# mini45 cell LEF. Generated by gen_mini45.py; do not edit.
VERSION 5.8 ;
BUSBITCHARS "[]" ;
DIVIDERCHAR "/" ;

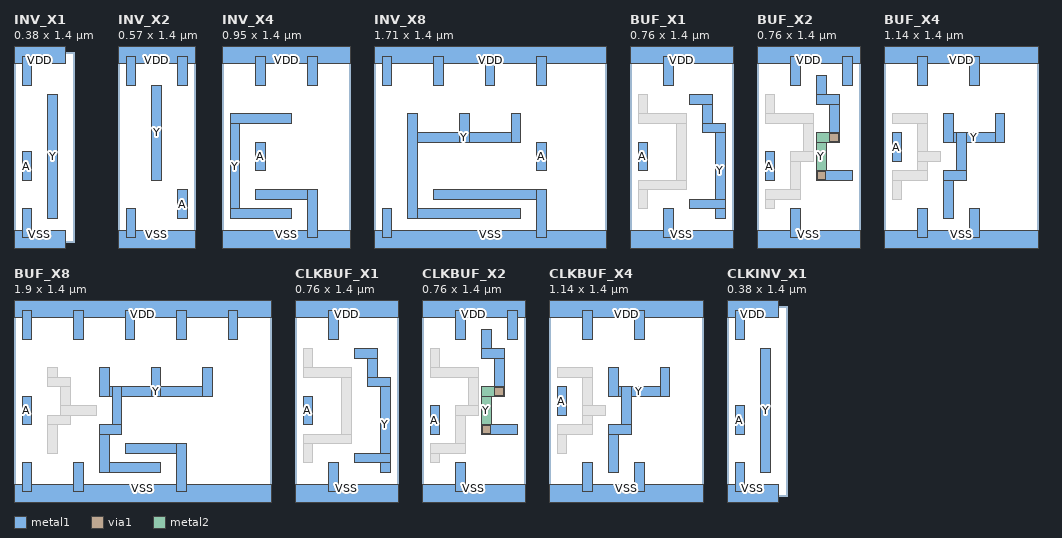
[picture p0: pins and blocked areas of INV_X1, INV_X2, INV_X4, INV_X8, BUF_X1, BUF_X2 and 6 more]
MACRO INV_X1
  CLASS CORE ;
  ORIGIN 0 0 ;
  FOREIGN INV_X1 0 0 ;
  SIZE 0.38 BY 1.40 ;
  SYMMETRY X Y ;
  SITE core ;
  PIN A
    DIRECTION INPUT ;
    USE SIGNAL ;
    PORT
      LAYER metal1 ;
        RECT 0.0600 0.4550 0.1300 0.6650 ;
    END
  END A
  PIN Y
    DIRECTION OUTPUT ;
    USE SIGNAL ;
    PORT
      LAYER metal1 ;
        RECT 0.2500 0.1750 0.3200 1.0850 ;
    END
  END Y
  PIN VDD
    DIRECTION INOUT ;
    USE POWER ;
    SHAPE ABUTMENT ;
    PORT
      LAYER metal1 ;
        RECT 0.0000 1.3150 0.3800 1.4850 ;
        RECT 0.0600 1.1550 0.1300 1.3650 ;
    END
  END VDD
  PIN VSS
    DIRECTION INOUT ;
    USE GROUND ;
    SHAPE ABUTMENT ;
    PORT
      LAYER metal1 ;
        RECT 0.0000 -0.0850 0.3800 0.0850 ;
        RECT 0.0600 0.0350 0.1300 0.2450 ;
    END
  END VSS
END INV_X1

MACRO INV_X2
  CLASS CORE ;
  ORIGIN 0 0 ;
  FOREIGN INV_X2 0 0 ;
  SIZE 0.57 BY 1.40 ;
  SYMMETRY X Y ;
  SITE core ;
  PIN A
    DIRECTION INPUT ;
    USE SIGNAL ;
    PORT
      LAYER metal1 ;
        RECT 0.4400 0.1750 0.5100 0.3850 ;
    END
  END A
  PIN Y
    DIRECTION OUTPUT ;
    USE SIGNAL ;
    PORT
      LAYER metal1 ;
        RECT 0.2500 0.4550 0.3200 1.1550 ;
    END
  END Y
  PIN VDD
    DIRECTION INOUT ;
    USE POWER ;
    SHAPE ABUTMENT ;
    PORT
      LAYER metal1 ;
        RECT 0.0000 1.3150 0.5700 1.4850 ;
        RECT 0.0600 1.1550 0.1300 1.3650 ;
        RECT 0.4400 1.1550 0.5100 1.3650 ;
    END
  END VDD
  PIN VSS
    DIRECTION INOUT ;
    USE GROUND ;
    SHAPE ABUTMENT ;
    PORT
      LAYER metal1 ;
        RECT 0.0000 -0.0850 0.5700 0.0850 ;
        RECT 0.0600 0.0350 0.1300 0.2450 ;
    END
  END VSS
END INV_X2

MACRO INV_X4
  CLASS CORE ;
  ORIGIN 0 0 ;
  FOREIGN INV_X4 0 0 ;
  SIZE 0.95 BY 1.40 ;
  SYMMETRY X Y ;
  SITE core ;
  PIN A
    DIRECTION INPUT ;
    USE SIGNAL ;
    PORT
      LAYER metal1 ;
        RECT 0.2500 0.5250 0.3200 0.7350 ;
    END
  END A
  PIN Y
    DIRECTION OUTPUT ;
    USE SIGNAL ;
    PORT
      LAYER metal1 ;
        RECT 0.0600 0.1750 0.1300 0.9450 ;
        RECT 0.0600 0.1750 0.5100 0.2450 ;
        RECT 0.0600 0.8750 0.5100 0.9450 ;
    END
  END Y
  PIN VDD
    DIRECTION INOUT ;
    USE POWER ;
    SHAPE ABUTMENT ;
    PORT
      LAYER metal1 ;
        RECT 0.0000 1.3150 0.9500 1.4850 ;
        RECT 0.2500 1.1550 0.3200 1.3650 ;
        RECT 0.6300 1.1550 0.7000 1.3650 ;
    END
  END VDD
  PIN VSS
    DIRECTION INOUT ;
    USE GROUND ;
    SHAPE ABUTMENT ;
    PORT
      LAYER metal1 ;
        RECT 0.0000 -0.0850 0.9500 0.0850 ;
        RECT 0.6300 0.0350 0.7000 0.3850 ;
        RECT 0.2500 0.3150 0.7000 0.3850 ;
    END
  END VSS
END INV_X4

MACRO INV_X8
  CLASS CORE ;
  ORIGIN 0 0 ;
  FOREIGN INV_X8 0 0 ;
  SIZE 1.71 BY 1.40 ;
  SYMMETRY X Y ;
  SITE core ;
  PIN A
    DIRECTION INPUT ;
    USE SIGNAL ;
    PORT
      LAYER metal1 ;
        RECT 1.2000 0.5250 1.2700 0.7350 ;
    END
  END A
  PIN Y
    DIRECTION OUTPUT ;
    USE SIGNAL ;
    PORT
      LAYER metal1 ;
        RECT 0.2500 0.1750 0.3200 0.9450 ;
        RECT 0.6300 0.7350 0.7000 0.9450 ;
        RECT 1.0100 0.7350 1.0800 0.9450 ;
        RECT 0.2500 0.1750 1.0800 0.2450 ;
        RECT 0.2500 0.7350 1.0800 0.8050 ;
    END
  END Y
  PIN VDD
    DIRECTION INOUT ;
    USE POWER ;
    SHAPE ABUTMENT ;
    PORT
      LAYER metal1 ;
        RECT 0.0000 1.3150 1.7100 1.4850 ;
        RECT 0.0600 1.1550 0.1300 1.3650 ;
        RECT 0.4400 1.1550 0.5100 1.3650 ;
        RECT 0.8200 1.1550 0.8900 1.3650 ;
        RECT 1.2000 1.1550 1.2700 1.3650 ;
    END
  END VDD
  PIN VSS
    DIRECTION INOUT ;
    USE GROUND ;
    SHAPE ABUTMENT ;
    PORT
      LAYER metal1 ;
        RECT 0.0000 -0.0850 1.7100 0.0850 ;
        RECT 0.0600 0.0350 0.1300 0.2450 ;
        RECT 1.2000 0.0350 1.2700 0.3850 ;
        RECT 0.4400 0.3150 1.2700 0.3850 ;
    END
  END VSS
END INV_X8

MACRO BUF_X1
  CLASS CORE ;
  ORIGIN 0 0 ;
  FOREIGN BUF_X1 0 0 ;
  SIZE 0.76 BY 1.40 ;
  SYMMETRY X Y ;
  SITE core ;
  PIN A
    DIRECTION INPUT ;
    USE SIGNAL ;
    PORT
      LAYER metal1 ;
        RECT 0.0600 0.5250 0.1300 0.7350 ;
    END
  END A
  PIN Y
    DIRECTION OUTPUT ;
    USE SIGNAL ;
    PORT
      LAYER metal1 ;
        RECT 0.5350 0.8050 0.6050 1.0850 ;
        RECT 0.6300 0.1750 0.7000 0.8750 ;
        RECT 0.4400 0.2450 0.7000 0.3150 ;
        RECT 0.5350 0.8050 0.7000 0.8750 ;
        RECT 0.4400 1.0150 0.6050 1.0850 ;
    END
  END Y
  PIN VDD
    DIRECTION INOUT ;
    USE POWER ;
    SHAPE ABUTMENT ;
    PORT
      LAYER metal1 ;
        RECT 0.0000 1.3150 0.7600 1.4850 ;
        RECT 0.2500 1.1550 0.3200 1.3650 ;
    END
  END VDD
  PIN VSS
    DIRECTION INOUT ;
    USE GROUND ;
    SHAPE ABUTMENT ;
    PORT
      LAYER metal1 ;
        RECT 0.0000 -0.0850 0.7600 0.0850 ;
        RECT 0.2500 0.0350 0.3200 0.2450 ;
    END
  END VSS
  OBS
    LAYER metal1 ;
      RECT 0.0600 0.2450 0.1300 0.4550 ;
      RECT 0.0600 0.8750 0.1300 1.0850 ;
      RECT 0.3450 0.3850 0.4150 0.9450 ;
      RECT 0.0600 0.3850 0.4150 0.4550 ;
      RECT 0.0600 0.8750 0.4150 0.9450 ;
  END
END BUF_X1

MACRO BUF_X2
  CLASS CORE ;
  ORIGIN 0 0 ;
  FOREIGN BUF_X2 0 0 ;
  SIZE 0.76 BY 1.40 ;
  SYMMETRY X Y ;
  SITE core ;
  PIN A
    DIRECTION INPUT ;
    USE SIGNAL ;
    PORT
      LAYER metal1 ;
        RECT 0.0600 0.4550 0.1300 0.6650 ;
    END
  END A
  PIN Y
    DIRECTION OUTPUT ;
    USE SIGNAL ;
    PORT
      LAYER metal1 ;
        RECT 0.4400 1.0150 0.5100 1.2250 ;
        RECT 0.5350 0.7350 0.6050 1.0850 ;
        RECT 0.4400 0.4550 0.7000 0.5250 ;
        RECT 0.4400 1.0150 0.6050 1.0850 ;
      LAYER via1 ;
        RECT 0.4425 0.4575 0.5075 0.5225 ;
        RECT 0.5375 0.7375 0.6025 0.8025 ;
      LAYER metal2 ;
        RECT 0.4400 0.4550 0.5100 0.8050 ;
        RECT 0.4400 0.7350 0.6050 0.8050 ;
    END
  END Y
  PIN VDD
    DIRECTION INOUT ;
    USE POWER ;
    SHAPE ABUTMENT ;
    PORT
      LAYER metal1 ;
        RECT 0.0000 1.3150 0.7600 1.4850 ;
        RECT 0.2500 1.1550 0.3200 1.3650 ;
        RECT 0.6300 1.1550 0.7000 1.3650 ;
    END
  END VDD
  PIN VSS
    DIRECTION INOUT ;
    USE GROUND ;
    SHAPE ABUTMENT ;
    PORT
      LAYER metal1 ;
        RECT 0.0000 -0.0850 0.7600 0.0850 ;
        RECT 0.2500 0.0350 0.3200 0.2450 ;
    END
  END VSS
  OBS
    LAYER metal1 ;
      RECT 0.0600 0.2450 0.1300 0.3850 ;
      RECT 0.0600 0.8750 0.1300 1.0850 ;
      RECT 0.2500 0.3150 0.3200 0.6650 ;
      RECT 0.3450 0.5950 0.4150 0.9450 ;
      RECT 0.0600 0.3150 0.3200 0.3850 ;
      RECT 0.2500 0.5950 0.4150 0.6650 ;
      RECT 0.0600 0.8750 0.4150 0.9450 ;
  END
END BUF_X2

MACRO BUF_X4
  CLASS CORE ;
  ORIGIN 0 0 ;
  FOREIGN BUF_X4 0 0 ;
  SIZE 1.14 BY 1.40 ;
  SYMMETRY X Y ;
  SITE core ;
  PIN A
    DIRECTION INPUT ;
    USE SIGNAL ;
    PORT
      LAYER metal1 ;
        RECT 0.0600 0.5950 0.1300 0.8050 ;
    END
  END A
  PIN Y
    DIRECTION OUTPUT ;
    USE SIGNAL ;
    PORT
      LAYER metal1 ;
        RECT 0.4400 0.1750 0.5100 0.5250 ;
        RECT 0.4400 0.7350 0.5100 0.9450 ;
        RECT 0.5350 0.4550 0.6050 0.8050 ;
        RECT 0.8200 0.7350 0.8900 0.9450 ;
        RECT 0.4400 0.4550 0.6050 0.5250 ;
        RECT 0.4400 0.7350 0.8900 0.8050 ;
    END
  END Y
  PIN VDD
    DIRECTION INOUT ;
    USE POWER ;
    SHAPE ABUTMENT ;
    PORT
      LAYER metal1 ;
        RECT 0.0000 1.3150 1.1400 1.4850 ;
        RECT 0.2500 1.1550 0.3200 1.3650 ;
        RECT 0.6300 1.1550 0.7000 1.3650 ;
    END
  END VDD
  PIN VSS
    DIRECTION INOUT ;
    USE GROUND ;
    SHAPE ABUTMENT ;
    PORT
      LAYER metal1 ;
        RECT 0.0000 -0.0850 1.1400 0.0850 ;
        RECT 0.2500 0.0350 0.3200 0.2450 ;
        RECT 0.6300 0.0350 0.7000 0.2450 ;
    END
  END VSS
  OBS
    LAYER metal1 ;
      RECT 0.0600 0.3150 0.1300 0.5250 ;
      RECT 0.2500 0.4550 0.3200 0.9450 ;
      RECT 0.0600 0.4550 0.3200 0.5250 ;
      RECT 0.2500 0.5950 0.4150 0.6650 ;
      RECT 0.0600 0.8750 0.3200 0.9450 ;
  END
END BUF_X4

MACRO BUF_X8
  CLASS CORE ;
  ORIGIN 0 0 ;
  FOREIGN BUF_X8 0 0 ;
  SIZE 1.90 BY 1.40 ;
  SYMMETRY X Y ;
  SITE core ;
  PIN A
    DIRECTION INPUT ;
    USE SIGNAL ;
    PORT
      LAYER metal1 ;
        RECT 0.0600 0.5250 0.1300 0.7350 ;
    END
  END A
  PIN Y
    DIRECTION OUTPUT ;
    USE SIGNAL ;
    PORT
      LAYER metal1 ;
        RECT 0.6300 0.1750 0.7000 0.5250 ;
        RECT 0.6300 0.7350 0.7000 0.9450 ;
        RECT 0.7250 0.4550 0.7950 0.8050 ;
        RECT 1.0100 0.7350 1.0800 0.9450 ;
        RECT 1.3900 0.7350 1.4600 0.9450 ;
        RECT 0.6300 0.1750 1.0800 0.2450 ;
        RECT 0.6300 0.4550 0.7950 0.5250 ;
        RECT 0.6300 0.7350 1.4600 0.8050 ;
    END
  END Y
  PIN VDD
    DIRECTION INOUT ;
    USE POWER ;
    SHAPE ABUTMENT ;
    PORT
      LAYER metal1 ;
        RECT 0.0000 1.3150 1.9000 1.4850 ;
        RECT 0.0600 1.1550 0.1300 1.3650 ;
        RECT 0.4400 1.1550 0.5100 1.3650 ;
        RECT 0.8200 1.1550 0.8900 1.3650 ;
        RECT 1.2000 1.1550 1.2700 1.3650 ;
        RECT 1.5800 1.1550 1.6500 1.3650 ;
    END
  END VDD
  PIN VSS
    DIRECTION INOUT ;
    USE GROUND ;
    SHAPE ABUTMENT ;
    PORT
      LAYER metal1 ;
        RECT 0.0000 -0.0850 1.9000 0.0850 ;
        RECT 0.0600 0.0350 0.1300 0.2450 ;
        RECT 0.4400 0.0350 0.5100 0.2450 ;
        RECT 1.2000 0.0350 1.2700 0.3850 ;
        RECT 0.8200 0.3150 1.2700 0.3850 ;
    END
  END VSS
  OBS
    LAYER metal1 ;
      RECT 0.2500 0.3150 0.3200 0.5950 ;
      RECT 0.2500 0.8050 0.3200 0.9450 ;
      RECT 0.3450 0.5250 0.4150 0.8750 ;
      RECT 0.2500 0.5250 0.4150 0.5950 ;
      RECT 0.3450 0.5950 0.6050 0.6650 ;
      RECT 0.2500 0.8050 0.4150 0.8750 ;
  END
END BUF_X8

MACRO CLKBUF_X1
  CLASS CORE ;
  ORIGIN 0 0 ;
  FOREIGN CLKBUF_X1 0 0 ;
  SIZE 0.76 BY 1.40 ;
  SYMMETRY X Y ;
  SITE core ;
  PIN A
    DIRECTION INPUT ;
    USE SIGNAL ;
    PORT
      LAYER metal1 ;
        RECT 0.0600 0.5250 0.1300 0.7350 ;
    END
  END A
  PIN Y
    DIRECTION OUTPUT ;
    USE SIGNAL ;
    PORT
      LAYER metal1 ;
        RECT 0.5350 0.8050 0.6050 1.0850 ;
        RECT 0.6300 0.1750 0.7000 0.8750 ;
        RECT 0.4400 0.2450 0.7000 0.3150 ;
        RECT 0.5350 0.8050 0.7000 0.8750 ;
        RECT 0.4400 1.0150 0.6050 1.0850 ;
    END
  END Y
  PIN VDD
    DIRECTION INOUT ;
    USE POWER ;
    SHAPE ABUTMENT ;
    PORT
      LAYER metal1 ;
        RECT 0.0000 1.3150 0.7600 1.4850 ;
        RECT 0.2500 1.1550 0.3200 1.3650 ;
    END
  END VDD
  PIN VSS
    DIRECTION INOUT ;
    USE GROUND ;
    SHAPE ABUTMENT ;
    PORT
      LAYER metal1 ;
        RECT 0.0000 -0.0850 0.7600 0.0850 ;
        RECT 0.2500 0.0350 0.3200 0.2450 ;
    END
  END VSS
  OBS
    LAYER metal1 ;
      RECT 0.0600 0.2450 0.1300 0.4550 ;
      RECT 0.0600 0.8750 0.1300 1.0850 ;
      RECT 0.3450 0.3850 0.4150 0.9450 ;
      RECT 0.0600 0.3850 0.4150 0.4550 ;
      RECT 0.0600 0.8750 0.4150 0.9450 ;
  END
END CLKBUF_X1

MACRO CLKBUF_X2
  CLASS CORE ;
  ORIGIN 0 0 ;
  FOREIGN CLKBUF_X2 0 0 ;
  SIZE 0.76 BY 1.40 ;
  SYMMETRY X Y ;
  SITE core ;
  PIN A
    DIRECTION INPUT ;
    USE SIGNAL ;
    PORT
      LAYER metal1 ;
        RECT 0.0600 0.4550 0.1300 0.6650 ;
    END
  END A
  PIN Y
    DIRECTION OUTPUT ;
    USE SIGNAL ;
    PORT
      LAYER metal1 ;
        RECT 0.4400 1.0150 0.5100 1.2250 ;
        RECT 0.5350 0.7350 0.6050 1.0850 ;
        RECT 0.4400 0.4550 0.7000 0.5250 ;
        RECT 0.4400 1.0150 0.6050 1.0850 ;
      LAYER via1 ;
        RECT 0.4425 0.4575 0.5075 0.5225 ;
        RECT 0.5375 0.7375 0.6025 0.8025 ;
      LAYER metal2 ;
        RECT 0.4400 0.4550 0.5100 0.8050 ;
        RECT 0.4400 0.7350 0.6050 0.8050 ;
    END
  END Y
  PIN VDD
    DIRECTION INOUT ;
    USE POWER ;
    SHAPE ABUTMENT ;
    PORT
      LAYER metal1 ;
        RECT 0.0000 1.3150 0.7600 1.4850 ;
        RECT 0.2500 1.1550 0.3200 1.3650 ;
        RECT 0.6300 1.1550 0.7000 1.3650 ;
    END
  END VDD
  PIN VSS
    DIRECTION INOUT ;
    USE GROUND ;
    SHAPE ABUTMENT ;
    PORT
      LAYER metal1 ;
        RECT 0.0000 -0.0850 0.7600 0.0850 ;
        RECT 0.2500 0.0350 0.3200 0.2450 ;
    END
  END VSS
  OBS
    LAYER metal1 ;
      RECT 0.0600 0.2450 0.1300 0.3850 ;
      RECT 0.0600 0.8750 0.1300 1.0850 ;
      RECT 0.2500 0.3150 0.3200 0.6650 ;
      RECT 0.3450 0.5950 0.4150 0.9450 ;
      RECT 0.0600 0.3150 0.3200 0.3850 ;
      RECT 0.2500 0.5950 0.4150 0.6650 ;
      RECT 0.0600 0.8750 0.4150 0.9450 ;
  END
END CLKBUF_X2

MACRO CLKBUF_X4
  CLASS CORE ;
  ORIGIN 0 0 ;
  FOREIGN CLKBUF_X4 0 0 ;
  SIZE 1.14 BY 1.40 ;
  SYMMETRY X Y ;
  SITE core ;
  PIN A
    DIRECTION INPUT ;
    USE SIGNAL ;
    PORT
      LAYER metal1 ;
        RECT 0.0600 0.5950 0.1300 0.8050 ;
    END
  END A
  PIN Y
    DIRECTION OUTPUT ;
    USE SIGNAL ;
    PORT
      LAYER metal1 ;
        RECT 0.4400 0.1750 0.5100 0.5250 ;
        RECT 0.4400 0.7350 0.5100 0.9450 ;
        RECT 0.5350 0.4550 0.6050 0.8050 ;
        RECT 0.8200 0.7350 0.8900 0.9450 ;
        RECT 0.4400 0.4550 0.6050 0.5250 ;
        RECT 0.4400 0.7350 0.8900 0.8050 ;
    END
  END Y
  PIN VDD
    DIRECTION INOUT ;
    USE POWER ;
    SHAPE ABUTMENT ;
    PORT
      LAYER metal1 ;
        RECT 0.0000 1.3150 1.1400 1.4850 ;
        RECT 0.2500 1.1550 0.3200 1.3650 ;
        RECT 0.6300 1.1550 0.7000 1.3650 ;
    END
  END VDD
  PIN VSS
    DIRECTION INOUT ;
    USE GROUND ;
    SHAPE ABUTMENT ;
    PORT
      LAYER metal1 ;
        RECT 0.0000 -0.0850 1.1400 0.0850 ;
        RECT 0.2500 0.0350 0.3200 0.2450 ;
        RECT 0.6300 0.0350 0.7000 0.2450 ;
    END
  END VSS
  OBS
    LAYER metal1 ;
      RECT 0.0600 0.3150 0.1300 0.5250 ;
      RECT 0.2500 0.4550 0.3200 0.9450 ;
      RECT 0.0600 0.4550 0.3200 0.5250 ;
      RECT 0.2500 0.5950 0.4150 0.6650 ;
      RECT 0.0600 0.8750 0.3200 0.9450 ;
  END
END CLKBUF_X4

MACRO CLKINV_X1
  CLASS CORE ;
  ORIGIN 0 0 ;
  FOREIGN CLKINV_X1 0 0 ;
  SIZE 0.38 BY 1.40 ;
  SYMMETRY X Y ;
  SITE core ;
  PIN A
    DIRECTION INPUT ;
    USE SIGNAL ;
    PORT
      LAYER metal1 ;
        RECT 0.0600 0.4550 0.1300 0.6650 ;
    END
  END A
  PIN Y
    DIRECTION OUTPUT ;
    USE SIGNAL ;
    PORT
      LAYER metal1 ;
        RECT 0.2500 0.1750 0.3200 1.0850 ;
    END
  END Y
  PIN VDD
    DIRECTION INOUT ;
    USE POWER ;
    SHAPE ABUTMENT ;
    PORT
      LAYER metal1 ;
        RECT 0.0000 1.3150 0.3800 1.4850 ;
        RECT 0.0600 1.1550 0.1300 1.3650 ;
    END
  END VDD
  PIN VSS
    DIRECTION INOUT ;
    USE GROUND ;
    SHAPE ABUTMENT ;
    PORT
      LAYER metal1 ;
        RECT 0.0000 -0.0850 0.3800 0.0850 ;
        RECT 0.0600 0.0350 0.1300 0.2450 ;
    END
  END VSS
END CLKINV_X1

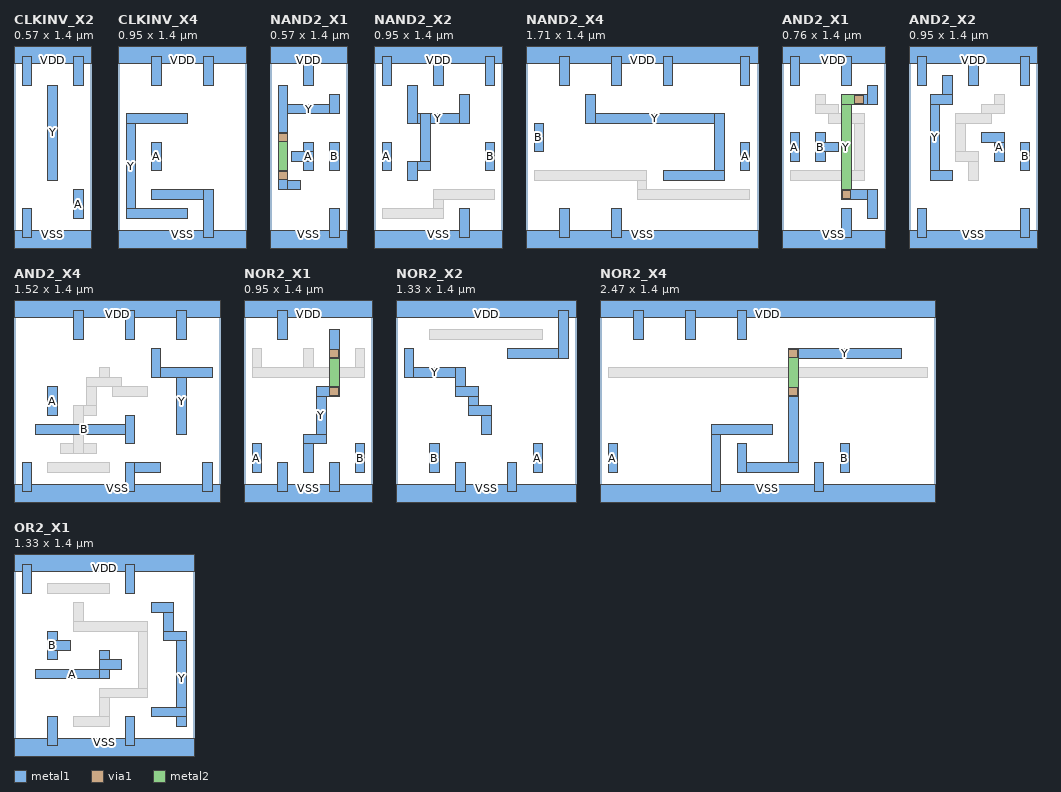
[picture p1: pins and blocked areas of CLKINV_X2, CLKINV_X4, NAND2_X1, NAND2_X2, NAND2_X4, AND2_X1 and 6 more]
MACRO CLKINV_X2
  CLASS CORE ;
  ORIGIN 0 0 ;
  FOREIGN CLKINV_X2 0 0 ;
  SIZE 0.57 BY 1.40 ;
  SYMMETRY X Y ;
  SITE core ;
  PIN A
    DIRECTION INPUT ;
    USE SIGNAL ;
    PORT
      LAYER metal1 ;
        RECT 0.4400 0.1750 0.5100 0.3850 ;
    END
  END A
  PIN Y
    DIRECTION OUTPUT ;
    USE SIGNAL ;
    PORT
      LAYER metal1 ;
        RECT 0.2500 0.4550 0.3200 1.1550 ;
    END
  END Y
  PIN VDD
    DIRECTION INOUT ;
    USE POWER ;
    SHAPE ABUTMENT ;
    PORT
      LAYER metal1 ;
        RECT 0.0000 1.3150 0.5700 1.4850 ;
        RECT 0.0600 1.1550 0.1300 1.3650 ;
        RECT 0.4400 1.1550 0.5100 1.3650 ;
    END
  END VDD
  PIN VSS
    DIRECTION INOUT ;
    USE GROUND ;
    SHAPE ABUTMENT ;
    PORT
      LAYER metal1 ;
        RECT 0.0000 -0.0850 0.5700 0.0850 ;
        RECT 0.0600 0.0350 0.1300 0.2450 ;
    END
  END VSS
END CLKINV_X2

MACRO CLKINV_X4
  CLASS CORE ;
  ORIGIN 0 0 ;
  FOREIGN CLKINV_X4 0 0 ;
  SIZE 0.95 BY 1.40 ;
  SYMMETRY X Y ;
  SITE core ;
  PIN A
    DIRECTION INPUT ;
    USE SIGNAL ;
    PORT
      LAYER metal1 ;
        RECT 0.2500 0.5250 0.3200 0.7350 ;
    END
  END A
  PIN Y
    DIRECTION OUTPUT ;
    USE SIGNAL ;
    PORT
      LAYER metal1 ;
        RECT 0.0600 0.1750 0.1300 0.9450 ;
        RECT 0.0600 0.1750 0.5100 0.2450 ;
        RECT 0.0600 0.8750 0.5100 0.9450 ;
    END
  END Y
  PIN VDD
    DIRECTION INOUT ;
    USE POWER ;
    SHAPE ABUTMENT ;
    PORT
      LAYER metal1 ;
        RECT 0.0000 1.3150 0.9500 1.4850 ;
        RECT 0.2500 1.1550 0.3200 1.3650 ;
        RECT 0.6300 1.1550 0.7000 1.3650 ;
    END
  END VDD
  PIN VSS
    DIRECTION INOUT ;
    USE GROUND ;
    SHAPE ABUTMENT ;
    PORT
      LAYER metal1 ;
        RECT 0.0000 -0.0850 0.9500 0.0850 ;
        RECT 0.6300 0.0350 0.7000 0.3850 ;
        RECT 0.2500 0.3150 0.7000 0.3850 ;
    END
  END VSS
END CLKINV_X4

MACRO NAND2_X1
  CLASS CORE ;
  ORIGIN 0 0 ;
  FOREIGN NAND2_X1 0 0 ;
  SIZE 0.57 BY 1.40 ;
  SYMMETRY X Y ;
  SITE core ;
  PIN A
    DIRECTION INPUT ;
    USE SIGNAL ;
    PORT
      LAYER metal1 ;
        RECT 0.2500 0.5250 0.3200 0.7350 ;
        RECT 0.1550 0.5950 0.3200 0.6650 ;
    END
  END A
  PIN B
    DIRECTION INPUT ;
    USE SIGNAL ;
    PORT
      LAYER metal1 ;
        RECT 0.4400 0.5250 0.5100 0.7350 ;
    END
  END B
  PIN Y
    DIRECTION OUTPUT ;
    USE SIGNAL ;
    PORT
      LAYER metal1 ;
        RECT 0.0600 0.3850 0.1300 0.5250 ;
        RECT 0.0600 0.7350 0.1300 1.1550 ;
        RECT 0.4400 0.9450 0.5100 1.0850 ;
        RECT 0.0600 0.3850 0.2250 0.4550 ;
        RECT 0.0600 0.9450 0.5100 1.0150 ;
      LAYER via1 ;
        RECT 0.0625 0.4575 0.1275 0.5225 ;
        RECT 0.0625 0.7375 0.1275 0.8025 ;
      LAYER metal2 ;
        RECT 0.0600 0.4550 0.1300 0.8050 ;
    END
  END Y
  PIN VDD
    DIRECTION INOUT ;
    USE POWER ;
    SHAPE ABUTMENT ;
    PORT
      LAYER metal1 ;
        RECT 0.0000 1.3150 0.5700 1.4850 ;
        RECT 0.2500 1.1550 0.3200 1.3650 ;
    END
  END VDD
  PIN VSS
    DIRECTION INOUT ;
    USE GROUND ;
    SHAPE ABUTMENT ;
    PORT
      LAYER metal1 ;
        RECT 0.0000 -0.0850 0.5700 0.0850 ;
        RECT 0.4400 0.0350 0.5100 0.2450 ;
    END
  END VSS
END NAND2_X1

MACRO NAND2_X2
  CLASS CORE ;
  ORIGIN 0 0 ;
  FOREIGN NAND2_X2 0 0 ;
  SIZE 0.95 BY 1.40 ;
  SYMMETRY X Y ;
  SITE core ;
  PIN A
    DIRECTION INPUT ;
    USE SIGNAL ;
    PORT
      LAYER metal1 ;
        RECT 0.0600 0.5250 0.1300 0.7350 ;
    END
  END A
  PIN B
    DIRECTION INPUT ;
    USE SIGNAL ;
    PORT
      LAYER metal1 ;
        RECT 0.8200 0.5250 0.8900 0.7350 ;
    END
  END B
  PIN Y
    DIRECTION OUTPUT ;
    USE SIGNAL ;
    PORT
      LAYER metal1 ;
        RECT 0.2500 0.4550 0.3200 0.5950 ;
        RECT 0.2500 0.8750 0.3200 1.1550 ;
        RECT 0.3450 0.5250 0.4150 0.9450 ;
        RECT 0.6300 0.8750 0.7000 1.0850 ;
        RECT 0.2500 0.5250 0.4150 0.5950 ;
        RECT 0.2500 0.8750 0.7000 0.9450 ;
    END
  END Y
  PIN VDD
    DIRECTION INOUT ;
    USE POWER ;
    SHAPE ABUTMENT ;
    PORT
      LAYER metal1 ;
        RECT 0.0000 1.3150 0.9500 1.4850 ;
        RECT 0.0600 1.1550 0.1300 1.3650 ;
        RECT 0.4400 1.1550 0.5100 1.3650 ;
        RECT 0.8200 1.1550 0.8900 1.3650 ;
    END
  END VDD
  PIN VSS
    DIRECTION INOUT ;
    USE GROUND ;
    SHAPE ABUTMENT ;
    PORT
      LAYER metal1 ;
        RECT 0.0000 -0.0850 0.9500 0.0850 ;
        RECT 0.6300 0.0350 0.7000 0.2450 ;
    END
  END VSS
  OBS
    LAYER metal1 ;
      RECT 0.4400 0.1750 0.5100 0.3850 ;
      RECT 0.0600 0.1750 0.5100 0.2450 ;
      RECT 0.4400 0.3150 0.8900 0.3850 ;
  END
END NAND2_X2

MACRO NAND2_X4
  CLASS CORE ;
  ORIGIN 0 0 ;
  FOREIGN NAND2_X4 0 0 ;
  SIZE 1.71 BY 1.40 ;
  SYMMETRY X Y ;
  SITE core ;
  PIN A
    DIRECTION INPUT ;
    USE SIGNAL ;
    PORT
      LAYER metal1 ;
        RECT 1.5800 0.5250 1.6500 0.7350 ;
    END
  END A
  PIN B
    DIRECTION INPUT ;
    USE SIGNAL ;
    PORT
      LAYER metal1 ;
        RECT 0.0600 0.6650 0.1300 0.8750 ;
    END
  END B
  PIN Y
    DIRECTION OUTPUT ;
    USE SIGNAL ;
    PORT
      LAYER metal1 ;
        RECT 0.4400 0.8750 0.5100 1.0850 ;
        RECT 1.3900 0.4550 1.4600 0.9450 ;
        RECT 1.0100 0.4550 1.4600 0.5250 ;
        RECT 0.4400 0.8750 1.4600 0.9450 ;
    END
  END Y
  PIN VDD
    DIRECTION INOUT ;
    USE POWER ;
    SHAPE ABUTMENT ;
    PORT
      LAYER metal1 ;
        RECT 0.0000 1.3150 1.7100 1.4850 ;
        RECT 0.2500 1.1550 0.3200 1.3650 ;
        RECT 0.6300 1.1550 0.7000 1.3650 ;
        RECT 1.0100 1.1550 1.0800 1.3650 ;
        RECT 1.5800 1.1550 1.6500 1.3650 ;
    END
  END VDD
  PIN VSS
    DIRECTION INOUT ;
    USE GROUND ;
    SHAPE ABUTMENT ;
    PORT
      LAYER metal1 ;
        RECT 0.0000 -0.0850 1.7100 0.0850 ;
        RECT 0.2500 0.0350 0.3200 0.2450 ;
        RECT 0.6300 0.0350 0.7000 0.2450 ;
    END
  END VSS
  OBS
    LAYER metal1 ;
      RECT 0.8200 0.3150 0.8900 0.5250 ;
      RECT 0.8200 0.3150 1.6500 0.3850 ;
      RECT 0.0600 0.4550 0.8900 0.5250 ;
  END
END NAND2_X4

MACRO AND2_X1
  CLASS CORE ;
  ORIGIN 0 0 ;
  FOREIGN AND2_X1 0 0 ;
  SIZE 0.76 BY 1.40 ;
  SYMMETRY X Y ;
  SITE core ;
  PIN A
    DIRECTION INPUT ;
    USE SIGNAL ;
    PORT
      LAYER metal1 ;
        RECT 0.0600 0.5950 0.1300 0.8050 ;
    END
  END A
  PIN B
    DIRECTION INPUT ;
    USE SIGNAL ;
    PORT
      LAYER metal1 ;
        RECT 0.2500 0.5950 0.3200 0.8050 ;
        RECT 0.2500 0.6650 0.4150 0.7350 ;
    END
  END B
  PIN Y
    DIRECTION OUTPUT ;
    USE SIGNAL ;
    PORT
      LAYER metal1 ;
        RECT 0.6300 0.1750 0.7000 0.3850 ;
        RECT 0.6300 1.0150 0.7000 1.1550 ;
        RECT 0.4400 0.3150 0.7000 0.3850 ;
        RECT 0.5350 1.0150 0.7000 1.0850 ;
      LAYER via1 ;
        RECT 0.4425 0.3175 0.5075 0.3825 ;
        RECT 0.5375 1.0175 0.6025 1.0825 ;
      LAYER metal2 ;
        RECT 0.4400 0.3150 0.5100 1.0850 ;
        RECT 0.4400 1.0150 0.7000 1.0850 ;
    END
  END Y
  PIN VDD
    DIRECTION INOUT ;
    USE POWER ;
    SHAPE ABUTMENT ;
    PORT
      LAYER metal1 ;
        RECT 0.0000 1.3150 0.7600 1.4850 ;
        RECT 0.0600 1.1550 0.1300 1.3650 ;
        RECT 0.4400 1.1550 0.5100 1.3650 ;
    END
  END VDD
  PIN VSS
    DIRECTION INOUT ;
    USE GROUND ;
    SHAPE ABUTMENT ;
    PORT
      LAYER metal1 ;
        RECT 0.0000 -0.0850 0.7600 0.0850 ;
        RECT 0.4400 0.0350 0.5100 0.2450 ;
    END
  END VSS
  OBS
    LAYER metal1 ;
      RECT 0.2500 0.9450 0.3200 1.0850 ;
      RECT 0.3450 0.8750 0.4150 1.0150 ;
      RECT 0.5350 0.4550 0.6050 0.9450 ;
      RECT 0.0600 0.4550 0.6050 0.5250 ;
      RECT 0.3450 0.8750 0.6050 0.9450 ;
      RECT 0.2500 0.9450 0.4150 1.0150 ;
  END
END AND2_X1

MACRO AND2_X2
  CLASS CORE ;
  ORIGIN 0 0 ;
  FOREIGN AND2_X2 0 0 ;
  SIZE 0.95 BY 1.40 ;
  SYMMETRY X Y ;
  SITE core ;
  PIN A
    DIRECTION INPUT ;
    USE SIGNAL ;
    PORT
      LAYER metal1 ;
        RECT 0.6300 0.5950 0.7000 0.8050 ;
        RECT 0.5350 0.7350 0.7000 0.8050 ;
    END
  END A
  PIN B
    DIRECTION INPUT ;
    USE SIGNAL ;
    PORT
      LAYER metal1 ;
        RECT 0.8200 0.5250 0.8900 0.7350 ;
    END
  END B
  PIN Y
    DIRECTION OUTPUT ;
    USE SIGNAL ;
    PORT
      LAYER metal1 ;
        RECT 0.1550 0.4550 0.2250 1.0850 ;
        RECT 0.2500 1.0150 0.3200 1.2250 ;
        RECT 0.1550 0.4550 0.3200 0.5250 ;
        RECT 0.1550 1.0150 0.3200 1.0850 ;
    END
  END Y
  PIN VDD
    DIRECTION INOUT ;
    USE POWER ;
    SHAPE ABUTMENT ;
    PORT
      LAYER metal1 ;
        RECT 0.0000 1.3150 0.9500 1.4850 ;
        RECT 0.0600 1.1550 0.1300 1.3650 ;
        RECT 0.4400 1.1550 0.5100 1.3650 ;
        RECT 0.8200 1.1550 0.8900 1.3650 ;
    END
  END VDD
  PIN VSS
    DIRECTION INOUT ;
    USE GROUND ;
    SHAPE ABUTMENT ;
    PORT
      LAYER metal1 ;
        RECT 0.0000 -0.0850 0.9500 0.0850 ;
        RECT 0.0600 0.0350 0.1300 0.2450 ;
        RECT 0.8200 0.0350 0.8900 0.2450 ;
    END
  END VSS
  OBS
    LAYER metal1 ;
      RECT 0.3450 0.5950 0.4150 0.9450 ;
      RECT 0.4400 0.4550 0.5100 0.6650 ;
      RECT 0.5350 0.8750 0.6050 1.0150 ;
      RECT 0.6300 0.9450 0.7000 1.0850 ;
      RECT 0.3450 0.5950 0.5100 0.6650 ;
      RECT 0.3450 0.8750 0.6050 0.9450 ;
      RECT 0.5350 0.9450 0.7000 1.0150 ;
  END
END AND2_X2

MACRO AND2_X4
  CLASS CORE ;
  ORIGIN 0 0 ;
  FOREIGN AND2_X4 0 0 ;
  SIZE 1.52 BY 1.40 ;
  SYMMETRY X Y ;
  SITE core ;
  PIN A
    DIRECTION INPUT ;
    USE SIGNAL ;
    PORT
      LAYER metal1 ;
        RECT 0.2500 0.5950 0.3200 0.8050 ;
    END
  END A
  PIN B
    DIRECTION INPUT ;
    USE SIGNAL ;
    PORT
      LAYER metal1 ;
        RECT 0.8200 0.3850 0.8900 0.5950 ;
        RECT 0.1550 0.4550 0.8900 0.5250 ;
    END
  END B
  PIN Y
    DIRECTION OUTPUT ;
    USE SIGNAL ;
    PORT
      LAYER metal1 ;
        RECT 1.0100 0.8750 1.0800 1.0850 ;
        RECT 1.2000 0.4550 1.2700 0.9450 ;
        RECT 1.0100 0.8750 1.4600 0.9450 ;
    END
  END Y
  PIN VDD
    DIRECTION INOUT ;
    USE POWER ;
    SHAPE ABUTMENT ;
    PORT
      LAYER metal1 ;
        RECT 0.0000 1.3150 1.5200 1.4850 ;
        RECT 0.4400 1.1550 0.5100 1.3650 ;
        RECT 0.8200 1.1550 0.8900 1.3650 ;
        RECT 1.2000 1.1550 1.2700 1.3650 ;
    END
  END VDD
  PIN VSS
    DIRECTION INOUT ;
    USE GROUND ;
    SHAPE ABUTMENT ;
    PORT
      LAYER metal1 ;
        RECT 0.0000 -0.0850 1.5200 0.0850 ;
        RECT 0.0600 0.0350 0.1300 0.2450 ;
        RECT 0.8200 0.0350 0.8900 0.2450 ;
        RECT 1.3900 0.0350 1.4600 0.2450 ;
        RECT 0.8200 0.1750 1.0800 0.2450 ;
    END
  END VSS
  OBS
    LAYER metal1 ;
      RECT 0.5350 0.5950 0.6050 0.8750 ;
      RECT 0.6300 0.8050 0.7000 0.9450 ;
      RECT 0.7250 0.7350 0.7950 0.8750 ;
      RECT 0.3450 0.3150 0.6050 0.3850 ;
      RECT 0.4400 0.5950 0.6050 0.6650 ;
      RECT 0.7250 0.7350 0.9850 0.8050 ;
      RECT 0.5350 0.8050 0.7950 0.8750 ;
      RECT 0.2500 0.1750 0.7000 0.2450 ;
    LAYER via1 ;
      RECT 0.4425 0.3175 0.5075 0.3825 ;
      RECT 0.4425 0.5975 0.5075 0.6625 ;
    LAYER metal2 ;
      RECT 0.4400 0.3150 0.5100 0.6650 ;
  END
END AND2_X4

MACRO NOR2_X1
  CLASS CORE ;
  ORIGIN 0 0 ;
  FOREIGN NOR2_X1 0 0 ;
  SIZE 0.95 BY 1.40 ;
  SYMMETRY X Y ;
  SITE core ;
  PIN A
    DIRECTION INPUT ;
    USE SIGNAL ;
    PORT
      LAYER metal1 ;
        RECT 0.0600 0.1750 0.1300 0.3850 ;
    END
  END A
  PIN B
    DIRECTION INPUT ;
    USE SIGNAL ;
    PORT
      LAYER metal1 ;
        RECT 0.8200 0.1750 0.8900 0.3850 ;
    END
  END B
  PIN Y
    DIRECTION OUTPUT ;
    USE SIGNAL ;
    PORT
      LAYER metal1 ;
        RECT 0.4400 0.1750 0.5100 0.4550 ;
        RECT 0.5350 0.3850 0.6050 0.8050 ;
        RECT 0.6300 1.0150 0.7000 1.2250 ;
        RECT 0.4400 0.3850 0.6050 0.4550 ;
        RECT 0.5350 0.7350 0.7000 0.8050 ;
      LAYER via1 ;
        RECT 0.6325 0.7375 0.6975 0.8025 ;
        RECT 0.6325 1.0175 0.6975 1.0825 ;
      LAYER metal2 ;
        RECT 0.6300 0.7350 0.7000 1.0850 ;
    END
  END Y
  PIN VDD
    DIRECTION INOUT ;
    USE POWER ;
    SHAPE ABUTMENT ;
    PORT
      LAYER metal1 ;
        RECT 0.0000 1.3150 0.9500 1.4850 ;
        RECT 0.2500 1.1550 0.3200 1.3650 ;
    END
  END VDD
  PIN VSS
    DIRECTION INOUT ;
    USE GROUND ;
    SHAPE ABUTMENT ;
    PORT
      LAYER metal1 ;
        RECT 0.0000 -0.0850 0.9500 0.0850 ;
        RECT 0.2500 0.0350 0.3200 0.2450 ;
        RECT 0.6300 0.0350 0.7000 0.2450 ;
    END
  END VSS
  OBS
    LAYER metal1 ;
      RECT 0.0600 0.8750 0.1300 1.0850 ;
      RECT 0.4400 0.8750 0.5100 1.0850 ;
      RECT 0.8200 0.8750 0.8900 1.0850 ;
      RECT 0.0600 0.8750 0.8900 0.9450 ;
  END
END NOR2_X1

MACRO NOR2_X2
  CLASS CORE ;
  ORIGIN 0 0 ;
  FOREIGN NOR2_X2 0 0 ;
  SIZE 1.33 BY 1.40 ;
  SYMMETRY X Y ;
  SITE core ;
  PIN A
    DIRECTION INPUT ;
    USE SIGNAL ;
    PORT
      LAYER metal1 ;
        RECT 1.0100 0.1750 1.0800 0.3850 ;
    END
  END A
  PIN B
    DIRECTION INPUT ;
    USE SIGNAL ;
    PORT
      LAYER metal1 ;
        RECT 0.2500 0.1750 0.3200 0.3850 ;
    END
  END B
  PIN Y
    DIRECTION OUTPUT ;
    USE SIGNAL ;
    PORT
      LAYER metal1 ;
        RECT 0.0600 0.8750 0.1300 1.0850 ;
        RECT 0.4400 0.7350 0.5100 0.9450 ;
        RECT 0.5350 0.5950 0.6050 0.8050 ;
        RECT 0.6300 0.4550 0.7000 0.6650 ;
        RECT 0.5350 0.5950 0.7000 0.6650 ;
        RECT 0.4400 0.7350 0.6050 0.8050 ;
        RECT 0.0600 0.8750 0.5100 0.9450 ;
    END
  END Y
  PIN VDD
    DIRECTION INOUT ;
    USE POWER ;
    SHAPE ABUTMENT ;
    PORT
      LAYER metal1 ;
        RECT 0.0000 1.3150 1.3300 1.4850 ;
        RECT 1.2000 1.0150 1.2700 1.3650 ;
        RECT 0.8200 1.0150 1.2700 1.0850 ;
    END
  END VDD
  PIN VSS
    DIRECTION INOUT ;
    USE GROUND ;
    SHAPE ABUTMENT ;
    PORT
      LAYER metal1 ;
        RECT 0.0000 -0.0850 1.3300 0.0850 ;
        RECT 0.4400 0.0350 0.5100 0.2450 ;
        RECT 0.8200 0.0350 0.8900 0.2450 ;
    END
  END VSS
  OBS
    LAYER metal1 ;
      RECT 0.2500 1.1550 1.0800 1.2250 ;
  END
END NOR2_X2

MACRO NOR2_X4
  CLASS CORE ;
  ORIGIN 0 0 ;
  FOREIGN NOR2_X4 0 0 ;
  SIZE 2.47 BY 1.40 ;
  SYMMETRY X Y ;
  SITE core ;
  PIN A
    DIRECTION INPUT ;
    USE SIGNAL ;
    PORT
      LAYER metal1 ;
        RECT 0.0600 0.1750 0.1300 0.3850 ;
    END
  END A
  PIN B
    DIRECTION INPUT ;
    USE SIGNAL ;
    PORT
      LAYER metal1 ;
        RECT 1.7700 0.1750 1.8400 0.3850 ;
    END
  END B
  PIN Y
    DIRECTION OUTPUT ;
    USE SIGNAL ;
    PORT
      LAYER metal1 ;
        RECT 1.0100 0.1750 1.0800 0.3850 ;
        RECT 1.3900 0.1750 1.4600 0.8050 ;
        RECT 1.0100 0.1750 1.4600 0.2450 ;
        RECT 1.3900 1.0150 2.2200 1.0850 ;
      LAYER via1 ;
        RECT 1.3925 0.7375 1.4575 0.8025 ;
        RECT 1.3925 1.0175 1.4575 1.0825 ;
      LAYER metal2 ;
        RECT 1.3900 0.7350 1.4600 1.0850 ;
    END
  END Y
  PIN VDD
    DIRECTION INOUT ;
    USE POWER ;
    SHAPE ABUTMENT ;
    PORT
      LAYER metal1 ;
        RECT 0.0000 1.3150 2.4700 1.4850 ;
        RECT 0.2500 1.1550 0.3200 1.3650 ;
        RECT 0.6300 1.1550 0.7000 1.3650 ;
        RECT 1.0100 1.1550 1.0800 1.3650 ;
    END
  END VDD
  PIN VSS
    DIRECTION INOUT ;
    USE GROUND ;
    SHAPE ABUTMENT ;
    PORT
      LAYER metal1 ;
        RECT 0.0000 -0.0850 2.4700 0.0850 ;
        RECT 0.8200 0.0350 0.8900 0.5250 ;
        RECT 1.5800 0.0350 1.6500 0.2450 ;
        RECT 0.8200 0.4550 1.2700 0.5250 ;
    END
  END VSS
  OBS
    LAYER metal1 ;
      RECT 0.0600 0.8750 2.4100 0.9450 ;
  END
END NOR2_X4

MACRO OR2_X1
  CLASS CORE ;
  ORIGIN 0 0 ;
  FOREIGN OR2_X1 0 0 ;
  SIZE 1.33 BY 1.40 ;
  SYMMETRY X Y ;
  SITE core ;
  PIN A
    DIRECTION INPUT ;
    USE SIGNAL ;
    PORT
      LAYER metal1 ;
        RECT 0.6300 0.5250 0.7000 0.7350 ;
        RECT 0.1550 0.5250 0.7000 0.5950 ;
        RECT 0.6300 0.5950 0.7950 0.6650 ;
    END
  END A
  PIN B
    DIRECTION INPUT ;
    USE SIGNAL ;
    PORT
      LAYER metal1 ;
        RECT 0.2500 0.6650 0.3200 0.8750 ;
        RECT 0.2500 0.7350 0.4150 0.8050 ;
    END
  END B
  PIN Y
    DIRECTION OUTPUT ;
    USE SIGNAL ;
    PORT
      LAYER metal1 ;
        RECT 1.1050 0.8050 1.1750 1.0850 ;
        RECT 1.2000 0.1750 1.2700 0.8750 ;
        RECT 1.0100 0.2450 1.2700 0.3150 ;
        RECT 1.1050 0.8050 1.2700 0.8750 ;
        RECT 1.0100 1.0150 1.1750 1.0850 ;
    END
  END Y
  PIN VDD
    DIRECTION INOUT ;
    USE POWER ;
    SHAPE ABUTMENT ;
    PORT
      LAYER metal1 ;
        RECT 0.0000 1.3150 1.3300 1.4850 ;
        RECT 0.0600 1.1550 0.1300 1.3650 ;
        RECT 0.8200 1.1550 0.8900 1.3650 ;
    END
  END VDD
  PIN VSS
    DIRECTION INOUT ;
    USE GROUND ;
    SHAPE ABUTMENT ;
    PORT
      LAYER metal1 ;
        RECT 0.0000 -0.0850 1.3300 0.0850 ;
        RECT 0.2500 0.0350 0.3200 0.2450 ;
        RECT 0.8200 0.0350 0.8900 0.2450 ;
    END
  END VSS
  OBS
    LAYER metal1 ;
      RECT 0.4400 0.8750 0.5100 1.0850 ;
      RECT 0.6300 0.1750 0.7000 0.4550 ;
      RECT 0.9150 0.3850 0.9850 0.9450 ;
      RECT 0.4400 0.1750 0.7000 0.2450 ;
      RECT 0.6300 0.3850 0.9850 0.4550 ;
      RECT 0.4400 0.8750 0.9850 0.9450 ;
      RECT 0.2500 1.1550 0.7000 1.2250 ;
  END
END OR2_X1

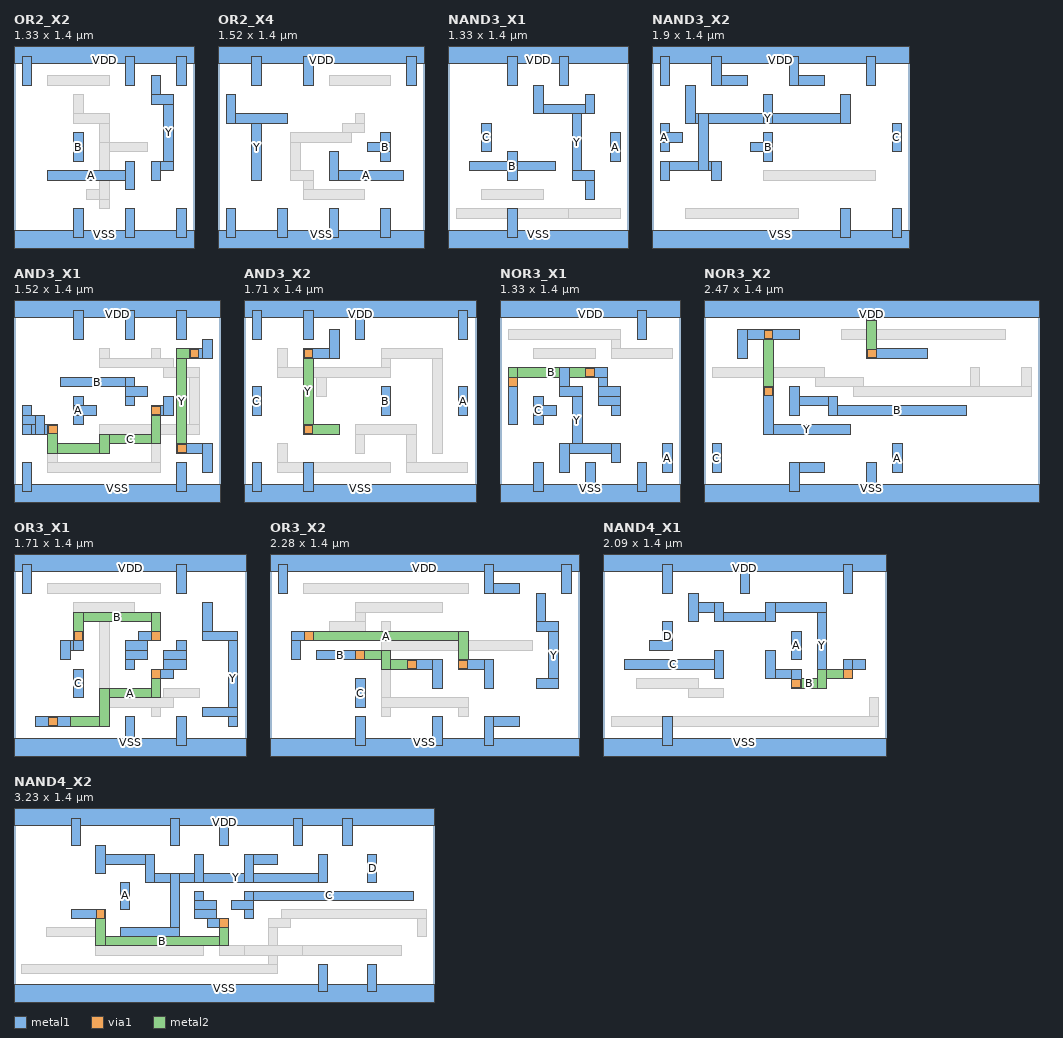
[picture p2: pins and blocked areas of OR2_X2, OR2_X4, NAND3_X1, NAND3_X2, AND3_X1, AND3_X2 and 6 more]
MACRO OR2_X2
  CLASS CORE ;
  ORIGIN 0 0 ;
  FOREIGN OR2_X2 0 0 ;
  SIZE 1.33 BY 1.40 ;
  SYMMETRY X Y ;
  SITE core ;
  PIN A
    DIRECTION INPUT ;
    USE SIGNAL ;
    PORT
      LAYER metal1 ;
        RECT 0.8200 0.3850 0.8900 0.5950 ;
        RECT 0.2500 0.4550 0.8900 0.5250 ;
    END
  END A
  PIN B
    DIRECTION INPUT ;
    USE SIGNAL ;
    PORT
      LAYER metal1 ;
        RECT 0.4400 0.5950 0.5100 0.8050 ;
    END
  END B
  PIN Y
    DIRECTION OUTPUT ;
    USE SIGNAL ;
    PORT
      LAYER metal1 ;
        RECT 1.0100 0.4550 1.0800 0.5950 ;
        RECT 1.0100 1.0150 1.0800 1.2250 ;
        RECT 1.1050 0.5250 1.1750 1.0850 ;
        RECT 1.0100 0.5250 1.1750 0.5950 ;
        RECT 1.0100 1.0150 1.1750 1.0850 ;
    END
  END Y
  PIN VDD
    DIRECTION INOUT ;
    USE POWER ;
    SHAPE ABUTMENT ;
    PORT
      LAYER metal1 ;
        RECT 0.0000 1.3150 1.3300 1.4850 ;
        RECT 0.0600 1.1550 0.1300 1.3650 ;
        RECT 0.8200 1.1550 0.8900 1.3650 ;
        RECT 1.2000 1.1550 1.2700 1.3650 ;
    END
  END VDD
  PIN VSS
    DIRECTION INOUT ;
    USE GROUND ;
    SHAPE ABUTMENT ;
    PORT
      LAYER metal1 ;
        RECT 0.0000 -0.0850 1.3300 0.0850 ;
        RECT 0.4400 0.0350 0.5100 0.2450 ;
        RECT 0.8200 0.0350 0.8900 0.2450 ;
        RECT 1.2000 0.0350 1.2700 0.2450 ;
    END
  END VSS
  OBS
    LAYER metal1 ;
      RECT 0.4400 0.8750 0.5100 1.0850 ;
      RECT 0.6300 0.2450 0.7000 0.3850 ;
      RECT 0.6300 0.6650 0.7000 0.9450 ;
      RECT 0.5350 0.3150 0.7000 0.3850 ;
      RECT 0.6300 0.6650 0.9850 0.7350 ;
      RECT 0.4400 0.8750 0.7000 0.9450 ;
      RECT 0.2500 1.1550 0.7000 1.2250 ;
    LAYER via1 ;
      RECT 0.6325 0.3175 0.6975 0.3825 ;
      RECT 0.6325 0.6675 0.6975 0.7325 ;
    LAYER metal2 ;
      RECT 0.6300 0.3150 0.7000 0.7350 ;
  END
END OR2_X2

MACRO OR2_X4
  CLASS CORE ;
  ORIGIN 0 0 ;
  FOREIGN OR2_X4 0 0 ;
  SIZE 1.52 BY 1.40 ;
  SYMMETRY X Y ;
  SITE core ;
  PIN A
    DIRECTION INPUT ;
    USE SIGNAL ;
    PORT
      LAYER metal1 ;
        RECT 0.8200 0.4550 0.8900 0.6650 ;
        RECT 0.8200 0.4550 1.3650 0.5250 ;
    END
  END A
  PIN B
    DIRECTION INPUT ;
    USE SIGNAL ;
    PORT
      LAYER metal1 ;
        RECT 1.2000 0.5950 1.2700 0.8050 ;
        RECT 1.1050 0.6650 1.2700 0.7350 ;
    END
  END B
  PIN Y
    DIRECTION OUTPUT ;
    USE SIGNAL ;
    PORT
      LAYER metal1 ;
        RECT 0.0600 0.8750 0.1300 1.0850 ;
        RECT 0.2500 0.4550 0.3200 0.9450 ;
        RECT 0.0600 0.8750 0.5100 0.9450 ;
    END
  END Y
  PIN VDD
    DIRECTION INOUT ;
    USE POWER ;
    SHAPE ABUTMENT ;
    PORT
      LAYER metal1 ;
        RECT 0.0000 1.3150 1.5200 1.4850 ;
        RECT 0.2500 1.1550 0.3200 1.3650 ;
        RECT 0.6300 1.1550 0.7000 1.3650 ;
        RECT 1.3900 1.1550 1.4600 1.3650 ;
    END
  END VDD
  PIN VSS
    DIRECTION INOUT ;
    USE GROUND ;
    SHAPE ABUTMENT ;
    PORT
      LAYER metal1 ;
        RECT 0.0000 -0.0850 1.5200 0.0850 ;
        RECT 0.0600 0.0350 0.1300 0.2450 ;
        RECT 0.4400 0.0350 0.5100 0.2450 ;
        RECT 0.8200 0.0350 0.8900 0.2450 ;
        RECT 1.2000 0.0350 1.2700 0.2450 ;
    END
  END VSS
  OBS
    LAYER metal1 ;
      RECT 0.5350 0.4550 0.6050 0.8050 ;
      RECT 0.6300 0.3150 0.7000 0.5250 ;
      RECT 0.9150 0.7350 0.9850 0.8750 ;
      RECT 1.0100 0.8050 1.0800 0.9450 ;
      RECT 0.6300 0.3150 1.0800 0.3850 ;
      RECT 0.5350 0.4550 0.7000 0.5250 ;
      RECT 0.5350 0.7350 0.9850 0.8050 ;
      RECT 0.9150 0.8050 1.0800 0.8750 ;
      RECT 0.8200 1.1550 1.2700 1.2250 ;
  END
END OR2_X4

MACRO NAND3_X1
  CLASS CORE ;
  ORIGIN 0 0 ;
  FOREIGN NAND3_X1 0 0 ;
  SIZE 1.33 BY 1.40 ;
  SYMMETRY X Y ;
  SITE core ;
  PIN A
    DIRECTION INPUT ;
    USE SIGNAL ;
    PORT
      LAYER metal1 ;
        RECT 1.2000 0.5950 1.2700 0.8050 ;
    END
  END A
  PIN B
    DIRECTION INPUT ;
    USE SIGNAL ;
    PORT
      LAYER metal1 ;
        RECT 0.4400 0.4550 0.5100 0.6650 ;
        RECT 0.1550 0.5250 0.7950 0.5950 ;
    END
  END B
  PIN C
    DIRECTION INPUT ;
    USE SIGNAL ;
    PORT
      LAYER metal1 ;
        RECT 0.2500 0.6650 0.3200 0.8750 ;
    END
  END C
  PIN Y
    DIRECTION OUTPUT ;
    USE SIGNAL ;
    PORT
      LAYER metal1 ;
        RECT 0.6300 0.9450 0.7000 1.1550 ;
        RECT 0.9150 0.4550 0.9850 1.0150 ;
        RECT 1.0100 0.3150 1.0800 0.5250 ;
        RECT 1.0100 0.9450 1.0800 1.0850 ;
        RECT 0.9150 0.4550 1.0800 0.5250 ;
        RECT 0.6300 0.9450 1.0800 1.0150 ;
    END
  END Y
  PIN VDD
    DIRECTION INOUT ;
    USE POWER ;
    SHAPE ABUTMENT ;
    PORT
      LAYER metal1 ;
        RECT 0.0000 1.3150 1.3300 1.4850 ;
        RECT 0.4400 1.1550 0.5100 1.3650 ;
        RECT 0.8200 1.1550 0.8900 1.3650 ;
    END
  END VDD
  PIN VSS
    DIRECTION INOUT ;
    USE GROUND ;
    SHAPE ABUTMENT ;
    PORT
      LAYER metal1 ;
        RECT 0.0000 -0.0850 1.3300 0.0850 ;
        RECT 0.4400 0.0350 0.5100 0.2450 ;
    END
  END VSS
  OBS
    LAYER metal1 ;
      RECT 0.0600 0.1750 0.3200 0.2450 ;
      RECT 0.8200 0.1750 1.2700 0.2450 ;
      RECT 0.2500 0.3150 0.7000 0.3850 ;
    LAYER via1 ;
      RECT 0.0625 0.1775 0.1275 0.2425 ;
      RECT 0.8225 0.1775 0.8875 0.2425 ;
    LAYER metal2 ;
      RECT 0.0600 0.1750 0.8900 0.2450 ;
  END
END NAND3_X1

MACRO NAND3_X2
  CLASS CORE ;
  ORIGIN 0 0 ;
  FOREIGN NAND3_X2 0 0 ;
  SIZE 1.90 BY 1.40 ;
  SYMMETRY X Y ;
  SITE core ;
  PIN A
    DIRECTION INPUT ;
    USE SIGNAL ;
    PORT
      LAYER metal1 ;
        RECT 0.0600 0.6650 0.1300 0.8750 ;
        RECT 0.0600 0.7350 0.2250 0.8050 ;
    END
  END A
  PIN B
    DIRECTION INPUT ;
    USE SIGNAL ;
    PORT
      LAYER metal1 ;
        RECT 0.8200 0.5950 0.8900 0.8050 ;
        RECT 0.7250 0.6650 0.8900 0.7350 ;
    END
  END B
  PIN C
    DIRECTION INPUT ;
    USE SIGNAL ;
    PORT
      LAYER metal1 ;
        RECT 1.7700 0.6650 1.8400 0.8750 ;
    END
  END C
  PIN Y
    DIRECTION OUTPUT ;
    USE SIGNAL ;
    PORT
      LAYER metal1 ;
        RECT 0.0600 0.4550 0.1300 0.5950 ;
        RECT 0.2500 0.8750 0.3200 1.1550 ;
        RECT 0.3450 0.5250 0.4150 0.9450 ;
        RECT 0.4400 0.4550 0.5100 0.5950 ;
        RECT 0.8200 0.8750 0.8900 1.0850 ;
        RECT 1.3900 0.8750 1.4600 1.0850 ;
        RECT 0.0600 0.5250 0.5100 0.5950 ;
        RECT 0.2500 0.8750 1.4600 0.9450 ;
    END
  END Y
  PIN VDD
    DIRECTION INOUT ;
    USE POWER ;
    SHAPE ABUTMENT ;
    PORT
      LAYER metal1 ;
        RECT 0.0000 1.3150 1.9000 1.4850 ;
        RECT 0.0600 1.1550 0.1300 1.3650 ;
        RECT 0.4400 1.1550 0.5100 1.3650 ;
        RECT 1.0100 1.1550 1.0800 1.3650 ;
        RECT 1.5800 1.1550 1.6500 1.3650 ;
        RECT 0.4400 1.1550 0.7000 1.2250 ;
        RECT 1.0100 1.1550 1.2700 1.2250 ;
    END
  END VDD
  PIN VSS
    DIRECTION INOUT ;
    USE GROUND ;
    SHAPE ABUTMENT ;
    PORT
      LAYER metal1 ;
        RECT 0.0000 -0.0850 1.9000 0.0850 ;
        RECT 1.3900 0.0350 1.4600 0.2450 ;
        RECT 1.7700 0.0350 1.8400 0.2450 ;
    END
  END VSS
  OBS
    LAYER metal1 ;
      RECT 0.2500 0.1750 1.0800 0.2450 ;
      RECT 0.8200 0.4550 1.6500 0.5250 ;
  END
END NAND3_X2

MACRO AND3_X1
  CLASS CORE ;
  ORIGIN 0 0 ;
  FOREIGN AND3_X1 0 0 ;
  SIZE 1.52 BY 1.40 ;
  SYMMETRY X Y ;
  SITE core ;
  PIN A
    DIRECTION INPUT ;
    USE SIGNAL ;
    PORT
      LAYER metal1 ;
        RECT 0.4400 0.5250 0.5100 0.7350 ;
        RECT 0.4400 0.5950 0.6050 0.6650 ;
    END
  END A
  PIN B
    DIRECTION INPUT ;
    USE SIGNAL ;
    PORT
      LAYER metal1 ;
        RECT 0.8200 0.6650 0.8900 0.8750 ;
        RECT 0.8200 0.7350 0.9850 0.8050 ;
        RECT 0.3450 0.8050 0.8900 0.8750 ;
    END
  END B
  PIN C
    DIRECTION INPUT ;
    USE SIGNAL ;
    PORT
      LAYER metal1 ;
        RECT 0.0600 0.4550 0.1300 0.6650 ;
        RECT 0.1550 0.4550 0.2250 0.5950 ;
        RECT 1.1050 0.5950 1.1750 0.7350 ;
        RECT 0.0600 0.4550 0.3200 0.5250 ;
        RECT 0.0600 0.5250 0.2250 0.5950 ;
        RECT 1.0100 0.5950 1.1750 0.6650 ;
      LAYER via1 ;
        RECT 0.2525 0.4575 0.3175 0.5225 ;
        RECT 1.0125 0.5975 1.0775 0.6625 ;
      LAYER metal2 ;
        RECT 0.2500 0.3150 0.3200 0.5250 ;
        RECT 0.6300 0.3150 0.7000 0.4550 ;
        RECT 1.0100 0.3850 1.0800 0.6650 ;
        RECT 0.2500 0.3150 0.7000 0.3850 ;
        RECT 0.6300 0.3850 1.0800 0.4550 ;
    END
  END C
  PIN Y
    DIRECTION OUTPUT ;
    USE SIGNAL ;
    PORT
      LAYER metal1 ;
        RECT 1.3900 0.1750 1.4600 0.3850 ;
        RECT 1.3900 1.0150 1.4600 1.1550 ;
        RECT 1.2000 0.3150 1.4600 0.3850 ;
        RECT 1.2950 1.0150 1.4600 1.0850 ;
      LAYER via1 ;
        RECT 1.2025 0.3175 1.2675 0.3825 ;
        RECT 1.2975 1.0175 1.3625 1.0825 ;
      LAYER metal2 ;
        RECT 1.2000 0.3150 1.2700 1.0850 ;
        RECT 1.2000 1.0150 1.4600 1.0850 ;
    END
  END Y
  PIN VDD
    DIRECTION INOUT ;
    USE POWER ;
    SHAPE ABUTMENT ;
    PORT
      LAYER metal1 ;
        RECT 0.0000 1.3150 1.5200 1.4850 ;
        RECT 0.4400 1.1550 0.5100 1.3650 ;
        RECT 0.8200 1.1550 0.8900 1.3650 ;
        RECT 1.2000 1.1550 1.2700 1.3650 ;
    END
  END VDD
  PIN VSS
    DIRECTION INOUT ;
    USE GROUND ;
    SHAPE ABUTMENT ;
    PORT
      LAYER metal1 ;
        RECT 0.0000 -0.0850 1.5200 0.0850 ;
        RECT 0.0600 0.0350 0.1300 0.2450 ;
        RECT 1.2000 0.0350 1.2700 0.2450 ;
    END
  END VSS
  OBS
    LAYER metal1 ;
      RECT 0.6300 0.3150 0.7000 0.5250 ;
      RECT 0.6300 0.9450 0.7000 1.0850 ;
      RECT 1.0100 0.9450 1.0800 1.0850 ;
      RECT 1.1050 0.8750 1.1750 1.0150 ;
      RECT 1.2950 0.4550 1.3650 0.9450 ;
      RECT 0.6300 0.4550 1.3650 0.5250 ;
      RECT 1.1050 0.8750 1.3650 0.9450 ;
      RECT 0.6300 0.9450 1.1750 1.0150 ;
      RECT 0.4400 0.1750 0.8900 0.2450 ;
      RECT 0.2500 0.1750 0.3200 0.3850 ;
      RECT 1.0100 0.1750 1.0800 0.3850 ;
    LAYER via1 ;
      RECT 0.2525 0.1775 0.3175 0.2425 ;
      RECT 1.0125 0.1775 1.0775 0.2425 ;
    LAYER metal2 ;
      RECT 0.2500 0.1750 1.0800 0.2450 ;
  END
END AND3_X1

MACRO AND3_X2
  CLASS CORE ;
  ORIGIN 0 0 ;
  FOREIGN AND3_X2 0 0 ;
  SIZE 1.71 BY 1.40 ;
  SYMMETRY X Y ;
  SITE core ;
  PIN A
    DIRECTION INPUT ;
    USE SIGNAL ;
    PORT
      LAYER metal1 ;
        RECT 1.5800 0.5950 1.6500 0.8050 ;
    END
  END A
  PIN B
    DIRECTION INPUT ;
    USE SIGNAL ;
    PORT
      LAYER metal1 ;
        RECT 1.0100 0.5950 1.0800 0.8050 ;
    END
  END B
  PIN C
    DIRECTION INPUT ;
    USE SIGNAL ;
    PORT
      LAYER metal1 ;
        RECT 0.0600 0.5950 0.1300 0.8050 ;
    END
  END C
  PIN Y
    DIRECTION OUTPUT ;
    USE SIGNAL ;
    PORT
      LAYER metal1 ;
        RECT 0.6300 1.0150 0.7000 1.2250 ;
        RECT 0.4400 0.4550 0.7000 0.5250 ;
        RECT 0.4400 1.0150 0.7000 1.0850 ;
      LAYER via1 ;
        RECT 0.4425 0.4575 0.5075 0.5225 ;
        RECT 0.4425 1.0175 0.5075 1.0825 ;
      LAYER metal2 ;
        RECT 0.4400 0.4550 0.5100 1.0850 ;
        RECT 0.4400 0.4550 0.7000 0.5250 ;
    END
  END Y
  PIN VDD
    DIRECTION INOUT ;
    USE POWER ;
    SHAPE ABUTMENT ;
    PORT
      LAYER metal1 ;
        RECT 0.0000 1.3150 1.7100 1.4850 ;
        RECT 0.0600 1.1550 0.1300 1.3650 ;
        RECT 0.4400 1.1550 0.5100 1.3650 ;
        RECT 0.8200 1.1550 0.8900 1.3650 ;
        RECT 1.5800 1.1550 1.6500 1.3650 ;
    END
  END VDD
  PIN VSS
    DIRECTION INOUT ;
    USE GROUND ;
    SHAPE ABUTMENT ;
    PORT
      LAYER metal1 ;
        RECT 0.0000 -0.0850 1.7100 0.0850 ;
        RECT 0.0600 0.0350 0.1300 0.2450 ;
        RECT 0.4400 0.0350 0.5100 0.2450 ;
    END
  END VSS
  OBS
    LAYER metal1 ;
      RECT 0.2500 0.8750 0.3200 1.0850 ;
      RECT 0.5350 0.7350 0.6050 0.9450 ;
      RECT 1.0100 0.8750 1.0800 1.0850 ;
      RECT 1.3900 0.3150 1.4600 1.0850 ;
      RECT 0.2500 0.8750 1.0800 0.9450 ;
      RECT 1.0100 1.0150 1.4600 1.0850 ;
      RECT 0.8200 0.3150 0.8900 0.5250 ;
      RECT 1.2000 0.1750 1.2700 0.5250 ;
      RECT 1.2000 0.1750 1.6500 0.2450 ;
      RECT 0.8200 0.4550 1.2700 0.5250 ;
      RECT 0.2500 0.1750 0.3200 0.3850 ;
      RECT 0.8200 0.1750 1.0800 0.2450 ;
    LAYER via1 ;
      RECT 0.2525 0.1775 0.3175 0.2425 ;
      RECT 0.8225 0.1775 0.8875 0.2425 ;
    LAYER metal2 ;
      RECT 0.2500 0.1750 1.0800 0.2450 ;
  END
END AND3_X2

MACRO NOR3_X1
  CLASS CORE ;
  ORIGIN 0 0 ;
  FOREIGN NOR3_X1 0 0 ;
  SIZE 1.33 BY 1.40 ;
  SYMMETRY X Y ;
  SITE core ;
  PIN A
    DIRECTION INPUT ;
    USE SIGNAL ;
    PORT
      LAYER metal1 ;
        RECT 1.2000 0.1750 1.2700 0.3850 ;
    END
  END A
  PIN B
    DIRECTION INPUT ;
    USE SIGNAL ;
    PORT
      LAYER metal1 ;
        RECT 0.0600 0.5250 0.1300 0.8750 ;
        RECT 0.7250 0.6650 0.7950 0.9450 ;
        RECT 0.8200 0.5950 0.8900 0.8050 ;
        RECT 0.7250 0.6650 0.8900 0.7350 ;
        RECT 0.7250 0.7350 0.8900 0.8050 ;
        RECT 0.6300 0.8750 0.7950 0.9450 ;
      LAYER via1 ;
        RECT 0.0625 0.8075 0.1275 0.8725 ;
        RECT 0.6325 0.8775 0.6975 0.9425 ;
      LAYER metal2 ;
        RECT 0.0600 0.8050 0.1300 0.9450 ;
        RECT 0.0600 0.8750 0.7000 0.9450 ;
    END
  END B
  PIN C
    DIRECTION INPUT ;
    USE SIGNAL ;
    PORT
      LAYER metal1 ;
        RECT 0.2500 0.5250 0.3200 0.7350 ;
        RECT 0.2500 0.5950 0.4150 0.6650 ;
    END
  END C
  PIN Y
    DIRECTION OUTPUT ;
    USE SIGNAL ;
    PORT
      LAYER metal1 ;
        RECT 0.4400 0.1750 0.5100 0.3850 ;
        RECT 0.4400 0.7350 0.5100 0.9450 ;
        RECT 0.5350 0.3150 0.6050 0.8050 ;
        RECT 0.8200 0.2450 0.8900 0.3850 ;
        RECT 0.4400 0.3150 0.8900 0.3850 ;
        RECT 0.4400 0.7350 0.6050 0.8050 ;
    END
  END Y
  PIN VDD
    DIRECTION INOUT ;
    USE POWER ;
    SHAPE ABUTMENT ;
    PORT
      LAYER metal1 ;
        RECT 0.0000 1.3150 1.3300 1.4850 ;
        RECT 1.0100 1.1550 1.0800 1.3650 ;
    END
  END VDD
  PIN VSS
    DIRECTION INOUT ;
    USE GROUND ;
    SHAPE ABUTMENT ;
    PORT
      LAYER metal1 ;
        RECT 0.0000 -0.0850 1.3300 0.0850 ;
        RECT 0.2500 0.0350 0.3200 0.2450 ;
        RECT 0.6300 0.0350 0.7000 0.2450 ;
        RECT 1.0100 0.0350 1.0800 0.2450 ;
    END
  END VSS
  OBS
    LAYER metal1 ;
      RECT 0.8200 1.0150 0.8900 1.2250 ;
      RECT 0.8200 1.0150 1.2700 1.0850 ;
      RECT 0.0600 1.1550 0.8900 1.2250 ;
      RECT 0.2500 1.0150 0.7000 1.0850 ;
  END
END NOR3_X1

MACRO NOR3_X2
  CLASS CORE ;
  ORIGIN 0 0 ;
  FOREIGN NOR3_X2 0 0 ;
  SIZE 2.47 BY 1.40 ;
  SYMMETRY X Y ;
  SITE core ;
  PIN A
    DIRECTION INPUT ;
    USE SIGNAL ;
    PORT
      LAYER metal1 ;
        RECT 1.3900 0.1750 1.4600 0.3850 ;
    END
  END A
  PIN B
    DIRECTION INPUT ;
    USE SIGNAL ;
    PORT
      LAYER metal1 ;
        RECT 0.6300 0.5950 0.7000 0.8050 ;
        RECT 0.9150 0.5950 0.9850 0.7350 ;
        RECT 0.9150 0.5950 1.9350 0.6650 ;
        RECT 0.6300 0.6650 0.9850 0.7350 ;
    END
  END B
  PIN C
    DIRECTION INPUT ;
    USE SIGNAL ;
    PORT
      LAYER metal1 ;
        RECT 0.0600 0.1750 0.1300 0.3850 ;
    END
  END C
  PIN Y
    DIRECTION OUTPUT ;
    USE SIGNAL ;
    PORT
      LAYER metal1 ;
        RECT 0.2500 1.0150 0.3200 1.2250 ;
        RECT 0.4400 0.4550 0.5100 0.8050 ;
        RECT 0.4400 0.4550 1.0800 0.5250 ;
        RECT 0.2500 1.1550 0.7000 1.2250 ;
      LAYER via1 ;
        RECT 0.4425 0.7375 0.5075 0.8025 ;
        RECT 0.4425 1.1575 0.5075 1.2225 ;
      LAYER metal2 ;
        RECT 0.4400 0.7350 0.5100 1.2250 ;
    END
  END Y
  PIN VDD
    DIRECTION INOUT ;
    USE POWER ;
    SHAPE ABUTMENT ;
    PORT
      LAYER metal1 ;
        RECT 0.0000 1.3150 2.4700 1.4850 ;
        RECT 1.2000 1.0150 1.6500 1.0850 ;
        RECT 1.2000 1.2950 1.2700 1.3650 ;
      LAYER via1 ;
        RECT 1.2025 1.0175 1.2675 1.0825 ;
        RECT 1.2025 1.2975 1.2675 1.3625 ;
      LAYER metal2 ;
        RECT 1.2000 1.0150 1.2700 1.3650 ;
    END
  END VDD
  PIN VSS
    DIRECTION INOUT ;
    USE GROUND ;
    SHAPE ABUTMENT ;
    PORT
      LAYER metal1 ;
        RECT 0.0000 -0.0850 2.4700 0.0850 ;
        RECT 0.6300 0.0350 0.7000 0.2450 ;
        RECT 1.2000 0.0350 1.2700 0.2450 ;
        RECT 0.6300 0.1750 0.8900 0.2450 ;
    END
  END VSS
  OBS
    LAYER metal1 ;
      RECT 1.0100 1.1550 2.2200 1.2250 ;
      RECT 0.8200 0.8050 0.8900 0.9450 ;
      RECT 1.1050 0.7350 1.1750 0.8750 ;
      RECT 1.9600 0.7350 2.0300 0.9450 ;
      RECT 2.3400 0.7350 2.4100 0.9450 ;
      RECT 1.1050 0.7350 2.4100 0.8050 ;
      RECT 0.8200 0.8050 1.1750 0.8750 ;
      RECT 0.0600 0.8750 0.8900 0.9450 ;
  END
END NOR3_X2

MACRO OR3_X1
  CLASS CORE ;
  ORIGIN 0 0 ;
  FOREIGN OR3_X1 0 0 ;
  SIZE 1.71 BY 1.40 ;
  SYMMETRY X Y ;
  SITE core ;
  PIN A
    DIRECTION INPUT ;
    USE SIGNAL ;
    PORT
      LAYER metal1 ;
        RECT 1.1050 0.5250 1.1750 0.7350 ;
        RECT 1.2000 0.5950 1.2700 0.8050 ;
        RECT 0.1550 0.1750 0.4150 0.2450 ;
        RECT 1.0100 0.5250 1.1750 0.5950 ;
        RECT 1.1050 0.5950 1.2700 0.6650 ;
        RECT 1.1050 0.6650 1.2700 0.7350 ;
      LAYER via1 ;
        RECT 0.2525 0.1775 0.3175 0.2425 ;
        RECT 1.0125 0.5275 1.0775 0.5925 ;
      LAYER metal2 ;
        RECT 0.6300 0.1750 0.7000 0.4550 ;
        RECT 1.0100 0.3850 1.0800 0.5950 ;
        RECT 0.2500 0.1750 0.7000 0.2450 ;
        RECT 0.6300 0.3850 1.0800 0.4550 ;
    END
  END A
  PIN B
    DIRECTION INPUT ;
    USE SIGNAL ;
    PORT
      LAYER metal1 ;
        RECT 0.3450 0.6650 0.4150 0.8050 ;
        RECT 0.4400 0.7350 0.5100 0.8750 ;
        RECT 0.8200 0.5950 0.8900 0.8050 ;
        RECT 0.9150 0.6650 0.9850 0.8750 ;
        RECT 0.8200 0.6650 0.9850 0.7350 ;
        RECT 0.3450 0.7350 0.5100 0.8050 ;
        RECT 0.8200 0.7350 0.9850 0.8050 ;
        RECT 0.9150 0.8050 1.0800 0.8750 ;
      LAYER via1 ;
        RECT 0.4425 0.8075 0.5075 0.8725 ;
        RECT 1.0125 0.8075 1.0775 0.8725 ;
      LAYER metal2 ;
        RECT 0.4400 0.8050 0.5100 1.0150 ;
        RECT 1.0100 0.8050 1.0800 1.0150 ;
        RECT 0.4400 0.9450 1.0800 1.0150 ;
    END
  END B
  PIN C
    DIRECTION INPUT ;
    USE SIGNAL ;
    PORT
      LAYER metal1 ;
        RECT 0.4400 0.3850 0.5100 0.5950 ;
    END
  END C
  PIN Y
    DIRECTION OUTPUT ;
    USE SIGNAL ;
    PORT
      LAYER metal1 ;
        RECT 1.3900 0.8050 1.4600 1.0850 ;
        RECT 1.5800 0.1750 1.6500 0.8750 ;
        RECT 1.3900 0.2450 1.6500 0.3150 ;
        RECT 1.3900 0.8050 1.6500 0.8750 ;
    END
  END Y
  PIN VDD
    DIRECTION INOUT ;
    USE POWER ;
    SHAPE ABUTMENT ;
    PORT
      LAYER metal1 ;
        RECT 0.0000 1.3150 1.7100 1.4850 ;
        RECT 0.0600 1.1550 0.1300 1.3650 ;
        RECT 1.2000 1.1550 1.2700 1.3650 ;
    END
  END VDD
  PIN VSS
    DIRECTION INOUT ;
    USE GROUND ;
    SHAPE ABUTMENT ;
    PORT
      LAYER metal1 ;
        RECT 0.0000 -0.0850 1.7100 0.0850 ;
        RECT 0.8200 0.0350 0.8900 0.2450 ;
        RECT 1.2000 0.0350 1.2700 0.2450 ;
    END
  END VSS
  OBS
    LAYER metal1 ;
      RECT 0.6300 0.2450 0.7000 0.9450 ;
      RECT 1.0100 0.2450 1.0800 0.3850 ;
      RECT 1.1050 0.3150 1.1750 0.4550 ;
      RECT 0.6300 0.3150 1.1750 0.3850 ;
      RECT 1.1050 0.3850 1.3650 0.4550 ;
      RECT 0.2500 1.1550 1.0800 1.2250 ;
      RECT 0.4400 1.0150 0.8900 1.0850 ;
  END
END OR3_X1

MACRO OR3_X2
  CLASS CORE ;
  ORIGIN 0 0 ;
  FOREIGN OR3_X2 0 0 ;
  SIZE 2.28 BY 1.40 ;
  SYMMETRY X Y ;
  SITE core ;
  PIN A
    DIRECTION INPUT ;
    USE SIGNAL ;
    PORT
      LAYER metal1 ;
        RECT 0.1550 0.6650 0.2250 0.8750 ;
        RECT 1.5800 0.4550 1.6500 0.6650 ;
        RECT 1.3900 0.5950 1.6500 0.6650 ;
        RECT 0.1550 0.8050 0.3200 0.8750 ;
      LAYER via1 ;
        RECT 0.2525 0.8075 0.3175 0.8725 ;
        RECT 1.3925 0.5975 1.4575 0.6625 ;
      LAYER metal2 ;
        RECT 1.3900 0.5950 1.4600 0.8750 ;
        RECT 0.2500 0.8050 1.4600 0.8750 ;
    END
  END A
  PIN B
    DIRECTION INPUT ;
    USE SIGNAL ;
    PORT
      LAYER metal1 ;
        RECT 1.2000 0.4550 1.2700 0.6650 ;
        RECT 1.0100 0.5950 1.2700 0.6650 ;
        RECT 0.3450 0.6650 0.7000 0.7350 ;
      LAYER via1 ;
        RECT 0.6325 0.6675 0.6975 0.7325 ;
        RECT 1.0125 0.5975 1.0775 0.6625 ;
      LAYER metal2 ;
        RECT 0.8200 0.5950 0.8900 0.7350 ;
        RECT 0.8200 0.5950 1.0800 0.6650 ;
        RECT 0.6300 0.6650 0.8900 0.7350 ;
    END
  END B
  PIN C
    DIRECTION INPUT ;
    USE SIGNAL ;
    PORT
      LAYER metal1 ;
        RECT 0.6300 0.3150 0.7000 0.5250 ;
    END
  END C
  PIN Y
    DIRECTION OUTPUT ;
    USE SIGNAL ;
    PORT
      LAYER metal1 ;
        RECT 1.9600 0.8750 2.0300 1.1550 ;
        RECT 2.0550 0.4550 2.1250 0.9450 ;
        RECT 1.9600 0.4550 2.1250 0.5250 ;
        RECT 1.9600 0.8750 2.1250 0.9450 ;
    END
  END Y
  PIN VDD
    DIRECTION INOUT ;
    USE POWER ;
    SHAPE ABUTMENT ;
    PORT
      LAYER metal1 ;
        RECT 0.0000 1.3150 2.2800 1.4850 ;
        RECT 0.0600 1.1550 0.1300 1.3650 ;
        RECT 1.5800 1.1550 1.6500 1.3650 ;
        RECT 2.1500 1.1550 2.2200 1.3650 ;
        RECT 1.5800 1.1550 1.8400 1.2250 ;
    END
  END VDD
  PIN VSS
    DIRECTION INOUT ;
    USE GROUND ;
    SHAPE ABUTMENT ;
    PORT
      LAYER metal1 ;
        RECT 0.0000 -0.0850 2.2800 0.0850 ;
        RECT 0.6300 0.0350 0.7000 0.2450 ;
        RECT 1.2000 0.0350 1.2700 0.2450 ;
        RECT 1.5800 0.0350 1.6500 0.2450 ;
        RECT 1.5800 0.1750 1.8400 0.2450 ;
    END
  END VSS
  OBS
    LAYER metal1 ;
      RECT 0.8200 0.2450 0.8900 0.9450 ;
      RECT 1.3900 0.2450 1.4600 0.3850 ;
      RECT 0.8200 0.3150 1.4600 0.3850 ;
      RECT 0.8200 0.7350 1.9350 0.8050 ;
      RECT 0.2500 1.1550 1.4600 1.2250 ;
      RECT 0.6300 0.8750 0.7000 1.0850 ;
      RECT 0.4400 0.8750 0.7000 0.9450 ;
      RECT 0.6300 1.0150 1.2700 1.0850 ;
  END
END OR3_X2

MACRO NAND4_X1
  CLASS CORE ;
  ORIGIN 0 0 ;
  FOREIGN NAND4_X1 0 0 ;
  SIZE 2.09 BY 1.40 ;
  SYMMETRY X Y ;
  SITE core ;
  PIN A
    DIRECTION INPUT ;
    USE SIGNAL ;
    PORT
      LAYER metal1 ;
        RECT 1.3900 0.6650 1.4600 0.8750 ;
    END
  END A
  PIN B
    DIRECTION INPUT ;
    USE SIGNAL ;
    PORT
      LAYER metal1 ;
        RECT 1.2000 0.5250 1.2700 0.7350 ;
        RECT 1.3900 0.4550 1.4600 0.5950 ;
        RECT 1.7700 0.5250 1.8400 0.6650 ;
        RECT 1.2000 0.5250 1.4600 0.5950 ;
        RECT 1.7700 0.5950 1.9350 0.6650 ;
      LAYER via1 ;
        RECT 1.3925 0.4575 1.4575 0.5225 ;
        RECT 1.7725 0.5275 1.8375 0.5925 ;
      LAYER metal2 ;
        RECT 1.5800 0.4550 1.6500 0.5950 ;
        RECT 1.3900 0.4550 1.6500 0.5250 ;
        RECT 1.5800 0.5250 1.8400 0.5950 ;
    END
  END B
  PIN C
    DIRECTION INPUT ;
    USE SIGNAL ;
    PORT
      LAYER metal1 ;
        RECT 0.8200 0.5250 0.8900 0.7350 ;
        RECT 0.1550 0.5950 0.8900 0.6650 ;
    END
  END C
  PIN D
    DIRECTION INPUT ;
    USE SIGNAL ;
    PORT
      LAYER metal1 ;
        RECT 0.4400 0.7350 0.5100 0.9450 ;
        RECT 0.3450 0.7350 0.5100 0.8050 ;
    END
  END D
  PIN Y
    DIRECTION OUTPUT ;
    USE SIGNAL ;
    PORT
      LAYER metal1 ;
        RECT 0.6300 0.9450 0.7000 1.1550 ;
        RECT 0.8200 0.9450 0.8900 1.0850 ;
        RECT 1.2000 0.9450 1.2700 1.0850 ;
        RECT 1.5800 0.4550 1.6500 1.0850 ;
        RECT 0.8200 0.9450 1.2700 1.0150 ;
        RECT 0.6300 1.0150 0.8900 1.0850 ;
        RECT 1.2000 1.0150 1.6500 1.0850 ;
    END
  END Y
  PIN VDD
    DIRECTION INOUT ;
    USE POWER ;
    SHAPE ABUTMENT ;
    PORT
      LAYER metal1 ;
        RECT 0.0000 1.3150 2.0900 1.4850 ;
        RECT 0.4400 1.1550 0.5100 1.3650 ;
        RECT 1.0100 1.1550 1.0800 1.3650 ;
        RECT 1.7700 1.1550 1.8400 1.3650 ;
    END
  END VDD
  PIN VSS
    DIRECTION INOUT ;
    USE GROUND ;
    SHAPE ABUTMENT ;
    PORT
      LAYER metal1 ;
        RECT 0.0000 -0.0850 2.0900 0.0850 ;
        RECT 0.4400 0.0350 0.5100 0.2450 ;
    END
  END VSS
  OBS
    LAYER metal1 ;
      RECT 1.2000 0.1750 1.8400 0.2450 ;
      RECT 1.9600 0.1750 2.0300 0.3850 ;
      RECT 0.0600 0.1750 0.3200 0.2450 ;
      RECT 0.8200 0.1750 1.0800 0.2450 ;
      RECT 0.6300 0.3850 0.7000 0.5250 ;
      RECT 0.6300 0.3850 0.8900 0.4550 ;
      RECT 0.2500 0.4550 0.7000 0.5250 ;
    LAYER via1 ;
      RECT 0.0625 0.1775 0.1275 0.2425 ;
      RECT 0.8225 0.1775 0.8875 0.2425 ;
      RECT 1.9625 0.1775 2.0275 0.2425 ;
    LAYER metal2 ;
      RECT 0.0600 0.1750 2.0300 0.2450 ;
  END
END NAND4_X1

MACRO NAND4_X2
  CLASS CORE ;
  ORIGIN 0 0 ;
  FOREIGN NAND4_X2 0 0 ;
  SIZE 3.23 BY 1.40 ;
  SYMMETRY X Y ;
  SITE core ;
  PIN A
    DIRECTION INPUT ;
    USE SIGNAL ;
    PORT
      LAYER metal1 ;
        RECT 0.8200 0.6650 0.8900 0.8750 ;
    END
  END A
  PIN B
    DIRECTION INPUT ;
    USE SIGNAL ;
    PORT
      LAYER metal1 ;
        RECT 1.3900 0.5950 1.4600 0.8050 ;
        RECT 1.4850 0.5250 1.5550 0.7350 ;
        RECT 1.4850 0.5250 1.6500 0.5950 ;
        RECT 0.4400 0.5950 0.7000 0.6650 ;
        RECT 1.3900 0.5950 1.5550 0.6650 ;
        RECT 1.3900 0.6650 1.5550 0.7350 ;
      LAYER via1 ;
        RECT 0.6325 0.5975 0.6975 0.6625 ;
        RECT 1.5825 0.5275 1.6475 0.5925 ;
      LAYER metal2 ;
        RECT 0.6300 0.3850 0.7000 0.6650 ;
        RECT 1.5800 0.3850 1.6500 0.5950 ;
        RECT 0.6300 0.3850 1.6500 0.4550 ;
    END
  END B
  PIN C
    DIRECTION INPUT ;
    USE SIGNAL ;
    PORT
      LAYER metal1 ;
        RECT 1.7700 0.5950 1.8400 0.8050 ;
        RECT 1.6750 0.6650 1.8400 0.7350 ;
        RECT 1.7700 0.7350 3.0750 0.8050 ;
    END
  END C
  PIN D
    DIRECTION INPUT ;
    USE SIGNAL ;
    PORT
      LAYER metal1 ;
        RECT 2.7200 0.8750 2.7900 1.0850 ;
    END
  END D
  PIN Y
    DIRECTION OUTPUT ;
    USE SIGNAL ;
    PORT
      LAYER metal1 ;
        RECT 0.6300 0.9450 0.7000 1.1550 ;
        RECT 1.0100 0.8750 1.0800 1.0850 ;
        RECT 1.2000 0.4550 1.2700 0.9450 ;
        RECT 1.3900 0.8750 1.4600 1.0850 ;
        RECT 1.7700 0.8750 1.8400 1.0850 ;
        RECT 2.3400 0.8750 2.4100 1.0850 ;
        RECT 0.8200 0.4550 1.2700 0.5250 ;
        RECT 1.0100 0.8750 2.4100 0.9450 ;
        RECT 0.6300 1.0150 1.0800 1.0850 ;
        RECT 1.7700 1.0150 2.0300 1.0850 ;
    END
  END Y
  PIN VDD
    DIRECTION INOUT ;
    USE POWER ;
    SHAPE ABUTMENT ;
    PORT
      LAYER metal1 ;
        RECT 0.0000 1.3150 3.2300 1.4850 ;
        RECT 0.4400 1.1550 0.5100 1.3650 ;
        RECT 1.2000 1.1550 1.2700 1.3650 ;
        RECT 1.5800 1.1550 1.6500 1.3650 ;
        RECT 2.1500 1.1550 2.2200 1.3650 ;
        RECT 2.5300 1.1550 2.6000 1.3650 ;
    END
  END VDD
  PIN VSS
    DIRECTION INOUT ;
    USE GROUND ;
    SHAPE ABUTMENT ;
    PORT
      LAYER metal1 ;
        RECT 0.0000 -0.0850 3.2300 0.0850 ;
        RECT 2.3400 0.0350 2.4100 0.2450 ;
        RECT 2.7200 0.0350 2.7900 0.2450 ;
    END
  END VSS
  OBS
    LAYER metal1 ;
      RECT 0.6300 0.3150 0.7000 0.5250 ;
      RECT 0.6300 0.3150 1.4600 0.3850 ;
      RECT 0.2500 0.4550 0.7000 0.5250 ;
      RECT 1.9600 0.1750 2.0300 0.5950 ;
      RECT 2.0550 0.5250 2.1250 0.6650 ;
      RECT 3.1000 0.4550 3.1700 0.6650 ;
      RECT 0.0600 0.1750 2.0300 0.2450 ;
      RECT 1.9600 0.5250 2.1250 0.5950 ;
      RECT 2.0550 0.5950 3.1700 0.6650 ;
      RECT 1.5800 0.3150 1.8400 0.3850 ;
      RECT 2.1500 0.3150 2.9800 0.3850 ;
    LAYER via1 ;
      RECT 1.7725 0.3175 1.8375 0.3825 ;
      RECT 2.1525 0.3175 2.2175 0.3825 ;
    LAYER metal2 ;
      RECT 1.7700 0.3150 2.2200 0.3850 ;
  END
END NAND4_X2

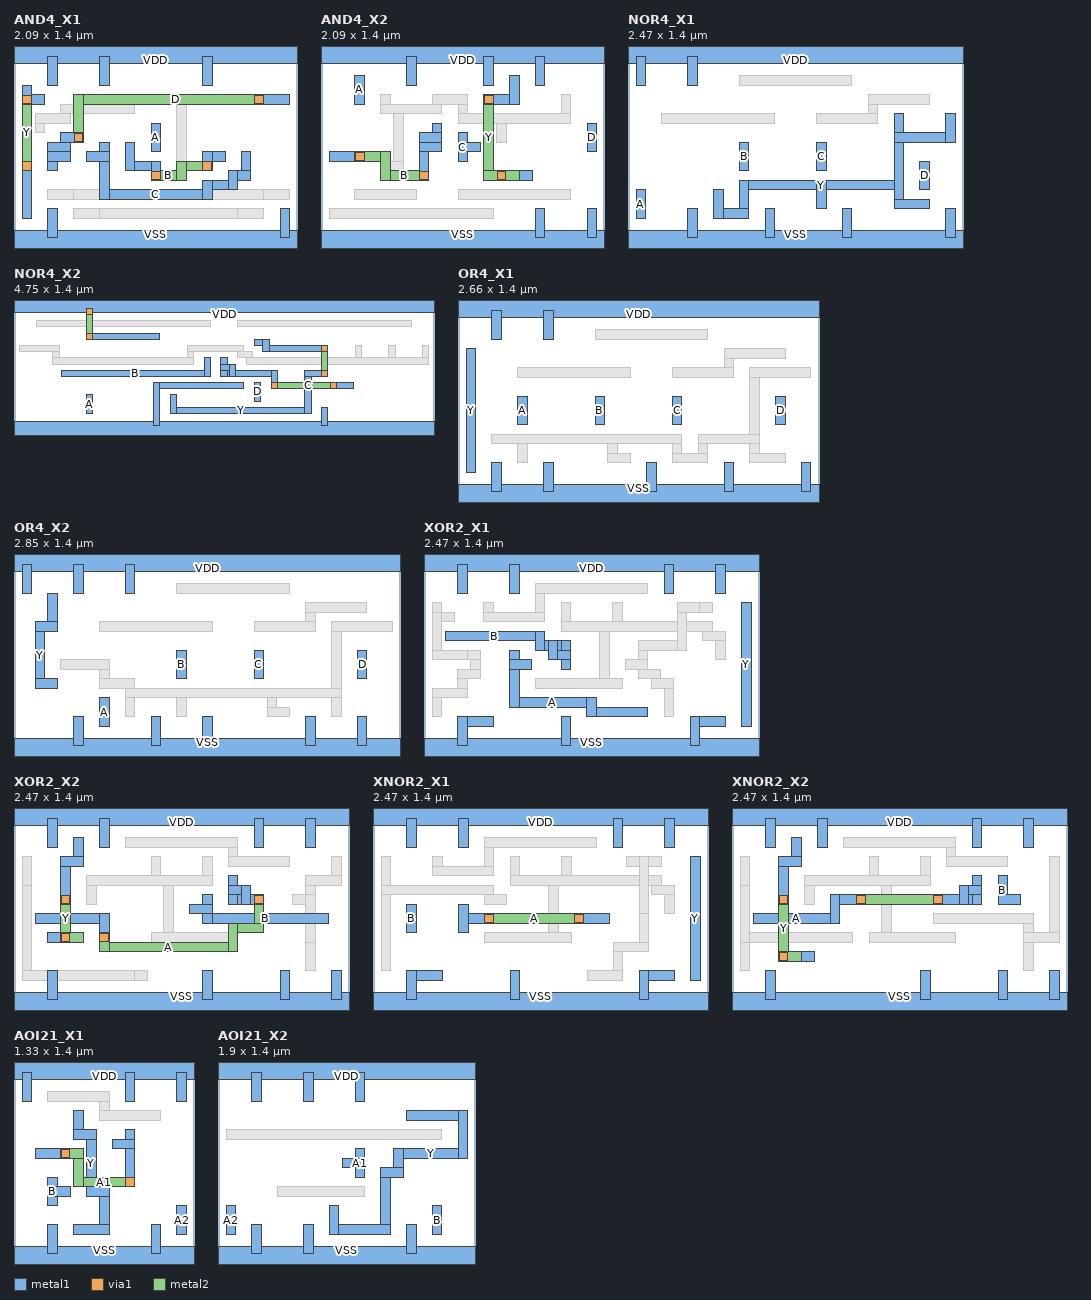
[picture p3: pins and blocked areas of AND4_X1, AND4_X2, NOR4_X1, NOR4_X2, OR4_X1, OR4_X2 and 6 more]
MACRO AND4_X1
  CLASS CORE ;
  ORIGIN 0 0 ;
  FOREIGN AND4_X1 0 0 ;
  SIZE 2.09 BY 1.40 ;
  SYMMETRY X Y ;
  SITE core ;
  PIN A
    DIRECTION INPUT ;
    USE SIGNAL ;
    PORT
      LAYER metal1 ;
        RECT 1.0100 0.6650 1.0800 0.8750 ;
    END
  END A
  PIN B
    DIRECTION INPUT ;
    USE SIGNAL ;
    PORT
      LAYER metal1 ;
        RECT 0.8200 0.5250 0.8900 0.7350 ;
        RECT 1.0100 0.4550 1.0800 0.5950 ;
        RECT 1.3900 0.5250 1.4600 0.6650 ;
        RECT 0.8200 0.5250 1.0800 0.5950 ;
        RECT 1.3900 0.5950 1.5550 0.6650 ;
      LAYER via1 ;
        RECT 1.0125 0.4575 1.0775 0.5225 ;
        RECT 1.3925 0.5275 1.4575 0.5925 ;
      LAYER metal2 ;
        RECT 1.2000 0.4550 1.2700 0.5950 ;
        RECT 1.0100 0.4550 1.2700 0.5250 ;
        RECT 1.2000 0.5250 1.4600 0.5950 ;
    END
  END B
  PIN C
    DIRECTION INPUT ;
    USE SIGNAL ;
    PORT
      LAYER metal1 ;
        RECT 0.6300 0.3150 0.7000 0.7350 ;
        RECT 1.3900 0.3150 1.4600 0.4550 ;
        RECT 1.5800 0.3850 1.6500 0.5250 ;
        RECT 1.6750 0.4550 1.7450 0.6650 ;
        RECT 0.6300 0.3150 1.4600 0.3850 ;
        RECT 1.3900 0.3850 1.6500 0.4550 ;
        RECT 1.5800 0.4550 1.7450 0.5250 ;
        RECT 0.5350 0.5950 0.7000 0.6650 ;
    END
  END C
  PIN D
    DIRECTION INPUT ;
    USE SIGNAL ;
    PORT
      LAYER metal1 ;
        RECT 0.2500 0.5250 0.3200 0.7350 ;
        RECT 0.3450 0.5950 0.4150 0.8050 ;
        RECT 0.2500 0.5950 0.4150 0.6650 ;
        RECT 0.2500 0.6650 0.4150 0.7350 ;
        RECT 0.3450 0.7350 0.5100 0.8050 ;
        RECT 1.7700 1.0150 2.0300 1.0850 ;
      LAYER via1 ;
        RECT 0.4425 0.7375 0.5075 0.8025 ;
        RECT 1.7725 1.0175 1.8375 1.0825 ;
      LAYER metal2 ;
        RECT 0.4400 0.7350 0.5100 1.0850 ;
        RECT 0.4400 1.0150 1.9350 1.0850 ;
    END
  END D
  PIN Y
    DIRECTION OUTPUT ;
    USE SIGNAL ;
    PORT
      LAYER metal1 ;
        RECT 0.0600 0.1750 0.1300 0.5950 ;
        RECT 0.0600 1.0150 0.1300 1.1550 ;
        RECT 0.0600 1.0150 0.2250 1.0850 ;
      LAYER via1 ;
        RECT 0.0625 0.5275 0.1275 0.5925 ;
        RECT 0.0625 1.0175 0.1275 1.0825 ;
      LAYER metal2 ;
        RECT 0.0600 0.5250 0.1300 1.0850 ;
    END
  END Y
  PIN VDD
    DIRECTION INOUT ;
    USE POWER ;
    SHAPE ABUTMENT ;
    PORT
      LAYER metal1 ;
        RECT 0.0000 1.3150 2.0900 1.4850 ;
        RECT 0.2500 1.1550 0.3200 1.3650 ;
        RECT 0.6300 1.1550 0.7000 1.3650 ;
        RECT 1.3900 1.1550 1.4600 1.3650 ;
    END
  END VDD
  PIN VSS
    DIRECTION INOUT ;
    USE GROUND ;
    SHAPE ABUTMENT ;
    PORT
      LAYER metal1 ;
        RECT 0.0000 -0.0850 2.0900 0.0850 ;
        RECT 0.2500 0.0350 0.3200 0.2450 ;
        RECT 1.9600 0.0350 2.0300 0.2450 ;
    END
  END VSS
  OBS
    LAYER metal1 ;
      RECT 0.1550 0.8050 0.2250 0.9450 ;
      RECT 0.3450 0.8750 0.4150 1.0150 ;
      RECT 0.4400 0.9450 0.5100 1.0850 ;
      RECT 0.8200 0.9450 0.8900 1.0850 ;
      RECT 1.2000 0.4550 1.2700 1.0850 ;
      RECT 0.1550 0.8750 0.4150 0.9450 ;
      RECT 0.3450 0.9450 0.8900 1.0150 ;
      RECT 0.8200 1.0150 1.2700 1.0850 ;
      RECT 0.8200 0.1750 1.4600 0.2450 ;
      RECT 0.4400 0.1750 0.7000 0.2450 ;
      RECT 1.5800 0.1750 1.8400 0.2450 ;
      RECT 0.2500 0.3150 0.5100 0.3850 ;
      RECT 1.7700 0.3150 2.0300 0.3850 ;
    LAYER via1 ;
      RECT 0.6325 0.1775 0.6975 0.2425 ;
      RECT 1.5825 0.1775 1.6475 0.2425 ;
      RECT 0.4425 0.3175 0.5075 0.3825 ;
      RECT 1.7725 0.3175 1.8375 0.3825 ;
    LAYER metal2 ;
      RECT 0.6300 0.1750 1.6500 0.2450 ;
      RECT 0.4400 0.3150 1.8400 0.3850 ;
  END
END AND4_X1

MACRO AND4_X2
  CLASS CORE ;
  ORIGIN 0 0 ;
  FOREIGN AND4_X2 0 0 ;
  SIZE 2.09 BY 1.40 ;
  SYMMETRY X Y ;
  SITE core ;
  PIN A
    DIRECTION INPUT ;
    USE SIGNAL ;
    PORT
      LAYER metal1 ;
        RECT 0.2500 1.0150 0.3200 1.2250 ;
    END
  END A
  PIN B
    DIRECTION INPUT ;
    USE SIGNAL ;
    PORT
      LAYER metal1 ;
        RECT 0.7250 0.4550 0.7950 0.8050 ;
        RECT 0.8200 0.6650 0.8900 0.8750 ;
        RECT 0.0600 0.5950 0.3200 0.6650 ;
        RECT 0.7250 0.6650 0.8900 0.7350 ;
        RECT 0.7250 0.7350 0.8900 0.8050 ;
      LAYER via1 ;
        RECT 0.2525 0.5975 0.3175 0.6625 ;
        RECT 0.7275 0.4575 0.7925 0.5225 ;
      LAYER metal2 ;
        RECT 0.4400 0.4550 0.5100 0.6650 ;
        RECT 0.4400 0.4550 0.7950 0.5250 ;
        RECT 0.2500 0.5950 0.5100 0.6650 ;
    END
  END B
  PIN C
    DIRECTION INPUT ;
    USE SIGNAL ;
    PORT
      LAYER metal1 ;
        RECT 1.0100 0.5950 1.0800 0.8050 ;
        RECT 1.0100 0.6650 1.1750 0.7350 ;
    END
  END C
  PIN D
    DIRECTION INPUT ;
    USE SIGNAL ;
    PORT
      LAYER metal1 ;
        RECT 1.9600 0.6650 2.0300 0.8750 ;
    END
  END D
  PIN Y
    DIRECTION OUTPUT ;
    USE SIGNAL ;
    PORT
      LAYER metal1 ;
        RECT 1.3900 1.0150 1.4600 1.2250 ;
        RECT 1.2950 0.4550 1.5550 0.5250 ;
        RECT 1.2000 1.0150 1.4600 1.0850 ;
      LAYER via1 ;
        RECT 1.2025 1.0175 1.2675 1.0825 ;
        RECT 1.2975 0.4575 1.3625 0.5225 ;
      LAYER metal2 ;
        RECT 1.2000 0.4550 1.2700 1.0850 ;
        RECT 1.2000 0.4550 1.4600 0.5250 ;
    END
  END Y
  PIN VDD
    DIRECTION INOUT ;
    USE POWER ;
    SHAPE ABUTMENT ;
    PORT
      LAYER metal1 ;
        RECT 0.0000 1.3150 2.0900 1.4850 ;
        RECT 0.6300 1.1550 0.7000 1.3650 ;
        RECT 1.2000 1.1550 1.2700 1.3650 ;
        RECT 1.5800 1.1550 1.6500 1.3650 ;
    END
  END VDD
  PIN VSS
    DIRECTION INOUT ;
    USE GROUND ;
    SHAPE ABUTMENT ;
    PORT
      LAYER metal1 ;
        RECT 0.0000 -0.0850 2.0900 0.0850 ;
        RECT 1.5800 0.0350 1.6500 0.2450 ;
        RECT 1.9600 0.0350 2.0300 0.2450 ;
    END
  END VSS
  OBS
    LAYER metal1 ;
      RECT 0.4400 0.4550 0.5100 0.5950 ;
      RECT 0.4400 0.9450 0.5100 1.0850 ;
      RECT 0.5350 0.5250 0.6050 1.0150 ;
      RECT 0.8200 0.9450 0.8900 1.0850 ;
      RECT 1.0100 0.8750 1.0800 1.0850 ;
      RECT 1.2950 0.7350 1.3650 0.9450 ;
      RECT 1.7700 0.8750 1.8400 1.0850 ;
      RECT 0.4400 0.5250 0.6050 0.5950 ;
      RECT 1.0100 0.8750 1.8400 0.9450 ;
      RECT 0.4400 0.9450 0.8900 1.0150 ;
      RECT 0.8200 1.0150 1.0800 1.0850 ;
      RECT 0.2500 0.3150 0.7000 0.3850 ;
      RECT 0.0600 0.1750 1.2700 0.2450 ;
      RECT 1.0100 0.3150 1.8400 0.3850 ;
  END
END AND4_X2

MACRO NOR4_X1
  CLASS CORE ;
  ORIGIN 0 0 ;
  FOREIGN NOR4_X1 0 0 ;
  SIZE 2.47 BY 1.40 ;
  SYMMETRY X Y ;
  SITE core ;
  PIN A
    DIRECTION INPUT ;
    USE SIGNAL ;
    PORT
      LAYER metal1 ;
        RECT 0.0600 0.1750 0.1300 0.3850 ;
    END
  END A
  PIN B
    DIRECTION INPUT ;
    USE SIGNAL ;
    PORT
      LAYER metal1 ;
        RECT 0.8200 0.5250 0.8900 0.7350 ;
    END
  END B
  PIN C
    DIRECTION INPUT ;
    USE SIGNAL ;
    PORT
      LAYER metal1 ;
        RECT 1.3900 0.5250 1.4600 0.7350 ;
    END
  END C
  PIN D
    DIRECTION INPUT ;
    USE SIGNAL ;
    PORT
      LAYER metal1 ;
        RECT 2.1500 0.3850 2.2200 0.5950 ;
    END
  END D
  PIN Y
    DIRECTION OUTPUT ;
    USE SIGNAL ;
    PORT
      LAYER metal1 ;
        RECT 0.6300 0.1750 0.7000 0.3850 ;
        RECT 0.8200 0.1750 0.8900 0.4550 ;
        RECT 1.3900 0.2450 1.4600 0.4550 ;
        RECT 1.9600 0.2450 2.0300 0.9450 ;
        RECT 2.3400 0.7350 2.4100 0.9450 ;
        RECT 0.6300 0.1750 0.8900 0.2450 ;
        RECT 1.9600 0.2450 2.2200 0.3150 ;
        RECT 0.8200 0.3850 2.0300 0.4550 ;
        RECT 1.9600 0.7350 2.4100 0.8050 ;
    END
  END Y
  PIN VDD
    DIRECTION INOUT ;
    USE POWER ;
    SHAPE ABUTMENT ;
    PORT
      LAYER metal1 ;
        RECT 0.0000 1.3150 2.4700 1.4850 ;
        RECT 0.0600 1.1550 0.1300 1.3650 ;
        RECT 0.4400 1.1550 0.5100 1.3650 ;
    END
  END VDD
  PIN VSS
    DIRECTION INOUT ;
    USE GROUND ;
    SHAPE ABUTMENT ;
    PORT
      LAYER metal1 ;
        RECT 0.0000 -0.0850 2.4700 0.0850 ;
        RECT 0.4400 0.0350 0.5100 0.2450 ;
        RECT 1.0100 0.0350 1.0800 0.2450 ;
        RECT 1.5800 0.0350 1.6500 0.2450 ;
        RECT 2.3400 0.0350 2.4100 0.2450 ;
    END
  END VSS
  OBS
    LAYER metal1 ;
      RECT 0.2500 0.8750 1.0800 0.9450 ;
      RECT 0.8200 1.1550 1.6500 1.2250 ;
      RECT 1.7700 0.8750 1.8400 1.0850 ;
      RECT 1.3900 0.8750 1.8400 0.9450 ;
      RECT 1.7700 1.0150 2.2200 1.0850 ;
  END
END NOR4_X1

MACRO NOR4_X2
  CLASS CORE ;
  ORIGIN 0 0 ;
  FOREIGN NOR4_X2 0 0 ;
  SIZE 4.75 BY 1.40 ;
  SYMMETRY X Y ;
  SITE core ;
  PIN A
    DIRECTION INPUT ;
    USE SIGNAL ;
    PORT
      LAYER metal1 ;
        RECT 0.8200 0.1750 0.8900 0.3850 ;
    END
  END A
  PIN B
    DIRECTION INPUT ;
    USE SIGNAL ;
    PORT
      LAYER metal1 ;
        RECT 2.1500 0.5950 2.2200 0.8050 ;
        RECT 0.5350 0.5950 2.2200 0.6650 ;
    END
  END B
  PIN C
    DIRECTION INPUT ;
    USE SIGNAL ;
    PORT
      LAYER metal1 ;
        RECT 2.3400 0.5950 2.4100 0.8050 ;
        RECT 2.4350 0.5950 2.5050 0.7350 ;
        RECT 2.9100 0.4550 2.9800 0.6650 ;
        RECT 3.5750 0.4550 3.8350 0.5250 ;
        RECT 2.3400 0.5950 2.9800 0.6650 ;
        RECT 2.3400 0.6650 2.5050 0.7350 ;
      LAYER via1 ;
        RECT 2.9125 0.4575 2.9775 0.5225 ;
        RECT 3.5775 0.4575 3.6425 0.5225 ;
      LAYER metal2 ;
        RECT 2.9100 0.4550 3.7400 0.5250 ;
    END
  END C
  PIN D
    DIRECTION INPUT ;
    USE SIGNAL ;
    PORT
      LAYER metal1 ;
        RECT 2.7200 0.3150 2.7900 0.5250 ;
    END
  END D
  PIN Y
    DIRECTION OUTPUT ;
    USE SIGNAL ;
    PORT
      LAYER metal1 ;
        RECT 1.7700 0.1750 1.8400 0.3850 ;
        RECT 2.8150 0.8750 2.8850 1.0150 ;
        RECT 3.2900 0.1750 3.3600 0.6650 ;
        RECT 1.7700 0.1750 3.3600 0.2450 ;
        RECT 3.2900 0.5950 3.5500 0.6650 ;
        RECT 2.8150 0.8750 3.5500 0.9450 ;
        RECT 2.7200 0.9450 2.8850 1.0150 ;
      LAYER via1 ;
        RECT 3.4825 0.5975 3.5475 0.6625 ;
        RECT 3.4825 0.8775 3.5475 0.9425 ;
      LAYER metal2 ;
        RECT 3.4800 0.5950 3.5500 0.9450 ;
    END
  END Y
  PIN VDD
    DIRECTION INOUT ;
    USE POWER ;
    SHAPE ABUTMENT ;
    PORT
      LAYER metal1 ;
        RECT 0.0000 1.3150 4.7500 1.4850 ;
        RECT 0.8200 1.0150 1.6500 1.0850 ;
        RECT 0.8200 1.2950 0.8900 1.3650 ;
      LAYER via1 ;
        RECT 0.8225 1.0175 0.8875 1.0825 ;
        RECT 0.8225 1.2975 0.8875 1.3625 ;
      LAYER metal2 ;
        RECT 0.8200 1.0150 0.8900 1.3650 ;
    END
  END VDD
  PIN VSS
    DIRECTION INOUT ;
    USE GROUND ;
    SHAPE ABUTMENT ;
    PORT
      LAYER metal1 ;
        RECT 0.0000 -0.0850 4.7500 0.0850 ;
        RECT 1.5800 0.0350 1.6500 0.5250 ;
        RECT 3.4800 0.0350 3.5500 0.2450 ;
        RECT 1.5800 0.4550 2.6000 0.5250 ;
    END
  END VSS
  OBS
    LAYER metal1 ;
      RECT 0.2500 1.1550 2.2200 1.2250 ;
      RECT 0.4400 0.7350 0.5100 0.9450 ;
      RECT 1.9600 0.7350 2.0300 0.9450 ;
      RECT 2.5300 0.8050 2.6000 0.9450 ;
      RECT 2.6250 0.7350 2.6950 0.8750 ;
      RECT 3.8600 0.7350 3.9300 0.9450 ;
      RECT 4.2400 0.7350 4.3100 0.9450 ;
      RECT 4.6200 0.7350 4.6900 0.9450 ;
      RECT 0.4400 0.7350 2.0300 0.8050 ;
      RECT 2.6250 0.7350 4.6900 0.8050 ;
      RECT 2.5300 0.8050 2.6950 0.8750 ;
      RECT 0.0600 0.8750 0.5100 0.9450 ;
      RECT 1.9600 0.8750 2.6000 0.9450 ;
      RECT 2.5300 1.1550 4.5000 1.2250 ;
  END
END NOR4_X2

MACRO OR4_X1
  CLASS CORE ;
  ORIGIN 0 0 ;
  FOREIGN OR4_X1 0 0 ;
  SIZE 2.66 BY 1.40 ;
  SYMMETRY X Y ;
  SITE core ;
  PIN A
    DIRECTION INPUT ;
    USE SIGNAL ;
    PORT
      LAYER metal1 ;
        RECT 0.4400 0.5250 0.5100 0.7350 ;
    END
  END A
  PIN B
    DIRECTION INPUT ;
    USE SIGNAL ;
    PORT
      LAYER metal1 ;
        RECT 1.0100 0.5250 1.0800 0.7350 ;
    END
  END B
  PIN C
    DIRECTION INPUT ;
    USE SIGNAL ;
    PORT
      LAYER metal1 ;
        RECT 1.5800 0.5250 1.6500 0.7350 ;
    END
  END C
  PIN D
    DIRECTION INPUT ;
    USE SIGNAL ;
    PORT
      LAYER metal1 ;
        RECT 2.3400 0.5250 2.4100 0.7350 ;
    END
  END D
  PIN Y
    DIRECTION OUTPUT ;
    USE SIGNAL ;
    PORT
      LAYER metal1 ;
        RECT 0.0600 0.1750 0.1300 1.0850 ;
    END
  END Y
  PIN VDD
    DIRECTION INOUT ;
    USE POWER ;
    SHAPE ABUTMENT ;
    PORT
      LAYER metal1 ;
        RECT 0.0000 1.3150 2.6600 1.4850 ;
        RECT 0.2500 1.1550 0.3200 1.3650 ;
        RECT 0.6300 1.1550 0.7000 1.3650 ;
    END
  END VDD
  PIN VSS
    DIRECTION INOUT ;
    USE GROUND ;
    SHAPE ABUTMENT ;
    PORT
      LAYER metal1 ;
        RECT 0.0000 -0.0850 2.6600 0.0850 ;
        RECT 0.2500 0.0350 0.3200 0.2450 ;
        RECT 0.6300 0.0350 0.7000 0.2450 ;
        RECT 1.3900 0.0350 1.4600 0.2450 ;
        RECT 1.9600 0.0350 2.0300 0.2450 ;
        RECT 2.5300 0.0350 2.6000 0.2450 ;
    END
  END VSS
  OBS
    LAYER metal1 ;
      RECT 0.4400 0.2450 0.5100 0.4550 ;
      RECT 1.1050 0.2450 1.1750 0.4550 ;
      RECT 1.5800 0.2450 1.6500 0.4550 ;
      RECT 1.7700 0.2450 1.8400 0.4550 ;
      RECT 2.1500 0.2450 2.2200 0.9450 ;
      RECT 1.1050 0.2450 1.2700 0.3150 ;
      RECT 1.5800 0.2450 1.8400 0.3150 ;
      RECT 2.1500 0.2450 2.4100 0.3150 ;
      RECT 0.2500 0.3850 1.6500 0.4550 ;
      RECT 1.7700 0.3850 2.2200 0.4550 ;
      RECT 2.1500 0.8750 2.6000 0.9450 ;
      RECT 0.4400 0.8750 1.2700 0.9450 ;
      RECT 1.0100 1.1550 1.8400 1.2250 ;
      RECT 1.9600 0.8750 2.0300 1.0850 ;
      RECT 1.5800 0.8750 2.0300 0.9450 ;
      RECT 1.9600 1.0150 2.4100 1.0850 ;
  END
END OR4_X1

MACRO OR4_X2
  CLASS CORE ;
  ORIGIN 0 0 ;
  FOREIGN OR4_X2 0 0 ;
  SIZE 2.85 BY 1.40 ;
  SYMMETRY X Y ;
  SITE core ;
  PIN A
    DIRECTION INPUT ;
    USE SIGNAL ;
    PORT
      LAYER metal1 ;
        RECT 0.6300 0.1750 0.7000 0.3850 ;
    END
  END A
  PIN B
    DIRECTION INPUT ;
    USE SIGNAL ;
    PORT
      LAYER metal1 ;
        RECT 1.2000 0.5250 1.2700 0.7350 ;
    END
  END B
  PIN C
    DIRECTION INPUT ;
    USE SIGNAL ;
    PORT
      LAYER metal1 ;
        RECT 1.7700 0.5250 1.8400 0.7350 ;
    END
  END C
  PIN D
    DIRECTION INPUT ;
    USE SIGNAL ;
    PORT
      LAYER metal1 ;
        RECT 2.5300 0.5250 2.6000 0.7350 ;
    END
  END D
  PIN Y
    DIRECTION OUTPUT ;
    USE SIGNAL ;
    PORT
      LAYER metal1 ;
        RECT 0.1550 0.4550 0.2250 0.9450 ;
        RECT 0.2500 0.8750 0.3200 1.1550 ;
        RECT 0.1550 0.4550 0.3200 0.5250 ;
        RECT 0.1550 0.8750 0.3200 0.9450 ;
    END
  END Y
  PIN VDD
    DIRECTION INOUT ;
    USE POWER ;
    SHAPE ABUTMENT ;
    PORT
      LAYER metal1 ;
        RECT 0.0000 1.3150 2.8500 1.4850 ;
        RECT 0.0600 1.1550 0.1300 1.3650 ;
        RECT 0.4400 1.1550 0.5100 1.3650 ;
        RECT 0.8200 1.1550 0.8900 1.3650 ;
    END
  END VDD
  PIN VSS
    DIRECTION INOUT ;
    USE GROUND ;
    SHAPE ABUTMENT ;
    PORT
      LAYER metal1 ;
        RECT 0.0000 -0.0850 2.8500 0.0850 ;
        RECT 0.4400 0.0350 0.5100 0.2450 ;
        RECT 1.0100 0.0350 1.0800 0.2450 ;
        RECT 1.3900 0.0350 1.4600 0.2450 ;
        RECT 2.1500 0.0350 2.2200 0.2450 ;
        RECT 2.5300 0.0350 2.6000 0.2450 ;
    END
  END VSS
  OBS
    LAYER metal1 ;
      RECT 0.6300 0.4550 0.7000 0.6650 ;
      RECT 0.8200 0.2450 0.8900 0.5250 ;
      RECT 1.2000 0.2450 1.2700 0.4550 ;
      RECT 1.8650 0.2450 1.9350 0.4550 ;
      RECT 2.3400 0.2450 2.4100 0.9450 ;
      RECT 1.8650 0.2450 2.0300 0.3150 ;
      RECT 0.8200 0.3850 2.4100 0.4550 ;
      RECT 0.6300 0.4550 0.8900 0.5250 ;
      RECT 0.3450 0.5950 0.7000 0.6650 ;
      RECT 2.3400 0.8750 2.7900 0.9450 ;
      RECT 0.6300 0.8750 1.4600 0.9450 ;
      RECT 1.2000 1.1550 2.0300 1.2250 ;
      RECT 2.1500 0.8750 2.2200 1.0850 ;
      RECT 1.7700 0.8750 2.2200 0.9450 ;
      RECT 2.1500 1.0150 2.6000 1.0850 ;
  END
END OR4_X2

MACRO XOR2_X1
  CLASS CORE ;
  ORIGIN 0 0 ;
  FOREIGN XOR2_X1 0 0 ;
  SIZE 2.47 BY 1.40 ;
  SYMMETRY X Y ;
  SITE core ;
  PIN A
    DIRECTION INPUT ;
    USE SIGNAL ;
    PORT
      LAYER metal1 ;
        RECT 0.6300 0.3150 0.7000 0.7350 ;
        RECT 1.2000 0.2450 1.2700 0.3850 ;
        RECT 1.2000 0.2450 1.6500 0.3150 ;
        RECT 0.6300 0.3150 1.2700 0.3850 ;
        RECT 0.6300 0.5950 0.7950 0.6650 ;
    END
  END A
  PIN B
    DIRECTION INPUT ;
    USE SIGNAL ;
    PORT
      LAYER metal1 ;
        RECT 0.8200 0.7350 0.8900 0.8750 ;
        RECT 0.9150 0.6650 0.9850 0.8050 ;
        RECT 1.0100 0.5950 1.0800 0.8050 ;
        RECT 0.9150 0.6650 1.0800 0.7350 ;
        RECT 0.8200 0.7350 1.0800 0.8050 ;
        RECT 0.1550 0.8050 0.8900 0.8750 ;
    END
  END B
  PIN Y
    DIRECTION OUTPUT ;
    USE SIGNAL ;
    PORT
      LAYER metal1 ;
        RECT 2.3400 0.1750 2.4100 1.0850 ;
    END
  END Y
  PIN VDD
    DIRECTION INOUT ;
    USE POWER ;
    SHAPE ABUTMENT ;
    PORT
      LAYER metal1 ;
        RECT 0.0000 1.3150 2.4700 1.4850 ;
        RECT 0.2500 1.1550 0.3200 1.3650 ;
        RECT 0.6300 1.1550 0.7000 1.3650 ;
        RECT 1.7700 1.1550 1.8400 1.3650 ;
        RECT 2.1500 1.1550 2.2200 1.3650 ;
    END
  END VDD
  PIN VSS
    DIRECTION INOUT ;
    USE GROUND ;
    SHAPE ABUTMENT ;
    PORT
      LAYER metal1 ;
        RECT 0.0000 -0.0850 2.4700 0.0850 ;
        RECT 0.2500 0.0350 0.3200 0.2450 ;
        RECT 1.0100 0.0350 1.0800 0.2450 ;
        RECT 1.9600 0.0350 2.0300 0.2450 ;
        RECT 0.2500 0.1750 0.5100 0.2450 ;
        RECT 1.9600 0.1750 2.2200 0.2450 ;
    END
  END VSS
  OBS
    LAYER metal1 ;
      RECT 1.5800 0.5250 1.6500 0.8050 ;
      RECT 1.6750 0.4550 1.7450 0.5950 ;
      RECT 1.7700 0.2450 1.8400 0.5250 ;
      RECT 1.6750 0.4550 1.8400 0.5250 ;
      RECT 1.5800 0.5250 1.7450 0.5950 ;
      RECT 1.4850 0.5950 1.6500 0.6650 ;
      RECT 1.5800 0.7350 1.9350 0.8050 ;
      RECT 1.8650 1.0150 2.1250 1.0850 ;
      RECT 0.0600 0.2450 0.1300 0.4550 ;
      RECT 0.0600 0.9450 0.1300 1.0850 ;
      RECT 0.2500 0.3850 0.3200 0.5950 ;
      RECT 0.3450 0.5250 0.4150 0.7350 ;
      RECT 0.0600 0.3850 0.3200 0.4550 ;
      RECT 0.2500 0.5250 0.4150 0.5950 ;
      RECT 0.2500 0.6650 0.4150 0.7350 ;
      RECT 0.0600 0.9450 0.2250 1.0150 ;
      RECT 1.0100 0.8750 1.0800 1.0850 ;
      RECT 1.2950 0.4550 1.3650 0.9450 ;
      RECT 1.3900 0.8750 1.4600 1.0850 ;
      RECT 2.0550 0.8050 2.1250 0.9450 ;
      RECT 2.1500 0.6650 2.2200 0.8750 ;
      RECT 0.8200 0.4550 1.4600 0.5250 ;
      RECT 2.0550 0.8050 2.2200 0.8750 ;
      RECT 1.0100 0.8750 2.1250 0.9450 ;
      RECT 0.4400 0.9450 0.5100 1.0850 ;
      RECT 0.8200 0.9450 0.8900 1.2250 ;
      RECT 0.4400 0.9450 0.8900 1.0150 ;
      RECT 0.8200 1.1550 1.6500 1.2250 ;
    LAYER via1 ;
      RECT 1.8675 0.7375 1.9325 0.8025 ;
      RECT 1.8675 1.0175 1.9325 1.0825 ;
      RECT 0.0625 0.9475 0.1275 1.0125 ;
      RECT 0.2525 0.6675 0.3175 0.7325 ;
    LAYER metal2 ;
      RECT 1.8650 0.7350 1.9350 1.0850 ;
      RECT 1.8650 1.0150 2.0300 1.0850 ;
      RECT 0.0600 0.6650 0.1300 1.0150 ;
      RECT 0.0600 0.6650 0.3200 0.7350 ;
  END
END XOR2_X1

MACRO XOR2_X2
  CLASS CORE ;
  ORIGIN 0 0 ;
  FOREIGN XOR2_X2 0 0 ;
  SIZE 2.47 BY 1.40 ;
  SYMMETRY X Y ;
  SITE core ;
  PIN A
    DIRECTION INPUT ;
    USE SIGNAL ;
    PORT
      LAYER metal1 ;
        RECT 0.6300 0.4550 0.7000 0.6650 ;
        RECT 1.5800 0.7350 1.6500 0.9450 ;
        RECT 1.6750 0.7350 1.7450 0.8750 ;
        RECT 0.1550 0.5950 0.7000 0.6650 ;
        RECT 1.5800 0.7350 1.8400 0.8050 ;
        RECT 1.5800 0.8050 1.7450 0.8750 ;
      LAYER via1 ;
        RECT 0.6325 0.4575 0.6975 0.5225 ;
        RECT 1.7725 0.7375 1.8375 0.8025 ;
      LAYER metal2 ;
        RECT 0.6300 0.3850 0.7000 0.5250 ;
        RECT 1.5800 0.3850 1.6500 0.5950 ;
        RECT 1.7700 0.5250 1.8400 0.8050 ;
        RECT 0.6300 0.3850 1.6500 0.4550 ;
        RECT 1.5800 0.5250 1.8400 0.5950 ;
    END
  END A
  PIN B
    DIRECTION INPUT ;
    USE SIGNAL ;
    PORT
      LAYER metal1 ;
        RECT 1.3900 0.5950 1.4600 0.8050 ;
        RECT 1.3900 0.5950 2.3150 0.6650 ;
        RECT 1.2950 0.6650 1.4600 0.7350 ;
    END
  END B
  PIN Y
    DIRECTION OUTPUT ;
    USE SIGNAL ;
    PORT
      LAYER metal1 ;
        RECT 0.3450 0.7350 0.4150 1.0850 ;
        RECT 0.4400 1.0150 0.5100 1.2250 ;
        RECT 0.2500 0.4550 0.5100 0.5250 ;
        RECT 0.3450 1.0150 0.5100 1.0850 ;
      LAYER via1 ;
        RECT 0.3475 0.4575 0.4125 0.5225 ;
        RECT 0.3475 0.7375 0.4125 0.8025 ;
      LAYER metal2 ;
        RECT 0.3450 0.4550 0.4150 0.8050 ;
        RECT 0.3450 0.4550 0.5100 0.5250 ;
    END
  END Y
  PIN VDD
    DIRECTION INOUT ;
    USE POWER ;
    SHAPE ABUTMENT ;
    PORT
      LAYER metal1 ;
        RECT 0.0000 1.3150 2.4700 1.4850 ;
        RECT 0.2500 1.1550 0.3200 1.3650 ;
        RECT 0.6300 1.1550 0.7000 1.3650 ;
        RECT 1.7700 1.1550 1.8400 1.3650 ;
        RECT 2.1500 1.1550 2.2200 1.3650 ;
    END
  END VDD
  PIN VSS
    DIRECTION INOUT ;
    USE GROUND ;
    SHAPE ABUTMENT ;
    PORT
      LAYER metal1 ;
        RECT 0.0000 -0.0850 2.4700 0.0850 ;
        RECT 0.2500 0.0350 0.3200 0.2450 ;
        RECT 1.3900 0.0350 1.4600 0.2450 ;
        RECT 1.9600 0.0350 2.0300 0.2450 ;
        RECT 2.3400 0.0350 2.4100 0.2450 ;
    END
  END VSS
  OBS
    LAYER metal1 ;
      RECT 0.0600 0.1750 0.1300 0.3850 ;
      RECT 0.0600 0.8050 0.1300 1.0850 ;
      RECT 0.7250 0.1750 0.9850 0.2450 ;
      RECT 2.1500 0.2450 2.2200 0.5250 ;
      RECT 2.1500 0.7350 2.2200 0.9450 ;
      RECT 2.3400 0.8750 2.4100 1.0850 ;
      RECT 2.0550 0.7350 2.2200 0.8050 ;
      RECT 2.1500 0.8750 2.4100 0.9450 ;
      RECT 0.5350 0.7350 0.6050 0.9450 ;
      RECT 1.0100 0.8750 1.0800 1.0850 ;
      RECT 1.1050 0.4550 1.1750 0.9450 ;
      RECT 1.3900 0.8750 1.4600 1.0850 ;
      RECT 1.0100 0.4550 1.6500 0.5250 ;
      RECT 0.5350 0.8750 1.4600 0.9450 ;
      RECT 1.5800 1.0150 1.6500 1.2250 ;
      RECT 1.5800 1.0150 2.0300 1.0850 ;
      RECT 0.8200 1.1550 1.6500 1.2250 ;
    LAYER via1 ;
      RECT 0.0625 0.1775 0.1275 0.2425 ;
      RECT 0.0625 0.8075 0.1275 0.8725 ;
      RECT 0.7275 0.1775 0.7925 0.2425 ;
      RECT 2.1525 0.4575 2.2175 0.5225 ;
      RECT 2.1525 0.7375 2.2175 0.8025 ;
    LAYER metal2 ;
      RECT 0.0600 0.1750 0.1300 0.8750 ;
      RECT 0.0600 0.1750 0.8900 0.2450 ;
      RECT 2.1500 0.4550 2.2200 0.8050 ;
  END
END XOR2_X2

MACRO XNOR2_X1
  CLASS CORE ;
  ORIGIN 0 0 ;
  FOREIGN XNOR2_X1 0 0 ;
  SIZE 2.47 BY 1.40 ;
  SYMMETRY X Y ;
  SITE core ;
  PIN A
    DIRECTION INPUT ;
    USE SIGNAL ;
    PORT
      LAYER metal1 ;
        RECT 0.6300 0.5250 0.7000 0.7350 ;
        RECT 0.6300 0.5950 0.8900 0.6650 ;
        RECT 1.4850 0.5950 1.7450 0.6650 ;
      LAYER via1 ;
        RECT 0.8225 0.5975 0.8875 0.6625 ;
        RECT 1.4875 0.5975 1.5525 0.6625 ;
      LAYER metal2 ;
        RECT 0.8200 0.5950 1.5550 0.6650 ;
    END
  END A
  PIN B
    DIRECTION INPUT ;
    USE SIGNAL ;
    PORT
      LAYER metal1 ;
        RECT 0.2500 0.5250 0.3200 0.7350 ;
    END
  END B
  PIN Y
    DIRECTION OUTPUT ;
    USE SIGNAL ;
    PORT
      LAYER metal1 ;
        RECT 2.3400 0.1750 2.4100 1.0850 ;
    END
  END Y
  PIN VDD
    DIRECTION INOUT ;
    USE POWER ;
    SHAPE ABUTMENT ;
    PORT
      LAYER metal1 ;
        RECT 0.0000 1.3150 2.4700 1.4850 ;
        RECT 0.2500 1.1550 0.3200 1.3650 ;
        RECT 0.6300 1.1550 0.7000 1.3650 ;
        RECT 1.7700 1.1550 1.8400 1.3650 ;
        RECT 2.1500 1.1550 2.2200 1.3650 ;
    END
  END VDD
  PIN VSS
    DIRECTION INOUT ;
    USE GROUND ;
    SHAPE ABUTMENT ;
    PORT
      LAYER metal1 ;
        RECT 0.0000 -0.0850 2.4700 0.0850 ;
        RECT 0.2500 0.0350 0.3200 0.2450 ;
        RECT 1.0100 0.0350 1.0800 0.2450 ;
        RECT 1.9600 0.0350 2.0300 0.2450 ;
        RECT 0.2500 0.1750 0.5100 0.2450 ;
        RECT 1.9600 0.1750 2.2200 0.2450 ;
    END
  END VSS
  OBS
    LAYER metal1 ;
      RECT 1.7700 0.1750 1.8400 0.4550 ;
      RECT 1.9600 0.3850 2.0300 0.7350 ;
      RECT 1.5800 0.1750 1.8400 0.2450 ;
      RECT 1.7700 0.3850 2.0300 0.4550 ;
      RECT 1.8650 1.0150 2.1250 1.0850 ;
      RECT 0.0600 0.2450 0.1300 1.0850 ;
      RECT 0.8200 0.7350 0.8900 0.8750 ;
      RECT 0.8200 0.7350 0.9850 0.8050 ;
      RECT 0.0600 0.8050 0.8900 0.8750 ;
      RECT 1.0100 0.8750 1.0800 1.0850 ;
      RECT 1.2950 0.4550 1.3650 0.9450 ;
      RECT 1.3900 0.8750 1.4600 1.0850 ;
      RECT 2.0550 0.8050 2.1250 0.9450 ;
      RECT 2.1500 0.6650 2.2200 0.8750 ;
      RECT 0.8200 0.4550 1.4600 0.5250 ;
      RECT 2.0550 0.8050 2.2200 0.8750 ;
      RECT 1.0100 0.8750 2.1250 0.9450 ;
      RECT 0.4400 0.9450 0.5100 1.0850 ;
      RECT 0.8200 0.9450 0.8900 1.2250 ;
      RECT 0.4400 0.9450 0.8900 1.0150 ;
      RECT 0.8200 1.1550 1.6500 1.2250 ;
    LAYER via1 ;
      RECT 1.9625 0.6675 2.0275 0.7325 ;
      RECT 1.9625 1.0175 2.0275 1.0825 ;
    LAYER metal2 ;
      RECT 1.9600 0.6650 2.0300 1.0850 ;
  END
END XNOR2_X1

MACRO XNOR2_X2
  CLASS CORE ;
  ORIGIN 0 0 ;
  FOREIGN XNOR2_X2 0 0 ;
  SIZE 2.47 BY 1.40 ;
  SYMMETRY X Y ;
  SITE core ;
  PIN A
    DIRECTION INPUT ;
    USE SIGNAL ;
    PORT
      LAYER metal1 ;
        RECT 0.7250 0.5950 0.7950 0.8050 ;
        RECT 1.6750 0.7350 1.7450 0.8750 ;
        RECT 1.7700 0.7350 1.8400 0.9450 ;
        RECT 0.1550 0.5950 0.7950 0.6650 ;
        RECT 0.7250 0.7350 0.9850 0.8050 ;
        RECT 1.4850 0.7350 1.8400 0.8050 ;
        RECT 1.6750 0.8050 1.8400 0.8750 ;
      LAYER via1 ;
        RECT 0.9175 0.7375 0.9825 0.8025 ;
        RECT 1.4875 0.7375 1.5525 0.8025 ;
      LAYER metal2 ;
        RECT 0.9150 0.7350 1.5550 0.8050 ;
    END
  END A
  PIN B
    DIRECTION INPUT ;
    USE SIGNAL ;
    PORT
      LAYER metal1 ;
        RECT 1.9600 0.7350 2.0300 0.9450 ;
        RECT 1.9600 0.7350 2.1250 0.8050 ;
    END
  END B
  PIN Y
    DIRECTION OUTPUT ;
    USE SIGNAL ;
    PORT
      LAYER metal1 ;
        RECT 0.3450 0.7350 0.4150 1.0850 ;
        RECT 0.4400 1.0150 0.5100 1.2250 ;
        RECT 0.3450 0.3150 0.6050 0.3850 ;
        RECT 0.3450 1.0150 0.5100 1.0850 ;
      LAYER via1 ;
        RECT 0.3475 0.3175 0.4125 0.3825 ;
        RECT 0.3475 0.7375 0.4125 0.8025 ;
      LAYER metal2 ;
        RECT 0.3450 0.3150 0.4150 0.8050 ;
        RECT 0.3450 0.3150 0.5100 0.3850 ;
    END
  END Y
  PIN VDD
    DIRECTION INOUT ;
    USE POWER ;
    SHAPE ABUTMENT ;
    PORT
      LAYER metal1 ;
        RECT 0.0000 1.3150 2.4700 1.4850 ;
        RECT 0.2500 1.1550 0.3200 1.3650 ;
        RECT 0.6300 1.1550 0.7000 1.3650 ;
        RECT 1.7700 1.1550 1.8400 1.3650 ;
        RECT 2.1500 1.1550 2.2200 1.3650 ;
    END
  END VDD
  PIN VSS
    DIRECTION INOUT ;
    USE GROUND ;
    SHAPE ABUTMENT ;
    PORT
      LAYER metal1 ;
        RECT 0.0000 -0.0850 2.4700 0.0850 ;
        RECT 0.2500 0.0350 0.3200 0.2450 ;
        RECT 1.3900 0.0350 1.4600 0.2450 ;
        RECT 1.9600 0.0350 2.0300 0.2450 ;
        RECT 2.3400 0.0350 2.4100 0.2450 ;
    END
  END VSS
  OBS
    LAYER metal1 ;
      RECT 0.0600 0.2450 0.1300 0.5250 ;
      RECT 0.0600 0.8050 0.1300 1.0850 ;
      RECT 0.0600 0.4550 0.8900 0.5250 ;
      RECT 2.1500 0.2450 2.2200 0.6650 ;
      RECT 2.3400 0.4550 2.4100 1.0850 ;
      RECT 2.1500 0.4550 2.4100 0.5250 ;
      RECT 1.4850 0.5950 2.2200 0.6650 ;
      RECT 0.5350 0.7350 0.6050 0.9450 ;
      RECT 1.0100 0.8750 1.0800 1.0850 ;
      RECT 1.1050 0.4550 1.1750 0.9450 ;
      RECT 1.3900 0.8750 1.4600 1.0850 ;
      RECT 1.0100 0.4550 1.6500 0.5250 ;
      RECT 0.5350 0.8750 1.4600 0.9450 ;
      RECT 1.5800 1.0150 1.6500 1.2250 ;
      RECT 1.5800 1.0150 2.0300 1.0850 ;
      RECT 0.8200 1.1550 1.6500 1.2250 ;
    LAYER via1 ;
      RECT 0.0625 0.4575 0.1275 0.5225 ;
      RECT 0.0625 0.8075 0.1275 0.8725 ;
    LAYER metal2 ;
      RECT 0.0600 0.4550 0.1300 0.8750 ;
  END
END XNOR2_X2

MACRO AOI21_X1
  CLASS CORE ;
  ORIGIN 0 0 ;
  FOREIGN AOI21_X1 0 0 ;
  SIZE 1.33 BY 1.40 ;
  SYMMETRY X Y ;
  SITE core ;
  PIN A1
    DIRECTION INPUT ;
    USE SIGNAL ;
    PORT
      LAYER metal1 ;
        RECT 0.8200 0.5250 0.8900 0.9450 ;
        RECT 0.1550 0.7350 0.4150 0.8050 ;
        RECT 0.7250 0.8050 0.8900 0.8750 ;
      LAYER via1 ;
        RECT 0.3475 0.7375 0.4125 0.8025 ;
        RECT 0.8225 0.5275 0.8875 0.5925 ;
      LAYER metal2 ;
        RECT 0.4400 0.5250 0.5100 0.8050 ;
        RECT 0.4400 0.5250 0.8900 0.5950 ;
        RECT 0.3450 0.7350 0.5100 0.8050 ;
    END
  END A1
  PIN A2
    DIRECTION INPUT ;
    USE SIGNAL ;
    PORT
      LAYER metal1 ;
        RECT 1.2000 0.1750 1.2700 0.3850 ;
    END
  END A2
  PIN B
    DIRECTION INPUT ;
    USE SIGNAL ;
    PORT
      LAYER metal1 ;
        RECT 0.2500 0.3850 0.3200 0.5950 ;
        RECT 0.2500 0.4550 0.4150 0.5250 ;
    END
  END B
  PIN Y
    DIRECTION OUTPUT ;
    USE SIGNAL ;
    PORT
      LAYER metal1 ;
        RECT 0.4400 0.8750 0.5100 1.0850 ;
        RECT 0.5350 0.4550 0.6050 0.9450 ;
        RECT 0.6300 0.1750 0.7000 0.5250 ;
        RECT 0.4400 0.1750 0.7000 0.2450 ;
        RECT 0.5350 0.4550 0.7000 0.5250 ;
        RECT 0.4400 0.8750 0.6050 0.9450 ;
    END
  END Y
  PIN VDD
    DIRECTION INOUT ;
    USE POWER ;
    SHAPE ABUTMENT ;
    PORT
      LAYER metal1 ;
        RECT 0.0000 1.3150 1.3300 1.4850 ;
        RECT 0.0600 1.1550 0.1300 1.3650 ;
        RECT 0.8200 1.1550 0.8900 1.3650 ;
        RECT 1.2000 1.1550 1.2700 1.3650 ;
    END
  END VDD
  PIN VSS
    DIRECTION INOUT ;
    USE GROUND ;
    SHAPE ABUTMENT ;
    PORT
      LAYER metal1 ;
        RECT 0.0000 -0.0850 1.3300 0.0850 ;
        RECT 0.2500 0.0350 0.3200 0.2450 ;
        RECT 1.0100 0.0350 1.0800 0.2450 ;
    END
  END VSS
  OBS
    LAYER metal1 ;
      RECT 0.6300 1.0150 0.7000 1.2250 ;
      RECT 0.6300 1.0150 1.0800 1.0850 ;
      RECT 0.2500 1.1550 0.7000 1.2250 ;
  END
END AOI21_X1

MACRO AOI21_X2
  CLASS CORE ;
  ORIGIN 0 0 ;
  FOREIGN AOI21_X2 0 0 ;
  SIZE 1.90 BY 1.40 ;
  SYMMETRY X Y ;
  SITE core ;
  PIN A1
    DIRECTION INPUT ;
    USE SIGNAL ;
    PORT
      LAYER metal1 ;
        RECT 1.0100 0.5950 1.0800 0.8050 ;
        RECT 0.9150 0.6650 1.0800 0.7350 ;
    END
  END A1
  PIN A2
    DIRECTION INPUT ;
    USE SIGNAL ;
    PORT
      LAYER metal1 ;
        RECT 0.0600 0.1750 0.1300 0.3850 ;
    END
  END A2
  PIN B
    DIRECTION INPUT ;
    USE SIGNAL ;
    PORT
      LAYER metal1 ;
        RECT 1.5800 0.1750 1.6500 0.3850 ;
    END
  END B
  PIN Y
    DIRECTION OUTPUT ;
    USE SIGNAL ;
    PORT
      LAYER metal1 ;
        RECT 0.8200 0.1750 0.8900 0.3850 ;
        RECT 1.2000 0.1750 1.2700 0.6650 ;
        RECT 1.2950 0.5950 1.3650 0.8050 ;
        RECT 1.7700 0.7350 1.8400 1.0850 ;
        RECT 0.8200 0.1750 1.2700 0.2450 ;
        RECT 1.2000 0.5950 1.3650 0.6650 ;
        RECT 1.2950 0.7350 1.8400 0.8050 ;
        RECT 1.3900 1.0150 1.8400 1.0850 ;
    END
  END Y
  PIN VDD
    DIRECTION INOUT ;
    USE POWER ;
    SHAPE ABUTMENT ;
    PORT
      LAYER metal1 ;
        RECT 0.0000 1.3150 1.9000 1.4850 ;
        RECT 0.2500 1.1550 0.3200 1.3650 ;
        RECT 0.6300 1.1550 0.7000 1.3650 ;
        RECT 1.0100 1.1550 1.0800 1.3650 ;
    END
  END VDD
  PIN VSS
    DIRECTION INOUT ;
    USE GROUND ;
    SHAPE ABUTMENT ;
    PORT
      LAYER metal1 ;
        RECT 0.0000 -0.0850 1.9000 0.0850 ;
        RECT 0.2500 0.0350 0.3200 0.2450 ;
        RECT 0.6300 0.0350 0.7000 0.2450 ;
        RECT 1.3900 0.0350 1.4600 0.2450 ;
    END
  END VSS
  OBS
    LAYER metal1 ;
      RECT 0.4400 0.4550 1.0800 0.5250 ;
      RECT 0.0600 0.8750 1.6500 0.9450 ;
  END
END AOI21_X2

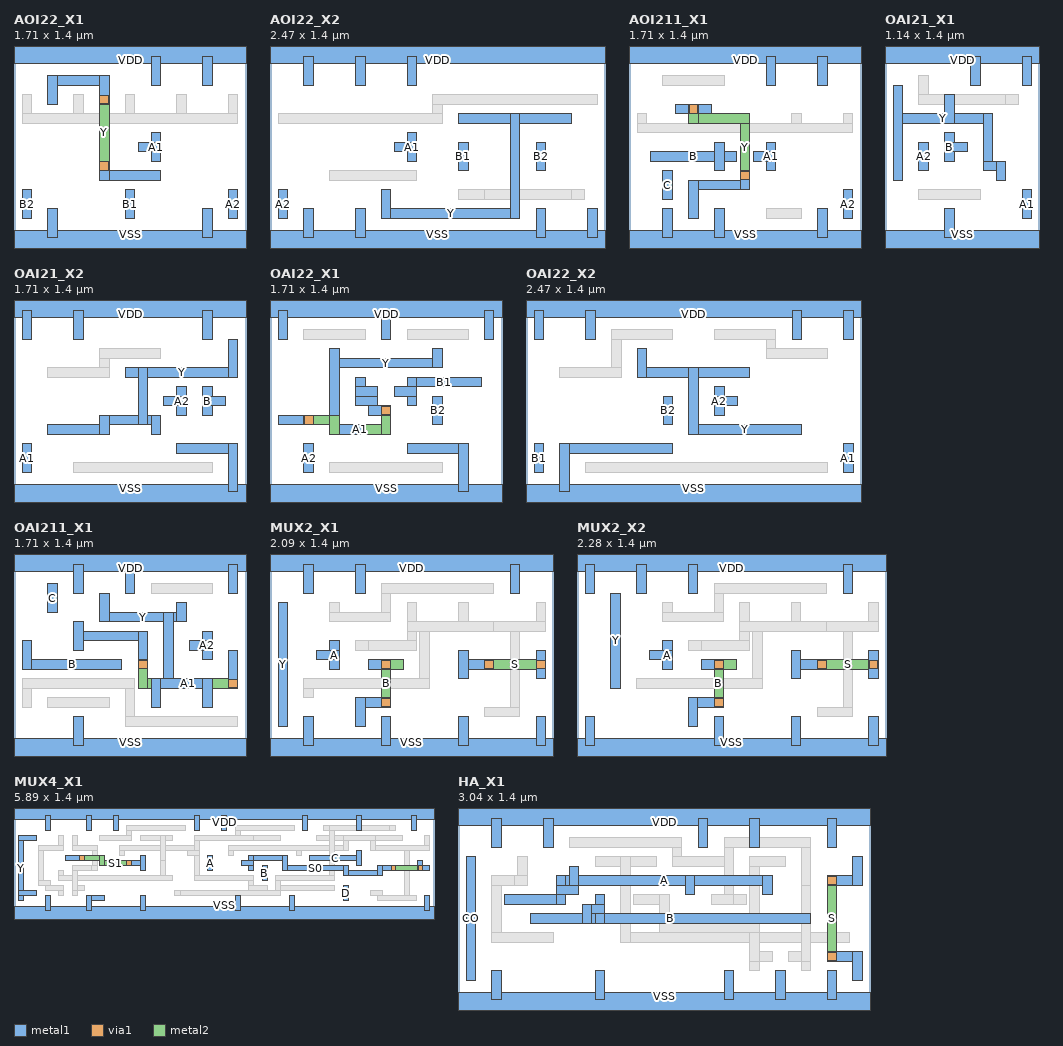
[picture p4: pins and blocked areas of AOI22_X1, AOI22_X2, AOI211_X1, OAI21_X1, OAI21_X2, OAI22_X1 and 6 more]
MACRO AOI22_X1
  CLASS CORE ;
  ORIGIN 0 0 ;
  FOREIGN AOI22_X1 0 0 ;
  SIZE 1.71 BY 1.40 ;
  SYMMETRY X Y ;
  SITE core ;
  PIN A1
    DIRECTION INPUT ;
    USE SIGNAL ;
    PORT
      LAYER metal1 ;
        RECT 1.0100 0.5950 1.0800 0.8050 ;
        RECT 0.9150 0.6650 1.0800 0.7350 ;
    END
  END A1
  PIN A2
    DIRECTION INPUT ;
    USE SIGNAL ;
    PORT
      LAYER metal1 ;
        RECT 1.5800 0.1750 1.6500 0.3850 ;
    END
  END A2
  PIN B1
    DIRECTION INPUT ;
    USE SIGNAL ;
    PORT
      LAYER metal1 ;
        RECT 0.8200 0.1750 0.8900 0.3850 ;
    END
  END B1
  PIN B2
    DIRECTION INPUT ;
    USE SIGNAL ;
    PORT
      LAYER metal1 ;
        RECT 0.0600 0.1750 0.1300 0.3850 ;
    END
  END B2
  PIN Y
    DIRECTION OUTPUT ;
    USE SIGNAL ;
    PORT
      LAYER metal1 ;
        RECT 0.2500 1.0150 0.3200 1.2250 ;
        RECT 0.6300 0.4550 0.7000 0.5950 ;
        RECT 0.6300 1.0150 0.7000 1.2250 ;
        RECT 0.6300 0.4550 1.0800 0.5250 ;
        RECT 0.2500 1.1550 0.7000 1.2250 ;
      LAYER via1 ;
        RECT 0.6325 0.5275 0.6975 0.5925 ;
        RECT 0.6325 1.0175 0.6975 1.0825 ;
      LAYER metal2 ;
        RECT 0.6300 0.5250 0.7000 1.0850 ;
    END
  END Y
  PIN VDD
    DIRECTION INOUT ;
    USE POWER ;
    SHAPE ABUTMENT ;
    PORT
      LAYER metal1 ;
        RECT 0.0000 1.3150 1.7100 1.4850 ;
        RECT 1.0100 1.1550 1.0800 1.3650 ;
        RECT 1.3900 1.1550 1.4600 1.3650 ;
    END
  END VDD
  PIN VSS
    DIRECTION INOUT ;
    USE GROUND ;
    SHAPE ABUTMENT ;
    PORT
      LAYER metal1 ;
        RECT 0.0000 -0.0850 1.7100 0.0850 ;
        RECT 0.2500 0.0350 0.3200 0.2450 ;
        RECT 1.3900 0.0350 1.4600 0.2450 ;
    END
  END VSS
  OBS
    LAYER metal1 ;
      RECT 0.0600 0.8750 0.1300 1.0850 ;
      RECT 0.4400 0.8750 0.5100 1.0850 ;
      RECT 0.8200 0.8750 0.8900 1.0850 ;
      RECT 1.2000 0.8750 1.2700 1.0850 ;
      RECT 1.5800 0.8750 1.6500 1.0850 ;
      RECT 0.0600 0.8750 1.6500 0.9450 ;
  END
END AOI22_X1

MACRO AOI22_X2
  CLASS CORE ;
  ORIGIN 0 0 ;
  FOREIGN AOI22_X2 0 0 ;
  SIZE 2.47 BY 1.40 ;
  SYMMETRY X Y ;
  SITE core ;
  PIN A1
    DIRECTION INPUT ;
    USE SIGNAL ;
    PORT
      LAYER metal1 ;
        RECT 1.0100 0.5950 1.0800 0.8050 ;
        RECT 0.9150 0.6650 1.0800 0.7350 ;
    END
  END A1
  PIN A2
    DIRECTION INPUT ;
    USE SIGNAL ;
    PORT
      LAYER metal1 ;
        RECT 0.0600 0.1750 0.1300 0.3850 ;
    END
  END A2
  PIN B1
    DIRECTION INPUT ;
    USE SIGNAL ;
    PORT
      LAYER metal1 ;
        RECT 1.3900 0.5250 1.4600 0.7350 ;
    END
  END B1
  PIN B2
    DIRECTION INPUT ;
    USE SIGNAL ;
    PORT
      LAYER metal1 ;
        RECT 1.9600 0.5250 2.0300 0.7350 ;
    END
  END B2
  PIN Y
    DIRECTION OUTPUT ;
    USE SIGNAL ;
    PORT
      LAYER metal1 ;
        RECT 0.8200 0.1750 0.8900 0.3850 ;
        RECT 1.7700 0.1750 1.8400 0.9450 ;
        RECT 0.8200 0.1750 1.8400 0.2450 ;
        RECT 1.3900 0.8750 2.2200 0.9450 ;
    END
  END Y
  PIN VDD
    DIRECTION INOUT ;
    USE POWER ;
    SHAPE ABUTMENT ;
    PORT
      LAYER metal1 ;
        RECT 0.0000 1.3150 2.4700 1.4850 ;
        RECT 0.2500 1.1550 0.3200 1.3650 ;
        RECT 0.6300 1.1550 0.7000 1.3650 ;
        RECT 1.0100 1.1550 1.0800 1.3650 ;
    END
  END VDD
  PIN VSS
    DIRECTION INOUT ;
    USE GROUND ;
    SHAPE ABUTMENT ;
    PORT
      LAYER metal1 ;
        RECT 0.0000 -0.0850 2.4700 0.0850 ;
        RECT 0.2500 0.0350 0.3200 0.2450 ;
        RECT 0.6300 0.0350 0.7000 0.2450 ;
        RECT 1.9600 0.0350 2.0300 0.2450 ;
        RECT 2.3400 0.0350 2.4100 0.2450 ;
    END
  END VSS
  OBS
    LAYER metal1 ;
      RECT 0.4400 0.4550 1.0800 0.5250 ;
      RECT 1.3900 0.3150 1.6500 0.3850 ;
      RECT 2.0550 0.3150 2.3150 0.3850 ;
      RECT 1.2000 0.8750 1.2700 1.0850 ;
      RECT 0.0600 0.8750 1.2700 0.9450 ;
      RECT 1.2000 1.0150 2.4100 1.0850 ;
    LAYER via1 ;
      RECT 1.5825 0.3175 1.6475 0.3825 ;
      RECT 2.0575 0.3175 2.1225 0.3825 ;
    LAYER metal2 ;
      RECT 1.5800 0.3150 2.2200 0.3850 ;
  END
END AOI22_X2

MACRO AOI211_X1
  CLASS CORE ;
  ORIGIN 0 0 ;
  FOREIGN AOI211_X1 0 0 ;
  SIZE 1.71 BY 1.40 ;
  SYMMETRY X Y ;
  SITE core ;
  PIN A1
    DIRECTION INPUT ;
    USE SIGNAL ;
    PORT
      LAYER metal1 ;
        RECT 1.0100 0.5250 1.0800 0.7350 ;
        RECT 0.9150 0.5950 1.0800 0.6650 ;
    END
  END A1
  PIN A2
    DIRECTION INPUT ;
    USE SIGNAL ;
    PORT
      LAYER metal1 ;
        RECT 1.5800 0.1750 1.6500 0.3850 ;
    END
  END A2
  PIN B
    DIRECTION INPUT ;
    USE SIGNAL ;
    PORT
      LAYER metal1 ;
        RECT 0.6300 0.5250 0.7000 0.7350 ;
        RECT 0.1550 0.5950 0.7950 0.6650 ;
    END
  END B
  PIN C
    DIRECTION INPUT ;
    USE SIGNAL ;
    PORT
      LAYER metal1 ;
        RECT 0.2500 0.3150 0.3200 0.5250 ;
    END
  END C
  PIN Y
    DIRECTION OUTPUT ;
    USE SIGNAL ;
    PORT
      LAYER metal1 ;
        RECT 0.4400 0.1750 0.5100 0.4550 ;
        RECT 0.8200 0.3850 0.8900 0.5250 ;
        RECT 0.4400 0.3850 0.8900 0.4550 ;
        RECT 0.3450 0.9450 0.6050 1.0150 ;
      LAYER via1 ;
        RECT 0.4425 0.9475 0.5075 1.0125 ;
        RECT 0.8225 0.4575 0.8875 0.5225 ;
      LAYER metal2 ;
        RECT 0.4400 0.8750 0.5100 1.0150 ;
        RECT 0.8200 0.4550 0.8900 0.9450 ;
        RECT 0.4400 0.8750 0.8900 0.9450 ;
    END
  END Y
  PIN VDD
    DIRECTION INOUT ;
    USE POWER ;
    SHAPE ABUTMENT ;
    PORT
      LAYER metal1 ;
        RECT 0.0000 1.3150 1.7100 1.4850 ;
        RECT 1.0100 1.1550 1.0800 1.3650 ;
        RECT 1.3900 1.1550 1.4600 1.3650 ;
    END
  END VDD
  PIN VSS
    DIRECTION INOUT ;
    USE GROUND ;
    SHAPE ABUTMENT ;
    PORT
      LAYER metal1 ;
        RECT 0.0000 -0.0850 1.7100 0.0850 ;
        RECT 0.2500 0.0350 0.3200 0.2450 ;
        RECT 0.6300 0.0350 0.7000 0.2450 ;
        RECT 1.3900 0.0350 1.4600 0.2450 ;
    END
  END VSS
  OBS
    LAYER metal1 ;
      RECT 1.0100 0.1750 1.2700 0.2450 ;
      RECT 0.0600 0.8050 0.1300 0.9450 ;
      RECT 0.8200 0.8050 0.8900 0.9450 ;
      RECT 1.2000 0.8050 1.2700 0.9450 ;
      RECT 1.5800 0.8050 1.6500 0.9450 ;
      RECT 0.0600 0.8050 1.6500 0.8750 ;
      RECT 0.2500 1.1550 0.7000 1.2250 ;
  END
END AOI211_X1

MACRO OAI21_X1
  CLASS CORE ;
  ORIGIN 0 0 ;
  FOREIGN OAI21_X1 0 0 ;
  SIZE 1.14 BY 1.40 ;
  SYMMETRY X Y ;
  SITE core ;
  PIN A1
    DIRECTION INPUT ;
    USE SIGNAL ;
    PORT
      LAYER metal1 ;
        RECT 1.0100 0.1750 1.0800 0.3850 ;
    END
  END A1
  PIN A2
    DIRECTION INPUT ;
    USE SIGNAL ;
    PORT
      LAYER metal1 ;
        RECT 0.2500 0.5250 0.3200 0.7350 ;
    END
  END A2
  PIN B
    DIRECTION INPUT ;
    USE SIGNAL ;
    PORT
      LAYER metal1 ;
        RECT 0.4400 0.5950 0.5100 0.8050 ;
        RECT 0.4400 0.6650 0.6050 0.7350 ;
    END
  END B
  PIN Y
    DIRECTION OUTPUT ;
    USE SIGNAL ;
    PORT
      LAYER metal1 ;
        RECT 0.0600 0.4550 0.1300 1.1550 ;
        RECT 0.4400 0.8750 0.5100 1.0850 ;
        RECT 0.7250 0.5250 0.7950 0.9450 ;
        RECT 0.8200 0.4550 0.8900 0.5950 ;
        RECT 0.7250 0.5250 0.8900 0.5950 ;
        RECT 0.0600 0.8750 0.7950 0.9450 ;
    END
  END Y
  PIN VDD
    DIRECTION INOUT ;
    USE POWER ;
    SHAPE ABUTMENT ;
    PORT
      LAYER metal1 ;
        RECT 0.0000 1.3150 1.1400 1.4850 ;
        RECT 0.6300 1.1550 0.7000 1.3650 ;
        RECT 1.0100 1.1550 1.0800 1.3650 ;
    END
  END VDD
  PIN VSS
    DIRECTION INOUT ;
    USE GROUND ;
    SHAPE ABUTMENT ;
    PORT
      LAYER metal1 ;
        RECT 0.0000 -0.0850 1.1400 0.0850 ;
        RECT 0.4400 0.0350 0.5100 0.2450 ;
    END
  END VSS
  OBS
    LAYER metal1 ;
      RECT 0.2500 0.3150 0.7000 0.3850 ;
      RECT 0.2500 1.0150 0.3200 1.2250 ;
      RECT 0.7250 1.0150 0.9850 1.0850 ;
    LAYER via1 ;
      RECT 0.2525 1.0175 0.3175 1.0825 ;
      RECT 0.7275 1.0175 0.7925 1.0825 ;
    LAYER metal2 ;
      RECT 0.2500 1.0150 0.8900 1.0850 ;
  END
END OAI21_X1

MACRO OAI21_X2
  CLASS CORE ;
  ORIGIN 0 0 ;
  FOREIGN OAI21_X2 0 0 ;
  SIZE 1.71 BY 1.40 ;
  SYMMETRY X Y ;
  SITE core ;
  PIN A1
    DIRECTION INPUT ;
    USE SIGNAL ;
    PORT
      LAYER metal1 ;
        RECT 0.0600 0.1750 0.1300 0.3850 ;
    END
  END A1
  PIN A2
    DIRECTION INPUT ;
    USE SIGNAL ;
    PORT
      LAYER metal1 ;
        RECT 1.2000 0.5950 1.2700 0.8050 ;
        RECT 1.1050 0.6650 1.2700 0.7350 ;
    END
  END A2
  PIN B
    DIRECTION INPUT ;
    USE SIGNAL ;
    PORT
      LAYER metal1 ;
        RECT 1.3900 0.5950 1.4600 0.8050 ;
        RECT 1.3900 0.6650 1.5550 0.7350 ;
    END
  END B
  PIN Y
    DIRECTION OUTPUT ;
    USE SIGNAL ;
    PORT
      LAYER metal1 ;
        RECT 0.6300 0.4550 0.7000 0.5950 ;
        RECT 0.9150 0.5250 0.9850 0.9450 ;
        RECT 1.0100 0.4550 1.0800 0.5950 ;
        RECT 1.5800 0.8750 1.6500 1.1550 ;
        RECT 0.2500 0.4550 0.7000 0.5250 ;
        RECT 0.6300 0.5250 1.0800 0.5950 ;
        RECT 0.8200 0.8750 1.6500 0.9450 ;
    END
  END Y
  PIN VDD
    DIRECTION INOUT ;
    USE POWER ;
    SHAPE ABUTMENT ;
    PORT
      LAYER metal1 ;
        RECT 0.0000 1.3150 1.7100 1.4850 ;
        RECT 0.0600 1.1550 0.1300 1.3650 ;
        RECT 0.4400 1.1550 0.5100 1.3650 ;
        RECT 1.3900 1.1550 1.4600 1.3650 ;
    END
  END VDD
  PIN VSS
    DIRECTION INOUT ;
    USE GROUND ;
    SHAPE ABUTMENT ;
    PORT
      LAYER metal1 ;
        RECT 0.0000 -0.0850 1.7100 0.0850 ;
        RECT 1.5800 0.0350 1.6500 0.3850 ;
        RECT 1.2000 0.3150 1.6500 0.3850 ;
    END
  END VSS
  OBS
    LAYER metal1 ;
      RECT 0.4400 0.1750 1.4600 0.2450 ;
      RECT 0.6300 0.8750 0.7000 1.0850 ;
      RECT 0.2500 0.8750 0.7000 0.9450 ;
      RECT 0.6300 1.0150 1.0800 1.0850 ;
  END
END OAI21_X2

MACRO OAI22_X1
  CLASS CORE ;
  ORIGIN 0 0 ;
  FOREIGN OAI22_X1 0 0 ;
  SIZE 1.71 BY 1.40 ;
  SYMMETRY X Y ;
  SITE core ;
  PIN A1
    DIRECTION INPUT ;
    USE SIGNAL ;
    PORT
      LAYER metal1 ;
        RECT 0.6300 0.6650 0.7000 0.8750 ;
        RECT 0.7250 0.5950 0.7950 0.8050 ;
        RECT 0.0600 0.5250 0.3200 0.5950 ;
        RECT 0.7250 0.5950 0.8900 0.6650 ;
        RECT 0.6300 0.6650 0.7950 0.7350 ;
        RECT 0.6300 0.7350 0.7950 0.8050 ;
      LAYER via1 ;
        RECT 0.2525 0.5275 0.3175 0.5925 ;
        RECT 0.8225 0.5975 0.8875 0.6625 ;
      LAYER metal2 ;
        RECT 0.4400 0.4550 0.5100 0.5950 ;
        RECT 0.8200 0.4550 0.8900 0.6650 ;
        RECT 0.4400 0.4550 0.8900 0.5250 ;
        RECT 0.2500 0.5250 0.5100 0.5950 ;
    END
  END A1
  PIN A2
    DIRECTION INPUT ;
    USE SIGNAL ;
    PORT
      LAYER metal1 ;
        RECT 0.2500 0.1750 0.3200 0.3850 ;
    END
  END A2
  PIN B1
    DIRECTION INPUT ;
    USE SIGNAL ;
    PORT
      LAYER metal1 ;
        RECT 1.0100 0.6650 1.0800 0.8750 ;
        RECT 0.9150 0.7350 1.0800 0.8050 ;
        RECT 1.0100 0.8050 1.5550 0.8750 ;
    END
  END B1
  PIN B2
    DIRECTION INPUT ;
    USE SIGNAL ;
    PORT
      LAYER metal1 ;
        RECT 1.2000 0.5250 1.2700 0.7350 ;
    END
  END B2
  PIN Y
    DIRECTION OUTPUT ;
    USE SIGNAL ;
    PORT
      LAYER metal1 ;
        RECT 0.4400 0.4550 0.5100 1.0850 ;
        RECT 1.2000 0.9450 1.2700 1.0850 ;
        RECT 0.4400 0.4550 0.7000 0.5250 ;
        RECT 0.4400 0.9450 1.2700 1.0150 ;
    END
  END Y
  PIN VDD
    DIRECTION INOUT ;
    USE POWER ;
    SHAPE ABUTMENT ;
    PORT
      LAYER metal1 ;
        RECT 0.0000 1.3150 1.7100 1.4850 ;
        RECT 0.0600 1.1550 0.1300 1.3650 ;
        RECT 0.8200 1.1550 0.8900 1.3650 ;
        RECT 1.5800 1.1550 1.6500 1.3650 ;
    END
  END VDD
  PIN VSS
    DIRECTION INOUT ;
    USE GROUND ;
    SHAPE ABUTMENT ;
    PORT
      LAYER metal1 ;
        RECT 0.0000 -0.0850 1.7100 0.0850 ;
        RECT 1.3900 0.0350 1.4600 0.3850 ;
        RECT 1.0100 0.3150 1.4600 0.3850 ;
    END
  END VSS
  OBS
    LAYER metal1 ;
      RECT 0.4400 0.1750 1.2700 0.2450 ;
      RECT 0.2500 1.1550 0.7000 1.2250 ;
      RECT 1.0100 1.1550 1.4600 1.2250 ;
  END
END OAI22_X1

MACRO OAI22_X2
  CLASS CORE ;
  ORIGIN 0 0 ;
  FOREIGN OAI22_X2 0 0 ;
  SIZE 2.47 BY 1.40 ;
  SYMMETRY X Y ;
  SITE core ;
  PIN A1
    DIRECTION INPUT ;
    USE SIGNAL ;
    PORT
      LAYER metal1 ;
        RECT 2.3400 0.1750 2.4100 0.3850 ;
    END
  END A1
  PIN A2
    DIRECTION INPUT ;
    USE SIGNAL ;
    PORT
      LAYER metal1 ;
        RECT 1.3900 0.5950 1.4600 0.8050 ;
        RECT 1.3900 0.6650 1.5550 0.7350 ;
    END
  END A2
  PIN B1
    DIRECTION INPUT ;
    USE SIGNAL ;
    PORT
      LAYER metal1 ;
        RECT 0.0600 0.1750 0.1300 0.3850 ;
    END
  END B1
  PIN B2
    DIRECTION INPUT ;
    USE SIGNAL ;
    PORT
      LAYER metal1 ;
        RECT 1.0100 0.5250 1.0800 0.7350 ;
    END
  END B2
  PIN Y
    DIRECTION OUTPUT ;
    USE SIGNAL ;
    PORT
      LAYER metal1 ;
        RECT 0.8200 0.8750 0.8900 1.0850 ;
        RECT 1.2000 0.4550 1.2700 0.9450 ;
        RECT 1.2000 0.4550 2.0300 0.5250 ;
        RECT 0.8200 0.8750 1.6500 0.9450 ;
    END
  END Y
  PIN VDD
    DIRECTION INOUT ;
    USE POWER ;
    SHAPE ABUTMENT ;
    PORT
      LAYER metal1 ;
        RECT 0.0000 1.3150 2.4700 1.4850 ;
        RECT 0.0600 1.1550 0.1300 1.3650 ;
        RECT 0.4400 1.1550 0.5100 1.3650 ;
        RECT 1.9600 1.1550 2.0300 1.3650 ;
        RECT 2.3400 1.1550 2.4100 1.3650 ;
    END
  END VDD
  PIN VSS
    DIRECTION INOUT ;
    USE GROUND ;
    SHAPE ABUTMENT ;
    PORT
      LAYER metal1 ;
        RECT 0.0000 -0.0850 2.4700 0.0850 ;
        RECT 0.2500 0.0350 0.3200 0.3850 ;
        RECT 0.2500 0.3150 1.0800 0.3850 ;
    END
  END VSS
  OBS
    LAYER metal1 ;
      RECT 0.4400 0.1750 2.2200 0.2450 ;
      RECT 1.7700 1.0150 1.8400 1.2250 ;
      RECT 1.7700 1.0150 2.2200 1.0850 ;
      RECT 1.3900 1.1550 1.8400 1.2250 ;
      RECT 0.6300 0.8750 0.7000 1.2250 ;
      RECT 0.2500 0.8750 0.7000 0.9450 ;
      RECT 0.6300 1.1550 1.0800 1.2250 ;
  END
END OAI22_X2

MACRO OAI211_X1
  CLASS CORE ;
  ORIGIN 0 0 ;
  FOREIGN OAI211_X1 0 0 ;
  SIZE 1.71 BY 1.40 ;
  SYMMETRY X Y ;
  SITE core ;
  PIN A1
    DIRECTION INPUT ;
    USE SIGNAL ;
    PORT
      LAYER metal1 ;
        RECT 0.4400 0.7350 0.5100 0.9450 ;
        RECT 0.9150 0.5950 0.9850 0.8750 ;
        RECT 1.5800 0.4550 1.6500 0.7350 ;
        RECT 0.4400 0.8050 0.9850 0.8750 ;
      LAYER via1 ;
        RECT 0.9175 0.5975 0.9825 0.6625 ;
        RECT 1.5825 0.4575 1.6475 0.5225 ;
      LAYER metal2 ;
        RECT 0.9150 0.4550 0.9850 0.6650 ;
        RECT 0.9150 0.4550 1.6500 0.5250 ;
    END
  END A1
  PIN A2
    DIRECTION INPUT ;
    USE SIGNAL ;
    PORT
      LAYER metal1 ;
        RECT 1.3900 0.6650 1.4600 0.8750 ;
        RECT 1.2950 0.7350 1.4600 0.8050 ;
    END
  END A2
  PIN B
    DIRECTION INPUT ;
    USE SIGNAL ;
    PORT
      LAYER metal1 ;
        RECT 0.0600 0.5950 0.1300 0.8050 ;
        RECT 0.0600 0.5950 0.7950 0.6650 ;
    END
  END B
  PIN C
    DIRECTION INPUT ;
    USE SIGNAL ;
    PORT
      LAYER metal1 ;
        RECT 0.2500 1.0150 0.3200 1.2250 ;
    END
  END C
  PIN Y
    DIRECTION OUTPUT ;
    USE SIGNAL ;
    PORT
      LAYER metal1 ;
        RECT 0.6300 0.9450 0.7000 1.1550 ;
        RECT 1.0100 0.3150 1.0800 0.5250 ;
        RECT 1.1050 0.4550 1.1750 1.0150 ;
        RECT 1.2000 0.9450 1.2700 1.0850 ;
        RECT 1.3900 0.3150 1.4600 0.5250 ;
        RECT 1.0100 0.4550 1.4600 0.5250 ;
        RECT 0.6300 0.9450 1.2700 1.0150 ;
    END
  END Y
  PIN VDD
    DIRECTION INOUT ;
    USE POWER ;
    SHAPE ABUTMENT ;
    PORT
      LAYER metal1 ;
        RECT 0.0000 1.3150 1.7100 1.4850 ;
        RECT 0.4400 1.1550 0.5100 1.3650 ;
        RECT 0.8200 1.1550 0.8900 1.3650 ;
        RECT 1.5800 1.1550 1.6500 1.3650 ;
    END
  END VDD
  PIN VSS
    DIRECTION INOUT ;
    USE GROUND ;
    SHAPE ABUTMENT ;
    PORT
      LAYER metal1 ;
        RECT 0.0000 -0.0850 1.7100 0.0850 ;
        RECT 0.4400 0.0350 0.5100 0.2450 ;
    END
  END VSS
  OBS
    LAYER metal1 ;
      RECT 0.0600 0.3150 0.1300 0.5250 ;
      RECT 0.8200 0.1750 0.8900 0.5250 ;
      RECT 0.8200 0.1750 1.6500 0.2450 ;
      RECT 0.0600 0.4550 0.8900 0.5250 ;
      RECT 0.2500 0.3150 0.7000 0.3850 ;
      RECT 1.0100 1.1550 1.4600 1.2250 ;
  END
END OAI211_X1

MACRO MUX2_X1
  CLASS CORE ;
  ORIGIN 0 0 ;
  FOREIGN MUX2_X1 0 0 ;
  SIZE 2.09 BY 1.40 ;
  SYMMETRY X Y ;
  SITE core ;
  PIN A
    DIRECTION INPUT ;
    USE SIGNAL ;
    PORT
      LAYER metal1 ;
        RECT 0.4400 0.5950 0.5100 0.8050 ;
        RECT 0.3450 0.6650 0.5100 0.7350 ;
    END
  END A
  PIN B
    DIRECTION INPUT ;
    USE SIGNAL ;
    PORT
      LAYER metal1 ;
        RECT 0.6300 0.1750 0.7000 0.3850 ;
        RECT 0.6300 0.3150 0.8900 0.3850 ;
        RECT 0.7250 0.5950 0.9850 0.6650 ;
      LAYER via1 ;
        RECT 0.8225 0.3175 0.8875 0.3825 ;
        RECT 0.8225 0.5975 0.8875 0.6625 ;
      LAYER metal2 ;
        RECT 0.8200 0.3150 0.8900 0.6650 ;
        RECT 0.8200 0.5950 0.9850 0.6650 ;
    END
  END B
  PIN S
    DIRECTION INPUT ;
    USE SIGNAL ;
    PORT
      LAYER metal1 ;
        RECT 1.3900 0.5250 1.4600 0.7350 ;
        RECT 1.9600 0.5250 2.0300 0.7350 ;
        RECT 1.3900 0.5950 1.6500 0.6650 ;
      LAYER via1 ;
        RECT 1.5825 0.5975 1.6475 0.6625 ;
        RECT 1.9625 0.5975 2.0275 0.6625 ;
      LAYER metal2 ;
        RECT 1.5800 0.5950 2.0300 0.6650 ;
    END
  END S
  PIN Y
    DIRECTION OUTPUT ;
    USE SIGNAL ;
    PORT
      LAYER metal1 ;
        RECT 0.0600 0.1750 0.1300 1.0850 ;
    END
  END Y
  PIN VDD
    DIRECTION INOUT ;
    USE POWER ;
    SHAPE ABUTMENT ;
    PORT
      LAYER metal1 ;
        RECT 0.0000 1.3150 2.0900 1.4850 ;
        RECT 0.2500 1.1550 0.3200 1.3650 ;
        RECT 0.6300 1.1550 0.7000 1.3650 ;
        RECT 1.7700 1.1550 1.8400 1.3650 ;
    END
  END VDD
  PIN VSS
    DIRECTION INOUT ;
    USE GROUND ;
    SHAPE ABUTMENT ;
    PORT
      LAYER metal1 ;
        RECT 0.0000 -0.0850 2.0900 0.0850 ;
        RECT 0.2500 0.0350 0.3200 0.2450 ;
        RECT 0.8200 0.0350 0.8900 0.2450 ;
        RECT 1.3900 0.0350 1.4600 0.2450 ;
        RECT 1.9600 0.0350 2.0300 0.2450 ;
    END
  END VSS
  OBS
    LAYER metal1 ;
      RECT 1.7700 0.2450 1.8400 0.9450 ;
      RECT 1.9600 0.8750 2.0300 1.0850 ;
      RECT 1.5800 0.2450 1.8400 0.3150 ;
      RECT 0.6300 0.7350 0.8900 0.8050 ;
      RECT 1.5800 0.8750 2.0300 0.9450 ;
      RECT 0.2500 0.3850 0.3200 0.5250 ;
      RECT 1.0100 0.8750 1.0800 1.0850 ;
      RECT 1.1050 0.4550 1.1750 0.9450 ;
      RECT 1.3900 0.8750 1.4600 1.0850 ;
      RECT 0.2500 0.4550 1.1750 0.5250 ;
      RECT 1.0100 0.8750 1.4600 0.9450 ;
      RECT 0.4400 0.9450 0.5100 1.0850 ;
      RECT 0.8200 0.9450 0.8900 1.2250 ;
      RECT 0.4400 0.9450 0.8900 1.0150 ;
      RECT 0.8200 1.1550 1.6500 1.2250 ;
    LAYER via1 ;
      RECT 0.7275 0.7375 0.7925 0.8025 ;
      RECT 1.5825 0.8775 1.6475 0.9425 ;
    LAYER metal2 ;
      RECT 1.0100 0.7350 1.0800 0.9450 ;
      RECT 0.7250 0.7350 1.0800 0.8050 ;
      RECT 1.0100 0.8750 1.6500 0.9450 ;
  END
END MUX2_X1

MACRO MUX2_X2
  CLASS CORE ;
  ORIGIN 0 0 ;
  FOREIGN MUX2_X2 0 0 ;
  SIZE 2.28 BY 1.40 ;
  SYMMETRY X Y ;
  SITE core ;
  PIN A
    DIRECTION INPUT ;
    USE SIGNAL ;
    PORT
      LAYER metal1 ;
        RECT 0.6300 0.5950 0.7000 0.8050 ;
        RECT 0.5350 0.6650 0.7000 0.7350 ;
    END
  END A
  PIN B
    DIRECTION INPUT ;
    USE SIGNAL ;
    PORT
      LAYER metal1 ;
        RECT 0.8200 0.1750 0.8900 0.3850 ;
        RECT 0.8200 0.3150 1.0800 0.3850 ;
        RECT 0.9150 0.5950 1.1750 0.6650 ;
      LAYER via1 ;
        RECT 1.0125 0.3175 1.0775 0.3825 ;
        RECT 1.0125 0.5975 1.0775 0.6625 ;
      LAYER metal2 ;
        RECT 1.0100 0.3150 1.0800 0.6650 ;
        RECT 1.0100 0.5950 1.1750 0.6650 ;
    END
  END B
  PIN S
    DIRECTION INPUT ;
    USE SIGNAL ;
    PORT
      LAYER metal1 ;
        RECT 1.5800 0.5250 1.6500 0.7350 ;
        RECT 2.1500 0.5250 2.2200 0.7350 ;
        RECT 1.5800 0.5950 1.8400 0.6650 ;
      LAYER via1 ;
        RECT 1.7725 0.5975 1.8375 0.6625 ;
        RECT 2.1525 0.5975 2.2175 0.6625 ;
      LAYER metal2 ;
        RECT 1.7700 0.5950 2.2200 0.6650 ;
    END
  END S
  PIN Y
    DIRECTION OUTPUT ;
    USE SIGNAL ;
    PORT
      LAYER metal1 ;
        RECT 0.2500 0.4550 0.3200 1.1550 ;
    END
  END Y
  PIN VDD
    DIRECTION INOUT ;
    USE POWER ;
    SHAPE ABUTMENT ;
    PORT
      LAYER metal1 ;
        RECT 0.0000 1.3150 2.2800 1.4850 ;
        RECT 0.0600 1.1550 0.1300 1.3650 ;
        RECT 0.4400 1.1550 0.5100 1.3650 ;
        RECT 0.8200 1.1550 0.8900 1.3650 ;
        RECT 1.9600 1.1550 2.0300 1.3650 ;
    END
  END VDD
  PIN VSS
    DIRECTION INOUT ;
    USE GROUND ;
    SHAPE ABUTMENT ;
    PORT
      LAYER metal1 ;
        RECT 0.0000 -0.0850 2.2800 0.0850 ;
        RECT 0.0600 0.0350 0.1300 0.2450 ;
        RECT 1.0100 0.0350 1.0800 0.2450 ;
        RECT 1.5800 0.0350 1.6500 0.2450 ;
        RECT 2.1500 0.0350 2.2200 0.2450 ;
    END
  END VSS
  OBS
    LAYER metal1 ;
      RECT 1.9600 0.2450 2.0300 0.9450 ;
      RECT 2.1500 0.8750 2.2200 1.0850 ;
      RECT 1.7700 0.2450 2.0300 0.3150 ;
      RECT 0.8200 0.7350 1.0800 0.8050 ;
      RECT 1.7700 0.8750 2.2200 0.9450 ;
      RECT 1.2000 0.8750 1.2700 1.0850 ;
      RECT 1.2950 0.4550 1.3650 0.9450 ;
      RECT 1.5800 0.8750 1.6500 1.0850 ;
      RECT 0.4400 0.4550 1.3650 0.5250 ;
      RECT 1.2000 0.8750 1.6500 0.9450 ;
      RECT 0.6300 0.9450 0.7000 1.0850 ;
      RECT 1.0100 0.9450 1.0800 1.2250 ;
      RECT 0.6300 0.9450 1.0800 1.0150 ;
      RECT 1.0100 1.1550 1.8400 1.2250 ;
    LAYER via1 ;
      RECT 0.9175 0.7375 0.9825 0.8025 ;
      RECT 1.7725 0.8775 1.8375 0.9425 ;
    LAYER metal2 ;
      RECT 1.2000 0.7350 1.2700 0.9450 ;
      RECT 0.9150 0.7350 1.2700 0.8050 ;
      RECT 1.2000 0.8750 1.8400 0.9450 ;
  END
END MUX2_X2

MACRO MUX4_X1
  CLASS CORE ;
  ORIGIN 0 0 ;
  FOREIGN MUX4_X1 0 0 ;
  SIZE 5.89 BY 1.40 ;
  SYMMETRY X Y ;
  SITE core ;
  PIN A
    DIRECTION INPUT ;
    USE SIGNAL ;
    PORT
      LAYER metal1 ;
        RECT 2.7200 0.5950 2.7900 0.8050 ;
    END
  END A
  PIN B
    DIRECTION INPUT ;
    USE SIGNAL ;
    PORT
      LAYER metal1 ;
        RECT 3.4800 0.4550 3.5500 0.6650 ;
    END
  END B
  PIN C
    DIRECTION INPUT ;
    USE SIGNAL ;
    PORT
      LAYER metal1 ;
        RECT 4.8100 0.6650 4.8800 0.8750 ;
        RECT 4.1450 0.7350 4.8800 0.8050 ;
    END
  END C
  PIN D
    DIRECTION INPUT ;
    USE SIGNAL ;
    PORT
      LAYER metal1 ;
        RECT 4.6200 0.1750 4.6900 0.3850 ;
    END
  END D
  PIN S0
    DIRECTION INPUT ;
    USE SIGNAL ;
    PORT
      LAYER metal1 ;
        RECT 3.2900 0.5950 3.3600 0.8050 ;
        RECT 3.7650 0.5950 3.8350 0.8050 ;
        RECT 4.6200 0.5250 4.6900 0.6650 ;
        RECT 5.0950 0.5250 5.1650 0.6650 ;
        RECT 5.6650 0.5950 5.7350 0.7350 ;
        RECT 4.6200 0.5250 5.1650 0.5950 ;
        RECT 3.7650 0.5950 4.6900 0.6650 ;
        RECT 5.0950 0.5950 5.3550 0.6650 ;
        RECT 5.6650 0.5950 5.8300 0.6650 ;
        RECT 3.1950 0.6650 3.3600 0.7350 ;
        RECT 3.2900 0.7350 3.8350 0.8050 ;
      LAYER via1 ;
        RECT 5.2875 0.5975 5.3525 0.6625 ;
        RECT 5.6675 0.5975 5.7325 0.6625 ;
      LAYER metal2 ;
        RECT 5.2850 0.5950 5.7350 0.6650 ;
    END
  END S0
  PIN S1
    DIRECTION INPUT ;
    USE SIGNAL ;
    PORT
      LAYER metal1 ;
        RECT 1.7700 0.5950 1.8400 0.8050 ;
        RECT 1.5800 0.6650 1.8400 0.7350 ;
        RECT 0.7250 0.7350 0.9850 0.8050 ;
      LAYER via1 ;
        RECT 0.9175 0.7375 0.9825 0.8025 ;
        RECT 1.5825 0.6675 1.6475 0.7325 ;
      LAYER metal2 ;
        RECT 1.2000 0.6650 1.2700 0.8050 ;
        RECT 1.2000 0.6650 1.6500 0.7350 ;
        RECT 0.9150 0.7350 1.2700 0.8050 ;
    END
  END S1
  PIN Y
    DIRECTION OUTPUT ;
    USE SIGNAL ;
    PORT
      LAYER metal1 ;
        RECT 0.0600 0.1750 0.1300 1.0850 ;
        RECT 0.0600 0.2450 0.3200 0.3150 ;
        RECT 0.0600 1.0150 0.3200 1.0850 ;
    END
  END Y
  PIN VDD
    DIRECTION INOUT ;
    USE POWER ;
    SHAPE ABUTMENT ;
    PORT
      LAYER metal1 ;
        RECT 0.0000 1.3150 5.8900 1.4850 ;
        RECT 0.4400 1.1550 0.5100 1.3650 ;
        RECT 1.0100 1.1550 1.0800 1.3650 ;
        RECT 1.3900 1.1550 1.4600 1.3650 ;
        RECT 2.5300 1.1550 2.6000 1.3650 ;
        RECT 2.9100 1.1550 2.9800 1.3650 ;
        RECT 4.0500 1.1550 4.1200 1.3650 ;
        RECT 4.8100 1.1550 4.8800 1.3650 ;
        RECT 5.5700 1.1550 5.6400 1.3650 ;
    END
  END VDD
  PIN VSS
    DIRECTION INOUT ;
    USE GROUND ;
    SHAPE ABUTMENT ;
    PORT
      LAYER metal1 ;
        RECT 0.0000 -0.0850 5.8900 0.0850 ;
        RECT 0.4400 0.0350 0.5100 0.2450 ;
        RECT 1.0100 0.0350 1.0800 0.2450 ;
        RECT 1.7700 0.0350 1.8400 0.2450 ;
        RECT 3.1000 0.0350 3.1700 0.2450 ;
        RECT 3.8600 0.0350 3.9300 0.2450 ;
        RECT 5.7600 0.0350 5.8300 0.2450 ;
        RECT 1.0100 0.1750 1.2700 0.2450 ;
    END
  END VSS
  OBS
    LAYER metal1 ;
      RECT 3.0050 0.8050 3.0750 0.9450 ;
      RECT 3.9550 0.8050 4.0250 0.9450 ;
      RECT 5.0950 0.1750 5.1650 0.3150 ;
      RECT 5.4750 0.1750 5.5450 0.9450 ;
      RECT 5.7600 0.8750 5.8300 1.0850 ;
      RECT 5.0950 0.1750 5.6400 0.2450 ;
      RECT 5.0000 0.2450 5.1650 0.3150 ;
      RECT 3.0050 0.8750 4.6900 0.9450 ;
      RECT 5.0000 0.8750 5.8300 0.9450 ;
      RECT 4.2400 1.0150 5.4500 1.0850 ;
      RECT 0.6300 0.4550 0.7000 0.5950 ;
      RECT 2.0550 0.4550 2.1250 0.8050 ;
      RECT 0.6300 0.4550 2.2200 0.5250 ;
      RECT 1.7700 1.0150 2.2200 1.0850 ;
      RECT 1.5800 1.0150 1.6500 1.2250 ;
      RECT 1.2000 1.0150 1.6500 1.0850 ;
      RECT 1.5800 1.1550 2.4100 1.2250 ;
      RECT 0.3450 0.3850 0.4150 0.9450 ;
      RECT 0.4400 0.3150 0.5100 0.4550 ;
      RECT 0.6300 0.2450 0.7000 0.3850 ;
      RECT 0.6300 0.8750 0.7000 1.0850 ;
      RECT 0.4400 0.3150 0.7000 0.3850 ;
      RECT 0.3450 0.3850 0.5100 0.4550 ;
      RECT 0.3450 0.8750 0.7000 0.9450 ;
      RECT 0.8200 0.2450 0.8900 0.3850 ;
      RECT 0.8200 0.8750 0.8900 1.0850 ;
      RECT 1.1050 0.5950 1.1750 0.9450 ;
      RECT 0.8200 0.3150 0.9850 0.3850 ;
      RECT 1.0100 0.5950 1.1750 0.6650 ;
      RECT 0.8200 0.8750 1.1750 0.9450 ;
      RECT 1.4850 0.8050 1.5550 0.9450 ;
      RECT 2.4350 0.8050 2.5050 0.9450 ;
      RECT 2.5300 0.4550 2.6000 0.9450 ;
      RECT 3.2900 0.3150 3.3600 0.5250 ;
      RECT 3.2900 0.3150 3.5500 0.3850 ;
      RECT 2.5300 0.4550 3.3600 0.5250 ;
      RECT 2.4350 0.8050 2.6000 0.8750 ;
      RECT 1.4850 0.8750 2.6000 0.9450 ;
      RECT 3.2900 1.0150 3.7400 1.0850 ;
      RECT 3.1000 1.0150 3.1700 1.2250 ;
      RECT 2.7200 1.0150 3.1700 1.0850 ;
      RECT 3.1000 1.1550 3.9300 1.2250 ;
      RECT 2.2450 0.2450 2.5050 0.3150 ;
      RECT 4.1450 0.4550 4.4050 0.5250 ;
      RECT 4.3350 1.1550 4.5950 1.2250 ;
      RECT 5.0950 1.1550 5.3550 1.2250 ;
      RECT 3.6700 0.3150 4.5000 0.3850 ;
    LAYER via1 ;
      RECT 4.6225 0.8775 4.6875 0.9425 ;
      RECT 5.0025 0.8775 5.0675 0.9425 ;
      RECT 2.0575 0.7375 2.1225 0.8025 ;
      RECT 2.0575 1.0175 2.1225 1.0825 ;
      RECT 0.8225 0.3175 0.8875 0.3825 ;
      RECT 1.0125 0.5975 1.0775 0.6625 ;
      RECT 2.5325 0.8775 2.5975 0.9425 ;
      RECT 3.2925 1.0175 3.3575 1.0825 ;
      RECT 2.3425 0.2475 2.4075 0.3125 ;
      RECT 4.1475 0.4575 4.2125 0.5225 ;
      RECT 4.4325 1.1575 4.4975 1.2225 ;
      RECT 5.0975 1.1575 5.1625 1.2225 ;
    LAYER metal2 ;
      RECT 4.6200 0.8750 4.6900 1.0850 ;
      RECT 5.0000 0.8750 5.0700 1.0850 ;
      RECT 4.6200 1.0150 5.0700 1.0850 ;
      RECT 2.0550 0.7350 2.1250 1.0850 ;
      RECT 0.8200 0.3150 0.8900 0.6650 ;
      RECT 0.8200 0.5950 1.0800 0.6650 ;
      RECT 2.5300 0.8750 2.6000 1.0850 ;
      RECT 2.5300 1.0150 3.3600 1.0850 ;
      RECT 3.6700 0.2450 3.7400 0.5250 ;
      RECT 4.4300 0.4550 4.5000 1.2250 ;
      RECT 2.3400 0.2450 3.7400 0.3150 ;
      RECT 3.6700 0.4550 4.5000 0.5250 ;
      RECT 4.4300 1.1550 5.2600 1.2250 ;
  END
END MUX4_X1

MACRO HA_X1
  CLASS CORE ;
  ORIGIN 0 0 ;
  FOREIGN HA_X1 0 0 ;
  SIZE 3.04 BY 1.40 ;
  SYMMETRY X Y ;
  SITE core ;
  PIN A
    DIRECTION INPUT ;
    USE SIGNAL ;
    PORT
      LAYER metal1 ;
        RECT 0.7250 0.7350 0.7950 0.9450 ;
        RECT 0.8200 0.8050 0.8900 1.0150 ;
        RECT 1.6750 0.8050 1.7450 0.9450 ;
        RECT 2.2450 0.8050 2.3150 0.9450 ;
        RECT 0.3450 0.7350 0.7950 0.8050 ;
        RECT 0.7250 0.8050 0.8900 0.8750 ;
        RECT 0.7250 0.8750 2.3150 0.9450 ;
    END
  END A
  PIN B
    DIRECTION INPUT ;
    USE SIGNAL ;
    PORT
      LAYER metal1 ;
        RECT 0.9150 0.5950 0.9850 0.7350 ;
        RECT 1.0100 0.5950 1.0800 0.8050 ;
        RECT 0.5350 0.5950 2.6000 0.6650 ;
        RECT 0.9150 0.6650 1.0800 0.7350 ;
    END
  END B
  PIN S
    DIRECTION OUTPUT ;
    USE SIGNAL ;
    PORT
      LAYER metal1 ;
        RECT 2.9100 0.1750 2.9800 0.3850 ;
        RECT 2.9100 0.8750 2.9800 1.0850 ;
        RECT 2.7200 0.3150 2.9800 0.3850 ;
        RECT 2.7200 0.8750 2.9800 0.9450 ;
      LAYER via1 ;
        RECT 2.7225 0.3175 2.7875 0.3825 ;
        RECT 2.7225 0.8775 2.7875 0.9425 ;
      LAYER metal2 ;
        RECT 2.7200 0.3150 2.7900 0.9450 ;
    END
  END S
  PIN CO
    DIRECTION OUTPUT ;
    USE SIGNAL ;
    PORT
      LAYER metal1 ;
        RECT 0.0600 0.1750 0.1300 1.0850 ;
    END
  END CO
  PIN VDD
    DIRECTION INOUT ;
    USE POWER ;
    SHAPE ABUTMENT ;
    PORT
      LAYER metal1 ;
        RECT 0.0000 1.3150 3.0400 1.4850 ;
        RECT 0.2500 1.1550 0.3200 1.3650 ;
        RECT 0.6300 1.1550 0.7000 1.3650 ;
        RECT 1.7700 1.1550 1.8400 1.3650 ;
        RECT 2.1500 1.1550 2.2200 1.3650 ;
        RECT 2.7200 1.1550 2.7900 1.3650 ;
    END
  END VDD
  PIN VSS
    DIRECTION INOUT ;
    USE GROUND ;
    SHAPE ABUTMENT ;
    PORT
      LAYER metal1 ;
        RECT 0.0000 -0.0850 3.0400 0.0850 ;
        RECT 0.2500 0.0350 0.3200 0.2450 ;
        RECT 1.0100 0.0350 1.0800 0.2450 ;
        RECT 1.9600 0.0350 2.0300 0.2450 ;
        RECT 2.3400 0.0350 2.4100 0.2450 ;
        RECT 2.7200 0.0350 2.7900 0.2450 ;
    END
  END VSS
  OBS
    LAYER metal1 ;
      RECT 2.1500 0.2450 2.2200 0.3850 ;
      RECT 2.1500 0.3150 2.3150 0.3850 ;
      RECT 1.2950 0.7350 1.5550 0.8050 ;
      RECT 2.1500 1.0150 2.4100 1.0850 ;
      RECT 2.5300 0.2450 2.6000 0.3850 ;
      RECT 2.5300 0.8050 2.6000 1.2250 ;
      RECT 2.4350 0.3150 2.6000 0.3850 ;
      RECT 1.8650 0.7350 2.1250 0.8050 ;
      RECT 1.2000 0.4550 2.8850 0.5250 ;
      RECT 1.0100 1.0150 1.4600 1.0850 ;
      RECT 1.5800 1.0150 1.6500 1.2250 ;
      RECT 1.5800 1.0150 2.0300 1.0850 ;
      RECT 0.8200 1.1550 1.6500 1.2250 ;
      RECT 0.2500 0.4550 0.3200 0.5950 ;
      RECT 0.4400 0.8750 0.5100 1.0850 ;
      RECT 0.2500 0.4550 0.7000 0.5250 ;
      RECT 0.3450 0.8750 0.5100 0.9450 ;
    LAYER via1 ;
      RECT 1.4875 0.7375 1.5525 0.8025 ;
      RECT 2.1525 0.3175 2.2175 0.3825 ;
      RECT 2.1525 1.0175 2.2175 1.0825 ;
      RECT 1.8675 0.7375 1.9325 0.8025 ;
      RECT 2.5325 0.3175 2.5975 0.3825 ;
      RECT 2.5325 0.8075 2.5975 0.8725 ;
      RECT 2.5325 1.1575 2.5975 1.2225 ;
      RECT 1.2025 0.4575 1.2675 0.5225 ;
      RECT 1.2025 1.0175 1.2675 1.0825 ;
      RECT 0.2525 0.5275 0.3175 0.5925 ;
      RECT 0.3475 0.8775 0.4125 0.9425 ;
    LAYER metal2 ;
      RECT 1.4850 0.5250 1.5550 0.8050 ;
      RECT 2.1500 0.3150 2.2200 1.0850 ;
      RECT 1.4850 0.5250 2.2200 0.5950 ;
      RECT 2.1500 1.0150 2.4100 1.0850 ;
      RECT 1.9600 0.7350 2.0300 1.2250 ;
      RECT 2.5300 0.3150 2.6000 0.8750 ;
      RECT 1.8650 0.7350 2.0300 0.8050 ;
      RECT 1.9600 1.1550 2.6000 1.2250 ;
      RECT 1.2000 0.4550 1.2700 1.0850 ;
      RECT 0.2500 0.5250 0.3200 0.9450 ;
      RECT 0.2500 0.8750 0.4150 0.9450 ;
  END
END HA_X1

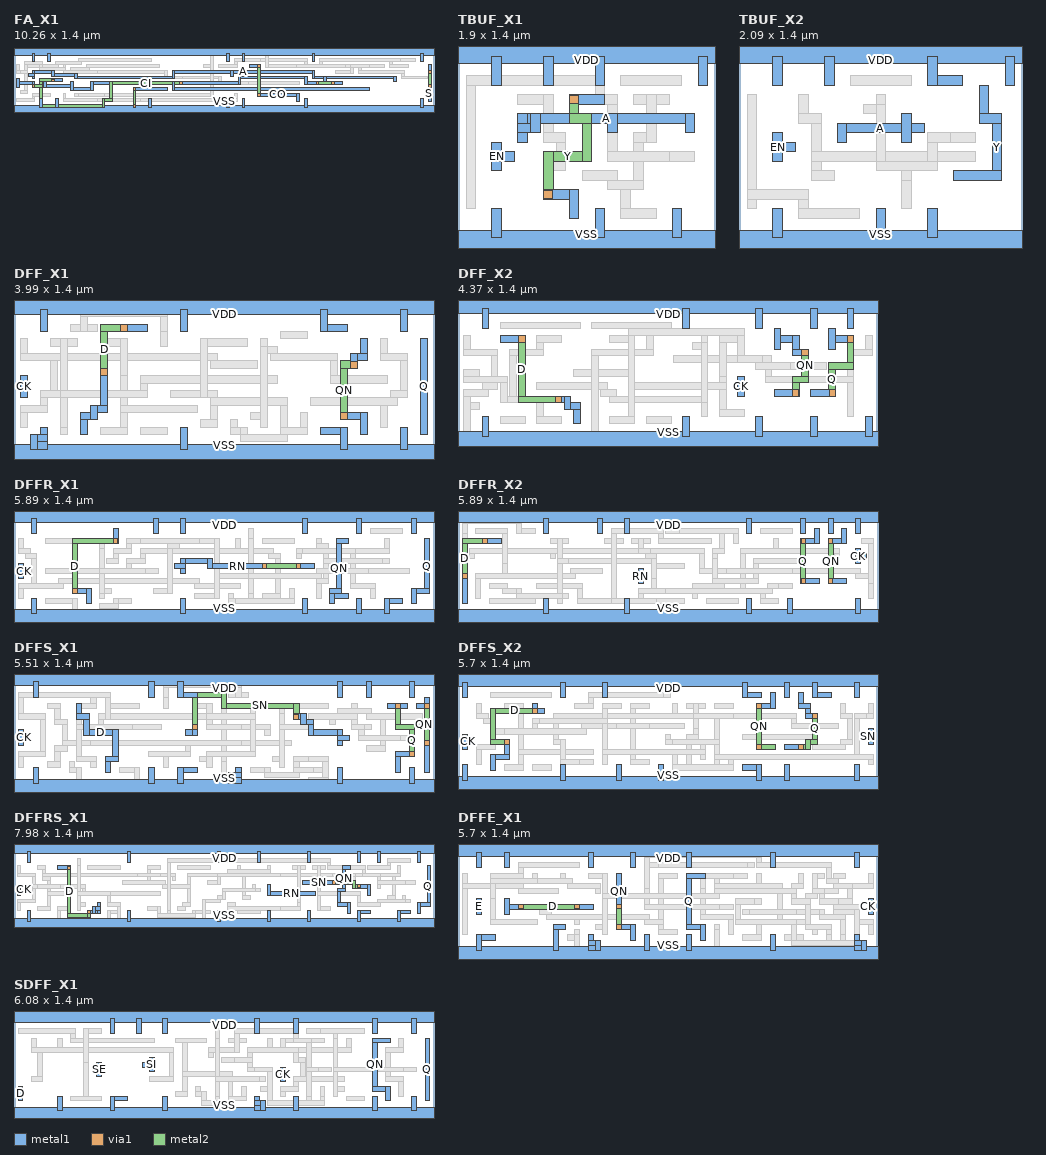
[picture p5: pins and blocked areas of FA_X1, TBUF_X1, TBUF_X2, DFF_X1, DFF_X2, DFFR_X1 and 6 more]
MACRO FA_X1
  CLASS CORE ;
  ORIGIN 0 0 ;
  FOREIGN FA_X1 0 0 ;
  SIZE 10.26 BY 1.40 ;
  SYMMETRY X Y ;
  SITE core ;
  PIN A
    DIRECTION INPUT ;
    USE SIGNAL ;
    PORT
      LAYER metal1 ;
        RECT 0.4400 0.7350 0.5100 0.9450 ;
        RECT 0.9150 0.8050 0.9850 0.9450 ;
        RECT 1.4850 0.7350 1.5550 0.8750 ;
        RECT 3.8600 0.7350 3.9300 0.9450 ;
        RECT 5.2850 0.8050 5.3550 0.9450 ;
        RECT 7.2800 0.7350 7.3500 0.9450 ;
        RECT 7.5650 0.6650 7.6350 0.8050 ;
        RECT 9.2750 0.6650 9.3450 0.8050 ;
        RECT 1.4850 0.7350 3.9300 0.8050 ;
        RECT 7.2800 0.7350 9.3450 0.8050 ;
        RECT 0.3450 0.8050 0.5100 0.8750 ;
        RECT 0.9150 0.8050 1.5550 0.8750 ;
        RECT 0.4400 0.8750 0.9850 0.9450 ;
        RECT 3.8600 0.8750 7.3500 0.9450 ;
    END
  END A
  PIN B
    DIRECTION INPUT ;
    USE SIGNAL ;
    PORT
      LAYER metal1 ;
        RECT 0.7250 0.5250 0.7950 0.6650 ;
        RECT 1.3900 0.4550 1.4600 0.6650 ;
        RECT 1.8650 0.4550 1.9350 0.6650 ;
        RECT 3.8600 0.4550 3.9300 0.6650 ;
        RECT 1.3900 0.4550 1.9350 0.5250 ;
        RECT 3.8600 0.4550 8.6800 0.5250 ;
        RECT 0.7250 0.5250 1.4600 0.5950 ;
        RECT 1.8650 0.5950 3.9300 0.6650 ;
    END
  END B
  PIN CI
    DIRECTION INPUT ;
    USE SIGNAL ;
    PORT
      LAYER metal1 ;
        RECT 0.0600 0.5250 0.1300 0.7350 ;
        RECT 0.4400 0.5250 0.5100 0.6650 ;
        RECT 5.4750 0.5950 5.5450 0.8050 ;
        RECT 7.0900 0.5950 7.1600 0.8050 ;
        RECT 0.0600 0.5950 0.5100 0.6650 ;
        RECT 4.0500 0.5950 5.5450 0.6650 ;
        RECT 7.0900 0.5950 7.4450 0.6650 ;
        RECT 7.7550 0.5950 8.0150 0.6650 ;
        RECT 0.9150 0.6650 1.1750 0.7350 ;
        RECT 5.4750 0.7350 7.1600 0.8050 ;
      LAYER via1 ;
        RECT 0.4425 0.5275 0.5075 0.5925 ;
        RECT 0.9175 0.6675 0.9825 0.7325 ;
        RECT 4.0525 0.5975 4.1175 0.6625 ;
        RECT 7.3775 0.5975 7.4425 0.6625 ;
        RECT 7.7575 0.5975 7.8225 0.6625 ;
      LAYER metal2 ;
        RECT 0.6300 0.0350 0.7000 0.7350 ;
        RECT 2.1500 0.0350 2.2200 0.2450 ;
        RECT 2.3400 0.1750 2.4100 0.6650 ;
        RECT 0.6300 0.0350 2.2200 0.1050 ;
        RECT 2.1500 0.1750 2.4100 0.2450 ;
        RECT 0.4400 0.5250 0.7000 0.5950 ;
        RECT 2.3400 0.5950 4.1200 0.6650 ;
        RECT 7.3750 0.5950 7.8250 0.6650 ;
        RECT 0.6300 0.6650 0.9850 0.7350 ;
    END
  END CI
  PIN S
    DIRECTION OUTPUT ;
    USE SIGNAL ;
    PORT
      LAYER metal1 ;
        RECT 10.1300 0.1750 10.2000 0.5950 ;
        RECT 10.1300 0.8750 10.2000 1.0850 ;
      LAYER via1 ;
        RECT 10.1325 0.5275 10.1975 0.5925 ;
        RECT 10.1325 0.8775 10.1975 0.9425 ;
      LAYER metal2 ;
        RECT 10.1300 0.5250 10.2000 0.9450 ;
    END
  END S
  PIN CO
    DIRECTION OUTPUT ;
    USE SIGNAL ;
    PORT
      LAYER metal1 ;
        RECT 6.9000 0.1750 6.9700 0.3850 ;
        RECT 5.9500 0.3150 6.9700 0.3850 ;
        RECT 5.7600 1.0150 6.0200 1.0850 ;
      LAYER via1 ;
        RECT 5.9525 0.3175 6.0175 0.3825 ;
        RECT 5.9525 1.0175 6.0175 1.0825 ;
      LAYER metal2 ;
        RECT 5.9500 0.3150 6.0200 1.0850 ;
    END
  END CO
  PIN VDD
    DIRECTION INOUT ;
    USE POWER ;
    SHAPE ABUTMENT ;
    PORT
      LAYER metal1 ;
        RECT 0.0000 1.3150 10.2600 1.4850 ;
        RECT 0.4400 1.1550 0.5100 1.3650 ;
        RECT 0.8200 1.1550 0.8900 1.3650 ;
        RECT 5.1900 1.1550 5.2600 1.3650 ;
        RECT 5.5700 1.1550 5.6400 1.3650 ;
        RECT 7.2800 1.1550 7.3500 1.3650 ;
        RECT 9.9400 1.1550 10.0100 1.3650 ;
    END
  END VDD
  PIN VSS
    DIRECTION INOUT ;
    USE GROUND ;
    SHAPE ABUTMENT ;
    PORT
      LAYER metal1 ;
        RECT 0.0000 -0.0850 10.2600 0.0850 ;
        RECT 0.6300 0.0350 0.7000 0.2450 ;
        RECT 1.0100 0.0350 1.0800 0.2450 ;
        RECT 3.2900 0.0350 3.3600 0.2450 ;
        RECT 5.1900 0.0350 5.2600 0.2450 ;
        RECT 5.5700 0.0350 5.6400 0.2450 ;
        RECT 7.0900 0.0350 7.1600 0.2450 ;
        RECT 9.9400 0.0350 10.0100 0.2450 ;
        RECT 2.9100 0.0350 2.9800 0.1050 ;
        RECT 2.9100 0.4550 3.7400 0.5250 ;
      LAYER via1 ;
        RECT 2.9125 0.0375 2.9775 0.1025 ;
        RECT 2.9125 0.4575 2.9775 0.5225 ;
      LAYER metal2 ;
        RECT 2.9100 0.0350 2.9800 0.5250 ;
    END
  END VSS
  OBS
    LAYER metal1 ;
      RECT 0.0600 0.8750 0.1300 1.0850 ;
      RECT 0.2500 0.3850 0.3200 0.5250 ;
      RECT 1.2000 0.9450 1.2700 1.1550 ;
      RECT 0.1550 0.3850 0.3200 0.4550 ;
      RECT 5.6650 0.5950 6.9700 0.6650 ;
      RECT 4.0500 0.7350 5.0700 0.8050 ;
      RECT 0.0600 0.8750 0.2250 0.9450 ;
      RECT 1.9600 0.8750 3.7400 0.9450 ;
      RECT 5.3800 1.0150 5.4500 1.2250 ;
      RECT 7.0900 1.0150 7.1600 1.2250 ;
      RECT 7.4700 1.0150 7.5400 1.2250 ;
      RECT 5.0000 1.0150 5.4500 1.0850 ;
      RECT 7.0900 1.0150 7.5400 1.0850 ;
      RECT 5.9500 1.1550 7.1600 1.2250 ;
      RECT 9.3700 1.1550 9.8200 1.2250 ;
      RECT 9.1800 1.0150 9.2500 1.2250 ;
      RECT 9.1800 1.0150 9.6300 1.0850 ;
      RECT 7.6600 1.1550 9.2500 1.2250 ;
      RECT 7.8500 0.8750 8.3000 0.9450 ;
      RECT 8.6100 1.0150 9.0600 1.0850 ;
      RECT 0.4400 0.1750 0.5100 0.3850 ;
      RECT 0.0600 0.1750 0.5100 0.2450 ;
      RECT 0.4400 0.3150 0.8900 0.3850 ;
      RECT 1.0100 1.0150 1.0800 1.1550 ;
      RECT 1.5800 1.0850 1.6500 1.2250 ;
      RECT 0.2500 1.0150 1.0800 1.0850 ;
      RECT 1.5800 1.1550 3.3600 1.2250 ;
      RECT 1.7700 0.9450 1.8400 1.0850 ;
      RECT 1.3900 0.9450 1.8400 1.0150 ;
      RECT 1.7700 1.0150 3.5500 1.0850 ;
      RECT 8.4200 0.8750 8.4900 1.0850 ;
      RECT 9.4650 0.7350 9.5350 0.9450 ;
      RECT 1.4850 0.3150 1.7450 0.3850 ;
      RECT 2.1500 0.3150 4.8800 0.3850 ;
      RECT 9.4650 0.7350 10.1050 0.8050 ;
      RECT 8.4200 0.8750 9.5350 0.9450 ;
      RECT 4.6200 1.0150 4.8800 1.0850 ;
      RECT 6.1400 1.0150 6.9700 1.0850 ;
      RECT 8.0400 1.0150 8.4900 1.0850 ;
      RECT 1.3900 0.1750 1.8400 0.2450 ;
      RECT 1.2000 0.1750 1.2700 0.3850 ;
      RECT 5.3800 0.1750 5.4500 0.3850 ;
      RECT 1.9600 0.1750 3.1700 0.2450 ;
      RECT 3.4800 0.1750 5.0700 0.2450 ;
    LAYER via1 ;
      RECT 0.1575 0.8775 0.2225 0.9425 ;
      RECT 0.2525 0.4575 0.3175 0.5225 ;
      RECT 1.2025 0.9475 1.2675 1.0125 ;
      RECT 1.9625 0.8775 2.0275 0.9425 ;
      RECT 3.6725 0.8775 3.7375 0.9425 ;
      RECT 4.0525 0.7375 4.1175 0.8025 ;
      RECT 5.0025 0.7375 5.0675 0.8025 ;
      RECT 5.6675 0.5975 5.7325 0.6625 ;
      RECT 5.3825 1.1575 5.4475 1.2225 ;
      RECT 5.9525 1.1575 6.0175 1.2225 ;
      RECT 7.4725 1.1575 7.5375 1.2225 ;
      RECT 9.3725 1.1575 9.4375 1.2225 ;
      RECT 8.2325 0.8775 8.2975 0.9425 ;
      RECT 8.6125 1.0175 8.6775 1.0825 ;
      RECT 1.0125 1.0875 1.0775 1.1525 ;
      RECT 1.5825 1.0875 1.6475 1.1525 ;
      RECT 1.5825 0.3175 1.6475 0.3825 ;
      RECT 2.1525 0.3175 2.2175 0.3825 ;
      RECT 4.8125 0.3175 4.8775 0.3825 ;
      RECT 4.8125 1.0175 4.8775 1.0825 ;
      RECT 6.1425 1.0175 6.2075 1.0825 ;
      RECT 6.9025 1.0175 6.9675 1.0825 ;
      RECT 8.0425 1.0175 8.1075 1.0825 ;
      RECT 1.2025 0.1775 1.2675 0.2425 ;
      RECT 1.9625 0.1775 2.0275 0.2425 ;
      RECT 3.1025 0.1775 3.1675 0.2425 ;
      RECT 5.3825 0.1775 5.4475 0.2425 ;
    LAYER metal2 ;
      RECT 0.2500 0.4550 0.3200 1.1550 ;
      RECT 0.6300 0.9450 0.7000 1.1550 ;
      RECT 1.2000 0.8750 1.2700 1.0150 ;
      RECT 3.6700 0.7350 3.7400 0.9450 ;
      RECT 5.0000 0.5950 5.0700 0.8050 ;
      RECT 5.0000 0.5950 5.7350 0.6650 ;
      RECT 3.6700 0.7350 4.1200 0.8050 ;
      RECT 0.1550 0.8750 0.3200 0.9450 ;
      RECT 1.2000 0.8750 2.0300 0.9450 ;
      RECT 0.6300 0.9450 1.2700 1.0150 ;
      RECT 0.2500 1.0850 0.7000 1.1550 ;
      RECT 5.3800 1.1550 6.0200 1.2250 ;
      RECT 7.4700 1.1550 9.4400 1.2250 ;
      RECT 8.2300 0.8750 8.3000 1.0850 ;
      RECT 8.2300 1.0150 8.6800 1.0850 ;
      RECT 1.0100 1.0850 1.6500 1.1550 ;
      RECT 4.8100 0.3150 4.8800 1.3650 ;
      RECT 6.1400 1.0150 6.2100 1.3650 ;
      RECT 1.5800 0.3150 2.2200 0.3850 ;
      RECT 6.9000 1.0150 8.1100 1.0850 ;
      RECT 4.8100 1.2950 6.2100 1.3650 ;
      RECT 1.2000 0.1750 2.0300 0.2450 ;
      RECT 3.1000 0.1750 5.4500 0.2450 ;
  END
END FA_X1

MACRO TBUF_X1
  CLASS CORE ;
  ORIGIN 0 0 ;
  FOREIGN TBUF_X1 0 0 ;
  SIZE 1.90 BY 1.40 ;
  SYMMETRY X Y ;
  SITE core ;
  PIN A
    DIRECTION INPUT ;
    USE SIGNAL ;
    PORT
      LAYER metal1 ;
        RECT 0.4400 0.7350 0.5100 0.9450 ;
        RECT 0.5350 0.8050 0.6050 0.9450 ;
        RECT 1.1050 0.8050 1.1750 0.9450 ;
        RECT 1.6750 0.8050 1.7450 0.9450 ;
        RECT 0.4400 0.8050 0.6050 0.8750 ;
        RECT 0.4400 0.8750 1.7450 0.9450 ;
    END
  END A
  PIN EN
    DIRECTION INPUT ;
    USE SIGNAL ;
    PORT
      LAYER metal1 ;
        RECT 0.2500 0.5250 0.3200 0.7350 ;
        RECT 0.2500 0.5950 0.4150 0.6650 ;
    END
  END EN
  PIN Y
    DIRECTION OUTPUT TRISTATE ;
    USE SIGNAL ;
    PORT
      LAYER metal1 ;
        RECT 0.8200 0.1750 0.8900 0.3850 ;
        RECT 0.6300 0.3150 0.8900 0.3850 ;
        RECT 0.8200 1.0150 1.0800 1.0850 ;
      LAYER via1 ;
        RECT 0.6325 0.3175 0.6975 0.3825 ;
        RECT 0.8225 1.0175 0.8875 1.0825 ;
      LAYER metal2 ;
        RECT 0.6300 0.3150 0.7000 0.6650 ;
        RECT 0.8200 0.8750 0.8900 1.0850 ;
        RECT 0.9150 0.5950 0.9850 0.9450 ;
        RECT 0.6300 0.5950 0.9850 0.6650 ;
        RECT 0.8200 0.8750 0.9850 0.9450 ;
    END
  END Y
  PIN VDD
    DIRECTION INOUT ;
    USE POWER ;
    SHAPE ABUTMENT ;
    PORT
      LAYER metal1 ;
        RECT 0.0000 1.3150 1.9000 1.4850 ;
        RECT 0.2500 1.1550 0.3200 1.3650 ;
        RECT 0.6300 1.1550 0.7000 1.3650 ;
        RECT 1.0100 1.1550 1.0800 1.3650 ;
        RECT 1.7700 1.1550 1.8400 1.3650 ;
    END
  END VDD
  PIN VSS
    DIRECTION INOUT ;
    USE GROUND ;
    SHAPE ABUTMENT ;
    PORT
      LAYER metal1 ;
        RECT 0.0000 -0.0850 1.9000 0.0850 ;
        RECT 0.2500 0.0350 0.3200 0.2450 ;
        RECT 1.0100 0.0350 1.0800 0.2450 ;
        RECT 1.5800 0.0350 1.6500 0.2450 ;
    END
  END VSS
  OBS
    LAYER metal1 ;
      RECT 0.0600 0.2450 0.1300 1.2250 ;
      RECT 1.4850 0.5950 1.7450 0.6650 ;
      RECT 0.6300 0.4550 0.7000 0.5950 ;
      RECT 0.7250 0.5250 0.7950 0.8050 ;
      RECT 0.6300 0.5250 0.7950 0.5950 ;
      RECT 0.4400 1.0150 0.7000 1.0850 ;
      RECT 1.1050 0.3850 1.1750 0.5250 ;
      RECT 1.2000 0.1750 1.2700 0.4550 ;
      RECT 1.2950 0.3850 1.3650 0.8050 ;
      RECT 1.2000 0.1750 1.4600 0.2450 ;
      RECT 1.1050 0.3850 1.3650 0.4550 ;
      RECT 0.9150 0.4550 1.1750 0.5250 ;
      RECT 1.2950 0.7350 1.4600 0.8050 ;
      RECT 1.2950 1.0150 1.5550 1.0850 ;
      RECT 1.2000 1.1550 1.6500 1.2250 ;
    LAYER via1 ;
      RECT 0.0625 1.1575 0.1275 1.2225 ;
      RECT 1.4875 0.5975 1.5525 0.6625 ;
      RECT 0.6325 1.0175 0.6975 1.0825 ;
      RECT 0.7275 0.7375 0.7925 0.8025 ;
      RECT 1.3925 0.7375 1.4575 0.8025 ;
      RECT 1.3925 1.0175 1.4575 1.0825 ;
    LAYER metal2 ;
      RECT 1.0100 1.0150 1.0800 1.2250 ;
      RECT 1.1050 0.5950 1.1750 1.0850 ;
      RECT 1.1050 0.5950 1.5550 0.6650 ;
      RECT 1.0100 1.0150 1.1750 1.0850 ;
      RECT 0.0600 1.1550 1.0800 1.2250 ;
      RECT 0.6300 0.7350 0.7000 1.0850 ;
      RECT 0.6300 0.7350 0.7950 0.8050 ;
      RECT 1.3900 0.7350 1.4600 1.0850 ;
  END
END TBUF_X1

MACRO TBUF_X2
  CLASS CORE ;
  ORIGIN 0 0 ;
  FOREIGN TBUF_X2 0 0 ;
  SIZE 2.09 BY 1.40 ;
  SYMMETRY X Y ;
  SITE core ;
  PIN A
    DIRECTION INPUT ;
    USE SIGNAL ;
    PORT
      LAYER metal1 ;
        RECT 0.7250 0.7350 0.7950 0.8750 ;
        RECT 1.2000 0.7350 1.2700 0.9450 ;
        RECT 0.7250 0.8050 1.3650 0.8750 ;
    END
  END A
  PIN EN
    DIRECTION INPUT ;
    USE SIGNAL ;
    PORT
      LAYER metal1 ;
        RECT 0.2500 0.5950 0.3200 0.8050 ;
        RECT 0.2500 0.6650 0.4150 0.7350 ;
    END
  END EN
  PIN Y
    DIRECTION OUTPUT TRISTATE ;
    USE SIGNAL ;
    PORT
      LAYER metal1 ;
        RECT 1.7700 0.8750 1.8400 1.1550 ;
        RECT 1.8650 0.4550 1.9350 0.9450 ;
        RECT 1.5800 0.4550 1.9350 0.5250 ;
        RECT 1.7700 0.8750 1.9350 0.9450 ;
    END
  END Y
  PIN VDD
    DIRECTION INOUT ;
    USE POWER ;
    SHAPE ABUTMENT ;
    PORT
      LAYER metal1 ;
        RECT 0.0000 1.3150 2.0900 1.4850 ;
        RECT 0.2500 1.1550 0.3200 1.3650 ;
        RECT 0.6300 1.1550 0.7000 1.3650 ;
        RECT 1.3900 1.1550 1.4600 1.3650 ;
        RECT 1.9600 1.1550 2.0300 1.3650 ;
        RECT 1.3900 1.1550 1.6500 1.2250 ;
    END
  END VDD
  PIN VSS
    DIRECTION INOUT ;
    USE GROUND ;
    SHAPE ABUTMENT ;
    PORT
      LAYER metal1 ;
        RECT 0.0000 -0.0850 2.0900 0.0850 ;
        RECT 0.2500 0.0350 0.3200 0.2450 ;
        RECT 1.0100 0.0350 1.0800 0.2450 ;
        RECT 1.3900 0.0350 1.4600 0.2450 ;
    END
  END VSS
  OBS
    LAYER metal1 ;
      RECT 0.0600 0.2450 0.1300 1.0850 ;
      RECT 0.4400 0.1750 0.5100 0.3850 ;
      RECT 0.4400 0.1750 0.8900 0.2450 ;
      RECT 0.0600 0.3150 0.5100 0.3850 ;
      RECT 0.4400 0.8750 0.5100 1.0850 ;
      RECT 0.5350 0.4550 0.6050 0.9450 ;
      RECT 0.5350 0.4550 0.7000 0.5250 ;
      RECT 0.5350 0.5950 1.7450 0.6650 ;
      RECT 0.4400 0.8750 0.6050 0.9450 ;
      RECT 1.0100 0.9450 1.0800 1.0850 ;
      RECT 1.2000 0.2450 1.2700 0.5250 ;
      RECT 1.4850 0.7350 1.7450 0.8050 ;
      RECT 0.9150 0.9450 1.0800 1.0150 ;
      RECT 0.8200 1.1550 1.2700 1.2250 ;
    LAYER via1 ;
      RECT 1.0125 0.9475 1.0775 1.0125 ;
      RECT 1.2025 0.4575 1.2675 0.5225 ;
      RECT 1.4875 0.7375 1.5525 0.8025 ;
    LAYER metal2 ;
      RECT 1.0100 0.5250 1.0800 1.0150 ;
      RECT 1.2000 0.4550 1.2700 0.5950 ;
      RECT 1.3900 0.5250 1.4600 0.8050 ;
      RECT 1.0100 0.5250 1.4600 0.5950 ;
      RECT 1.3900 0.7350 1.5550 0.8050 ;
  END
END TBUF_X2

MACRO DFF_X1
  CLASS CORE ;
  ORIGIN 0 0 ;
  FOREIGN DFF_X1 0 0 ;
  SIZE 3.99 BY 1.40 ;
  SYMMETRY X Y ;
  SITE core ;
  PIN D
    DIRECTION INPUT ;
    USE SIGNAL ;
    PORT
      LAYER metal1 ;
        RECT 0.6300 0.1750 0.7000 0.3850 ;
        RECT 0.7250 0.3150 0.7950 0.4550 ;
        RECT 0.8200 0.3850 0.8900 0.8050 ;
        RECT 0.6300 0.3150 0.7950 0.3850 ;
        RECT 0.7250 0.3850 0.8900 0.4550 ;
        RECT 1.0100 1.1550 1.2700 1.2250 ;
      LAYER via1 ;
        RECT 0.8225 0.7375 0.8875 0.8025 ;
        RECT 1.0125 1.1575 1.0775 1.2225 ;
      LAYER metal2 ;
        RECT 0.8200 0.7350 0.8900 1.2250 ;
        RECT 0.8200 1.1550 1.2700 1.2250 ;
    END
  END D
  PIN CK
    DIRECTION INPUT ;
    USE CLOCK ;
    PORT
      LAYER metal1 ;
        RECT 0.0600 0.5250 0.1300 0.7350 ;
    END
  END CK
  PIN Q
    DIRECTION OUTPUT ;
    USE SIGNAL ;
    PORT
      LAYER metal1 ;
        RECT 3.8600 0.1750 3.9300 1.0850 ;
    END
  END Q
  PIN QN
    DIRECTION OUTPUT ;
    USE SIGNAL ;
    PORT
      LAYER metal1 ;
        RECT 3.1950 0.8050 3.2650 0.9450 ;
        RECT 3.2900 0.1750 3.3600 0.3850 ;
        RECT 3.2900 0.8750 3.3600 1.0850 ;
        RECT 3.1000 0.3150 3.3600 0.3850 ;
        RECT 3.1950 0.8750 3.3600 0.9450 ;
      LAYER via1 ;
        RECT 3.1025 0.3175 3.1675 0.3825 ;
        RECT 3.1975 0.8075 3.2625 0.8725 ;
      LAYER metal2 ;
        RECT 3.1000 0.3150 3.1700 0.8750 ;
        RECT 3.1000 0.8050 3.2650 0.8750 ;
    END
  END QN
  PIN VDD
    DIRECTION INOUT ;
    USE POWER ;
    SHAPE ABUTMENT ;
    PORT
      LAYER metal1 ;
        RECT 0.0000 1.3150 3.9900 1.4850 ;
        RECT 0.2500 1.1550 0.3200 1.3650 ;
        RECT 1.5800 1.1550 1.6500 1.3650 ;
        RECT 2.9100 1.1550 2.9800 1.3650 ;
        RECT 3.6700 1.1550 3.7400 1.3650 ;
        RECT 2.9100 1.1550 3.1700 1.2250 ;
    END
  END VDD
  PIN VSS
    DIRECTION INOUT ;
    USE GROUND ;
    SHAPE ABUTMENT ;
    PORT
      LAYER metal1 ;
        RECT 0.0000 -0.0850 3.9900 0.0850 ;
        RECT 0.1550 0.0350 0.2250 0.1750 ;
        RECT 0.2500 0.0350 0.3200 0.2450 ;
        RECT 1.5800 0.0350 1.6500 0.2450 ;
        RECT 3.1000 0.0350 3.1700 0.2450 ;
        RECT 3.6700 0.0350 3.7400 0.2450 ;
        RECT 0.1550 0.0350 0.3200 0.1050 ;
        RECT 0.1550 0.1050 0.3200 0.1750 ;
        RECT 2.9100 0.1750 3.1700 0.2450 ;
    END
  END VSS
  OBS
    LAYER metal1 ;
      RECT 3.4800 0.2450 3.5500 0.5250 ;
      RECT 3.4800 0.8750 3.5500 1.0850 ;
      RECT 3.5750 0.4550 3.6450 0.5950 ;
      RECT 3.6700 0.5250 3.7400 0.9450 ;
      RECT 2.8150 0.4550 3.6450 0.5250 ;
      RECT 3.5750 0.5250 3.7400 0.5950 ;
      RECT 3.4800 0.8750 3.7400 0.9450 ;
      RECT 2.5300 1.0850 2.7900 1.1550 ;
      RECT 0.0600 0.2450 0.1300 0.4550 ;
      RECT 0.0600 0.8750 0.1300 1.0850 ;
      RECT 0.2500 0.3850 0.3200 0.5950 ;
      RECT 0.3450 0.5250 0.4150 0.9450 ;
      RECT 1.8650 0.8050 1.9350 0.9450 ;
      RECT 0.0600 0.3850 0.3200 0.4550 ;
      RECT 0.2500 0.5250 0.7000 0.5950 ;
      RECT 1.8650 0.8050 2.3150 0.8750 ;
      RECT 0.0600 0.8750 1.9350 0.9450 ;
      RECT 0.4400 0.1750 0.5100 0.3850 ;
      RECT 1.2000 0.5250 1.2700 0.7350 ;
      RECT 1.2000 0.6650 2.5050 0.7350 ;
      RECT 0.3450 1.0150 0.6050 1.0850 ;
      RECT 1.0100 0.1750 1.0800 0.8050 ;
      RECT 0.8200 0.1750 1.0800 0.2450 ;
      RECT 1.0100 0.3850 1.7450 0.4550 ;
      RECT 0.8200 1.0150 1.0800 1.0850 ;
      RECT 1.8650 0.2450 1.9350 0.5950 ;
      RECT 2.5300 0.2450 2.6000 0.5250 ;
      RECT 1.7700 0.2450 1.9350 0.3150 ;
      RECT 1.8650 0.4550 2.6000 0.5250 ;
      RECT 1.4850 0.5250 1.9350 0.5950 ;
      RECT 1.7700 1.0150 2.2200 1.0850 ;
      RECT 2.3400 0.2450 2.4100 0.3850 ;
      RECT 2.3400 0.9450 2.4100 1.0850 ;
      RECT 2.4350 0.8750 2.5050 1.0150 ;
      RECT 3.0050 0.6650 3.0750 0.9450 ;
      RECT 2.2450 0.3150 2.4100 0.3850 ;
      RECT 3.0050 0.6650 3.5500 0.7350 ;
      RECT 2.4350 0.8750 3.0750 0.9450 ;
      RECT 2.3400 0.9450 2.5050 1.0150 ;
      RECT 1.2000 0.1750 1.4600 0.2450 ;
      RECT 1.3900 1.0150 1.4600 1.2250 ;
      RECT 0.5350 1.1550 0.7950 1.2250 ;
      RECT 2.0550 0.1750 2.1250 0.3150 ;
      RECT 2.7200 0.1750 2.7900 0.3850 ;
      RECT 2.0550 0.1750 2.2200 0.2450 ;
    LAYER via1 ;
      RECT 0.4425 0.2475 0.5075 0.3125 ;
      RECT 0.4425 1.0175 0.5075 1.0825 ;
      RECT 1.2025 0.5275 1.2675 0.5925 ;
      RECT 1.0125 0.7375 1.0775 0.8025 ;
      RECT 1.0125 1.0175 1.0775 1.0825 ;
      RECT 1.7725 0.5275 1.8375 0.5925 ;
      RECT 1.7725 1.0175 1.8375 1.0825 ;
      RECT 2.3425 0.2475 2.4075 0.3125 ;
      RECT 2.3425 0.9475 2.4075 1.0125 ;
      RECT 0.6325 1.1575 0.6975 1.2225 ;
      RECT 1.3925 1.1575 1.4575 1.2225 ;
      RECT 2.1525 0.1775 2.2175 0.2425 ;
      RECT 2.7225 0.1775 2.7875 0.2425 ;
    LAYER metal2 ;
      RECT 0.4400 0.2450 0.5100 1.0850 ;
      RECT 0.4400 0.5250 1.2700 0.5950 ;
      RECT 1.0100 0.7350 1.0800 1.0850 ;
      RECT 1.7700 0.5250 1.8400 1.0850 ;
      RECT 2.3400 0.2450 2.4100 1.0150 ;
      RECT 0.6300 1.1550 0.7000 1.3650 ;
      RECT 1.3900 1.1550 1.4600 1.3650 ;
      RECT 0.6300 1.2950 1.4600 1.3650 ;
      RECT 2.1500 0.1050 2.2200 0.2450 ;
      RECT 2.5300 0.1050 2.6000 0.2450 ;
      RECT 2.1500 0.1050 2.6000 0.1750 ;
      RECT 2.5300 0.1750 2.7900 0.2450 ;
  END
END DFF_X1

MACRO DFF_X2
  CLASS CORE ;
  ORIGIN 0 0 ;
  FOREIGN DFF_X2 0 0 ;
  SIZE 4.37 BY 1.40 ;
  SYMMETRY X Y ;
  SITE core ;
  PIN D
    DIRECTION INPUT ;
    USE SIGNAL ;
    PORT
      LAYER metal1 ;
        RECT 1.1050 0.3150 1.1750 0.4550 ;
        RECT 1.2000 0.1750 1.2700 0.3850 ;
        RECT 1.1050 0.3150 1.2700 0.3850 ;
        RECT 1.0100 0.3850 1.1750 0.4550 ;
        RECT 0.4400 1.0150 0.7000 1.0850 ;
      LAYER via1 ;
        RECT 0.6325 1.0175 0.6975 1.0825 ;
        RECT 1.0125 0.3875 1.0775 0.4525 ;
      LAYER metal2 ;
        RECT 0.6300 0.3850 0.7000 1.0850 ;
        RECT 0.6300 0.3850 1.0800 0.4550 ;
    END
  END D
  PIN CK
    DIRECTION INPUT ;
    USE CLOCK ;
    PORT
      LAYER metal1 ;
        RECT 2.9100 0.4550 2.9800 0.6650 ;
    END
  END CK
  PIN Q
    DIRECTION OUTPUT ;
    USE SIGNAL ;
    PORT
      LAYER metal1 ;
        RECT 3.8600 0.9450 3.9300 1.1550 ;
        RECT 3.6700 0.4550 3.9300 0.5250 ;
        RECT 3.8600 1.0150 4.1200 1.0850 ;
      LAYER via1 ;
        RECT 3.8625 0.4575 3.9275 0.5225 ;
        RECT 4.0525 1.0175 4.1175 1.0825 ;
      LAYER metal2 ;
        RECT 3.8600 0.4550 3.9300 0.8050 ;
        RECT 4.0500 0.7350 4.1200 1.0850 ;
        RECT 3.8600 0.7350 4.1200 0.8050 ;
    END
  END Q
  PIN QN
    DIRECTION OUTPUT ;
    USE SIGNAL ;
    PORT
      LAYER metal1 ;
        RECT 3.2900 0.9450 3.3600 1.1550 ;
        RECT 3.4800 0.8750 3.5500 1.0850 ;
        RECT 3.2900 0.4550 3.5500 0.5250 ;
        RECT 3.4800 0.8750 3.6450 0.9450 ;
        RECT 3.2900 1.0150 3.5500 1.0850 ;
      LAYER via1 ;
        RECT 3.4825 0.4575 3.5475 0.5225 ;
        RECT 3.5775 0.8775 3.6425 0.9425 ;
      LAYER metal2 ;
        RECT 3.4800 0.4550 3.5500 0.6650 ;
        RECT 3.5750 0.5950 3.6450 0.9450 ;
        RECT 3.4800 0.5950 3.6450 0.6650 ;
    END
  END QN
  PIN VDD
    DIRECTION INOUT ;
    USE POWER ;
    SHAPE ABUTMENT ;
    PORT
      LAYER metal1 ;
        RECT 0.0000 1.3150 4.3700 1.4850 ;
        RECT 0.2500 1.1550 0.3200 1.3650 ;
        RECT 2.3400 1.1550 2.4100 1.3650 ;
        RECT 3.1000 1.1550 3.1700 1.3650 ;
        RECT 3.6700 1.1550 3.7400 1.3650 ;
        RECT 4.0500 1.1550 4.1200 1.3650 ;
    END
  END VDD
  PIN VSS
    DIRECTION INOUT ;
    USE GROUND ;
    SHAPE ABUTMENT ;
    PORT
      LAYER metal1 ;
        RECT 0.0000 -0.0850 4.3700 0.0850 ;
        RECT 0.2500 0.0350 0.3200 0.2450 ;
        RECT 2.3400 0.0350 2.4100 0.2450 ;
        RECT 3.1000 0.0350 3.1700 0.2450 ;
        RECT 3.6700 0.0350 3.7400 0.2450 ;
        RECT 4.2400 0.0350 4.3100 0.2450 ;
    END
  END VSS
  OBS
    LAYER metal1 ;
      RECT 3.1950 0.5950 3.2650 0.8750 ;
      RECT 4.0500 0.2450 4.1200 0.9450 ;
      RECT 4.2400 0.8750 4.3100 1.0850 ;
      RECT 3.1950 0.5950 4.1200 0.6650 ;
      RECT 2.2450 0.8050 3.2650 0.8750 ;
      RECT 4.0500 0.8750 4.3100 0.9450 ;
      RECT 1.3900 1.1550 2.2200 1.2250 ;
      RECT 1.7700 0.5250 1.8400 0.7350 ;
      RECT 2.7200 0.2450 2.7900 0.7350 ;
      RECT 2.7200 0.9450 2.7900 1.0850 ;
      RECT 2.7200 0.2450 2.9800 0.3150 ;
      RECT 1.7700 0.5250 2.7900 0.5950 ;
      RECT 1.2000 0.6650 1.8400 0.7350 ;
      RECT 2.7200 1.0150 2.9800 1.0850 ;
      RECT 1.4850 0.4550 1.5550 0.5950 ;
      RECT 1.5800 0.3850 1.6500 0.5250 ;
      RECT 2.5300 0.2450 2.6000 0.4550 ;
      RECT 2.5300 0.9450 2.6000 1.0850 ;
      RECT 1.5800 0.3850 2.6000 0.4550 ;
      RECT 1.4850 0.4550 1.6500 0.5250 ;
      RECT 0.8200 0.5250 1.5550 0.5950 ;
      RECT 2.4350 0.9450 2.6000 1.0150 ;
      RECT 0.0600 0.5950 0.1300 0.7350 ;
      RECT 0.5350 0.3850 0.6050 0.9450 ;
      RECT 0.8200 0.1750 0.8900 0.4550 ;
      RECT 0.8200 0.8750 0.8900 1.0850 ;
      RECT 0.8200 0.1750 1.0800 0.2450 ;
      RECT 0.4400 0.3850 0.8900 0.4550 ;
      RECT 0.0600 0.6650 0.2250 0.7350 ;
      RECT 0.5350 0.8750 0.8900 0.9450 ;
      RECT 0.8200 1.0150 1.0800 1.0850 ;
      RECT 0.0600 0.2450 0.1300 0.3850 ;
      RECT 0.0600 0.8750 0.1300 1.0850 ;
      RECT 0.2500 0.4550 0.3200 0.5950 ;
      RECT 0.3450 0.5250 0.4150 0.9450 ;
      RECT 1.3900 0.1750 1.4600 0.3850 ;
      RECT 1.3900 0.8050 1.4600 0.9450 ;
      RECT 1.9600 0.8750 2.0300 1.0850 ;
      RECT 0.0600 0.3150 0.2250 0.3850 ;
      RECT 0.2500 0.5250 0.4150 0.5950 ;
      RECT 0.0600 0.8750 0.4150 0.9450 ;
      RECT 1.3900 0.8750 2.0300 0.9450 ;
      RECT 1.7700 0.1750 1.8400 0.3150 ;
      RECT 1.5800 0.1750 1.8400 0.2450 ;
      RECT 3.3850 0.7350 3.8350 0.8050 ;
      RECT 1.5800 1.0150 1.8400 1.0850 ;
      RECT 0.4400 0.1750 0.7000 0.2450 ;
      RECT 0.4400 1.1550 1.2700 1.2250 ;
      RECT 1.9600 0.1750 2.2200 0.2450 ;
    LAYER via1 ;
      RECT 2.7225 0.6675 2.7875 0.7325 ;
      RECT 2.7225 0.9475 2.7875 1.0125 ;
      RECT 2.5325 0.3875 2.5975 0.4525 ;
      RECT 2.5325 0.9475 2.5975 1.0125 ;
      RECT 0.0625 0.5975 0.1275 0.6625 ;
      RECT 0.4425 0.3875 0.5075 0.4525 ;
      RECT 0.0625 0.2475 0.1275 0.3125 ;
      RECT 0.2525 0.4575 0.3175 0.5225 ;
      RECT 1.3925 0.1775 1.4575 0.2425 ;
      RECT 1.3925 0.8075 1.4575 0.8725 ;
      RECT 1.7725 0.2475 1.8375 0.3125 ;
      RECT 1.7725 1.0175 1.8375 1.0825 ;
      RECT 3.3875 0.7375 3.4525 0.8025 ;
    LAYER metal2 ;
      RECT 2.7200 0.6650 2.7900 1.0150 ;
      RECT 2.5300 0.3850 2.6000 1.0150 ;
      RECT 0.4400 0.3850 0.5100 0.6650 ;
      RECT 0.0600 0.5950 0.5100 0.6650 ;
      RECT 0.0600 -0.0350 0.1300 0.5250 ;
      RECT 1.3900 -0.0350 1.4600 0.8750 ;
      RECT 0.0600 -0.0350 1.4600 0.0350 ;
      RECT 0.0600 0.4550 0.3200 0.5250 ;
      RECT 1.7700 0.2450 1.8400 1.1550 ;
      RECT 2.9100 0.8050 2.9800 1.1550 ;
      RECT 3.1000 0.7350 3.1700 0.8750 ;
      RECT 3.1000 0.7350 3.4550 0.8050 ;
      RECT 2.9100 0.8050 3.1700 0.8750 ;
      RECT 1.7700 1.0850 2.9800 1.1550 ;
  END
END DFF_X2

MACRO DFFR_X1
  CLASS CORE ;
  ORIGIN 0 0 ;
  FOREIGN DFFR_X1 0 0 ;
  SIZE 5.89 BY 1.40 ;
  SYMMETRY X Y ;
  SITE core ;
  PIN D
    DIRECTION INPUT ;
    USE SIGNAL ;
    PORT
      LAYER metal1 ;
        RECT 1.0100 0.1750 1.0800 0.3850 ;
        RECT 1.3900 1.0150 1.4600 1.2250 ;
        RECT 0.8200 0.3150 1.0800 0.3850 ;
      LAYER via1 ;
        RECT 0.8225 0.3175 0.8875 0.3825 ;
        RECT 1.3925 1.0175 1.4575 1.0825 ;
      LAYER metal2 ;
        RECT 0.8200 0.3150 0.8900 1.0850 ;
        RECT 0.8200 1.0150 1.4600 1.0850 ;
    END
  END D
  PIN CK
    DIRECTION INPUT ;
    USE CLOCK ;
    PORT
      LAYER metal1 ;
        RECT 0.0600 0.5250 0.1300 0.7350 ;
    END
  END CK
  PIN RN
    DIRECTION INPUT ;
    USE SIGNAL ;
    PORT
      LAYER metal1 ;
        RECT 2.3400 0.5950 2.4100 0.8050 ;
        RECT 2.7200 0.6650 2.7900 0.8050 ;
        RECT 2.2450 0.6650 2.4100 0.7350 ;
        RECT 2.7200 0.6650 3.5500 0.7350 ;
        RECT 3.9550 0.6650 4.2150 0.7350 ;
        RECT 2.3400 0.7350 2.7900 0.8050 ;
      LAYER via1 ;
        RECT 3.4825 0.6675 3.5475 0.7325 ;
        RECT 3.9575 0.6675 4.0225 0.7325 ;
      LAYER metal2 ;
        RECT 3.4800 0.6650 4.1200 0.7350 ;
    END
  END RN
  PIN Q
    DIRECTION OUTPUT ;
    USE SIGNAL ;
    PORT
      LAYER metal1 ;
        RECT 5.5700 0.1750 5.6400 0.3850 ;
        RECT 5.7600 0.3150 5.8300 1.0850 ;
        RECT 5.5700 0.3150 5.8300 0.3850 ;
    END
  END Q
  PIN QN
    DIRECTION OUTPUT ;
    USE SIGNAL ;
    PORT
      LAYER metal1 ;
        RECT 4.4300 0.1750 4.5000 0.3850 ;
        RECT 4.5250 0.2450 4.5950 1.0850 ;
        RECT 4.4300 0.2450 4.6900 0.3150 ;
        RECT 4.4300 0.3150 4.5950 0.3850 ;
        RECT 4.5250 1.0150 4.6900 1.0850 ;
    END
  END QN
  PIN VDD
    DIRECTION INOUT ;
    USE POWER ;
    SHAPE ABUTMENT ;
    PORT
      LAYER metal1 ;
        RECT 0.0000 1.3150 5.8900 1.4850 ;
        RECT 0.2500 1.1550 0.3200 1.3650 ;
        RECT 1.9600 1.1550 2.0300 1.3650 ;
        RECT 2.3400 1.1550 2.4100 1.3650 ;
        RECT 4.0500 1.1550 4.1200 1.3650 ;
        RECT 4.8100 1.1550 4.8800 1.3650 ;
        RECT 5.5700 1.1550 5.6400 1.3650 ;
    END
  END VDD
  PIN VSS
    DIRECTION INOUT ;
    USE GROUND ;
    SHAPE ABUTMENT ;
    PORT
      LAYER metal1 ;
        RECT 0.0000 -0.0850 5.8900 0.0850 ;
        RECT 0.2500 0.0350 0.3200 0.2450 ;
        RECT 2.3400 0.0350 2.4100 0.2450 ;
        RECT 4.0500 0.0350 4.1200 0.2450 ;
        RECT 4.8100 0.0350 4.8800 0.2450 ;
        RECT 5.1900 0.0350 5.2600 0.2450 ;
        RECT 5.1900 0.1750 5.4500 0.2450 ;
    END
  END VSS
  OBS
    LAYER metal1 ;
      RECT 3.9550 0.8050 4.0250 0.9450 ;
      RECT 4.7150 0.3850 4.7850 0.9450 ;
      RECT 5.0000 0.2450 5.0700 0.4550 ;
      RECT 5.1900 0.8750 5.2600 1.0850 ;
      RECT 4.7150 0.3850 5.0700 0.4550 ;
      RECT 3.9550 0.8750 4.1200 0.9450 ;
      RECT 4.7150 0.8750 5.2600 0.9450 ;
      RECT 0.4400 1.0150 1.0800 1.0850 ;
      RECT 5.0000 1.1550 5.4500 1.2250 ;
      RECT 3.0050 0.1750 3.0750 0.3150 ;
      RECT 3.8600 0.1750 3.9300 0.3850 ;
      RECT 3.0050 0.1750 3.1700 0.2450 ;
      RECT 3.4800 1.0150 3.9300 1.0850 ;
      RECT 0.0600 0.2450 0.1300 0.4550 ;
      RECT 0.0600 0.8750 0.1300 1.0850 ;
      RECT 0.1550 0.8050 0.2250 0.9450 ;
      RECT 0.2500 0.3850 0.3200 0.8750 ;
      RECT 0.6300 0.3850 0.7000 0.5250 ;
      RECT 2.5300 0.3850 2.6000 0.5250 ;
      RECT 0.0600 0.3850 0.7000 0.4550 ;
      RECT 2.5300 0.3850 3.1700 0.4550 ;
      RECT 0.6300 0.4550 2.6000 0.5250 ;
      RECT 0.1550 0.8050 0.3200 0.8750 ;
      RECT 0.0600 0.8750 0.2250 0.9450 ;
      RECT 1.3900 0.7350 1.4600 0.9450 ;
      RECT 1.5800 0.8750 1.6500 1.0850 ;
      RECT 2.5300 0.2450 2.8850 0.3150 ;
      RECT 2.8150 0.5250 3.4550 0.5950 ;
      RECT 1.2950 0.7350 1.4600 0.8050 ;
      RECT 1.3900 0.8750 1.6500 0.9450 ;
      RECT 1.5800 1.0150 1.8400 1.0850 ;
      RECT 2.5300 1.0150 2.8850 1.0850 ;
      RECT 1.2000 0.2450 1.2700 0.3850 ;
      RECT 1.2000 0.8750 1.2700 1.0850 ;
      RECT 1.2000 0.3150 1.3650 0.3850 ;
      RECT 1.7700 0.5950 2.0300 0.6650 ;
      RECT 1.5800 0.5950 1.6500 0.8050 ;
      RECT 1.7700 0.7350 1.8400 0.9450 ;
      RECT 2.1500 0.8750 2.2200 1.0850 ;
      RECT 2.2450 0.8750 2.3150 1.0150 ;
      RECT 3.1000 0.8750 3.1700 1.0850 ;
      RECT 3.5750 0.8050 3.6450 0.9450 ;
      RECT 3.6700 0.2450 3.7400 0.8750 ;
      RECT 3.4800 0.2450 3.7400 0.3150 ;
      RECT 1.9600 0.3150 2.2200 0.3850 ;
      RECT 0.4400 0.5950 1.6500 0.6650 ;
      RECT 1.5800 0.7350 1.8400 0.8050 ;
      RECT 3.5750 0.8050 3.7400 0.8750 ;
      RECT 1.7700 0.8750 3.6450 0.9450 ;
      RECT 2.1500 0.9450 2.3150 1.0150 ;
      RECT 3.2900 0.1750 3.3600 0.3850 ;
      RECT 3.2900 1.0150 3.3600 1.2250 ;
      RECT 4.9050 0.5950 5.5450 0.6650 ;
      RECT 4.2400 0.2450 4.3100 0.5250 ;
      RECT 4.2400 0.9450 4.3100 1.0850 ;
      RECT 4.3350 0.4550 4.4050 1.0150 ;
      RECT 4.2400 0.4550 4.4050 0.5250 ;
      RECT 5.0000 0.7350 5.2600 0.8050 ;
      RECT 4.2400 0.9450 4.4050 1.0150 ;
      RECT 0.4400 0.1750 0.8900 0.2450 ;
      RECT 1.3900 0.1750 1.6500 0.2450 ;
    LAYER via1 ;
      RECT 4.0525 0.8775 4.1175 0.9425 ;
      RECT 4.7175 0.8775 4.7825 0.9425 ;
      RECT 3.1025 0.1775 3.1675 0.2425 ;
      RECT 3.8625 0.1775 3.9275 0.2425 ;
      RECT 1.7725 1.0175 1.8375 1.0825 ;
      RECT 2.5325 1.0175 2.5975 1.0825 ;
      RECT 2.8175 0.2475 2.8825 0.3125 ;
      RECT 2.8175 0.5275 2.8825 0.5925 ;
      RECT 2.8175 1.0175 2.8825 1.0825 ;
      RECT 1.2025 0.3175 1.2675 0.3825 ;
      RECT 1.2025 0.8775 1.2675 0.9425 ;
      RECT 1.7725 0.5975 1.8375 0.6625 ;
      RECT 2.1525 0.3175 2.2175 0.3825 ;
      RECT 2.1525 0.8775 2.2175 0.9425 ;
      RECT 3.2925 0.3175 3.3575 0.3825 ;
      RECT 3.2925 1.0175 3.3575 1.0825 ;
      RECT 4.9075 0.5975 4.9725 0.6625 ;
      RECT 4.3375 0.7375 4.4025 0.8025 ;
      RECT 5.0025 0.7375 5.0675 0.8025 ;
      RECT 0.8225 0.1775 0.8875 0.2425 ;
      RECT 1.3925 0.1775 1.4575 0.2425 ;
    LAYER metal2 ;
      RECT 4.0500 0.8750 4.7850 0.9450 ;
      RECT 3.1000 0.1750 3.9300 0.2450 ;
      RECT 2.8150 0.2450 2.8850 1.0850 ;
      RECT 1.7700 1.0150 2.6000 1.0850 ;
      RECT 1.2000 0.3150 1.2700 0.9450 ;
      RECT 1.2000 0.5950 1.8400 0.6650 ;
      RECT 2.1500 0.3150 2.2200 0.9450 ;
      RECT 3.2900 0.3150 3.3600 1.0850 ;
      RECT 4.2400 0.5250 4.3100 0.6650 ;
      RECT 3.2900 0.5250 4.3100 0.5950 ;
      RECT 4.2400 0.5950 4.9750 0.6650 ;
      RECT 4.3350 0.7350 5.1650 0.8050 ;
      RECT 0.8200 -0.0350 0.8900 0.2450 ;
      RECT 1.2000 -0.0350 1.2700 0.1750 ;
      RECT 1.3900 0.1050 1.4600 0.2450 ;
      RECT 0.8200 -0.0350 1.2700 0.0350 ;
      RECT 1.2000 0.1050 1.4600 0.1750 ;
  END
END DFFR_X1

MACRO DFFR_X2
  CLASS CORE ;
  ORIGIN 0 0 ;
  FOREIGN DFFR_X2 0 0 ;
  SIZE 5.89 BY 1.40 ;
  SYMMETRY X Y ;
  SITE core ;
  PIN D
    DIRECTION INPUT ;
    USE SIGNAL ;
    PORT
      LAYER metal1 ;
        RECT 0.0600 0.1750 0.1300 0.5950 ;
        RECT 0.3450 1.0150 0.6050 1.0850 ;
      LAYER via1 ;
        RECT 0.0625 0.5275 0.1275 0.5925 ;
        RECT 0.3475 1.0175 0.4125 1.0825 ;
      LAYER metal2 ;
        RECT 0.0600 0.5250 0.1300 1.0850 ;
        RECT 0.0600 1.0150 0.5100 1.0850 ;
    END
  END D
  PIN CK
    DIRECTION INPUT ;
    USE CLOCK ;
    PORT
      LAYER metal1 ;
        RECT 5.5700 0.7350 5.6400 0.9450 ;
        RECT 5.5700 0.8050 5.7350 0.8750 ;
    END
  END CK
  PIN RN
    DIRECTION INPUT ;
    USE SIGNAL ;
    PORT
      LAYER metal1 ;
        RECT 2.5300 0.4550 2.6000 0.6650 ;
    END
  END RN
  PIN Q
    DIRECTION OUTPUT ;
    USE SIGNAL ;
    PORT
      LAYER metal1 ;
        RECT 5.0000 1.0150 5.0700 1.2250 ;
        RECT 4.8100 0.4550 5.0700 0.5250 ;
        RECT 4.8100 1.0150 5.0700 1.0850 ;
      LAYER via1 ;
        RECT 4.8125 0.4575 4.8775 0.5225 ;
        RECT 4.8125 1.0175 4.8775 1.0825 ;
      LAYER metal2 ;
        RECT 4.8100 0.4550 4.8800 1.0850 ;
    END
  END Q
  PIN QN
    DIRECTION OUTPUT ;
    USE SIGNAL ;
    PORT
      LAYER metal1 ;
        RECT 5.3800 1.0150 5.4500 1.2250 ;
        RECT 5.1900 0.4550 5.4500 0.5250 ;
        RECT 5.1900 1.0150 5.4500 1.0850 ;
      LAYER via1 ;
        RECT 5.1925 0.4575 5.2575 0.5225 ;
        RECT 5.1925 1.0175 5.2575 1.0825 ;
      LAYER metal2 ;
        RECT 5.1900 0.4550 5.2600 1.0850 ;
    END
  END QN
  PIN VDD
    DIRECTION INOUT ;
    USE POWER ;
    SHAPE ABUTMENT ;
    PORT
      LAYER metal1 ;
        RECT 0.0000 1.3150 5.8900 1.4850 ;
        RECT 1.2000 1.1550 1.2700 1.3650 ;
        RECT 1.9600 1.1550 2.0300 1.3650 ;
        RECT 2.3400 1.1550 2.4100 1.3650 ;
        RECT 4.0500 1.1550 4.1200 1.3650 ;
        RECT 4.8100 1.1550 4.8800 1.3650 ;
        RECT 5.1900 1.1550 5.2600 1.3650 ;
        RECT 5.5700 1.1550 5.6400 1.3650 ;
    END
  END VDD
  PIN VSS
    DIRECTION INOUT ;
    USE GROUND ;
    SHAPE ABUTMENT ;
    PORT
      LAYER metal1 ;
        RECT 0.0000 -0.0850 5.8900 0.0850 ;
        RECT 1.2000 0.0350 1.2700 0.2450 ;
        RECT 2.3400 0.0350 2.4100 0.2450 ;
        RECT 4.0500 0.0350 4.1200 0.2450 ;
        RECT 4.6200 0.0350 4.6900 0.2450 ;
        RECT 5.5700 0.0350 5.6400 0.2450 ;
    END
  END VSS
  OBS
    LAYER metal1 ;
      RECT 3.9550 0.3150 4.0250 0.9450 ;
      RECT 4.2400 0.1750 4.3100 0.3850 ;
      RECT 4.4300 0.8750 4.5000 1.0850 ;
      RECT 5.2850 0.7350 5.3550 0.9450 ;
      RECT 4.2400 0.1750 4.5000 0.2450 ;
      RECT 3.9550 0.3150 4.3100 0.3850 ;
      RECT 3.9550 0.8750 5.3550 0.9450 ;
      RECT 0.0600 1.0150 0.1300 1.2250 ;
      RECT 0.8200 1.1550 1.0800 1.2250 ;
      RECT 4.2400 1.1550 4.6900 1.2250 ;
      RECT 3.4800 0.1750 3.9300 0.2450 ;
      RECT 3.8600 1.0150 3.9300 1.2250 ;
      RECT 2.9100 1.1550 3.1700 1.2250 ;
      RECT 0.1550 0.8050 0.2250 0.9450 ;
      RECT 1.2950 0.8050 1.3650 0.9450 ;
      RECT 3.3850 0.5950 3.4550 0.9450 ;
      RECT 5.5700 0.5250 5.6400 0.6650 ;
      RECT 5.7600 0.2450 5.8300 0.5950 ;
      RECT 5.7600 0.9450 5.8300 1.0850 ;
      RECT 5.5700 0.5250 5.8300 0.5950 ;
      RECT 3.3850 0.5950 3.8350 0.6650 ;
      RECT 4.6200 0.5950 5.6400 0.6650 ;
      RECT 0.1550 0.8750 3.4550 0.9450 ;
      RECT 5.6650 1.0150 5.8300 1.0850 ;
      RECT 0.6300 0.3150 0.7000 0.4550 ;
      RECT 1.3900 0.1750 1.4600 0.3150 ;
      RECT 2.7200 0.6650 2.7900 0.8050 ;
      RECT 1.3900 0.2450 1.5550 0.3150 ;
      RECT 0.6300 0.3150 0.8900 0.3850 ;
      RECT 0.4400 0.3850 0.7000 0.4550 ;
      RECT 2.7200 0.6650 3.1700 0.7350 ;
      RECT 1.4850 0.7350 2.7900 0.8050 ;
      RECT 1.2950 1.0150 1.5550 1.0850 ;
      RECT 0.2500 0.2450 0.3200 0.5950 ;
      RECT 0.6300 0.5250 0.7000 0.8050 ;
      RECT 1.5800 0.5250 1.6500 0.6650 ;
      RECT 0.2500 0.5250 1.6500 0.5950 ;
      RECT 1.5800 0.5950 2.0300 0.6650 ;
      RECT 0.2500 1.1550 0.5100 1.2250 ;
      RECT 1.6750 0.1750 1.7450 0.4550 ;
      RECT 1.6750 0.1750 2.2200 0.2450 ;
      RECT 2.7200 0.1750 3.1700 0.2450 ;
      RECT 1.1050 0.3850 1.7450 0.4550 ;
      RECT 2.0550 1.0150 2.3150 1.0850 ;
      RECT 3.2900 1.0150 3.5500 1.0850 ;
      RECT 3.2900 0.2450 3.3600 0.4550 ;
      RECT 3.5750 0.7350 3.6450 0.9450 ;
      RECT 3.6700 0.3850 3.7400 0.5250 ;
      RECT 3.6700 0.8750 3.7400 1.2250 ;
      RECT 4.1450 0.4550 4.2150 0.8050 ;
      RECT 3.2900 0.3850 3.7400 0.4550 ;
      RECT 3.6700 0.4550 3.8350 0.5250 ;
      RECT 4.1450 0.7350 4.7850 0.8050 ;
      RECT 3.5750 0.8750 3.7400 0.9450 ;
      RECT 3.2900 1.1550 3.7400 1.2250 ;
      RECT 2.5300 0.2450 2.6000 0.3850 ;
      RECT 2.7200 0.3150 2.7900 0.5950 ;
      RECT 2.5300 0.3150 2.9800 0.3850 ;
      RECT 4.4300 0.3850 4.6900 0.4550 ;
      RECT 2.4350 1.0150 2.6950 1.0850 ;
      RECT 0.4400 0.1750 1.0800 0.2450 ;
    LAYER via1 ;
      RECT 0.0625 1.1575 0.1275 1.2225 ;
      RECT 0.8225 1.1575 0.8875 1.2225 ;
      RECT 3.1025 1.1575 3.1675 1.2225 ;
      RECT 3.8625 1.1575 3.9275 1.2225 ;
      RECT 3.7675 0.5975 3.8325 0.6625 ;
      RECT 4.6225 0.5975 4.6875 0.6625 ;
      RECT 5.7625 0.4575 5.8275 0.5225 ;
      RECT 5.7625 0.9475 5.8275 1.0125 ;
      RECT 0.8225 0.3175 0.8875 0.3825 ;
      RECT 1.3925 0.2475 1.4575 0.3125 ;
      RECT 1.3925 1.0175 1.4575 1.0825 ;
      RECT 1.4875 0.7375 1.5525 0.8025 ;
      RECT 0.2525 1.1575 0.3175 1.2225 ;
      RECT 0.6325 0.7375 0.6975 0.8025 ;
      RECT 2.1525 0.1775 2.2175 0.2425 ;
      RECT 2.1525 1.0175 2.2175 1.0825 ;
      RECT 2.7225 0.1775 2.7875 0.2425 ;
      RECT 3.2925 1.0175 3.3575 1.0825 ;
      RECT 3.5775 0.7375 3.6425 0.8025 ;
      RECT 3.6725 0.4575 3.7375 0.5225 ;
      RECT 4.1475 0.4575 4.2125 0.5225 ;
      RECT 2.5325 1.0175 2.5975 1.0825 ;
      RECT 2.7225 0.5275 2.7875 0.5925 ;
      RECT 2.9125 0.3175 2.9775 0.3825 ;
      RECT 4.4325 0.3875 4.4975 0.4525 ;
    LAYER metal2 ;
      RECT 0.0600 1.1550 0.1300 1.3650 ;
      RECT 0.8200 1.1550 0.8900 1.3650 ;
      RECT 0.0600 1.2950 0.8900 1.3650 ;
      RECT 3.1000 1.1550 3.9300 1.2250 ;
      RECT 5.7600 0.4550 5.8300 1.0150 ;
      RECT 3.7650 0.5950 4.6900 0.6650 ;
      RECT 0.8200 0.2450 0.8900 0.3850 ;
      RECT 1.3900 0.2450 1.4600 1.0850 ;
      RECT 0.8200 0.2450 1.4600 0.3150 ;
      RECT 1.3900 0.7350 1.5550 0.8050 ;
      RECT 0.6300 0.7350 0.7000 1.2250 ;
      RECT 0.2500 1.1550 0.7000 1.2250 ;
      RECT 2.1500 0.1750 2.2200 1.2250 ;
      RECT 2.8150 1.0150 2.8850 1.2250 ;
      RECT 2.1500 0.1750 2.7900 0.2450 ;
      RECT 2.8150 1.0150 3.5500 1.0850 ;
      RECT 2.1500 1.1550 2.8850 1.2250 ;
      RECT 3.5750 0.4550 3.6450 0.8050 ;
      RECT 3.5750 0.4550 4.2150 0.5250 ;
      RECT 2.5300 0.8750 2.6000 1.0850 ;
      RECT 2.6250 0.8050 2.6950 0.9450 ;
      RECT 2.7200 0.5250 2.7900 0.8750 ;
      RECT 4.3350 0.3150 4.4050 0.4550 ;
      RECT 2.9100 0.3150 4.4050 0.3850 ;
      RECT 4.3350 0.3850 4.5000 0.4550 ;
      RECT 2.6250 0.8050 2.7900 0.8750 ;
      RECT 2.5300 0.8750 2.6950 0.9450 ;
  END
END DFFR_X2

MACRO DFFS_X1
  CLASS CORE ;
  ORIGIN 0 0 ;
  FOREIGN DFFS_X1 0 0 ;
  SIZE 5.51 BY 1.40 ;
  SYMMETRY X Y ;
  SITE core ;
  PIN D
    DIRECTION INPUT ;
    USE SIGNAL ;
    PORT
      LAYER metal1 ;
        RECT 0.8200 0.8750 0.8900 1.0850 ;
        RECT 0.9150 0.6650 0.9850 0.9450 ;
        RECT 1.2000 0.1750 1.2700 0.3850 ;
        RECT 1.2950 0.3150 1.3650 0.7350 ;
        RECT 1.2000 0.3150 1.3650 0.3850 ;
        RECT 0.9150 0.6650 1.3650 0.7350 ;
        RECT 0.8200 0.8750 0.9850 0.9450 ;
    END
  END D
  PIN CK
    DIRECTION INPUT ;
    USE CLOCK ;
    PORT
      LAYER metal1 ;
        RECT 0.0600 0.5250 0.1300 0.7350 ;
    END
  END CK
  PIN SN
    DIRECTION INPUT ;
    USE SIGNAL ;
    PORT
      LAYER metal1 ;
        RECT 2.3400 0.6650 2.4100 0.8050 ;
        RECT 3.7650 0.8050 3.8350 0.9450 ;
        RECT 3.8600 0.6650 3.9300 0.8750 ;
        RECT 4.2400 0.5250 4.3100 0.7350 ;
        RECT 4.2400 0.5950 4.4050 0.6650 ;
        RECT 2.2450 0.6650 2.4100 0.7350 ;
        RECT 3.8600 0.6650 4.3100 0.7350 ;
        RECT 3.7650 0.8050 3.9300 0.8750 ;
        RECT 3.6700 0.8750 3.8350 0.9450 ;
      LAYER via1 ;
        RECT 2.3425 0.7375 2.4075 0.8025 ;
        RECT 3.6725 0.8775 3.7375 0.9425 ;
      LAYER metal2 ;
        RECT 2.3400 0.7350 2.4100 1.2250 ;
        RECT 2.7200 1.0150 2.7900 1.2250 ;
        RECT 3.6700 0.8750 3.7400 1.0850 ;
        RECT 2.7200 1.0150 3.7400 1.0850 ;
        RECT 2.3400 1.1550 2.7900 1.2250 ;
    END
  END SN
  PIN Q
    DIRECTION OUTPUT ;
    USE SIGNAL ;
    PORT
      LAYER metal1 ;
        RECT 5.0000 0.1750 5.0700 0.4550 ;
        RECT 5.0000 0.3850 5.2600 0.4550 ;
        RECT 4.9050 1.0150 5.1650 1.0850 ;
      LAYER via1 ;
        RECT 5.0025 1.0175 5.0675 1.0825 ;
        RECT 5.1925 0.3875 5.2575 0.4525 ;
      LAYER metal2 ;
        RECT 5.0000 0.7350 5.0700 1.0850 ;
        RECT 5.1900 0.3850 5.2600 0.8050 ;
        RECT 5.0000 0.7350 5.2600 0.8050 ;
    END
  END Q
  PIN QN
    DIRECTION OUTPUT ;
    USE SIGNAL ;
    PORT
      LAYER metal1 ;
        RECT 5.3800 0.1750 5.4500 0.5950 ;
        RECT 5.3800 1.0150 5.4500 1.1550 ;
        RECT 5.2850 1.0150 5.4500 1.0850 ;
      LAYER via1 ;
        RECT 5.3825 0.5275 5.4475 0.5925 ;
        RECT 5.3825 1.0175 5.4475 1.0825 ;
      LAYER metal2 ;
        RECT 5.3800 0.5250 5.4500 1.0850 ;
    END
  END QN
  PIN VDD
    DIRECTION INOUT ;
    USE POWER ;
    SHAPE ABUTMENT ;
    PORT
      LAYER metal1 ;
        RECT 0.0000 1.3150 5.5100 1.4850 ;
        RECT 0.2500 1.1550 0.3200 1.3650 ;
        RECT 1.7700 1.1550 1.8400 1.3650 ;
        RECT 2.1500 1.1550 2.2200 1.3650 ;
        RECT 4.2400 1.1550 4.3100 1.3650 ;
        RECT 4.6200 1.1550 4.6900 1.3650 ;
        RECT 5.1900 1.1550 5.2600 1.3650 ;
        RECT 2.1500 1.1550 2.4100 1.2250 ;
    END
  END VDD
  PIN VSS
    DIRECTION INOUT ;
    USE GROUND ;
    SHAPE ABUTMENT ;
    PORT
      LAYER metal1 ;
        RECT 0.0000 -0.0850 5.5100 0.0850 ;
        RECT 0.2500 0.0350 0.3200 0.2450 ;
        RECT 1.7700 0.0350 1.8400 0.2450 ;
        RECT 2.1500 0.0350 2.2200 0.2450 ;
        RECT 2.8150 0.0350 2.8850 0.1750 ;
        RECT 2.9100 0.0350 2.9800 0.2450 ;
        RECT 4.2400 0.0350 4.3100 0.2450 ;
        RECT 5.1900 0.0350 5.2600 0.2450 ;
        RECT 2.8150 0.0350 2.9800 0.1050 ;
        RECT 2.8150 0.1050 2.9800 0.1750 ;
        RECT 2.1500 0.1750 2.4100 0.2450 ;
    END
  END VSS
  OBS
    LAYER metal1 ;
      RECT 4.1450 0.8050 4.2150 0.9450 ;
      RECT 4.2400 0.8750 4.3100 1.0150 ;
      RECT 4.4300 0.9450 4.5000 1.0850 ;
      RECT 4.6200 0.8750 4.6900 1.0150 ;
      RECT 4.8100 0.4550 4.8800 0.9450 ;
      RECT 5.2850 0.8050 5.3550 0.9450 ;
      RECT 4.6200 0.4550 4.8800 0.5250 ;
      RECT 4.1450 0.8750 4.3100 0.9450 ;
      RECT 4.6200 0.8750 5.3550 0.9450 ;
      RECT 4.2400 0.9450 4.6900 1.0150 ;
      RECT 1.2000 1.0150 1.6500 1.0850 ;
      RECT 3.1000 0.1750 3.3600 0.2450 ;
      RECT 3.8600 0.1750 4.1200 0.2450 ;
      RECT 3.6700 1.0150 4.1200 1.0850 ;
      RECT 0.0600 0.2450 0.1300 0.4550 ;
      RECT 0.0600 0.8750 0.1300 1.2250 ;
      RECT 0.3450 0.3850 0.4150 0.9450 ;
      RECT 1.1050 0.8050 1.1750 0.9450 ;
      RECT 2.5300 0.7350 2.6000 0.9450 ;
      RECT 3.2900 0.6650 3.3600 0.8050 ;
      RECT 0.0600 0.3850 0.4150 0.4550 ;
      RECT 2.9100 0.7350 3.3600 0.8050 ;
      RECT 0.0600 0.8750 0.4150 0.9450 ;
      RECT 1.1050 0.8750 2.6000 0.9450 ;
      RECT 0.5350 0.2450 0.6050 0.5250 ;
      RECT 0.5350 0.8050 0.6050 1.0850 ;
      RECT 0.6300 0.4550 0.7000 0.8750 ;
      RECT 0.4400 0.2450 0.6050 0.3150 ;
      RECT 0.5350 0.4550 0.7000 0.5250 ;
      RECT 0.6300 0.5250 1.0800 0.5950 ;
      RECT 2.9100 0.5250 3.6450 0.5950 ;
      RECT 0.5350 0.8050 0.7000 0.8750 ;
      RECT 0.4400 1.0150 0.6050 1.0850 ;
      RECT 1.0100 0.2450 1.0800 0.3850 ;
      RECT 1.0100 1.0150 1.0800 1.2250 ;
      RECT 0.9150 0.3150 1.0800 0.3850 ;
      RECT 1.4850 0.7350 1.9350 0.8050 ;
      RECT 1.9600 0.2450 2.0300 0.4550 ;
      RECT 2.2450 0.3850 2.3150 0.5950 ;
      RECT 2.7200 0.2450 2.7900 1.0850 ;
      RECT 3.1000 0.8750 3.1700 1.0850 ;
      RECT 3.6700 0.2450 3.7400 0.3850 ;
      RECT 3.6700 0.3150 3.9300 0.3850 ;
      RECT 1.7700 0.3850 2.3150 0.4550 ;
      RECT 2.2450 0.5250 2.7900 0.5950 ;
      RECT 2.7200 0.8750 3.1700 0.9450 ;
      RECT 3.1000 1.0150 3.3600 1.0850 ;
      RECT 3.4800 0.2450 3.5500 0.3850 ;
      RECT 3.4800 0.8750 3.5500 1.0850 ;
      RECT 3.3850 0.3150 3.5500 0.3850 ;
      RECT 5.0000 0.5950 5.2600 0.6650 ;
      RECT 4.4300 0.7350 4.6900 0.8050 ;
      RECT 2.5300 0.2450 2.6000 0.3850 ;
      RECT 2.4350 0.3150 2.6000 0.3850 ;
      RECT 2.9100 0.3850 3.1700 0.4550 ;
      RECT 2.3400 1.0150 2.6000 1.0850 ;
      RECT 1.9600 1.0150 2.0300 1.2250 ;
      RECT 2.8150 1.1550 3.0750 1.2250 ;
      RECT 0.7250 0.1750 0.7950 0.3150 ;
      RECT 0.7250 0.1750 0.8900 0.2450 ;
      RECT 1.3900 0.1750 1.6500 0.2450 ;
    LAYER via1 ;
      RECT 3.2925 0.1775 3.3575 0.2425 ;
      RECT 3.8625 0.1775 3.9275 0.2425 ;
      RECT 0.0625 1.1575 0.1275 1.2225 ;
      RECT 1.2025 0.8775 1.2675 0.9425 ;
      RECT 2.5325 0.7375 2.5975 0.8025 ;
      RECT 2.9125 0.7375 2.9775 0.8025 ;
      RECT 1.0125 0.5275 1.0775 0.5925 ;
      RECT 2.9125 0.5275 2.9775 0.5925 ;
      RECT 0.9175 0.3175 0.9825 0.3825 ;
      RECT 1.0125 1.0175 1.0775 1.0825 ;
      RECT 1.4875 0.7375 1.5525 0.8025 ;
      RECT 2.7225 0.2475 2.7875 0.3125 ;
      RECT 3.8625 0.3175 3.9275 0.3825 ;
      RECT 3.4825 0.2475 3.5475 0.3125 ;
      RECT 3.4825 0.8775 3.5475 0.9425 ;
      RECT 4.4325 0.7375 4.4975 0.8025 ;
      RECT 5.0025 0.5975 5.0675 0.6625 ;
      RECT 2.5325 0.2475 2.5975 0.3125 ;
      RECT 2.5325 1.0175 2.5975 1.0825 ;
      RECT 2.9125 0.3875 2.9775 0.4525 ;
      RECT 1.9625 1.1575 2.0275 1.2225 ;
      RECT 2.9125 1.1575 2.9775 1.2225 ;
      RECT 0.8225 0.1775 0.8875 0.2425 ;
      RECT 1.5825 0.1775 1.6475 0.2425 ;
    LAYER metal2 ;
      RECT 3.2900 0.1050 3.3600 0.2450 ;
      RECT 3.6700 0.1050 3.7400 0.2450 ;
      RECT 3.2900 0.1050 3.7400 0.1750 ;
      RECT 3.6700 0.1750 3.9300 0.2450 ;
      RECT 1.2000 0.8750 1.2700 1.2250 ;
      RECT 2.5300 0.7350 2.9800 0.8050 ;
      RECT 0.0600 1.1550 1.2700 1.2250 ;
      RECT 1.0100 0.5250 2.9800 0.5950 ;
      RECT 0.8200 0.3150 0.8900 1.0850 ;
      RECT 1.0100 0.2450 1.0800 0.3850 ;
      RECT 0.8200 0.3150 1.0800 0.3850 ;
      RECT 0.8200 0.7350 1.5550 0.8050 ;
      RECT 0.8200 1.0150 1.0800 1.0850 ;
      RECT 2.7200 -0.0350 2.7900 0.3150 ;
      RECT 3.8600 -0.0350 3.9300 0.1050 ;
      RECT 4.0500 0.0350 4.1200 0.3850 ;
      RECT 2.7200 -0.0350 3.9300 0.0350 ;
      RECT 3.8600 0.0350 4.1200 0.1050 ;
      RECT 3.8600 0.3150 4.1200 0.3850 ;
      RECT 3.4800 0.2450 3.5500 0.9450 ;
      RECT 3.8600 0.7350 3.9300 0.9450 ;
      RECT 4.4300 0.7350 4.5000 0.9450 ;
      RECT 4.5250 0.5950 4.5950 0.8050 ;
      RECT 4.5250 0.5950 5.0700 0.6650 ;
      RECT 3.4800 0.7350 3.9300 0.8050 ;
      RECT 4.4300 0.7350 4.5950 0.8050 ;
      RECT 3.8600 0.8750 4.5000 0.9450 ;
      RECT 2.5300 0.2450 2.6000 0.4550 ;
      RECT 2.5300 0.8750 2.6000 1.0850 ;
      RECT 3.1000 0.3850 3.1700 0.9450 ;
      RECT 2.5300 0.3850 3.1700 0.4550 ;
      RECT 2.5300 0.8750 3.1700 0.9450 ;
      RECT 1.9600 1.1550 2.0300 1.3650 ;
      RECT 2.9100 1.1550 2.9800 1.3650 ;
      RECT 1.9600 1.2950 2.9800 1.3650 ;
      RECT 0.8200 -0.0350 0.8900 0.2450 ;
      RECT 1.5800 -0.0350 1.6500 0.2450 ;
      RECT 0.8200 -0.0350 1.6500 0.0350 ;
  END
END DFFS_X1

MACRO DFFS_X2
  CLASS CORE ;
  ORIGIN 0 0 ;
  FOREIGN DFFS_X2 0 0 ;
  SIZE 5.70 BY 1.40 ;
  SYMMETRY X Y ;
  SITE core ;
  PIN D
    DIRECTION INPUT ;
    USE SIGNAL ;
    PORT
      LAYER metal1 ;
        RECT 0.4400 0.1750 0.5100 0.3850 ;
        RECT 0.6300 0.3150 0.7000 0.5950 ;
        RECT 1.0100 0.9450 1.0800 1.0850 ;
        RECT 0.4400 0.3150 0.7000 0.3850 ;
        RECT 1.0100 0.9450 1.1750 1.0150 ;
      LAYER via1 ;
        RECT 0.6325 0.5275 0.6975 0.5925 ;
        RECT 1.0125 0.9475 1.0775 1.0125 ;
      LAYER metal2 ;
        RECT 0.4400 0.5250 0.5100 1.0150 ;
        RECT 0.4400 0.5250 0.7000 0.5950 ;
        RECT 0.4400 0.9450 1.0800 1.0150 ;
    END
  END D
  PIN CK
    DIRECTION INPUT ;
    USE CLOCK ;
    PORT
      LAYER metal1 ;
        RECT 0.0600 0.4550 0.1300 0.6650 ;
    END
  END CK
  PIN SN
    DIRECTION INPUT ;
    USE SIGNAL ;
    PORT
      LAYER metal1 ;
        RECT 5.5700 0.5250 5.6400 0.7350 ;
    END
  END SN
  PIN Q
    DIRECTION OUTPUT ;
    USE SIGNAL ;
    PORT
      LAYER metal1 ;
        RECT 4.6200 1.0150 4.6900 1.2250 ;
        RECT 4.7150 0.8750 4.7850 1.0850 ;
        RECT 4.4300 0.4550 4.6900 0.5250 ;
        RECT 4.7150 0.8750 4.8800 0.9450 ;
        RECT 4.6200 1.0150 4.7850 1.0850 ;
      LAYER via1 ;
        RECT 4.6225 0.4575 4.6875 0.5225 ;
        RECT 4.8125 0.8775 4.8775 0.9425 ;
      LAYER metal2 ;
        RECT 4.7150 0.4550 4.7850 0.5950 ;
        RECT 4.8100 0.5250 4.8800 0.9450 ;
        RECT 4.6200 0.4550 4.7850 0.5250 ;
        RECT 4.7150 0.5250 4.8800 0.5950 ;
    END
  END Q
  PIN QN
    DIRECTION OUTPUT ;
    USE SIGNAL ;
    PORT
      LAYER metal1 ;
        RECT 4.2400 1.0150 4.3100 1.2250 ;
        RECT 4.0500 0.4550 4.3100 0.5250 ;
        RECT 4.0500 1.0150 4.3100 1.0850 ;
      LAYER via1 ;
        RECT 4.0525 0.4575 4.1175 0.5225 ;
        RECT 4.0525 1.0175 4.1175 1.0825 ;
      LAYER metal2 ;
        RECT 4.0500 0.4550 4.1200 1.0850 ;
        RECT 4.0500 0.4550 4.3100 0.5250 ;
    END
  END QN
  PIN VDD
    DIRECTION INOUT ;
    USE POWER ;
    SHAPE ABUTMENT ;
    PORT
      LAYER metal1 ;
        RECT 0.0000 1.3150 5.7000 1.4850 ;
        RECT 0.0600 1.1550 0.1300 1.3650 ;
        RECT 1.3900 1.1550 1.4600 1.3650 ;
        RECT 1.9600 1.1550 2.0300 1.3650 ;
        RECT 3.8600 1.1550 3.9300 1.3650 ;
        RECT 4.4300 1.1550 4.5000 1.3650 ;
        RECT 4.8100 1.1550 4.8800 1.3650 ;
        RECT 5.3800 1.1550 5.4500 1.3650 ;
        RECT 3.8600 1.1550 4.1200 1.2250 ;
        RECT 4.8100 1.1550 5.0700 1.2250 ;
    END
  END VDD
  PIN VSS
    DIRECTION INOUT ;
    USE GROUND ;
    SHAPE ABUTMENT ;
    PORT
      LAYER metal1 ;
        RECT 0.0000 -0.0850 5.7000 0.0850 ;
        RECT 0.0600 0.0350 0.1300 0.2450 ;
        RECT 1.3900 0.0350 1.4600 0.2450 ;
        RECT 2.1500 0.0350 2.2200 0.2450 ;
        RECT 2.7200 0.0350 2.7900 0.2450 ;
        RECT 4.0500 0.0350 4.1200 0.2450 ;
        RECT 4.4300 0.0350 4.5000 0.2450 ;
        RECT 5.3800 0.0350 5.4500 0.2450 ;
        RECT 3.8600 0.1750 4.1200 0.2450 ;
    END
  END VSS
  OBS
    LAYER metal1 ;
      RECT 4.8100 0.4550 4.8800 0.6650 ;
      RECT 5.1900 0.4550 5.2600 0.5950 ;
      RECT 5.1900 0.8750 5.2600 1.0850 ;
      RECT 5.2850 0.5250 5.3550 0.9450 ;
      RECT 4.8100 0.4550 5.2600 0.5250 ;
      RECT 5.1900 0.5250 5.3550 0.5950 ;
      RECT 3.8600 0.5950 4.8800 0.6650 ;
      RECT 5.1900 0.8750 5.3550 0.9450 ;
      RECT 0.4400 1.1550 1.2700 1.2250 ;
      RECT 2.9100 0.1750 2.9800 0.3850 ;
      RECT 3.6700 0.1750 3.7400 0.3850 ;
      RECT 3.4800 1.0150 3.7400 1.0850 ;
      RECT 0.2500 0.2450 0.3200 0.5250 ;
      RECT 0.2500 0.8750 0.3200 1.0850 ;
      RECT 0.3450 0.8050 0.4150 0.9450 ;
      RECT 0.4400 0.4550 0.5100 0.8750 ;
      RECT 1.6750 0.6650 1.7450 0.8050 ;
      RECT 0.2500 0.4550 0.5100 0.5250 ;
      RECT 0.4400 0.6650 0.7000 0.7350 ;
      RECT 1.6750 0.7350 2.2200 0.8050 ;
      RECT 2.5300 0.7350 3.0750 0.8050 ;
      RECT 0.3450 0.8050 0.5100 0.8750 ;
      RECT 0.2500 0.8750 0.4150 0.9450 ;
      RECT 1.0100 0.6650 1.0800 0.8750 ;
      RECT 1.9600 0.2450 2.0300 0.4550 ;
      RECT 3.2900 0.3150 3.3600 0.5250 ;
      RECT 1.0100 0.8050 1.1750 0.8750 ;
      RECT 1.9600 1.0150 2.2200 1.0850 ;
      RECT 0.8200 0.1750 0.8900 1.0850 ;
      RECT 0.6300 0.1750 0.8900 0.2450 ;
      RECT 0.8200 0.3850 1.8400 0.4550 ;
      RECT 0.6300 1.0150 0.8900 1.0850 ;
      RECT 1.2950 0.5250 1.3650 0.9450 ;
      RECT 2.3400 0.2450 2.4100 1.0850 ;
      RECT 2.9100 0.8750 2.9800 1.0850 ;
      RECT 3.4800 0.2450 3.5500 0.9450 ;
      RECT 1.5800 0.2450 1.8400 0.3150 ;
      RECT 2.3400 0.2450 2.6000 0.3150 ;
      RECT 1.2950 0.5250 1.4600 0.5950 ;
      RECT 1.2950 0.8750 3.5500 0.9450 ;
      RECT 2.3400 1.0150 2.6000 1.0850 ;
      RECT 3.1000 0.1750 3.1700 0.6650 ;
      RECT 3.1950 0.5950 3.2650 0.8050 ;
      RECT 4.5250 0.7350 4.5950 0.9450 ;
      RECT 3.1000 0.1750 3.3600 0.2450 ;
      RECT 3.1000 0.5950 3.2650 0.6650 ;
      RECT 4.5250 0.7350 5.1650 0.8050 ;
      RECT 3.6700 0.8750 4.5950 0.9450 ;
      RECT 3.1000 1.0150 3.3600 1.0850 ;
      RECT 2.8150 0.5250 2.8850 0.6650 ;
      RECT 5.5700 0.2450 5.6400 0.3850 ;
      RECT 5.5700 0.8750 5.6400 1.0850 ;
      RECT 5.4750 0.3150 5.6400 0.3850 ;
      RECT 2.8150 0.5250 2.9800 0.5950 ;
      RECT 5.4750 0.8750 5.6400 0.9450 ;
      RECT 1.7700 1.0150 1.8400 1.2250 ;
      RECT 1.5800 1.0150 1.8400 1.0850 ;
      RECT 2.6250 1.1550 2.8850 1.2250 ;
      RECT 1.0100 0.1750 1.2700 0.2450 ;
    LAYER via1 ;
      RECT 2.9125 0.1775 2.9775 0.2425 ;
      RECT 3.6725 0.1775 3.7375 0.2425 ;
      RECT 0.6325 0.6675 0.6975 0.7325 ;
      RECT 1.6775 0.6675 1.7425 0.7325 ;
      RECT 2.1525 0.7375 2.2175 0.8025 ;
      RECT 2.5325 0.7375 2.5975 0.8025 ;
      RECT 1.1075 0.8075 1.1725 0.8725 ;
      RECT 1.9625 0.3875 2.0275 0.4525 ;
      RECT 1.9625 1.0175 2.0275 1.0825 ;
      RECT 3.2925 0.3875 3.3575 0.4525 ;
      RECT 1.3925 0.5275 1.4575 0.5925 ;
      RECT 1.5825 0.2475 1.6475 0.3125 ;
      RECT 3.1975 0.7375 3.2625 0.8025 ;
      RECT 3.1975 1.0175 3.2625 1.0825 ;
      RECT 3.6725 0.8775 3.7375 0.9425 ;
      RECT 2.9125 0.5275 2.9775 0.5925 ;
      RECT 5.4775 0.3175 5.5425 0.3825 ;
      RECT 5.4775 0.8775 5.5425 0.9425 ;
      RECT 1.7725 1.1575 1.8375 1.2225 ;
      RECT 2.6275 1.1575 2.6925 1.2225 ;
    LAYER metal2 ;
      RECT 2.9100 0.1750 3.7400 0.2450 ;
      RECT 0.6300 0.6650 1.7450 0.7350 ;
      RECT 2.1500 0.7350 2.6000 0.8050 ;
      RECT 1.9600 0.3850 2.0300 1.0850 ;
      RECT 1.9600 0.3850 3.3600 0.4550 ;
      RECT 1.1050 0.8050 2.0300 0.8750 ;
      RECT 1.9600 1.0150 2.2200 1.0850 ;
      RECT 1.3900 0.2450 1.4600 0.5950 ;
      RECT 1.3900 0.2450 1.6500 0.3150 ;
      RECT 3.1950 0.7350 3.2650 1.0850 ;
      RECT 3.1950 0.8750 3.7400 0.9450 ;
      RECT 3.4800 0.3150 3.5500 0.5950 ;
      RECT 5.3800 0.3150 5.4500 0.9450 ;
      RECT 3.4800 0.3150 5.6400 0.3850 ;
      RECT 2.9100 0.5250 3.5500 0.5950 ;
      RECT 5.3800 0.8750 5.5450 0.9450 ;
      RECT 1.7700 1.1550 2.7900 1.2250 ;
  END
END DFFS_X2

MACRO DFFRS_X1
  CLASS CORE ;
  ORIGIN 0 0 ;
  FOREIGN DFFRS_X1 0 0 ;
  SIZE 7.98 BY 1.40 ;
  SYMMETRY X Y ;
  SITE core ;
  PIN D
    DIRECTION INPUT ;
    USE SIGNAL ;
    PORT
      LAYER metal1 ;
        RECT 1.4850 0.1750 1.5550 0.3150 ;
        RECT 1.5800 0.1750 1.6500 0.3850 ;
        RECT 1.3900 0.1750 1.6500 0.2450 ;
        RECT 1.4850 0.2450 1.6500 0.3150 ;
        RECT 0.8200 1.0150 1.0800 1.0850 ;
      LAYER via1 ;
        RECT 1.0125 1.0175 1.0775 1.0825 ;
        RECT 1.3925 0.1775 1.4575 0.2425 ;
      LAYER metal2 ;
        RECT 1.0100 0.1050 1.0800 1.0850 ;
        RECT 1.3900 0.1050 1.4600 0.2450 ;
        RECT 1.0100 0.1050 1.4600 0.1750 ;
    END
  END D
  PIN CK
    DIRECTION INPUT ;
    USE CLOCK ;
    PORT
      LAYER metal1 ;
        RECT 0.0600 0.5250 0.1300 0.7350 ;
    END
  END CK
  PIN RN
    DIRECTION INPUT ;
    USE SIGNAL ;
    PORT
      LAYER metal1 ;
        RECT 4.8100 0.5250 4.8800 0.7350 ;
        RECT 4.8100 0.5250 5.7350 0.5950 ;
    END
  END RN
  PIN SN
    DIRECTION INPUT ;
    USE SIGNAL ;
    PORT
      LAYER metal1 ;
        RECT 6.7100 0.5250 6.7800 0.7350 ;
        RECT 6.5200 0.6650 6.7800 0.7350 ;
        RECT 5.4750 0.7350 6.1150 0.8050 ;
      LAYER via1 ;
        RECT 6.0475 0.7375 6.1125 0.8025 ;
        RECT 6.5225 0.6675 6.5875 0.7325 ;
      LAYER metal2 ;
        RECT 6.4250 0.6650 6.4950 0.8050 ;
        RECT 6.4250 0.6650 6.5900 0.7350 ;
        RECT 6.0450 0.7350 6.4950 0.8050 ;
    END
  END SN
  PIN Q
    DIRECTION OUTPUT ;
    USE SIGNAL ;
    PORT
      LAYER metal1 ;
        RECT 7.6600 0.1750 7.7300 0.3850 ;
        RECT 7.8500 0.3150 7.9200 1.0850 ;
        RECT 7.6600 0.3150 7.9200 0.3850 ;
    END
  END Q
  PIN QN
    DIRECTION OUTPUT ;
    USE SIGNAL ;
    PORT
      LAYER metal1 ;
        RECT 6.1400 0.3150 6.2100 0.6650 ;
        RECT 6.2350 0.5950 6.3050 1.0850 ;
        RECT 6.3300 0.1750 6.4000 0.3850 ;
        RECT 6.1400 0.3150 6.4000 0.3850 ;
        RECT 6.1400 0.5950 6.3050 0.6650 ;
        RECT 6.2350 1.0150 6.4000 1.0850 ;
    END
  END QN
  PIN VDD
    DIRECTION INOUT ;
    USE POWER ;
    SHAPE ABUTMENT ;
    PORT
      LAYER metal1 ;
        RECT 0.0000 1.3150 7.9800 1.4850 ;
        RECT 0.2500 1.1550 0.3200 1.3650 ;
        RECT 2.1500 1.1550 2.2200 1.3650 ;
        RECT 3.8600 1.1550 3.9300 1.3650 ;
        RECT 4.6200 1.1550 4.6900 1.3650 ;
        RECT 5.5700 1.1550 5.6400 1.3650 ;
        RECT 6.5200 1.1550 6.5900 1.3650 ;
        RECT 6.9000 1.1550 6.9700 1.3650 ;
        RECT 7.6600 1.1550 7.7300 1.3650 ;
    END
  END VDD
  PIN VSS
    DIRECTION INOUT ;
    USE GROUND ;
    SHAPE ABUTMENT ;
    PORT
      LAYER metal1 ;
        RECT 0.0000 -0.0850 7.9800 0.0850 ;
        RECT 0.2500 0.0350 0.3200 0.2450 ;
        RECT 2.1500 0.0350 2.2200 0.2450 ;
        RECT 3.8600 0.0350 3.9300 0.2450 ;
        RECT 4.8100 0.0350 4.8800 0.2450 ;
        RECT 5.5700 0.0350 5.6400 0.2450 ;
        RECT 6.5200 0.0350 6.5900 0.2450 ;
        RECT 7.2800 0.0350 7.3500 0.2450 ;
        RECT 6.5200 0.1750 6.7800 0.2450 ;
        RECT 7.2800 0.1750 7.5400 0.2450 ;
    END
  END VSS
  OBS
    LAYER metal1 ;
      RECT 6.4250 0.8050 6.4950 0.9450 ;
      RECT 7.1850 0.4550 7.2550 0.9450 ;
      RECT 7.2800 0.8750 7.3500 1.0850 ;
      RECT 7.0900 0.4550 7.2550 0.5250 ;
      RECT 3.6700 0.7350 3.9300 0.8050 ;
      RECT 5.0000 0.8750 6.1150 0.9450 ;
      RECT 6.4250 0.8750 7.3500 0.9450 ;
      RECT 4.0500 1.1550 4.5000 1.2250 ;
      RECT 0.8200 0.1750 0.8900 0.3150 ;
      RECT 1.7700 0.1750 2.0300 0.2450 ;
      RECT 0.8200 0.2450 1.0800 0.3150 ;
      RECT 1.3900 1.0150 2.0300 1.0850 ;
      RECT 7.0900 1.0150 7.1600 1.2250 ;
      RECT 6.7100 1.0150 7.1600 1.0850 ;
      RECT 7.0900 1.1550 7.5400 1.2250 ;
      RECT 3.3850 0.1750 3.7400 0.2450 ;
      RECT 2.5300 0.2450 2.7900 0.3150 ;
      RECT 3.1000 1.0150 3.7400 1.0850 ;
      RECT 0.0600 0.2450 0.1300 0.4550 ;
      RECT 0.0600 0.8750 0.1300 1.0850 ;
      RECT 0.3450 0.3850 0.4150 0.9450 ;
      RECT 1.2950 0.5250 1.3650 0.7350 ;
      RECT 0.0600 0.3850 0.4150 0.4550 ;
      RECT 1.2950 0.5250 2.7900 0.5950 ;
      RECT 0.3450 0.6650 0.5100 0.7350 ;
      RECT 0.8200 0.6650 1.3650 0.7350 ;
      RECT 0.0600 0.8750 0.4150 0.9450 ;
      RECT 0.5350 0.8050 0.6050 1.0850 ;
      RECT 0.6300 0.2450 0.7000 0.9450 ;
      RECT 3.0050 0.8050 3.0750 0.9450 ;
      RECT 0.4400 0.2450 0.7000 0.3150 ;
      RECT 0.6300 0.5250 1.0800 0.5950 ;
      RECT 0.5350 0.8050 0.7000 0.8750 ;
      RECT 0.5350 0.8750 2.4100 0.9450 ;
      RECT 2.7200 0.8750 3.0750 0.9450 ;
      RECT 0.4400 1.0150 0.6050 1.0850 ;
      RECT 1.2000 0.2450 1.2700 0.3850 ;
      RECT 1.2000 1.0150 1.2700 1.2250 ;
      RECT 3.8600 0.3850 3.9300 0.5250 ;
      RECT 4.5250 0.5950 4.5950 0.7350 ;
      RECT 1.2000 0.3150 1.3650 0.3850 ;
      RECT 3.5750 0.3850 3.9300 0.4550 ;
      RECT 3.8600 0.4550 4.0250 0.5250 ;
      RECT 4.5250 0.5950 4.6900 0.6650 ;
      RECT 2.5300 0.7350 2.6000 1.0850 ;
      RECT 2.8150 0.6650 2.8850 0.8050 ;
      RECT 3.1950 0.2450 3.2650 0.3850 ;
      RECT 3.2900 0.3150 3.3600 0.9450 ;
      RECT 4.0500 0.8750 4.1200 1.0150 ;
      RECT 4.2400 0.9450 4.3100 1.0850 ;
      RECT 4.3350 0.4550 4.4050 1.0150 ;
      RECT 4.8100 0.9450 4.8800 1.0850 ;
      RECT 3.1000 0.2450 3.2650 0.3150 ;
      RECT 3.1950 0.3150 3.3600 0.3850 ;
      RECT 4.3350 0.4550 4.5000 0.5250 ;
      RECT 2.8150 0.6650 3.3600 0.7350 ;
      RECT 2.0550 0.7350 2.8850 0.8050 ;
      RECT 3.2900 0.8750 4.1200 0.9450 ;
      RECT 4.0500 0.9450 4.8800 1.0150 ;
      RECT 2.5300 1.0150 2.7900 1.0850 ;
      RECT 2.9100 0.1750 2.9800 0.3850 ;
      RECT 2.9100 1.0150 2.9800 1.2250 ;
      RECT 6.9000 0.6650 6.9700 0.8050 ;
      RECT 6.9000 0.7350 7.0650 0.8050 ;
      RECT 7.3750 0.7350 7.6350 0.8050 ;
      RECT 7.3750 0.3850 7.4450 0.5250 ;
      RECT 5.7600 0.2450 6.0200 0.3150 ;
      RECT 7.3750 0.3850 7.5400 0.4550 ;
      RECT 5.6650 1.0150 5.9250 1.0850 ;
      RECT 4.0500 0.2450 4.1200 0.3850 ;
      RECT 5.3800 0.2450 5.4500 0.4550 ;
      RECT 5.0000 0.2450 5.4500 0.3150 ;
      RECT 4.0500 0.3150 4.2150 0.3850 ;
      RECT 5.2850 1.0150 5.5450 1.0850 ;
      RECT 4.2400 0.1750 4.6900 0.2450 ;
    LAYER via1 ;
      RECT 3.8625 0.7375 3.9275 0.8025 ;
      RECT 5.0025 0.8775 5.0675 0.9425 ;
      RECT 6.0475 0.8775 6.1125 0.9425 ;
      RECT 6.4275 0.8775 6.4925 0.9425 ;
      RECT 0.8225 0.1775 0.8875 0.2425 ;
      RECT 1.7725 0.1775 1.8375 0.2425 ;
      RECT 2.7225 0.2475 2.7875 0.3125 ;
      RECT 3.3875 0.1775 3.4525 0.2425 ;
      RECT 0.4425 0.6675 0.5075 0.7325 ;
      RECT 0.8225 0.6675 0.8875 0.7325 ;
      RECT 2.3425 0.8775 2.4075 0.9425 ;
      RECT 2.7225 0.8775 2.7875 0.9425 ;
      RECT 1.2025 0.2475 1.2675 0.3125 ;
      RECT 1.2025 1.0175 1.2675 1.0825 ;
      RECT 3.5775 0.3875 3.6425 0.4525 ;
      RECT 3.9575 0.4575 4.0225 0.5225 ;
      RECT 4.5275 0.5975 4.5925 0.6625 ;
      RECT 2.9125 0.2475 2.9775 0.3125 ;
      RECT 2.9125 1.0175 2.9775 1.0825 ;
      RECT 6.9025 0.7375 6.9675 0.8025 ;
      RECT 7.3775 0.7375 7.4425 0.8025 ;
      RECT 5.7625 0.2475 5.8275 0.3125 ;
      RECT 5.7625 1.0175 5.8275 1.0825 ;
      RECT 7.3775 0.3875 7.4425 0.4525 ;
      RECT 4.0525 0.2475 4.1175 0.3125 ;
      RECT 5.0025 0.2475 5.0675 0.3125 ;
      RECT 5.3825 0.3875 5.4475 0.4525 ;
      RECT 5.3825 1.0175 5.4475 1.0825 ;
    LAYER metal2 ;
      RECT 3.8600 0.7350 3.9300 0.9450 ;
      RECT 3.8600 0.8750 5.0700 0.9450 ;
      RECT 6.0450 0.8750 6.4950 0.9450 ;
      RECT 0.8200 -0.0350 0.8900 0.2450 ;
      RECT 1.7700 -0.0350 1.8400 0.2450 ;
      RECT 0.8200 -0.0350 1.8400 0.0350 ;
      RECT 2.7200 0.1050 2.7900 0.3150 ;
      RECT 3.3850 0.1050 3.4550 0.2450 ;
      RECT 2.7200 0.1050 3.4550 0.1750 ;
      RECT 0.4400 0.6650 0.8900 0.7350 ;
      RECT 2.3400 0.8750 2.7900 0.9450 ;
      RECT 1.2000 0.2450 1.2700 1.0850 ;
      RECT 1.7700 0.3150 1.8400 0.5950 ;
      RECT 1.9600 -0.0350 2.0300 0.3850 ;
      RECT 3.5750 -0.0350 3.6450 0.4550 ;
      RECT 3.9550 0.4550 4.0250 0.6650 ;
      RECT 1.9600 -0.0350 3.6450 0.0350 ;
      RECT 1.7700 0.3150 2.0300 0.3850 ;
      RECT 1.2000 0.5250 1.8400 0.5950 ;
      RECT 3.9550 0.5950 4.5950 0.6650 ;
      RECT 2.9100 0.2450 2.9800 1.2250 ;
      RECT 5.9500 1.0150 6.0200 1.2250 ;
      RECT 6.6150 0.8750 6.6850 1.0850 ;
      RECT 6.9000 0.7350 6.9700 0.9450 ;
      RECT 6.9000 0.7350 7.4450 0.8050 ;
      RECT 6.6150 0.8750 6.9700 0.9450 ;
      RECT 5.9500 1.0150 6.6850 1.0850 ;
      RECT 2.9100 1.1550 6.0200 1.2250 ;
      RECT 5.7600 0.2450 5.8300 1.0850 ;
      RECT 6.5200 0.3150 6.5900 0.5950 ;
      RECT 6.9000 0.3150 6.9700 0.4550 ;
      RECT 6.5200 0.3150 6.9700 0.3850 ;
      RECT 6.9000 0.3850 7.4450 0.4550 ;
      RECT 5.7600 0.5250 6.5900 0.5950 ;
      RECT 5.3800 0.3850 5.4500 1.0850 ;
      RECT 4.0500 0.2450 5.0700 0.3150 ;
  END
END DFFRS_X1

MACRO DFFE_X1
  CLASS CORE ;
  ORIGIN 0 0 ;
  FOREIGN DFFE_X1 0 0 ;
  SIZE 5.70 BY 1.40 ;
  SYMMETRY X Y ;
  SITE core ;
  PIN D
    DIRECTION INPUT ;
    USE SIGNAL ;
    PORT
      LAYER metal1 ;
        RECT 0.6300 0.5250 0.7000 0.7350 ;
        RECT 0.6300 0.5950 0.8900 0.6650 ;
        RECT 1.5800 0.5950 1.8400 0.6650 ;
      LAYER via1 ;
        RECT 0.8225 0.5975 0.8875 0.6625 ;
        RECT 1.5825 0.5975 1.6475 0.6625 ;
      LAYER metal2 ;
        RECT 0.8200 0.5950 1.7450 0.6650 ;
    END
  END D
  PIN E
    DIRECTION INPUT ;
    USE SIGNAL ;
    PORT
      LAYER metal1 ;
        RECT 0.2500 0.5250 0.3200 0.7350 ;
    END
  END E
  PIN CK
    DIRECTION INPUT ;
    USE CLOCK ;
    PORT
      LAYER metal1 ;
        RECT 5.5700 0.5250 5.6400 0.7350 ;
    END
  END CK
  PIN Q
    DIRECTION OUTPUT ;
    USE SIGNAL ;
    PORT
      LAYER metal1 ;
        RECT 3.1000 0.3150 3.1700 1.0850 ;
        RECT 3.2900 0.1750 3.3600 0.3850 ;
        RECT 3.1000 0.3150 3.3600 0.3850 ;
        RECT 3.1000 1.0150 3.3600 1.0850 ;
    END
  END Q
  PIN QN
    DIRECTION OUTPUT ;
    USE SIGNAL ;
    PORT
      LAYER metal1 ;
        RECT 2.1500 0.5950 2.2200 1.0850 ;
        RECT 2.3400 0.1750 2.4100 0.3850 ;
        RECT 2.1500 0.3150 2.4100 0.3850 ;
      LAYER via1 ;
        RECT 2.1525 0.3175 2.2175 0.3825 ;
        RECT 2.1525 0.5975 2.2175 0.6625 ;
      LAYER metal2 ;
        RECT 2.1500 0.3150 2.2200 0.6650 ;
    END
  END QN
  PIN VDD
    DIRECTION INOUT ;
    USE POWER ;
    SHAPE ABUTMENT ;
    PORT
      LAYER metal1 ;
        RECT 0.0000 1.3150 5.7000 1.4850 ;
        RECT 0.2500 1.1550 0.3200 1.3650 ;
        RECT 0.6300 1.1550 0.7000 1.3650 ;
        RECT 1.7700 1.1550 1.8400 1.3650 ;
        RECT 2.3400 1.1550 2.4100 1.3650 ;
        RECT 3.1000 1.1550 3.1700 1.3650 ;
        RECT 4.2400 1.1550 4.3100 1.3650 ;
        RECT 5.3800 1.1550 5.4500 1.3650 ;
    END
  END VDD
  PIN VSS
    DIRECTION INOUT ;
    USE GROUND ;
    SHAPE ABUTMENT ;
    PORT
      LAYER metal1 ;
        RECT 0.0000 -0.0850 5.7000 0.0850 ;
        RECT 0.2500 0.0350 0.3200 0.2450 ;
        RECT 1.2950 0.0350 1.3650 0.3850 ;
        RECT 1.7700 0.0350 1.8400 0.2450 ;
        RECT 1.8650 0.0350 1.9350 0.1750 ;
        RECT 2.5300 0.0350 2.6000 0.2450 ;
        RECT 3.1000 0.0350 3.1700 0.2450 ;
        RECT 4.2400 0.0350 4.3100 0.2450 ;
        RECT 5.3800 0.0350 5.4500 0.2450 ;
        RECT 5.4750 0.0350 5.5450 0.1750 ;
        RECT 1.7700 0.0350 1.9350 0.1050 ;
        RECT 5.3800 0.0350 5.5450 0.1050 ;
        RECT 1.7700 0.1050 1.9350 0.1750 ;
        RECT 5.3800 0.1050 5.5450 0.1750 ;
        RECT 0.2500 0.1750 0.5100 0.2450 ;
        RECT 1.2950 0.3150 1.4600 0.3850 ;
    END
  END VSS
  OBS
    LAYER metal1 ;
      RECT 1.1050 0.5250 1.1750 0.6650 ;
      RECT 1.2000 0.4550 1.2700 0.5950 ;
      RECT 1.5800 0.3850 1.6500 0.5250 ;
      RECT 2.5300 0.3850 2.6000 0.5250 ;
      RECT 2.7200 0.2450 2.7900 1.0850 ;
      RECT 2.7200 0.2450 2.9800 0.3150 ;
      RECT 2.5300 0.3850 2.7900 0.4550 ;
      RECT 1.2000 0.4550 2.6000 0.5250 ;
      RECT 1.1050 0.5250 1.2700 0.5950 ;
      RECT 2.7200 1.0150 2.9800 1.0850 ;
      RECT 4.7150 0.3150 4.7850 0.4550 ;
      RECT 4.8100 0.2450 4.8800 0.3850 ;
      RECT 4.8100 0.9450 4.8800 1.0850 ;
      RECT 4.7150 0.3150 4.8800 0.3850 ;
      RECT 4.5250 0.3850 4.7850 0.4550 ;
      RECT 3.8600 0.6650 4.1200 0.7350 ;
      RECT 4.8100 1.0150 4.9750 1.0850 ;
      RECT 3.4800 0.8750 3.5500 1.0850 ;
      RECT 4.0500 0.1750 4.1200 0.4550 ;
      RECT 4.0500 0.8750 4.1200 1.0850 ;
      RECT 4.3350 0.3850 4.4050 0.9450 ;
      RECT 3.8600 0.1750 4.1200 0.2450 ;
      RECT 4.0500 0.3850 4.4050 0.4550 ;
      RECT 3.4800 0.8750 4.4050 0.9450 ;
      RECT 3.2900 0.4550 3.3600 0.9450 ;
      RECT 3.6700 0.2450 3.7400 0.5250 ;
      RECT 3.2900 0.4550 3.7400 0.5250 ;
      RECT 3.6700 1.0150 3.9300 1.0850 ;
      RECT 4.4300 0.1750 4.6900 0.2450 ;
      RECT 4.4300 1.1550 5.0700 1.2250 ;
      RECT 1.5800 0.1750 1.6500 0.3150 ;
      RECT 3.4800 0.1750 3.5500 0.3850 ;
      RECT 1.4850 0.1750 1.6500 0.2450 ;
      RECT 2.5300 1.1550 2.7900 1.2250 ;
      RECT 3.7650 1.1550 4.0250 1.2250 ;
      RECT 0.0600 0.2450 0.1300 1.0850 ;
      RECT 0.8200 0.8050 0.8900 0.9450 ;
      RECT 0.8200 0.8050 1.3650 0.8750 ;
      RECT 0.0600 0.8750 0.8900 0.9450 ;
      RECT 1.9600 0.2450 2.0300 0.3850 ;
      RECT 4.5250 0.8050 4.5950 0.9450 ;
      RECT 4.6200 0.8750 4.6900 1.0850 ;
      RECT 5.0000 0.1750 5.0700 0.3850 ;
      RECT 1.8650 0.3150 2.0300 0.3850 ;
      RECT 4.5250 0.8750 4.6900 0.9450 ;
      RECT 1.7700 1.0150 2.0300 1.0850 ;
      RECT 0.4400 0.3850 0.5100 0.8050 ;
      RECT 1.0100 0.9450 1.0800 1.0850 ;
      RECT 1.3900 0.9450 1.4600 1.0850 ;
      RECT 1.4850 0.8750 1.5550 1.0150 ;
      RECT 1.8650 0.8050 1.9350 0.9450 ;
      RECT 0.4400 0.3850 1.0800 0.4550 ;
      RECT 1.4850 0.8750 1.9350 0.9450 ;
      RECT 1.0100 0.9450 1.5550 1.0150 ;
      RECT 0.8200 1.0150 0.8900 1.2250 ;
      RECT 0.4400 1.0150 0.8900 1.0850 ;
      RECT 0.8200 1.1550 1.6500 1.2250 ;
      RECT 2.5300 0.5950 2.6000 0.9450 ;
      RECT 5.0950 0.5250 5.1650 0.7350 ;
      RECT 5.2850 0.6650 5.3550 0.9450 ;
      RECT 5.3800 0.3850 5.4500 0.5950 ;
      RECT 5.5700 0.2450 5.6400 0.4550 ;
      RECT 5.5700 0.8750 5.6400 1.0850 ;
      RECT 5.3800 0.3850 5.6400 0.4550 ;
      RECT 5.0950 0.5250 5.4500 0.5950 ;
      RECT 3.4800 0.5950 3.7400 0.6650 ;
      RECT 5.0000 0.6650 5.3550 0.7350 ;
      RECT 5.2850 0.8750 5.6400 0.9450 ;
      RECT 4.7150 0.5250 4.7850 0.8050 ;
      RECT 4.8100 0.7350 4.8800 0.8750 ;
      RECT 5.0950 0.8050 5.1650 1.0850 ;
      RECT 5.1900 0.1750 5.2600 0.3850 ;
      RECT 3.8600 0.5250 4.1200 0.5950 ;
      RECT 4.5250 0.5250 4.9750 0.5950 ;
      RECT 4.7150 0.7350 4.8800 0.8050 ;
      RECT 4.8100 0.8050 5.1650 0.8750 ;
      RECT 5.0950 1.0150 5.2600 1.0850 ;
    LAYER via1 ;
      RECT 3.8625 0.6675 3.9275 0.7325 ;
      RECT 4.5275 0.3875 4.5925 0.4525 ;
      RECT 4.8125 0.9475 4.8775 1.0125 ;
      RECT 3.2925 0.8775 3.3575 0.9425 ;
      RECT 3.6725 1.0175 3.7375 1.0825 ;
      RECT 1.5825 0.1775 1.6475 0.2425 ;
      RECT 3.4825 0.1775 3.5475 0.2425 ;
      RECT 2.7225 1.1575 2.7875 1.2225 ;
      RECT 3.7675 1.1575 3.8325 1.2225 ;
      RECT 1.9625 0.2475 2.0275 0.3125 ;
      RECT 1.9625 1.0175 2.0275 1.0825 ;
      RECT 4.5275 0.8075 4.5925 0.8725 ;
      RECT 5.0025 0.2475 5.0675 0.3125 ;
      RECT 0.4425 0.7375 0.5075 0.8025 ;
      RECT 1.0125 0.9475 1.0775 1.0125 ;
      RECT 2.5325 0.5975 2.5975 0.6625 ;
      RECT 2.5325 0.8775 2.5975 0.9425 ;
      RECT 3.4825 0.5975 3.5475 0.6625 ;
      RECT 5.2875 0.8775 5.3525 0.9425 ;
      RECT 3.9575 0.5275 4.0225 0.5925 ;
      RECT 4.5275 0.5275 4.5925 0.5925 ;
      RECT 4.9075 0.5275 4.9725 0.5925 ;
      RECT 5.1925 0.2475 5.2575 0.3125 ;
    LAYER metal2 ;
      RECT 3.7650 0.3850 3.8350 0.7350 ;
      RECT 4.5250 0.1050 4.5950 0.4550 ;
      RECT 4.8100 0.8050 4.8800 1.0850 ;
      RECT 4.9050 0.6650 4.9750 0.8750 ;
      RECT 5.0950 0.5950 5.1650 0.7350 ;
      RECT 5.3800 0.1050 5.4500 0.6650 ;
      RECT 4.5250 0.1050 5.4500 0.1750 ;
      RECT 3.7650 0.3850 4.5950 0.4550 ;
      RECT 5.0950 0.5950 5.4500 0.6650 ;
      RECT 3.7650 0.6650 4.0250 0.7350 ;
      RECT 4.9050 0.6650 5.1650 0.7350 ;
      RECT 4.8100 0.8050 4.9750 0.8750 ;
      RECT 3.2900 0.8750 3.3600 1.0850 ;
      RECT 3.2900 1.0150 3.7400 1.0850 ;
      RECT 1.5800 -0.0350 1.6500 0.2450 ;
      RECT 3.4800 -0.0350 3.5500 0.3150 ;
      RECT 1.5800 -0.0350 3.5500 0.0350 ;
      RECT 2.7200 1.1550 3.9300 1.2250 ;
      RECT 1.9600 0.2450 2.0300 1.0850 ;
      RECT 3.4800 0.7350 3.5500 0.8750 ;
      RECT 4.5250 0.6650 4.5950 0.8750 ;
      RECT 4.7150 0.3150 4.7850 0.7350 ;
      RECT 5.0000 0.2450 5.0700 0.3850 ;
      RECT 4.7150 0.3150 5.0700 0.3850 ;
      RECT 4.5250 0.6650 4.7850 0.7350 ;
      RECT 1.9600 0.7350 3.5500 0.8050 ;
      RECT 3.4800 0.8050 4.5950 0.8750 ;
      RECT 0.4400 0.7350 0.5100 1.0150 ;
      RECT 0.4400 0.9450 1.0800 1.0150 ;
      RECT 2.5300 0.8750 2.6000 1.3650 ;
      RECT 4.0500 1.1550 4.1200 1.3650 ;
      RECT 5.0000 0.9450 5.0700 1.2250 ;
      RECT 5.0950 0.8750 5.1650 1.0150 ;
      RECT 2.5300 0.5950 3.5500 0.6650 ;
      RECT 5.0950 0.8750 5.3550 0.9450 ;
      RECT 5.0000 0.9450 5.1650 1.0150 ;
      RECT 4.0500 1.1550 5.0700 1.2250 ;
      RECT 2.5300 1.2950 4.1200 1.3650 ;
      RECT 4.9050 0.4550 4.9750 0.5950 ;
      RECT 5.1900 0.2450 5.2600 0.5250 ;
      RECT 4.9050 0.4550 5.2600 0.5250 ;
      RECT 3.9550 0.5250 4.5950 0.5950 ;
  END
END DFFE_X1

MACRO SDFF_X1
  CLASS CORE ;
  ORIGIN 0 0 ;
  FOREIGN SDFF_X1 0 0 ;
  SIZE 6.08 BY 1.40 ;
  SYMMETRY X Y ;
  SITE core ;
  PIN D
    DIRECTION INPUT ;
    USE SIGNAL ;
    PORT
      LAYER metal1 ;
        RECT 0.0600 0.1750 0.1300 0.3850 ;
    END
  END D
  PIN SI
    DIRECTION INPUT ;
    USE SIGNAL ;
    PORT
      LAYER metal1 ;
        RECT 1.9600 0.5950 2.0300 0.8050 ;
        RECT 1.8650 0.6650 2.0300 0.7350 ;
    END
  END SI
  PIN SE
    DIRECTION INPUT ;
    USE SIGNAL ;
    PORT
      LAYER metal1 ;
        RECT 1.2000 0.5250 1.2700 0.7350 ;
    END
  END SE
  PIN CK
    DIRECTION INPUT ;
    USE CLOCK ;
    PORT
      LAYER metal1 ;
        RECT 3.8600 0.4550 3.9300 0.6650 ;
    END
  END CK
  PIN Q
    DIRECTION OUTPUT ;
    USE SIGNAL ;
    PORT
      LAYER metal1 ;
        RECT 5.9500 0.1750 6.0200 1.0850 ;
    END
  END Q
  PIN QN
    DIRECTION OUTPUT ;
    USE SIGNAL ;
    PORT
      LAYER metal1 ;
        RECT 5.1900 0.3150 5.2600 1.0850 ;
        RECT 5.3800 0.1750 5.4500 0.3850 ;
        RECT 5.1900 0.3150 5.4500 0.3850 ;
        RECT 5.1900 1.0150 5.4500 1.0850 ;
    END
  END QN
  PIN VDD
    DIRECTION INOUT ;
    USE POWER ;
    SHAPE ABUTMENT ;
    PORT
      LAYER metal1 ;
        RECT 0.0000 1.3150 6.0800 1.4850 ;
        RECT 1.3900 1.1550 1.4600 1.3650 ;
        RECT 1.7700 1.1550 1.8400 1.3650 ;
        RECT 2.1500 1.1550 2.2200 1.3650 ;
        RECT 3.4800 1.1550 3.5500 1.3650 ;
        RECT 4.0500 1.1550 4.1200 1.3650 ;
        RECT 5.1900 1.1550 5.2600 1.3650 ;
        RECT 5.7600 1.1550 5.8300 1.3650 ;
    END
  END VDD
  PIN VSS
    DIRECTION INOUT ;
    USE GROUND ;
    SHAPE ABUTMENT ;
    PORT
      LAYER metal1 ;
        RECT 0.0000 -0.0850 6.0800 0.0850 ;
        RECT 0.6300 0.0350 0.7000 0.2450 ;
        RECT 1.3900 0.0350 1.4600 0.2450 ;
        RECT 2.1500 0.0350 2.2200 0.2450 ;
        RECT 3.4800 0.0350 3.5500 0.2450 ;
        RECT 3.5750 0.0350 3.6450 0.1750 ;
        RECT 4.0500 0.0350 4.1200 0.2450 ;
        RECT 5.1900 0.0350 5.2600 0.2450 ;
        RECT 5.7600 0.0350 5.8300 0.2450 ;
        RECT 3.4800 0.0350 3.6450 0.1050 ;
        RECT 3.4800 0.1050 3.6450 0.1750 ;
        RECT 1.3900 0.1750 1.6500 0.2450 ;
    END
  END VSS
  OBS
    LAYER metal1 ;
      RECT 1.0100 0.1750 1.0800 0.8050 ;
      RECT 0.8200 0.1750 1.2700 0.2450 ;
      RECT 1.0100 1.1550 1.2700 1.2250 ;
      RECT 2.9100 0.1750 2.9800 0.3850 ;
      RECT 2.9100 1.0150 2.9800 1.2250 ;
      RECT 3.3850 0.4550 3.6450 0.5250 ;
      RECT 3.3850 0.5950 3.4550 0.9450 ;
      RECT 3.6700 0.2450 3.7400 0.3850 ;
      RECT 3.6700 0.8750 3.7400 1.0850 ;
      RECT 4.4300 0.1750 4.5000 0.3850 ;
      RECT 4.8100 0.8750 4.8800 1.0850 ;
      RECT 3.5750 0.3150 3.7400 0.3850 ;
      RECT 3.3850 0.5950 3.5500 0.6650 ;
      RECT 3.3850 0.8750 4.8800 0.9450 ;
      RECT 4.6200 0.2450 4.6900 0.3850 ;
      RECT 4.6200 1.0150 4.6900 1.2250 ;
      RECT 4.6200 0.3150 4.7850 0.3850 ;
      RECT 5.5700 0.5950 5.8300 0.6650 ;
      RECT 2.6250 0.2450 2.6950 0.3850 ;
      RECT 3.2900 0.1750 3.3600 0.3850 ;
      RECT 2.6250 0.2450 2.7900 0.3150 ;
      RECT 3.1000 1.0150 3.3600 1.0850 ;
      RECT 4.8100 0.1750 5.0700 0.2450 ;
      RECT 4.2400 1.1550 4.5000 1.2250 ;
      RECT 4.8100 1.1550 5.0700 1.2250 ;
      RECT 2.4350 0.2450 2.5050 1.0850 ;
      RECT 3.1000 0.2450 3.1700 0.5950 ;
      RECT 2.3400 0.2450 2.5050 0.3150 ;
      RECT 2.4350 0.5250 3.1700 0.5950 ;
      RECT 2.3400 1.0150 2.7900 1.0850 ;
      RECT 0.2500 0.8750 0.3200 1.0850 ;
      RECT 0.3450 0.4550 0.4150 0.9450 ;
      RECT 0.6300 0.8750 0.7000 1.0850 ;
      RECT 2.2450 0.4550 2.3150 0.9450 ;
      RECT 0.2500 0.4550 0.4150 0.5250 ;
      RECT 1.9600 0.4550 2.3150 0.5250 ;
      RECT 0.2500 0.8750 2.3150 0.9450 ;
      RECT 0.8200 1.0150 0.8900 1.2250 ;
      RECT 0.8200 1.0150 2.0300 1.0850 ;
      RECT 0.0600 1.1550 0.8900 1.2250 ;
      RECT 5.3800 0.4550 5.4500 0.9450 ;
      RECT 5.5700 0.2450 5.6400 0.5250 ;
      RECT 5.5700 0.8750 5.6400 1.0850 ;
      RECT 5.3800 0.4550 5.6400 0.5250 ;
      RECT 5.3800 0.8750 5.6400 0.9450 ;
      RECT 3.8600 0.2450 3.9300 0.3850 ;
      RECT 4.0500 0.3150 4.1200 0.5250 ;
      RECT 4.1450 0.4550 4.2150 0.8050 ;
      RECT 3.8600 0.3150 4.1200 0.3850 ;
      RECT 4.0500 0.4550 4.7850 0.5250 ;
      RECT 3.0050 0.7350 3.2650 0.8050 ;
      RECT 4.0500 0.7350 4.2150 0.8050 ;
      RECT 3.8600 1.0150 4.1200 1.0850 ;
      RECT 2.8150 0.8050 2.8850 0.9450 ;
      RECT 4.2400 0.1750 4.3100 0.3850 ;
      RECT 4.3350 0.5950 4.5950 0.6650 ;
      RECT 2.8150 0.8750 3.2650 0.9450 ;
      RECT 4.2400 1.0150 4.5000 1.0850 ;
    LAYER via1 ;
      RECT 1.0125 0.7375 1.0775 0.8025 ;
      RECT 1.0125 1.1575 1.0775 1.2225 ;
      RECT 2.9125 0.2475 2.9775 0.3125 ;
      RECT 2.9125 1.0175 2.9775 1.0825 ;
      RECT 3.3875 0.4575 3.4525 0.5225 ;
      RECT 3.4825 0.5975 3.5475 0.6625 ;
      RECT 3.6725 0.2475 3.7375 0.3125 ;
      RECT 4.4325 0.1775 4.4975 0.2425 ;
      RECT 4.6225 0.2475 4.6875 0.3125 ;
      RECT 4.6225 1.0175 4.6875 1.0825 ;
      RECT 5.5725 0.5975 5.6375 0.6625 ;
      RECT 2.7225 0.2475 2.7875 0.3125 ;
      RECT 3.2925 0.1775 3.3575 0.2425 ;
      RECT 4.4325 1.1575 4.4975 1.2225 ;
      RECT 4.8125 1.1575 4.8775 1.2225 ;
      RECT 3.1975 0.7375 3.2625 0.8025 ;
      RECT 3.8625 1.0175 3.9275 1.0825 ;
      RECT 4.0525 0.7375 4.1175 0.8025 ;
      RECT 3.1975 0.8775 3.2625 0.9425 ;
      RECT 4.2425 0.2475 4.3075 0.3125 ;
      RECT 4.2425 1.0175 4.3075 1.0825 ;
      RECT 4.3375 0.5975 4.4025 0.6625 ;
    LAYER metal2 ;
      RECT 1.0100 0.7350 1.0800 1.2250 ;
      RECT 2.9100 0.2450 2.9800 1.0850 ;
      RECT 2.9100 0.4550 3.5500 0.5250 ;
      RECT 3.6700 0.1050 3.7400 0.6650 ;
      RECT 4.4300 0.1050 4.5000 0.2450 ;
      RECT 3.6700 0.1050 4.5000 0.1750 ;
      RECT 3.4800 0.5950 3.7400 0.6650 ;
      RECT 4.6200 0.2450 4.6900 1.0850 ;
      RECT 4.6200 0.5950 5.6400 0.6650 ;
      RECT 2.7200 0.1050 2.7900 0.3150 ;
      RECT 3.1000 0.1050 3.1700 0.2450 ;
      RECT 2.7200 0.1050 3.1700 0.1750 ;
      RECT 3.1000 0.1750 3.3600 0.2450 ;
      RECT 4.4300 1.1550 5.0700 1.2250 ;
      RECT 3.3850 0.7350 3.4550 0.9450 ;
      RECT 3.8600 0.8750 3.9300 1.0850 ;
      RECT 4.0500 0.7350 4.1200 0.9450 ;
      RECT 3.1950 0.7350 3.4550 0.8050 ;
      RECT 3.3850 0.8750 4.1200 0.9450 ;
      RECT 3.1950 0.8750 3.2650 1.2250 ;
      RECT 4.0500 1.0150 4.1200 1.2250 ;
      RECT 4.2400 0.2450 4.3100 1.0850 ;
      RECT 4.2400 0.5950 4.4050 0.6650 ;
      RECT 4.0500 1.0150 4.3100 1.0850 ;
      RECT 3.1950 1.1550 4.1200 1.2250 ;
  END
END SDFF_X1

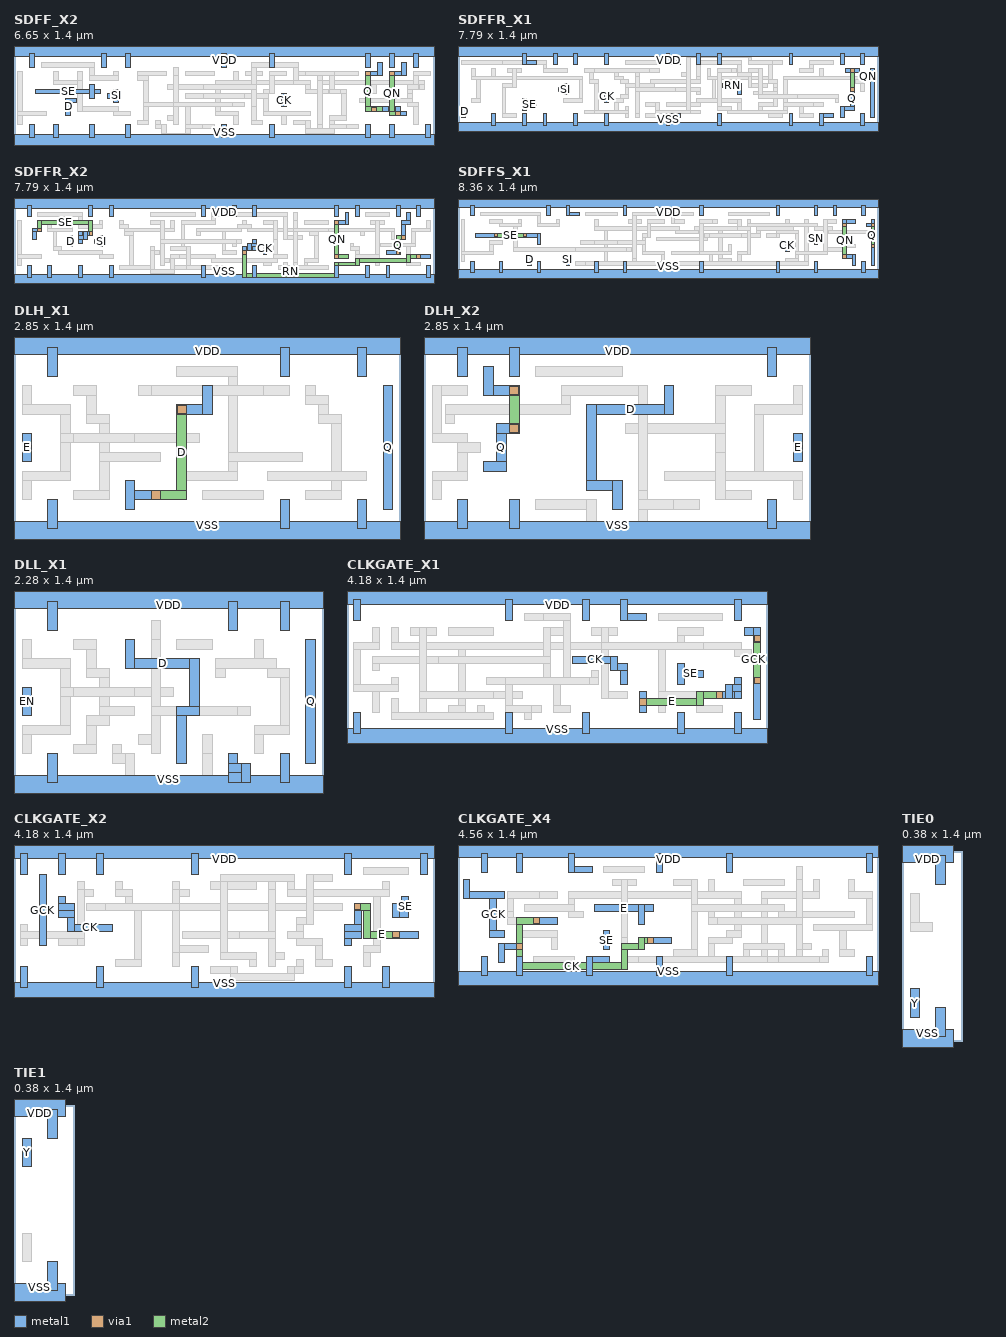
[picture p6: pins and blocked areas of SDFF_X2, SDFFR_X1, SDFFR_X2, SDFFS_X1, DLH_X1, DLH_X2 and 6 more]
MACRO SDFF_X2
  CLASS CORE ;
  ORIGIN 0 0 ;
  FOREIGN SDFF_X2 0 0 ;
  SIZE 6.65 BY 1.40 ;
  SYMMETRY X Y ;
  SITE core ;
  PIN D
    DIRECTION INPUT ;
    USE SIGNAL ;
    PORT
      LAYER metal1 ;
        RECT 0.8200 0.3850 0.8900 0.6650 ;
        RECT 0.8200 0.5950 0.9850 0.6650 ;
    END
  END D
  PIN SI
    DIRECTION INPUT ;
    USE SIGNAL ;
    PORT
      LAYER metal1 ;
        RECT 1.5800 0.5950 1.6500 0.8050 ;
        RECT 1.4850 0.6650 1.6500 0.7350 ;
    END
  END SI
  PIN SE
    DIRECTION INPUT ;
    USE SIGNAL ;
    PORT
      LAYER metal1 ;
        RECT 1.2000 0.6650 1.2700 0.8750 ;
        RECT 0.3450 0.7350 1.3650 0.8050 ;
    END
  END SE
  PIN CK
    DIRECTION INPUT ;
    USE CLOCK ;
    PORT
      LAYER metal1 ;
        RECT 4.2400 0.5250 4.3100 0.7350 ;
    END
  END CK
  PIN Q
    DIRECTION OUTPUT ;
    USE SIGNAL ;
    PORT
      LAYER metal1 ;
        RECT 5.7600 1.0150 5.8300 1.2250 ;
        RECT 5.6650 0.4550 5.9250 0.5250 ;
        RECT 5.5700 1.0150 5.8300 1.0850 ;
      LAYER via1 ;
        RECT 5.5725 1.0175 5.6375 1.0825 ;
        RECT 5.6675 0.4575 5.7325 0.5225 ;
      LAYER metal2 ;
        RECT 5.5700 0.4550 5.6400 1.0850 ;
        RECT 5.5700 0.4550 5.8300 0.5250 ;
    END
  END Q
  PIN QN
    DIRECTION OUTPUT ;
    USE SIGNAL ;
    PORT
      LAYER metal1 ;
        RECT 6.0450 0.3850 6.1150 0.5250 ;
        RECT 6.1400 1.0150 6.2100 1.2250 ;
        RECT 6.0450 0.3850 6.2100 0.4550 ;
        RECT 5.9500 1.0150 6.2100 1.0850 ;
      LAYER via1 ;
        RECT 5.9525 1.0175 6.0175 1.0825 ;
        RECT 6.0475 0.3875 6.1125 0.4525 ;
      LAYER metal2 ;
        RECT 5.9500 0.3850 6.0200 1.0850 ;
        RECT 5.9500 0.3850 6.2100 0.4550 ;
    END
  END QN
  PIN VDD
    DIRECTION INOUT ;
    USE POWER ;
    SHAPE ABUTMENT ;
    PORT
      LAYER metal1 ;
        RECT 0.0000 1.3150 6.6500 1.4850 ;
        RECT 0.2500 1.1550 0.3200 1.3650 ;
        RECT 1.3900 1.1550 1.4600 1.3650 ;
        RECT 1.7700 1.1550 1.8400 1.3650 ;
        RECT 3.2900 1.1550 3.3600 1.3650 ;
        RECT 4.0500 1.1550 4.1200 1.3650 ;
        RECT 5.5700 1.1550 5.6400 1.3650 ;
        RECT 5.9500 1.1550 6.0200 1.3650 ;
        RECT 6.3300 1.1550 6.4000 1.3650 ;
    END
  END VDD
  PIN VSS
    DIRECTION INOUT ;
    USE GROUND ;
    SHAPE ABUTMENT ;
    PORT
      LAYER metal1 ;
        RECT 0.0000 -0.0850 6.6500 0.0850 ;
        RECT 0.2500 0.0350 0.3200 0.2450 ;
        RECT 0.6300 0.0350 0.7000 0.2450 ;
        RECT 1.2000 0.0350 1.2700 0.2450 ;
        RECT 1.7700 0.0350 1.8400 0.2450 ;
        RECT 3.2900 0.0350 3.3600 0.2450 ;
        RECT 4.0500 0.0350 4.1200 0.2450 ;
        RECT 5.5700 0.0350 5.6400 0.2450 ;
        RECT 5.9500 0.0350 6.0200 0.2450 ;
        RECT 6.5200 0.0350 6.5900 0.2450 ;
    END
  END VSS
  OBS
    LAYER metal1 ;
      RECT 0.0600 0.2450 0.1300 1.0850 ;
      RECT 0.0600 0.3850 0.5100 0.4550 ;
      RECT 2.5300 0.2450 2.6000 0.3850 ;
      RECT 2.5300 0.9450 2.6000 1.1550 ;
      RECT 2.4350 0.3150 2.6000 0.3850 ;
      RECT 3.3850 0.5250 3.6450 0.5950 ;
      RECT 3.1950 0.3850 3.2650 0.9450 ;
      RECT 3.4800 0.2450 3.5500 0.4550 ;
      RECT 3.4800 0.8750 3.5500 1.0850 ;
      RECT 4.4300 0.8750 4.5000 1.0850 ;
      RECT 5.0000 0.2450 5.0700 0.3850 ;
      RECT 5.1900 0.3150 5.2600 0.8050 ;
      RECT 5.0000 0.3150 5.2600 0.3850 ;
      RECT 3.1950 0.3850 3.5500 0.4550 ;
      RECT 5.0950 0.7350 5.2600 0.8050 ;
      RECT 3.1950 0.8750 4.5000 0.9450 ;
      RECT 4.4300 1.0150 4.6900 1.0850 ;
      RECT 4.8100 0.1750 4.8800 0.3850 ;
      RECT 4.8100 0.8750 4.8800 1.0850 ;
      RECT 5.6650 0.7350 5.7350 0.9450 ;
      RECT 6.4250 0.8050 6.4950 0.9450 ;
      RECT 4.8100 0.8750 6.4950 0.9450 ;
      RECT 2.2450 0.1750 2.3150 0.3150 ;
      RECT 2.2450 0.1750 2.4100 0.2450 ;
      RECT 2.9100 0.1750 3.1700 0.2450 ;
      RECT 2.7200 1.0150 3.1700 1.0850 ;
      RECT 5.1900 0.1750 5.4500 0.2450 ;
      RECT 4.4300 0.2450 4.6900 0.3150 ;
      RECT 5.0000 1.0150 5.4500 1.0850 ;
      RECT 1.9600 0.9450 2.0300 1.0850 ;
      RECT 2.0550 0.2450 2.1250 1.0850 ;
      RECT 2.7200 0.2450 2.7900 0.5950 ;
      RECT 1.9600 0.2450 2.1250 0.3150 ;
      RECT 2.0550 0.5250 2.7900 0.5950 ;
      RECT 1.9600 0.9450 2.1250 1.0150 ;
      RECT 1.9600 1.0150 2.4100 1.0850 ;
      RECT 0.6300 0.8750 0.7000 1.0850 ;
      RECT 1.0100 0.8750 1.0800 1.0850 ;
      RECT 1.5800 0.3850 1.6500 0.5250 ;
      RECT 1.5800 0.3850 1.8400 0.4550 ;
      RECT 1.0100 0.4550 1.6500 0.5250 ;
      RECT 0.6300 0.8750 1.0800 0.9450 ;
      RECT 1.2000 0.9450 1.2700 1.2250 ;
      RECT 1.5800 0.9450 1.6500 1.0850 ;
      RECT 1.2000 0.9450 1.6500 1.0150 ;
      RECT 0.4400 1.1550 1.2700 1.2250 ;
      RECT 6.2350 0.5250 6.3050 0.8050 ;
      RECT 6.3300 0.2450 6.4000 0.5950 ;
      RECT 6.2350 0.5250 6.4000 0.5950 ;
      RECT 5.4750 0.5950 6.3050 0.6650 ;
      RECT 6.3300 1.0150 6.5900 1.0850 ;
      RECT 3.9550 0.3850 4.0250 0.8050 ;
      RECT 4.2400 0.2450 4.3100 0.4550 ;
      RECT 3.9550 0.3850 4.6900 0.4550 ;
      RECT 2.7200 0.6650 3.0750 0.7350 ;
      RECT 3.5750 0.6650 4.0250 0.7350 ;
      RECT 3.9550 0.7350 4.1200 0.8050 ;
      RECT 4.0500 1.0150 4.3100 1.0850 ;
      RECT 3.7650 0.2450 3.8350 0.5950 ;
      RECT 4.6200 0.7350 4.6900 0.9450 ;
      RECT 3.7650 0.2450 3.9300 0.3150 ;
      RECT 4.6200 0.7350 4.9750 0.8050 ;
      RECT 2.4350 0.8050 3.0750 0.8750 ;
      RECT 3.6700 1.0150 3.9300 1.0850 ;
    LAYER via1 ;
      RECT 2.5325 0.2475 2.5975 0.3125 ;
      RECT 2.5325 0.9475 2.5975 1.0125 ;
      RECT 3.3875 0.5275 3.4525 0.5925 ;
      RECT 4.6225 1.0175 4.6875 1.0825 ;
      RECT 5.0975 0.7375 5.1625 0.8025 ;
      RECT 4.8125 0.2475 4.8775 0.3125 ;
      RECT 4.8125 0.8775 4.8775 0.9425 ;
      RECT 2.3425 0.1775 2.4075 0.2425 ;
      RECT 2.9125 0.1775 2.9775 0.2425 ;
      RECT 4.6225 0.2475 4.6875 0.3125 ;
      RECT 5.1925 0.1775 5.2575 0.2425 ;
      RECT 1.0125 0.4575 1.0775 0.5225 ;
      RECT 1.0125 0.8775 1.0775 0.9425 ;
      RECT 6.2375 0.7375 6.3025 0.8025 ;
      RECT 6.3325 1.0175 6.3975 1.0825 ;
      RECT 3.0075 0.6675 3.0725 0.7325 ;
      RECT 3.5775 0.6675 3.6425 0.7325 ;
      RECT 4.0525 0.7375 4.1175 0.8025 ;
      RECT 4.0525 1.0175 4.1175 1.0825 ;
      RECT 3.0075 0.8075 3.0725 0.8725 ;
      RECT 3.7675 0.5275 3.8325 0.5925 ;
      RECT 3.7675 1.0175 3.8325 1.0825 ;
      RECT 4.6225 0.8775 4.6875 0.9425 ;
    LAYER metal2 ;
      RECT 2.5300 0.2450 2.6000 1.0150 ;
      RECT 2.5300 0.5250 3.4550 0.5950 ;
      RECT 5.0000 0.7350 5.0700 1.0850 ;
      RECT 5.0000 0.7350 5.1650 0.8050 ;
      RECT 4.6200 1.0150 5.0700 1.0850 ;
      RECT 4.8100 0.2450 4.8800 0.9450 ;
      RECT 2.3400 0.0350 2.4100 0.2450 ;
      RECT 2.7200 0.0350 2.7900 0.2450 ;
      RECT 2.3400 0.0350 2.7900 0.1050 ;
      RECT 2.7200 0.1750 2.9800 0.2450 ;
      RECT 4.6200 0.1050 4.6900 0.3150 ;
      RECT 5.0000 0.1050 5.0700 0.2450 ;
      RECT 4.6200 0.1050 5.0700 0.1750 ;
      RECT 5.0000 0.1750 5.2600 0.2450 ;
      RECT 1.0100 0.4550 1.0800 0.9450 ;
      RECT 6.2350 0.7350 6.3050 0.8750 ;
      RECT 6.3300 0.8050 6.4000 1.0850 ;
      RECT 6.2350 0.8050 6.4000 0.8750 ;
      RECT 6.3300 1.0150 6.5900 1.0850 ;
      RECT 4.0500 0.7350 4.1200 1.0850 ;
      RECT 3.0050 0.6650 3.6450 0.7350 ;
      RECT 4.0500 1.0150 4.3100 1.0850 ;
      RECT 3.7650 0.5250 3.8350 1.2250 ;
      RECT 4.4300 0.8750 4.5000 1.2250 ;
      RECT 3.0050 0.8050 3.8350 0.8750 ;
      RECT 4.4300 0.8750 4.6900 0.9450 ;
      RECT 3.7650 1.1550 4.5000 1.2250 ;
  END
END SDFF_X2

MACRO SDFFR_X1
  CLASS CORE ;
  ORIGIN 0 0 ;
  FOREIGN SDFFR_X1 0 0 ;
  SIZE 7.79 BY 1.40 ;
  SYMMETRY X Y ;
  SITE core ;
  PIN D
    DIRECTION INPUT ;
    USE SIGNAL ;
    PORT
      LAYER metal1 ;
        RECT 0.0600 0.1750 0.1300 0.3850 ;
    END
  END D
  PIN SI
    DIRECTION INPUT ;
    USE SIGNAL ;
    PORT
      LAYER metal1 ;
        RECT 1.9600 0.5950 2.0300 0.8050 ;
        RECT 1.8650 0.6650 2.0300 0.7350 ;
    END
  END SI
  PIN SE
    DIRECTION INPUT ;
    USE SIGNAL ;
    PORT
      LAYER metal1 ;
        RECT 1.2000 0.3150 1.2700 0.5250 ;
        RECT 1.2000 0.3850 1.4600 0.4550 ;
    END
  END SE
  PIN CK
    DIRECTION INPUT ;
    USE CLOCK ;
    PORT
      LAYER metal1 ;
        RECT 2.7200 0.4550 2.7900 0.6650 ;
    END
  END CK
  PIN RN
    DIRECTION INPUT ;
    USE SIGNAL ;
    PORT
      LAYER metal1 ;
        RECT 5.1900 0.5950 5.2600 0.8050 ;
        RECT 4.9050 0.7350 5.2600 0.8050 ;
    END
  END RN
  PIN Q
    DIRECTION OUTPUT ;
    USE SIGNAL ;
    PORT
      LAYER metal1 ;
        RECT 7.0900 0.1750 7.1600 0.3850 ;
        RECT 7.2800 0.3150 7.3500 0.7350 ;
        RECT 7.0900 0.3150 7.3500 0.3850 ;
        RECT 7.1850 1.0150 7.4450 1.0850 ;
      LAYER via1 ;
        RECT 7.2825 0.6675 7.3475 0.7325 ;
        RECT 7.2825 1.0175 7.3475 1.0825 ;
      LAYER metal2 ;
        RECT 7.2800 0.6650 7.3500 1.0850 ;
    END
  END Q
  PIN QN
    DIRECTION OUTPUT ;
    USE SIGNAL ;
    PORT
      LAYER metal1 ;
        RECT 7.6600 0.1750 7.7300 1.0850 ;
    END
  END QN
  PIN VDD
    DIRECTION INOUT ;
    USE POWER ;
    SHAPE ABUTMENT ;
    PORT
      LAYER metal1 ;
        RECT 0.0000 1.3150 7.7900 1.4850 ;
        RECT 1.2000 1.1550 1.2700 1.3650 ;
        RECT 1.7700 1.1550 1.8400 1.3650 ;
        RECT 2.1500 1.1550 2.2200 1.3650 ;
        RECT 2.7200 1.1550 2.7900 1.3650 ;
        RECT 3.8600 1.1550 3.9300 1.3650 ;
        RECT 4.4300 1.1550 4.5000 1.3650 ;
        RECT 4.8100 1.1550 4.8800 1.3650 ;
        RECT 6.1400 1.1550 6.2100 1.3650 ;
        RECT 7.0900 1.1550 7.1600 1.3650 ;
        RECT 7.4700 1.1550 7.5400 1.3650 ;
        RECT 1.2000 1.1550 1.4600 1.2250 ;
        RECT 3.8600 1.1550 4.1200 1.2250 ;
    END
  END VDD
  PIN VSS
    DIRECTION INOUT ;
    USE GROUND ;
    SHAPE ABUTMENT ;
    PORT
      LAYER metal1 ;
        RECT 0.0000 -0.0850 7.7900 0.0850 ;
        RECT 0.6300 0.0350 0.7000 0.2450 ;
        RECT 1.2000 0.0350 1.2700 0.2450 ;
        RECT 1.5800 0.0350 1.6500 0.2450 ;
        RECT 2.1500 0.0350 2.2200 0.2450 ;
        RECT 2.7200 0.0350 2.7900 0.2450 ;
        RECT 3.8600 0.0350 3.9300 0.2450 ;
        RECT 4.8100 0.0350 4.8800 0.2450 ;
        RECT 6.1400 0.0350 6.2100 0.2450 ;
        RECT 6.7100 0.0350 6.7800 0.2450 ;
        RECT 7.4700 0.0350 7.5400 0.2450 ;
        RECT 3.8600 0.1750 4.1200 0.2450 ;
        RECT 6.7100 0.1750 6.9700 0.2450 ;
    END
  END VSS
  OBS
    LAYER metal1 ;
      RECT 0.8200 0.1750 0.8900 0.8050 ;
      RECT 0.8200 0.1750 1.0800 0.2450 ;
      RECT 0.8200 0.7350 1.0800 0.8050 ;
      RECT 0.9150 1.0150 1.1750 1.0850 ;
      RECT 3.2900 0.1750 3.3600 0.3850 ;
      RECT 3.2900 0.8750 3.3600 1.0850 ;
      RECT 4.4300 0.5950 4.5000 0.7350 ;
      RECT 3.9550 0.6650 4.5000 0.7350 ;
      RECT 4.4300 0.3850 4.5000 0.5250 ;
      RECT 4.6200 0.8750 4.6900 1.0850 ;
      RECT 4.7150 0.4550 4.7850 0.9450 ;
      RECT 5.1900 0.2450 5.2600 0.5250 ;
      RECT 5.7600 0.8750 5.8300 1.0850 ;
      RECT 5.1900 0.2450 5.4500 0.3150 ;
      RECT 3.8600 0.3850 4.5000 0.4550 ;
      RECT 4.4300 0.4550 5.2600 0.5250 ;
      RECT 4.6200 0.8750 5.8300 0.9450 ;
      RECT 5.5700 0.2450 5.6400 0.4550 ;
      RECT 6.9950 0.4550 7.0650 0.5950 ;
      RECT 5.5700 0.3850 5.9250 0.4550 ;
      RECT 6.2350 0.5250 7.0650 0.5950 ;
      RECT 5.3800 1.0150 5.6400 1.0850 ;
      RECT 5.0000 0.2450 5.0700 0.3850 ;
      RECT 4.9050 0.3150 5.0700 0.3850 ;
      RECT 6.5200 0.3850 6.7800 0.4550 ;
      RECT 4.9050 1.0150 5.1650 1.0850 ;
      RECT 3.4800 0.1750 3.7400 0.2450 ;
      RECT 3.1000 1.1550 3.7400 1.2250 ;
      RECT 6.5200 1.0150 6.5900 1.2250 ;
      RECT 6.3300 1.0150 6.5900 1.0850 ;
      RECT 6.5200 1.1550 6.9700 1.2250 ;
      RECT 5.7600 0.1750 6.0200 0.2450 ;
      RECT 5.3800 1.1550 6.0200 1.2250 ;
      RECT 2.4350 0.8050 2.5050 1.0850 ;
      RECT 2.5300 0.2450 2.6000 0.8750 ;
      RECT 3.1000 0.1750 3.1700 0.3850 ;
      RECT 2.3400 0.2450 2.6000 0.3150 ;
      RECT 2.4350 0.8050 2.6000 0.8750 ;
      RECT 2.3400 1.0150 2.6000 1.0850 ;
      RECT 3.4800 1.0150 3.7400 1.0850 ;
      RECT 0.2500 0.8750 0.3200 1.0850 ;
      RECT 0.3450 0.4550 0.4150 0.9450 ;
      RECT 0.6300 0.8750 0.7000 1.0850 ;
      RECT 2.2450 0.4550 2.3150 0.9450 ;
      RECT 0.2500 0.4550 0.4150 0.5250 ;
      RECT 1.9600 0.4550 2.3150 0.5250 ;
      RECT 0.2500 0.8750 2.3150 0.9450 ;
      RECT 1.5800 1.0150 1.6500 1.2250 ;
      RECT 1.5800 1.0150 2.0300 1.0850 ;
      RECT 0.0600 1.1550 0.8900 1.2250 ;
      RECT 6.0450 0.3850 6.1150 0.9450 ;
      RECT 6.3300 0.1750 6.4000 0.4550 ;
      RECT 6.7100 0.8750 6.7800 1.0850 ;
      RECT 7.3750 0.8050 7.4450 0.9450 ;
      RECT 7.4700 0.6650 7.5400 0.8750 ;
      RECT 6.3300 0.1750 6.5900 0.2450 ;
      RECT 6.0450 0.3850 6.4000 0.4550 ;
      RECT 7.3750 0.8050 7.5400 0.8750 ;
      RECT 6.0450 0.8750 7.4450 0.9450 ;
      RECT 2.9100 0.2450 2.9800 0.5250 ;
      RECT 2.9100 0.8750 2.9800 1.0850 ;
      RECT 3.0050 0.4550 3.0750 0.5950 ;
      RECT 3.0050 0.8050 3.0750 0.9450 ;
      RECT 3.1000 0.5250 3.1700 0.8750 ;
      RECT 3.5750 0.7350 3.6450 0.8750 ;
      RECT 4.4300 0.8050 4.5000 1.0150 ;
      RECT 2.9100 0.4550 3.0750 0.5250 ;
      RECT 3.0050 0.5250 3.1700 0.5950 ;
      RECT 3.1000 0.7350 3.6450 0.8050 ;
      RECT 5.3800 0.7350 5.7350 0.8050 ;
      RECT 3.0050 0.8050 3.1700 0.8750 ;
      RECT 3.5750 0.8050 4.5000 0.8750 ;
      RECT 2.9100 0.8750 3.0750 0.9450 ;
      RECT 4.2400 0.9450 4.3100 1.0850 ;
      RECT 5.8550 0.5950 5.9250 0.8050 ;
      RECT 4.2400 0.2450 4.5000 0.3150 ;
      RECT 3.4800 0.3850 3.7400 0.4550 ;
      RECT 5.4750 0.5950 5.9250 0.6650 ;
      RECT 4.1450 0.9450 4.3100 1.0150 ;
    LAYER via1 ;
      RECT 1.0125 0.7375 1.0775 0.8025 ;
      RECT 1.0125 1.0175 1.0775 1.0825 ;
      RECT 3.2925 0.2475 3.3575 0.3125 ;
      RECT 3.2925 0.8775 3.3575 0.9425 ;
      RECT 3.9575 0.6675 4.0225 0.7325 ;
      RECT 5.5725 1.0175 5.6375 1.0825 ;
      RECT 5.8575 0.3875 5.9225 0.4525 ;
      RECT 6.2375 0.5275 6.3025 0.5925 ;
      RECT 4.9075 0.3175 4.9725 0.3825 ;
      RECT 4.9075 1.0175 4.9725 1.0825 ;
      RECT 6.5225 0.3875 6.5875 0.4525 ;
      RECT 2.5325 0.2475 2.5975 0.3125 ;
      RECT 2.5325 1.0175 2.5975 1.0825 ;
      RECT 3.1025 0.2475 3.1675 0.3125 ;
      RECT 3.4825 1.0175 3.5475 1.0825 ;
      RECT 0.8225 1.1575 0.8875 1.2225 ;
      RECT 1.5825 1.1575 1.6475 1.2225 ;
      RECT 4.4325 0.9475 4.4975 1.0125 ;
      RECT 5.3825 0.7375 5.4475 0.8025 ;
      RECT 3.6725 0.3875 3.7375 0.4525 ;
      RECT 4.2425 0.2475 4.3075 0.3125 ;
      RECT 4.2425 0.9475 4.3075 1.0125 ;
      RECT 5.8575 0.7375 5.9225 0.8025 ;
    LAYER metal2 ;
      RECT 1.0100 0.7350 1.0800 1.0850 ;
      RECT 3.2900 0.2450 3.3600 0.9450 ;
      RECT 3.2900 0.6650 4.0250 0.7350 ;
      RECT 5.5700 0.5250 5.6400 1.0850 ;
      RECT 5.8550 0.3850 5.9250 0.5950 ;
      RECT 5.5700 0.5250 6.3050 0.5950 ;
      RECT 4.8100 0.3150 4.8800 1.0850 ;
      RECT 5.0000 0.2450 5.0700 0.3850 ;
      RECT 6.0450 0.2450 6.1150 0.4550 ;
      RECT 5.0000 0.2450 6.1150 0.3150 ;
      RECT 4.8100 0.3150 5.0700 0.3850 ;
      RECT 6.0450 0.3850 6.5900 0.4550 ;
      RECT 4.8100 1.0150 5.0700 1.0850 ;
      RECT 2.5300 0.2450 3.1700 0.3150 ;
      RECT 2.5300 1.0150 3.5500 1.0850 ;
      RECT 0.8200 1.1550 1.6500 1.2250 ;
      RECT 4.4300 0.9450 4.5000 1.2250 ;
      RECT 5.1900 0.9450 5.2600 1.2250 ;
      RECT 5.3800 0.7350 5.4500 1.0150 ;
      RECT 5.1900 0.9450 5.4500 1.0150 ;
      RECT 4.4300 1.1550 5.2600 1.2250 ;
      RECT 3.6700 0.2450 3.7400 0.4550 ;
      RECT 4.2400 0.2450 4.3100 1.3650 ;
      RECT 5.3800 1.1550 5.4500 1.3650 ;
      RECT 5.7600 0.8050 5.8300 1.2250 ;
      RECT 5.8550 0.7350 5.9250 0.8750 ;
      RECT 3.6700 0.2450 4.3100 0.3150 ;
      RECT 5.7600 0.8050 5.9250 0.8750 ;
      RECT 5.3800 1.1550 5.8300 1.2250 ;
      RECT 4.2400 1.2950 5.4500 1.3650 ;
  END
END SDFFR_X1

MACRO SDFFR_X2
  CLASS CORE ;
  ORIGIN 0 0 ;
  FOREIGN SDFFR_X2 0 0 ;
  SIZE 7.79 BY 1.40 ;
  SYMMETRY X Y ;
  SITE core ;
  PIN D
    DIRECTION INPUT ;
    USE SIGNAL ;
    PORT
      LAYER metal1 ;
        RECT 1.0100 0.5950 1.0800 0.8050 ;
    END
  END D
  PIN SI
    DIRECTION INPUT ;
    USE SIGNAL ;
    PORT
      LAYER metal1 ;
        RECT 1.5800 0.5950 1.6500 0.8050 ;
        RECT 1.4850 0.6650 1.6500 0.7350 ;
    END
  END SI
  PIN SE
    DIRECTION INPUT ;
    USE SIGNAL ;
    PORT
      LAYER metal1 ;
        RECT 0.3450 0.7350 0.4150 0.9450 ;
        RECT 1.2000 0.6650 1.2700 0.8750 ;
        RECT 1.2950 0.7350 1.3650 0.8750 ;
        RECT 1.2000 0.7350 1.3650 0.8050 ;
        RECT 1.2000 0.8050 1.4600 0.8750 ;
        RECT 0.3450 0.8750 0.5100 0.9450 ;
      LAYER via1 ;
        RECT 0.4425 0.8775 0.5075 0.9425 ;
        RECT 1.3925 0.8075 1.4575 0.8725 ;
      LAYER metal2 ;
        RECT 0.4400 0.8750 0.5100 1.0850 ;
        RECT 1.3900 0.8050 1.4600 1.0850 ;
        RECT 0.4400 1.0150 1.4600 1.0850 ;
    END
  END SE
  PIN CK
    DIRECTION INPUT ;
    USE CLOCK ;
    PORT
      LAYER metal1 ;
        RECT 4.6200 0.4550 4.6900 0.6650 ;
    END
  END CK
  PIN RN
    DIRECTION INPUT ;
    USE SIGNAL ;
    PORT
      LAYER metal1 ;
        RECT 4.2400 0.4550 4.3100 0.5950 ;
        RECT 4.3350 0.5250 4.4050 0.6650 ;
        RECT 4.4300 0.5250 4.5000 0.7350 ;
        RECT 7.4700 0.3850 7.7300 0.4550 ;
        RECT 4.2400 0.5250 4.5000 0.5950 ;
        RECT 4.3350 0.5950 4.5000 0.6650 ;
      LAYER via1 ;
        RECT 4.2425 0.4575 4.3075 0.5225 ;
        RECT 7.4725 0.3875 7.5375 0.4525 ;
      LAYER metal2 ;
        RECT 4.2400 0.0350 4.3100 0.5250 ;
        RECT 5.9500 0.0350 6.0200 0.3150 ;
        RECT 6.3300 0.2450 6.4000 0.3850 ;
        RECT 7.2800 0.3150 7.3500 0.4550 ;
        RECT 4.2400 0.0350 6.0200 0.1050 ;
        RECT 5.9500 0.2450 6.4000 0.3150 ;
        RECT 6.3300 0.3150 7.3500 0.3850 ;
        RECT 7.2800 0.3850 7.5400 0.4550 ;
    END
  END RN
  PIN Q
    DIRECTION OUTPUT ;
    USE SIGNAL ;
    PORT
      LAYER metal1 ;
        RECT 7.1850 0.7350 7.2550 1.0850 ;
        RECT 7.2800 1.0150 7.3500 1.2250 ;
        RECT 6.9000 0.4550 7.1600 0.5250 ;
        RECT 7.1850 1.0150 7.3500 1.0850 ;
      LAYER via1 ;
        RECT 7.0925 0.4575 7.1575 0.5225 ;
        RECT 7.1875 0.7375 7.2525 0.8025 ;
      LAYER metal2 ;
        RECT 7.0900 0.4550 7.1600 0.8050 ;
        RECT 7.0900 0.7350 7.2550 0.8050 ;
    END
  END Q
  PIN QN
    DIRECTION OUTPUT ;
    USE SIGNAL ;
    PORT
      LAYER metal1 ;
        RECT 6.1400 1.0150 6.2100 1.2250 ;
        RECT 5.9500 0.3850 6.2100 0.4550 ;
        RECT 5.9500 1.0150 6.2100 1.0850 ;
      LAYER via1 ;
        RECT 5.9525 0.3875 6.0175 0.4525 ;
        RECT 5.9525 1.0175 6.0175 1.0825 ;
      LAYER metal2 ;
        RECT 5.9500 0.3850 6.0200 1.0850 ;
        RECT 5.9500 0.3850 6.2100 0.4550 ;
    END
  END QN
  PIN VDD
    DIRECTION INOUT ;
    USE POWER ;
    SHAPE ABUTMENT ;
    PORT
      LAYER metal1 ;
        RECT 0.0000 1.3150 7.7900 1.4850 ;
        RECT 0.2500 1.1550 0.3200 1.3650 ;
        RECT 1.3900 1.1550 1.4600 1.3650 ;
        RECT 1.7700 1.1550 1.8400 1.3650 ;
        RECT 3.4800 1.1550 3.5500 1.3650 ;
        RECT 4.0500 1.1550 4.1200 1.3650 ;
        RECT 4.4300 1.1550 4.5000 1.3650 ;
        RECT 5.9500 1.1550 6.0200 1.3650 ;
        RECT 6.3300 1.1550 6.4000 1.3650 ;
        RECT 7.0900 1.1550 7.1600 1.3650 ;
        RECT 7.4700 1.1550 7.5400 1.3650 ;
    END
  END VDD
  PIN VSS
    DIRECTION INOUT ;
    USE GROUND ;
    SHAPE ABUTMENT ;
    PORT
      LAYER metal1 ;
        RECT 0.0000 -0.0850 7.7900 0.0850 ;
        RECT 0.2500 0.0350 0.3200 0.2450 ;
        RECT 0.6300 0.0350 0.7000 0.2450 ;
        RECT 1.2000 0.0350 1.2700 0.2450 ;
        RECT 1.7700 0.0350 1.8400 0.2450 ;
        RECT 3.4800 0.0350 3.5500 0.2450 ;
        RECT 4.4300 0.0350 4.5000 0.2450 ;
        RECT 5.9500 0.0350 6.0200 0.2450 ;
        RECT 6.5200 0.0350 6.5900 0.2450 ;
        RECT 6.9000 0.0350 6.9700 0.2450 ;
        RECT 7.6600 0.0350 7.7300 0.2450 ;
    END
  END VSS
  OBS
    LAYER metal1 ;
      RECT 0.0600 0.2450 0.1300 1.0850 ;
      RECT 0.0600 0.3850 0.5100 0.4550 ;
      RECT 2.7200 0.2450 2.7900 0.3850 ;
      RECT 4.0500 0.5950 4.1200 0.7350 ;
      RECT 2.7200 0.3150 2.8850 0.3850 ;
      RECT 4.0500 0.6650 4.2150 0.7350 ;
      RECT 2.5300 1.0150 2.7900 1.0850 ;
      RECT 3.3850 0.8050 3.4550 0.9450 ;
      RECT 3.8600 0.4550 3.9300 0.9450 ;
      RECT 4.1450 0.8750 4.2150 1.0150 ;
      RECT 4.2400 0.9450 4.3100 1.0850 ;
      RECT 4.3350 0.8750 4.4050 1.0150 ;
      RECT 5.0000 0.8750 5.0700 1.0850 ;
      RECT 5.3800 0.2450 5.4500 0.3850 ;
      RECT 5.4750 0.8050 5.5450 0.9450 ;
      RECT 5.5700 0.3150 5.6400 0.8750 ;
      RECT 5.3800 0.3150 5.6400 0.3850 ;
      RECT 3.8600 0.4550 4.1200 0.5250 ;
      RECT 5.4750 0.8050 5.6400 0.8750 ;
      RECT 3.3850 0.8750 4.2150 0.9450 ;
      RECT 4.3350 0.8750 5.5450 0.9450 ;
      RECT 4.1450 0.9450 4.4050 1.0150 ;
      RECT 5.1900 0.1750 5.2600 0.3850 ;
      RECT 5.1900 1.0150 5.2600 1.2250 ;
      RECT 6.4250 0.8050 6.4950 0.9450 ;
      RECT 6.9950 0.7350 7.0650 0.9450 ;
      RECT 5.7600 0.8750 7.0650 0.9450 ;
      RECT 7.2800 0.2450 7.3500 0.6650 ;
      RECT 7.3750 0.5950 7.4450 0.9450 ;
      RECT 7.6600 0.8750 7.7300 1.0850 ;
      RECT 7.2800 0.2450 7.5400 0.3150 ;
      RECT 6.8050 0.5950 7.4450 0.6650 ;
      RECT 7.3750 0.8750 7.7300 0.9450 ;
      RECT 2.9100 0.1750 3.3600 0.2450 ;
      RECT 2.5300 1.1550 3.3600 1.2250 ;
      RECT 6.5200 1.1550 6.9700 1.2250 ;
      RECT 5.0000 0.1750 5.0700 0.3150 ;
      RECT 4.9050 0.1750 5.0700 0.2450 ;
      RECT 5.5700 0.1750 5.8300 0.2450 ;
      RECT 5.3800 1.0150 5.8300 1.0850 ;
      RECT 1.9600 0.9450 2.0300 1.0850 ;
      RECT 2.0550 0.8050 2.1250 1.0150 ;
      RECT 2.1500 0.1750 2.2200 0.9450 ;
      RECT 2.9100 0.8750 2.9800 1.0850 ;
      RECT 1.9600 0.1750 2.6000 0.2450 ;
      RECT 2.0550 0.8050 2.2200 0.8750 ;
      RECT 2.0550 0.8750 2.9800 0.9450 ;
      RECT 1.9600 0.9450 2.1250 1.0150 ;
      RECT 0.6300 0.8750 0.7000 1.0850 ;
      RECT 0.7250 0.5250 0.7950 0.9450 ;
      RECT 0.8200 0.4550 0.8900 0.5950 ;
      RECT 1.0100 0.8750 1.0800 1.0850 ;
      RECT 1.5800 0.3850 1.6500 0.5250 ;
      RECT 1.5800 0.3850 1.8400 0.4550 ;
      RECT 0.8200 0.4550 1.6500 0.5250 ;
      RECT 0.7250 0.5250 0.8900 0.5950 ;
      RECT 0.6300 0.8750 1.0800 0.9450 ;
      RECT 1.2000 0.9450 1.2700 1.2250 ;
      RECT 1.5800 0.9450 1.6500 1.0850 ;
      RECT 1.2000 0.9450 1.6500 1.0150 ;
      RECT 0.4400 1.1550 1.2700 1.2250 ;
      RECT 6.2350 0.5250 6.3050 0.6650 ;
      RECT 6.3300 0.2450 6.4000 0.5950 ;
      RECT 6.7100 0.2450 6.7800 0.5250 ;
      RECT 6.3300 0.3850 6.7800 0.4550 ;
      RECT 6.2350 0.5250 6.4000 0.5950 ;
      RECT 6.6150 1.0150 6.8750 1.0850 ;
      RECT 2.5300 0.4550 2.6000 0.5950 ;
      RECT 3.6700 0.3150 3.7400 0.4550 ;
      RECT 4.6200 0.2450 4.6900 0.3850 ;
      RECT 4.7150 0.2450 4.7850 0.3850 ;
      RECT 4.8100 0.3150 4.8800 0.8050 ;
      RECT 4.6200 0.2450 4.7850 0.3150 ;
      RECT 3.6700 0.3150 4.8800 0.3850 ;
      RECT 3.0050 0.3850 3.7400 0.4550 ;
      RECT 4.8100 0.3850 5.0700 0.4550 ;
      RECT 2.5300 0.4550 2.6950 0.5250 ;
      RECT 4.6200 1.0150 4.8800 1.0850 ;
      RECT 3.1000 0.5250 3.1700 1.0850 ;
      RECT 3.6700 1.0150 3.7400 1.2250 ;
      RECT 3.6700 0.1750 3.9300 0.2450 ;
      RECT 2.9100 0.5250 3.2650 0.5950 ;
      RECT 5.0000 0.7350 5.3550 0.8050 ;
      RECT 3.1000 1.0150 3.7400 1.0850 ;
      RECT 3.6700 1.1550 3.9300 1.2250 ;
    LAYER via1 ;
      RECT 2.7225 0.2475 2.7875 0.3125 ;
      RECT 2.7225 1.0175 2.7875 1.0825 ;
      RECT 4.0525 0.6675 4.1175 0.7325 ;
      RECT 5.1925 0.3175 5.2575 0.3825 ;
      RECT 5.1925 1.0175 5.2575 1.0825 ;
      RECT 5.7625 0.8775 5.8275 0.9425 ;
      RECT 5.0025 0.1775 5.0675 0.2425 ;
      RECT 5.5725 0.1775 5.6375 0.2425 ;
      RECT 6.7125 0.4575 6.7775 0.5225 ;
      RECT 6.7125 1.0175 6.7775 1.0825 ;
      RECT 2.5325 0.4575 2.5975 0.5225 ;
      RECT 3.0075 0.3875 3.0725 0.4525 ;
      RECT 4.8125 0.7375 4.8775 0.8025 ;
      RECT 4.8125 1.0175 4.8775 1.0825 ;
      RECT 3.1975 0.5275 3.2625 0.5925 ;
      RECT 3.6725 0.1775 3.7375 0.2425 ;
      RECT 3.8625 1.1575 3.9275 1.2225 ;
      RECT 5.0025 0.7375 5.0675 0.8025 ;
    LAYER metal2 ;
      RECT 2.7200 0.2450 2.7900 1.0850 ;
      RECT 2.7200 0.6650 4.1200 0.7350 ;
      RECT 5.1900 0.3150 5.2600 1.0850 ;
      RECT 5.1900 0.8750 5.8300 0.9450 ;
      RECT 5.0000 0.1750 5.8300 0.2450 ;
      RECT 6.7100 0.4550 6.7800 1.0850 ;
      RECT 2.5300 0.1050 2.6000 0.5250 ;
      RECT 2.9100 0.1050 2.9800 0.4550 ;
      RECT 4.8100 0.7350 4.8800 1.0850 ;
      RECT 2.5300 0.1050 2.9800 0.1750 ;
      RECT 2.9100 0.3850 3.0750 0.4550 ;
      RECT 3.1950 0.1750 3.2650 0.5950 ;
      RECT 5.0000 0.7350 5.0700 1.2250 ;
      RECT 3.1950 0.1750 3.7400 0.2450 ;
      RECT 3.8600 1.1550 5.0700 1.2250 ;
  END
END SDFFR_X2

MACRO SDFFS_X1
  CLASS CORE ;
  ORIGIN 0 0 ;
  FOREIGN SDFFS_X1 0 0 ;
  SIZE 8.36 BY 1.40 ;
  SYMMETRY X Y ;
  SITE core ;
  PIN D
    DIRECTION INPUT ;
    USE SIGNAL ;
    PORT
      LAYER metal1 ;
        RECT 1.3900 0.1750 1.4600 0.3850 ;
    END
  END D
  PIN SI
    DIRECTION INPUT ;
    USE SIGNAL ;
    PORT
      LAYER metal1 ;
        RECT 2.1500 0.1750 2.2200 0.3850 ;
    END
  END SI
  PIN SE
    DIRECTION INPUT ;
    USE SIGNAL ;
    PORT
      LAYER metal1 ;
        RECT 1.5800 0.5950 1.6500 0.8050 ;
        RECT 0.3450 0.7350 0.7950 0.8050 ;
        RECT 1.2950 0.7350 1.6500 0.8050 ;
      LAYER via1 ;
        RECT 0.7275 0.7375 0.7925 0.8025 ;
        RECT 1.2975 0.7375 1.3625 0.8025 ;
      LAYER metal2 ;
        RECT 0.7250 0.7350 1.3650 0.8050 ;
    END
  END SE
  PIN CK
    DIRECTION INPUT ;
    USE CLOCK ;
    PORT
      LAYER metal1 ;
        RECT 6.5200 0.4550 6.5900 0.6650 ;
    END
  END CK
  PIN SN
    DIRECTION INPUT ;
    USE SIGNAL ;
    PORT
      LAYER metal1 ;
        RECT 7.0900 0.5950 7.1600 0.8050 ;
        RECT 7.0900 0.6650 7.2550 0.7350 ;
    END
  END SN
  PIN Q
    DIRECTION OUTPUT ;
    USE SIGNAL ;
    PORT
      LAYER metal1 ;
        RECT 8.2300 0.1750 8.3000 0.5950 ;
        RECT 8.2300 0.9450 8.3000 1.0850 ;
        RECT 8.1350 0.9450 8.3000 1.0150 ;
      LAYER via1 ;
        RECT 8.2325 0.5275 8.2975 0.5925 ;
        RECT 8.2325 0.9475 8.2975 1.0125 ;
      LAYER metal2 ;
        RECT 8.2300 0.5250 8.3000 1.0150 ;
    END
  END Q
  PIN QN
    DIRECTION OUTPUT ;
    USE SIGNAL ;
    PORT
      LAYER metal1 ;
        RECT 7.6600 0.9450 7.7300 1.0850 ;
        RECT 7.8500 0.1750 7.9200 0.3850 ;
        RECT 7.6600 0.3150 7.9200 0.3850 ;
        RECT 7.6600 1.0150 7.9200 1.0850 ;
      LAYER via1 ;
        RECT 7.6625 0.3175 7.7275 0.3825 ;
        RECT 7.6625 0.9475 7.7275 1.0125 ;
      LAYER metal2 ;
        RECT 7.6600 0.3150 7.7300 1.0150 ;
    END
  END QN
  PIN VDD
    DIRECTION INOUT ;
    USE POWER ;
    SHAPE ABUTMENT ;
    PORT
      LAYER metal1 ;
        RECT 0.0000 1.3150 8.3600 1.4850 ;
        RECT 0.2500 1.1550 0.3200 1.3650 ;
        RECT 1.7700 1.1550 1.8400 1.3650 ;
        RECT 2.1500 1.1550 2.2200 1.3650 ;
        RECT 3.2900 1.1550 3.3600 1.3650 ;
        RECT 4.8100 1.1550 4.8800 1.3650 ;
        RECT 6.3300 1.1550 6.4000 1.3650 ;
        RECT 7.0900 1.1550 7.1600 1.3650 ;
        RECT 7.4700 1.1550 7.5400 1.3650 ;
        RECT 8.0400 1.1550 8.1100 1.3650 ;
        RECT 2.1500 1.1550 2.4100 1.2250 ;
    END
  END VDD
  PIN VSS
    DIRECTION INOUT ;
    USE GROUND ;
    SHAPE ABUTMENT ;
    PORT
      LAYER metal1 ;
        RECT 0.0000 -0.0850 8.3600 0.0850 ;
        RECT 0.2500 0.0350 0.3200 0.2450 ;
        RECT 0.8200 0.0350 0.8900 0.2450 ;
        RECT 1.5800 0.0350 1.6500 0.2450 ;
        RECT 2.7200 0.0350 2.7900 0.2450 ;
        RECT 3.2900 0.0350 3.3600 0.2450 ;
        RECT 4.8100 0.0350 4.8800 0.2450 ;
        RECT 6.3300 0.0350 6.4000 0.2450 ;
        RECT 7.0900 0.0350 7.1600 0.2450 ;
        RECT 8.0400 0.0350 8.1100 0.2450 ;
    END
  END VSS
  OBS
    LAYER metal1 ;
      RECT 0.0600 0.2450 0.1300 1.0850 ;
      RECT 0.6300 0.3850 0.7000 0.6650 ;
      RECT 0.0600 0.3850 0.7000 0.4550 ;
      RECT 0.6300 0.5950 0.8900 0.6650 ;
      RECT 3.6700 0.3850 3.7400 0.8050 ;
      RECT 4.0500 0.2450 4.1200 0.4550 ;
      RECT 3.6700 0.3850 4.1200 0.4550 ;
      RECT 2.4350 0.5950 2.7900 0.6650 ;
      RECT 3.1000 0.5950 3.7400 0.6650 ;
      RECT 3.6700 0.7350 3.8350 0.8050 ;
      RECT 3.8600 1.0150 4.1200 1.0850 ;
      RECT 2.7200 0.8750 2.7900 1.0850 ;
      RECT 2.9100 0.1750 2.9800 0.9450 ;
      RECT 4.3350 0.8050 4.4050 0.9450 ;
      RECT 4.7150 0.8050 4.7850 0.9450 ;
      RECT 5.1900 0.2450 5.2600 0.9450 ;
      RECT 5.7600 0.8750 5.8300 1.0850 ;
      RECT 2.9100 0.1750 3.1700 0.2450 ;
      RECT 5.1900 0.2450 5.4500 0.3150 ;
      RECT 4.3350 0.8050 4.7850 0.8750 ;
      RECT 2.7200 0.8750 4.4050 0.9450 ;
      RECT 4.7150 0.8750 5.8300 0.9450 ;
      RECT 5.5700 0.2450 5.6400 0.4550 ;
      RECT 7.0900 0.8750 7.1600 1.0150 ;
      RECT 7.3750 0.8050 7.4450 0.9450 ;
      RECT 5.5700 0.3850 5.8300 0.4550 ;
      RECT 7.3750 0.8050 8.2050 0.8750 ;
      RECT 7.0900 0.8750 7.4450 0.9450 ;
      RECT 5.3800 1.0150 5.6400 1.0850 ;
      RECT 6.9000 0.1750 6.9700 1.0850 ;
      RECT 2.3400 0.1750 2.6000 0.2450 ;
      RECT 2.5300 1.1550 3.1700 1.2250 ;
      RECT 4.2400 0.1750 4.6900 0.2450 ;
      RECT 3.8600 1.1550 4.6900 1.2250 ;
      RECT 5.7600 0.1750 6.2100 0.2450 ;
      RECT 5.3800 1.1550 6.2100 1.2250 ;
      RECT 3.4800 0.1750 3.5500 0.3850 ;
      RECT 3.4800 0.1750 3.9300 0.2450 ;
      RECT 3.3850 1.0150 3.6450 1.0850 ;
      RECT 4.2400 1.0150 4.5000 1.0850 ;
      RECT 0.8200 0.9450 0.8900 1.0850 ;
      RECT 1.1050 0.4550 1.1750 1.0150 ;
      RECT 1.2000 0.9450 1.2700 1.0850 ;
      RECT 1.1050 0.4550 2.4100 0.5250 ;
      RECT 3.1950 0.4550 3.4550 0.5250 ;
      RECT 0.8200 0.9450 1.2700 1.0150 ;
      RECT 0.6300 1.0150 0.8900 1.0850 ;
      RECT 1.5800 0.9450 1.6500 1.2250 ;
      RECT 1.9600 0.9450 2.0300 1.0850 ;
      RECT 1.5800 0.9450 2.0300 1.0150 ;
      RECT 0.4400 1.1550 1.6500 1.2250 ;
      RECT 7.2800 0.4550 7.3500 0.5950 ;
      RECT 7.6600 0.4550 7.7300 0.5950 ;
      RECT 7.2800 0.4550 7.7300 0.5250 ;
      RECT 7.6600 0.5250 7.9200 0.5950 ;
      RECT 6.1400 0.7350 6.4000 0.8050 ;
      RECT 7.2800 1.0150 7.5400 1.0850 ;
      RECT 4.9050 0.6650 4.9750 0.8050 ;
      RECT 5.9500 0.7350 6.0200 0.9450 ;
      RECT 6.5200 0.8750 6.5900 1.0850 ;
      RECT 6.6150 0.8050 6.6850 1.0150 ;
      RECT 6.7100 0.2450 6.7800 0.8750 ;
      RECT 6.5200 0.2450 6.7800 0.3150 ;
      RECT 3.9550 0.6650 4.9750 0.7350 ;
      RECT 4.9050 0.7350 5.0700 0.8050 ;
      RECT 5.5700 0.7350 6.0200 0.8050 ;
      RECT 6.6150 0.8050 6.7800 0.8750 ;
      RECT 5.9500 0.8750 6.6850 0.9450 ;
      RECT 6.5200 0.9450 6.6850 1.0150 ;
      RECT 5.0000 0.2450 5.0700 0.4550 ;
      RECT 5.3800 0.3850 5.4500 0.5950 ;
      RECT 4.2400 0.3850 5.0700 0.4550 ;
      RECT 4.9050 1.0150 5.1650 1.0850 ;
    LAYER via1 ;
      RECT 2.7225 0.5975 2.7875 0.6625 ;
      RECT 3.1025 0.5975 3.1675 0.6625 ;
      RECT 3.7675 0.7375 3.8325 0.8025 ;
      RECT 3.8625 1.0175 3.9275 1.0825 ;
      RECT 5.5725 1.0175 5.6375 1.0825 ;
      RECT 5.7625 0.3875 5.8275 0.4525 ;
      RECT 7.0925 0.9475 7.1575 1.0125 ;
      RECT 2.5325 0.1775 2.5975 0.2425 ;
      RECT 6.9025 0.1775 6.9675 0.2425 ;
      RECT 3.4825 0.3175 3.5475 0.3825 ;
      RECT 3.4825 1.0175 3.5475 1.0825 ;
      RECT 4.2425 1.0175 4.3075 1.0825 ;
      RECT 2.3425 0.4575 2.4075 0.5225 ;
      RECT 3.1975 0.4575 3.2625 0.5225 ;
      RECT 6.3325 0.7375 6.3975 0.8025 ;
      RECT 7.2825 0.4575 7.3475 0.5225 ;
      RECT 7.2825 1.0175 7.3475 1.0825 ;
      RECT 5.0025 0.7375 5.0675 0.8025 ;
      RECT 5.5725 0.7375 5.6375 0.8025 ;
      RECT 4.8125 0.3875 4.8775 0.4525 ;
      RECT 4.9075 1.0175 4.9725 1.0825 ;
      RECT 5.3825 0.3875 5.4475 0.4525 ;
    LAYER metal2 ;
      RECT 3.7650 0.7350 3.8350 1.0850 ;
      RECT 2.7200 0.5950 3.1700 0.6650 ;
      RECT 3.7650 1.0150 4.1200 1.0850 ;
      RECT 5.5700 0.8750 5.6400 1.0850 ;
      RECT 5.7600 0.3850 5.8300 1.0150 ;
      RECT 5.5700 0.8750 5.8300 0.9450 ;
      RECT 5.7600 0.9450 7.1600 1.0150 ;
      RECT 2.5300 0.1750 6.9700 0.2450 ;
      RECT 3.4800 0.3150 3.5500 1.2250 ;
      RECT 4.2400 1.0150 4.3100 1.2250 ;
      RECT 3.4800 1.1550 4.3100 1.2250 ;
      RECT 2.3400 0.4550 3.3600 0.5250 ;
      RECT 6.3300 0.7350 6.4000 0.8750 ;
      RECT 6.7100 0.3850 6.7800 0.8750 ;
      RECT 7.2800 0.3850 7.3500 1.0850 ;
      RECT 6.7100 0.3850 7.3500 0.4550 ;
      RECT 6.3300 0.8050 6.7800 0.8750 ;
      RECT 5.0000 0.7350 5.6400 0.8050 ;
      RECT 4.8100 0.3850 4.8800 1.0850 ;
      RECT 4.8100 0.3850 5.4500 0.4550 ;
      RECT 4.8100 1.0150 5.0700 1.0850 ;
  END
END SDFFS_X1

MACRO DLH_X1
  CLASS CORE ;
  ORIGIN 0 0 ;
  FOREIGN DLH_X1 0 0 ;
  SIZE 2.85 BY 1.40 ;
  SYMMETRY X Y ;
  SITE core ;
  PIN D
    DIRECTION INPUT ;
    USE SIGNAL ;
    PORT
      LAYER metal1 ;
        RECT 0.8200 0.1750 0.8900 0.3850 ;
        RECT 1.3900 0.8750 1.4600 1.0850 ;
        RECT 0.8200 0.2450 1.0800 0.3150 ;
        RECT 1.2000 0.8750 1.4600 0.9450 ;
      LAYER via1 ;
        RECT 1.0125 0.2475 1.0775 0.3125 ;
        RECT 1.2025 0.8775 1.2675 0.9425 ;
      LAYER metal2 ;
        RECT 1.2000 0.2450 1.2700 0.9450 ;
        RECT 1.0100 0.2450 1.2700 0.3150 ;
    END
  END D
  PIN E
    DIRECTION INPUT ;
    USE SIGNAL ;
    PORT
      LAYER metal1 ;
        RECT 0.0600 0.5250 0.1300 0.7350 ;
    END
  END E
  PIN Q
    DIRECTION OUTPUT ;
    USE SIGNAL ;
    PORT
      LAYER metal1 ;
        RECT 2.7200 0.1750 2.7900 1.0850 ;
    END
  END Q
  PIN VDD
    DIRECTION INOUT ;
    USE POWER ;
    SHAPE ABUTMENT ;
    PORT
      LAYER metal1 ;
        RECT 0.0000 1.3150 2.8500 1.4850 ;
        RECT 0.2500 1.1550 0.3200 1.3650 ;
        RECT 1.9600 1.1550 2.0300 1.3650 ;
        RECT 2.5300 1.1550 2.6000 1.3650 ;
    END
  END VDD
  PIN VSS
    DIRECTION INOUT ;
    USE GROUND ;
    SHAPE ABUTMENT ;
    PORT
      LAYER metal1 ;
        RECT 0.0000 -0.0850 2.8500 0.0850 ;
        RECT 0.2500 0.0350 0.3200 0.2450 ;
        RECT 1.9600 0.0350 2.0300 0.2450 ;
        RECT 2.5300 0.0350 2.6000 0.2450 ;
    END
  END VSS
  OBS
    LAYER metal1 ;
      RECT 0.0600 0.2450 0.1300 0.4550 ;
      RECT 0.0600 0.8750 0.1300 1.0850 ;
      RECT 0.3450 0.3850 0.4150 0.9450 ;
      RECT 0.0600 0.3850 0.4150 0.4550 ;
      RECT 0.3450 0.6650 0.5100 0.7350 ;
      RECT 0.8200 0.6650 1.3650 0.7350 ;
      RECT 0.0600 0.8750 0.4150 0.9450 ;
      RECT 0.5350 0.8050 0.6050 1.0850 ;
      RECT 0.6300 0.2450 0.7000 0.8750 ;
      RECT 0.4400 0.2450 0.7000 0.3150 ;
      RECT 0.6300 0.5250 1.0800 0.5950 ;
      RECT 0.5350 0.8050 0.7000 0.8750 ;
      RECT 0.4400 1.0150 0.6050 1.0850 ;
      RECT 1.2000 0.2450 1.2700 0.4550 ;
      RECT 1.5800 0.3850 1.6500 1.2250 ;
      RECT 1.2000 0.3850 1.6500 0.4550 ;
      RECT 1.5800 0.5250 2.1250 0.5950 ;
      RECT 1.2000 1.1550 1.6500 1.2250 ;
      RECT 2.1500 0.9450 2.2200 1.0850 ;
      RECT 2.2450 0.8050 2.3150 1.0150 ;
      RECT 2.3400 0.2450 2.4100 0.8750 ;
      RECT 2.1500 0.2450 2.4100 0.3150 ;
      RECT 1.8650 0.3850 2.6000 0.4550 ;
      RECT 2.2450 0.8050 2.4100 0.8750 ;
      RECT 2.1500 0.9450 2.3150 1.0150 ;
      RECT 1.3900 0.2450 1.8400 0.3150 ;
      RECT 0.9150 1.0150 1.1750 1.0850 ;
      RECT 1.7700 1.0150 2.0300 1.0850 ;
    LAYER via1 ;
      RECT 0.4425 0.6675 0.5075 0.7325 ;
      RECT 0.8225 0.6675 0.8875 0.7325 ;
      RECT 1.0125 1.0175 1.0775 1.0825 ;
      RECT 1.7725 1.0175 1.8375 1.0825 ;
    LAYER metal2 ;
      RECT 0.4400 0.6650 0.8900 0.7350 ;
      RECT 1.0100 1.0150 1.8400 1.0850 ;
  END
END DLH_X1

MACRO DLH_X2
  CLASS CORE ;
  ORIGIN 0 0 ;
  FOREIGN DLH_X2 0 0 ;
  SIZE 2.85 BY 1.40 ;
  SYMMETRY X Y ;
  SITE core ;
  PIN D
    DIRECTION INPUT ;
    USE SIGNAL ;
    PORT
      LAYER metal1 ;
        RECT 1.2000 0.3150 1.2700 0.9450 ;
        RECT 1.3900 0.1750 1.4600 0.3850 ;
        RECT 1.7700 0.8750 1.8400 1.0850 ;
        RECT 1.2000 0.3150 1.4600 0.3850 ;
        RECT 1.2000 0.8750 1.8400 0.9450 ;
    END
  END D
  PIN E
    DIRECTION INPUT ;
    USE SIGNAL ;
    PORT
      LAYER metal1 ;
        RECT 2.7200 0.5250 2.7900 0.7350 ;
    END
  END E
  PIN Q
    DIRECTION OUTPUT ;
    USE SIGNAL ;
    PORT
      LAYER metal1 ;
        RECT 0.4400 1.0150 0.5100 1.2250 ;
        RECT 0.5350 0.4550 0.6050 0.8050 ;
        RECT 0.4400 0.4550 0.6050 0.5250 ;
        RECT 0.5350 0.7350 0.7000 0.8050 ;
        RECT 0.4400 1.0150 0.7000 1.0850 ;
      LAYER via1 ;
        RECT 0.6325 0.7375 0.6975 0.8025 ;
        RECT 0.6325 1.0175 0.6975 1.0825 ;
      LAYER metal2 ;
        RECT 0.6300 0.7350 0.7000 1.0850 ;
    END
  END Q
  PIN VDD
    DIRECTION INOUT ;
    USE POWER ;
    SHAPE ABUTMENT ;
    PORT
      LAYER metal1 ;
        RECT 0.0000 1.3150 2.8500 1.4850 ;
        RECT 0.2500 1.1550 0.3200 1.3650 ;
        RECT 0.6300 1.1550 0.7000 1.3650 ;
        RECT 2.5300 1.1550 2.6000 1.3650 ;
    END
  END VDD
  PIN VSS
    DIRECTION INOUT ;
    USE GROUND ;
    SHAPE ABUTMENT ;
    PORT
      LAYER metal1 ;
        RECT 0.0000 -0.0850 2.8500 0.0850 ;
        RECT 0.2500 0.0350 0.3200 0.2450 ;
        RECT 0.6300 0.0350 0.7000 0.2450 ;
        RECT 2.5300 0.0350 2.6000 0.2450 ;
    END
  END VSS
  OBS
    LAYER metal1 ;
      RECT 2.4350 0.3850 2.5050 0.9450 ;
      RECT 2.7200 0.2450 2.7900 0.4550 ;
      RECT 2.7200 0.8750 2.7900 1.0850 ;
      RECT 1.7700 0.3850 2.7900 0.4550 ;
      RECT 2.4350 0.8750 2.7900 0.9450 ;
      RECT 2.1500 0.5250 2.2200 1.0850 ;
      RECT 2.1500 0.2450 2.4100 0.3150 ;
      RECT 1.4850 0.7350 2.2200 0.8050 ;
      RECT 2.1500 1.0150 2.4100 1.0850 ;
      RECT 0.1550 0.8050 0.2250 0.9450 ;
      RECT 1.0100 0.8750 1.0800 1.0850 ;
      RECT 1.5800 0.1750 1.6500 0.3850 ;
      RECT 0.1550 0.8750 1.0800 0.9450 ;
      RECT 1.0100 1.0150 1.6500 1.0850 ;
      RECT 0.0600 0.2450 0.1300 0.4550 ;
      RECT 0.2500 0.3850 0.3200 0.7350 ;
      RECT 0.0600 0.3850 0.3200 0.4550 ;
      RECT 0.2500 0.5950 0.4150 0.6650 ;
      RECT 0.0600 1.0150 0.3200 1.0850 ;
      RECT 0.8200 0.1750 1.2700 0.2450 ;
      RECT 1.7700 0.1750 2.0300 0.2450 ;
      RECT 0.8200 1.1550 1.4600 1.2250 ;
    LAYER via1 ;
      RECT 2.1525 0.2475 2.2175 0.3125 ;
      RECT 2.1525 0.5275 2.2175 0.5925 ;
      RECT 1.5825 0.3175 1.6475 0.3825 ;
      RECT 1.5825 1.0175 1.6475 1.0825 ;
      RECT 0.0625 1.0175 0.1275 1.0825 ;
      RECT 0.2525 0.6675 0.3175 0.7325 ;
      RECT 1.2025 0.1775 1.2675 0.2425 ;
      RECT 1.7725 0.1775 1.8375 0.2425 ;
    LAYER metal2 ;
      RECT 2.1500 0.2450 2.2200 0.5950 ;
      RECT 1.5800 0.3150 1.6500 1.0850 ;
      RECT 0.0600 0.6650 0.1300 1.0850 ;
      RECT 0.0600 0.6650 0.3200 0.7350 ;
      RECT 1.2000 -0.0350 1.2700 0.2450 ;
      RECT 1.5800 -0.0350 1.6500 0.2450 ;
      RECT 1.2000 -0.0350 1.6500 0.0350 ;
      RECT 1.5800 0.1750 1.8400 0.2450 ;
  END
END DLH_X2

MACRO DLL_X1
  CLASS CORE ;
  ORIGIN 0 0 ;
  FOREIGN DLL_X1 0 0 ;
  SIZE 2.28 BY 1.40 ;
  SYMMETRY X Y ;
  SITE core ;
  PIN D
    DIRECTION INPUT ;
    USE SIGNAL ;
    PORT
      LAYER metal1 ;
        RECT 0.8200 0.8750 0.8900 1.0850 ;
        RECT 1.2000 0.1750 1.2700 0.5950 ;
        RECT 1.2950 0.5250 1.3650 0.9450 ;
        RECT 1.2000 0.5250 1.3650 0.5950 ;
        RECT 0.8200 0.8750 1.3650 0.9450 ;
    END
  END D
  PIN EN
    DIRECTION INPUT ;
    USE SIGNAL ;
    PORT
      LAYER metal1 ;
        RECT 0.0600 0.5250 0.1300 0.7350 ;
    END
  END EN
  PIN Q
    DIRECTION OUTPUT ;
    USE SIGNAL ;
    PORT
      LAYER metal1 ;
        RECT 2.1500 0.1750 2.2200 1.0850 ;
    END
  END Q
  PIN VDD
    DIRECTION INOUT ;
    USE POWER ;
    SHAPE ABUTMENT ;
    PORT
      LAYER metal1 ;
        RECT 0.0000 1.3150 2.2800 1.4850 ;
        RECT 0.2500 1.1550 0.3200 1.3650 ;
        RECT 1.5800 1.1550 1.6500 1.3650 ;
        RECT 1.9600 1.1550 2.0300 1.3650 ;
    END
  END VDD
  PIN VSS
    DIRECTION INOUT ;
    USE GROUND ;
    SHAPE ABUTMENT ;
    PORT
      LAYER metal1 ;
        RECT 0.0000 -0.0850 2.2800 0.0850 ;
        RECT 0.2500 0.0350 0.3200 0.2450 ;
        RECT 1.5800 0.0350 1.6500 0.2450 ;
        RECT 1.6750 0.0350 1.7450 0.1750 ;
        RECT 1.9600 0.0350 2.0300 0.2450 ;
        RECT 1.5800 0.0350 1.7450 0.1050 ;
        RECT 1.5800 0.1050 1.7450 0.1750 ;
    END
  END VSS
  OBS
    LAYER metal1 ;
      RECT 0.0600 0.2450 0.1300 0.4550 ;
      RECT 0.0600 0.8750 0.1300 1.0850 ;
      RECT 0.3450 0.3850 0.4150 0.9450 ;
      RECT 0.0600 0.3850 0.4150 0.4550 ;
      RECT 0.3450 0.6650 0.5100 0.7350 ;
      RECT 0.8200 0.6650 1.1750 0.7350 ;
      RECT 0.0600 0.8750 0.4150 0.9450 ;
      RECT 0.5350 0.2450 0.6050 0.5250 ;
      RECT 0.5350 0.8050 0.6050 1.0850 ;
      RECT 0.6300 0.4550 0.7000 0.8750 ;
      RECT 0.4400 0.2450 0.6050 0.3150 ;
      RECT 0.5350 0.4550 0.7000 0.5250 ;
      RECT 0.6300 0.5250 0.8900 0.5950 ;
      RECT 0.5350 0.8050 0.7000 0.8750 ;
      RECT 0.4400 1.0150 0.6050 1.0850 ;
      RECT 1.0100 0.2450 1.0800 0.3850 ;
      RECT 1.0100 1.0150 1.0800 1.2250 ;
      RECT 0.9150 0.3150 1.0800 0.3850 ;
      RECT 1.4850 0.5250 1.7450 0.5950 ;
      RECT 1.4850 0.8050 1.5550 0.9450 ;
      RECT 1.7700 0.2450 1.8400 0.4550 ;
      RECT 1.7700 0.8750 1.8400 1.0850 ;
      RECT 1.8650 0.8050 1.9350 0.9450 ;
      RECT 1.9600 0.3850 2.0300 0.8750 ;
      RECT 1.7700 0.3850 2.0300 0.4550 ;
      RECT 1.8650 0.8050 2.0300 0.8750 ;
      RECT 1.4850 0.8750 1.9350 0.9450 ;
      RECT 0.7250 0.1750 0.7950 0.3150 ;
      RECT 1.3900 0.1750 1.4600 0.3850 ;
      RECT 0.7250 0.1750 0.8900 0.2450 ;
      RECT 1.2000 1.0150 1.4600 1.0850 ;
    LAYER via1 ;
      RECT 0.4425 0.6675 0.5075 0.7325 ;
      RECT 0.8225 0.6675 0.8875 0.7325 ;
      RECT 1.0125 0.2475 1.0775 0.3125 ;
      RECT 1.0125 1.0175 1.0775 1.0825 ;
      RECT 1.4875 0.5275 1.5525 0.5925 ;
      RECT 0.8225 0.1775 0.8875 0.2425 ;
      RECT 1.3925 0.1775 1.4575 0.2425 ;
    LAYER metal2 ;
      RECT 0.4400 0.6650 0.8900 0.7350 ;
      RECT 1.0100 0.2450 1.0800 1.0850 ;
      RECT 1.0100 0.5250 1.6500 0.5950 ;
      RECT 0.8200 -0.0350 0.8900 0.2450 ;
      RECT 1.3900 -0.0350 1.4600 0.2450 ;
      RECT 0.8200 -0.0350 1.4600 0.0350 ;
  END
END DLL_X1

MACRO CLKGATE_X1
  CLASS CORE ;
  ORIGIN 0 0 ;
  FOREIGN CLKGATE_X1 0 0 ;
  SIZE 4.18 BY 1.40 ;
  SYMMETRY X Y ;
  SITE core ;
  PIN CK
    DIRECTION INPUT ;
    USE CLOCK ;
    PORT
      LAYER metal1 ;
        RECT 2.6250 0.6650 2.6950 0.8050 ;
        RECT 2.7200 0.5250 2.7900 0.7350 ;
        RECT 2.6250 0.6650 2.7900 0.7350 ;
        RECT 2.2450 0.7350 2.6950 0.8050 ;
    END
  END CK
  PIN E
    DIRECTION INPUT ;
    USE SIGNAL ;
    PORT
      LAYER metal1 ;
        RECT 2.9100 0.2450 2.9800 0.4550 ;
        RECT 3.7650 0.3850 3.8350 0.5250 ;
        RECT 3.8600 0.3850 3.9300 0.5950 ;
        RECT 3.6700 0.3850 3.9300 0.4550 ;
        RECT 3.7650 0.4550 3.9300 0.5250 ;
      LAYER via1 ;
        RECT 2.9125 0.3175 2.9775 0.3825 ;
        RECT 3.6725 0.3875 3.7375 0.4525 ;
      LAYER metal2 ;
        RECT 3.4800 0.3150 3.5500 0.4550 ;
        RECT 2.9100 0.3150 3.5500 0.3850 ;
        RECT 3.4800 0.3850 3.7400 0.4550 ;
    END
  END E
  PIN SE
    DIRECTION INPUT ;
    USE SIGNAL ;
    PORT
      LAYER metal1 ;
        RECT 3.2900 0.5250 3.3600 0.7350 ;
        RECT 3.2900 0.5950 3.5500 0.6650 ;
    END
  END SE
  PIN GCK
    DIRECTION OUTPUT ;
    USE SIGNAL ;
    PORT
      LAYER metal1 ;
        RECT 4.0500 0.1750 4.1200 0.5950 ;
        RECT 4.0500 0.9450 4.1200 1.0850 ;
        RECT 3.9550 1.0150 4.1200 1.0850 ;
      LAYER via1 ;
        RECT 4.0525 0.5275 4.1175 0.5925 ;
        RECT 4.0525 0.9475 4.1175 1.0125 ;
      LAYER metal2 ;
        RECT 4.0500 0.5250 4.1200 1.0150 ;
    END
  END GCK
  PIN VDD
    DIRECTION INOUT ;
    USE POWER ;
    SHAPE ABUTMENT ;
    PORT
      LAYER metal1 ;
        RECT 0.0000 1.3150 4.1800 1.4850 ;
        RECT 0.0600 1.1550 0.1300 1.3650 ;
        RECT 1.5800 1.1550 1.6500 1.3650 ;
        RECT 2.3400 1.1550 2.4100 1.3650 ;
        RECT 2.7200 1.1550 2.7900 1.3650 ;
        RECT 3.8600 1.1550 3.9300 1.3650 ;
        RECT 2.7200 1.1550 2.9800 1.2250 ;
    END
  END VDD
  PIN VSS
    DIRECTION INOUT ;
    USE GROUND ;
    SHAPE ABUTMENT ;
    PORT
      LAYER metal1 ;
        RECT 0.0000 -0.0850 4.1800 0.0850 ;
        RECT 0.0600 0.0350 0.1300 0.2450 ;
        RECT 1.5800 0.0350 1.6500 0.2450 ;
        RECT 2.3400 0.0350 2.4100 0.2450 ;
        RECT 3.2900 0.0350 3.3600 0.2450 ;
        RECT 3.8600 0.0350 3.9300 0.2450 ;
    END
  END VSS
  OBS
    LAYER metal1 ;
      RECT 0.2500 0.6650 0.3200 0.8050 ;
      RECT 1.9600 0.5250 2.0300 0.8050 ;
      RECT 2.0550 0.2450 2.1250 0.5950 ;
      RECT 2.0550 0.2450 2.2200 0.3150 ;
      RECT 1.9600 0.5250 2.1250 0.5950 ;
      RECT 0.2500 0.7350 0.9850 0.8050 ;
      RECT 1.9600 1.0150 2.2200 1.0850 ;
      RECT 0.0600 0.4550 0.1300 0.9450 ;
      RECT 0.2500 0.2450 0.3200 0.5250 ;
      RECT 0.2500 0.8750 0.3200 1.0850 ;
      RECT 0.4400 0.4550 0.5100 0.5950 ;
      RECT 0.0600 0.4550 0.5100 0.5250 ;
      RECT 0.0600 0.8750 0.3200 0.9450 ;
      RECT 0.7250 0.1750 0.7950 0.5950 ;
      RECT 0.6300 0.1750 0.8900 0.2450 ;
      RECT 1.3900 0.3850 1.7450 0.4550 ;
      RECT 0.6300 1.0150 0.8900 1.0850 ;
      RECT 1.7700 0.1750 1.8400 0.3150 ;
      RECT 2.4350 0.5250 2.5050 0.6650 ;
      RECT 1.7700 0.2450 1.9350 0.3150 ;
      RECT 1.3900 0.5250 1.6500 0.5950 ;
      RECT 2.3400 0.5250 2.5050 0.5950 ;
      RECT 1.7700 1.1550 2.0300 1.2250 ;
      RECT 0.4400 0.8750 0.5100 1.0850 ;
      RECT 1.1050 0.2450 1.1750 0.9450 ;
      RECT 3.1000 0.2450 3.1700 0.9450 ;
      RECT 3.2900 0.8750 3.3600 1.0850 ;
      RECT 3.4800 0.2450 3.5500 0.4550 ;
      RECT 1.0100 0.2450 1.1750 0.3150 ;
      RECT 3.4800 0.2450 3.7400 0.3150 ;
      RECT 3.1000 0.3850 3.5500 0.4550 ;
      RECT 0.4400 0.8750 3.3600 0.9450 ;
      RECT 3.2900 1.0150 3.5500 1.0850 ;
      RECT 3.1000 1.1550 3.7400 1.2250 ;
      RECT 0.4400 0.1750 0.5100 0.3850 ;
      RECT 1.2950 0.1750 1.3650 0.3150 ;
      RECT 1.2950 0.1750 1.4600 0.2450 ;
      RECT 1.0100 1.0150 1.4600 1.0850 ;
      RECT 3.8600 0.8050 3.9300 0.9450 ;
      RECT 2.5300 0.3850 2.7900 0.4550 ;
      RECT 3.8600 0.8050 4.0250 0.8750 ;
      RECT 3.4800 0.8750 3.9300 0.9450 ;
      RECT 2.4350 1.0150 2.6950 1.0850 ;
    LAYER via1 ;
      RECT 0.9175 0.7375 0.9825 0.8025 ;
      RECT 1.9625 0.7375 2.0275 0.8025 ;
      RECT 1.9625 1.0175 2.0275 1.0825 ;
      RECT 0.7275 0.3875 0.7925 0.4525 ;
      RECT 0.7275 1.0175 0.7925 1.0825 ;
      RECT 1.3925 0.3875 1.4575 0.4525 ;
      RECT 1.5825 0.5275 1.6475 0.5925 ;
      RECT 1.7725 0.2475 1.8375 0.3125 ;
      RECT 1.9625 1.1575 2.0275 1.2225 ;
      RECT 2.3425 0.5275 2.4075 0.5925 ;
      RECT 0.4425 0.1775 0.5075 0.2425 ;
      RECT 1.2975 0.1775 1.3625 0.2425 ;
      RECT 2.5325 0.3875 2.5975 0.4525 ;
      RECT 2.5325 1.0175 2.5975 1.0825 ;
      RECT 3.4825 0.8775 3.5475 0.9425 ;
    LAYER metal2 ;
      RECT 1.9600 0.7350 2.0300 1.0850 ;
      RECT 0.9150 0.7350 2.0300 0.8050 ;
      RECT 0.7250 0.3850 0.7950 1.0850 ;
      RECT 0.7250 0.3850 1.4600 0.4550 ;
      RECT 1.5800 0.2450 1.6500 0.5950 ;
      RECT 2.1500 0.5250 2.2200 1.2250 ;
      RECT 1.5800 0.2450 1.8400 0.3150 ;
      RECT 1.5800 0.5250 2.4100 0.5950 ;
      RECT 1.9600 1.1550 2.2200 1.2250 ;
      RECT 0.4400 0.1750 1.4600 0.2450 ;
      RECT 2.5300 0.3850 2.6000 1.0850 ;
      RECT 2.5300 0.8750 3.5500 0.9450 ;
  END
END CLKGATE_X1

MACRO CLKGATE_X2
  CLASS CORE ;
  ORIGIN 0 0 ;
  FOREIGN CLKGATE_X2 0 0 ;
  SIZE 4.18 BY 1.40 ;
  SYMMETRY X Y ;
  SITE core ;
  PIN CK
    DIRECTION INPUT ;
    USE CLOCK ;
    PORT
      LAYER metal1 ;
        RECT 0.4400 0.7350 0.5100 0.9450 ;
        RECT 0.5350 0.5950 0.6050 0.8750 ;
        RECT 0.5350 0.5950 0.9850 0.6650 ;
        RECT 0.4400 0.7350 0.6050 0.8050 ;
        RECT 0.4400 0.8050 0.6050 0.8750 ;
    END
  END CK
  PIN E
    DIRECTION INPUT ;
    USE SIGNAL ;
    PORT
      LAYER metal1 ;
        RECT 3.2900 0.4550 3.3600 0.6650 ;
        RECT 3.3850 0.5250 3.4550 0.8750 ;
        RECT 3.2900 0.5250 3.4550 0.5950 ;
        RECT 3.7650 0.5250 4.0250 0.5950 ;
        RECT 3.2900 0.5950 3.4550 0.6650 ;
      LAYER via1 ;
        RECT 3.3875 0.8075 3.4525 0.8725 ;
        RECT 3.7675 0.5275 3.8325 0.5925 ;
      LAYER metal2 ;
        RECT 3.4800 0.5250 3.5500 0.8750 ;
        RECT 3.4800 0.5250 3.8350 0.5950 ;
        RECT 3.3850 0.8050 3.5500 0.8750 ;
    END
  END E
  PIN SE
    DIRECTION INPUT ;
    USE SIGNAL ;
    PORT
      LAYER metal1 ;
        RECT 3.7650 0.7350 3.8350 0.8750 ;
        RECT 3.8600 0.7350 3.9300 0.9450 ;
        RECT 3.7650 0.7350 3.9300 0.8050 ;
        RECT 3.7650 0.8050 3.9300 0.8750 ;
    END
  END SE
  PIN GCK
    DIRECTION OUTPUT ;
    USE SIGNAL ;
    PORT
      LAYER metal1 ;
        RECT 0.2500 0.4550 0.3200 1.1550 ;
    END
  END GCK
  PIN VDD
    DIRECTION INOUT ;
    USE POWER ;
    SHAPE ABUTMENT ;
    PORT
      LAYER metal1 ;
        RECT 0.0000 1.3150 4.1800 1.4850 ;
        RECT 0.0600 1.1550 0.1300 1.3650 ;
        RECT 0.4400 1.1550 0.5100 1.3650 ;
        RECT 0.8200 1.1550 0.8900 1.3650 ;
        RECT 1.7700 1.1550 1.8400 1.3650 ;
        RECT 3.2900 1.1550 3.3600 1.3650 ;
        RECT 4.0500 1.1550 4.1200 1.3650 ;
    END
  END VDD
  PIN VSS
    DIRECTION INOUT ;
    USE GROUND ;
    SHAPE ABUTMENT ;
    PORT
      LAYER metal1 ;
        RECT 0.0000 -0.0850 4.1800 0.0850 ;
        RECT 0.0600 0.0350 0.1300 0.2450 ;
        RECT 0.8200 0.0350 0.8900 0.2450 ;
        RECT 1.7700 0.0350 1.8400 0.2450 ;
        RECT 3.2900 0.0350 3.3600 0.2450 ;
        RECT 3.6700 0.0350 3.7400 0.2450 ;
    END
  END VSS
  OBS
    LAYER metal1 ;
      RECT 1.0100 0.9450 1.0800 1.0850 ;
      RECT 1.1050 0.8050 1.1750 1.0150 ;
      RECT 1.2000 0.2450 1.2700 0.8750 ;
      RECT 1.0100 0.2450 1.2700 0.3150 ;
      RECT 1.1050 0.8050 3.2650 0.8750 ;
      RECT 1.0100 0.9450 1.1750 1.0150 ;
      RECT 2.8150 0.4550 2.8850 0.7350 ;
      RECT 3.0050 0.2450 3.0750 0.5250 ;
      RECT 3.0050 0.2450 3.1700 0.3150 ;
      RECT 2.8150 0.4550 3.0750 0.5250 ;
      RECT 2.7200 0.5250 2.8850 0.5950 ;
      RECT 2.8150 0.6650 2.9800 0.7350 ;
      RECT 2.9100 1.0850 3.1700 1.1550 ;
      RECT 2.5300 0.2450 2.6000 0.3850 ;
      RECT 2.5300 0.9450 2.6000 1.1550 ;
      RECT 2.5300 0.3150 2.6950 0.3850 ;
      RECT 1.6750 0.5250 2.3150 0.5950 ;
      RECT 1.5800 0.2450 1.6500 0.4550 ;
      RECT 1.5800 0.9450 1.6500 1.0850 ;
      RECT 1.5800 0.3850 1.9350 0.4550 ;
      RECT 0.7250 0.8050 0.9850 0.8750 ;
      RECT 1.5800 0.9450 1.7450 1.0150 ;
      RECT 2.3400 0.2450 2.4100 0.3850 ;
      RECT 2.7200 0.9450 2.7900 1.1550 ;
      RECT 3.4800 0.2450 3.5500 0.4550 ;
      RECT 3.5750 0.3850 3.6450 1.0150 ;
      RECT 3.6700 0.9450 3.7400 1.0850 ;
      RECT 2.2450 0.3150 2.4100 0.3850 ;
      RECT 3.4800 0.3850 3.6450 0.4550 ;
      RECT 2.7200 0.9450 3.7400 1.0150 ;
      RECT 3.4800 1.1550 3.9300 1.2250 ;
      RECT 2.8150 0.1750 2.8850 0.3150 ;
      RECT 1.9600 0.1750 2.2200 0.2450 ;
      RECT 2.7200 0.1750 2.8850 0.2450 ;
      RECT 1.9600 1.0150 2.4100 1.0850 ;
      RECT 0.0600 0.4550 0.1300 0.6650 ;
      RECT 0.6300 0.9450 0.7000 1.0850 ;
      RECT 0.4400 0.4550 0.7000 0.5250 ;
      RECT 0.6300 0.9450 0.7950 1.0150 ;
    LAYER via1 ;
      RECT 2.9125 0.6675 2.9775 0.7325 ;
      RECT 2.9125 1.0875 2.9775 1.1525 ;
      RECT 2.2475 0.5275 2.3125 0.5925 ;
      RECT 2.5325 0.2475 2.5975 0.3125 ;
      RECT 2.5325 0.9475 2.5975 1.0125 ;
      RECT 0.9175 0.8075 0.9825 0.8725 ;
      RECT 1.5825 0.3875 1.6475 0.4525 ;
      RECT 1.5825 0.9475 1.6475 1.0125 ;
      RECT 2.2475 0.3175 2.3125 0.3825 ;
      RECT 2.7225 1.0875 2.7875 1.1525 ;
      RECT 2.1525 0.1775 2.2175 0.2425 ;
      RECT 2.7225 0.1775 2.7875 0.2425 ;
      RECT 0.0625 0.5275 0.1275 0.5925 ;
      RECT 0.6325 0.4575 0.6975 0.5225 ;
      RECT 0.6325 0.9475 0.6975 1.0125 ;
    LAYER metal2 ;
      RECT 2.9100 0.6650 2.9800 1.1550 ;
      RECT 2.5300 0.2450 2.6000 1.0150 ;
      RECT 2.2450 0.5250 2.6000 0.5950 ;
      RECT 1.5800 0.3850 1.6500 1.0150 ;
      RECT 0.9150 0.8050 1.6500 0.8750 ;
      RECT 2.0550 0.3150 2.1250 1.1550 ;
      RECT 2.3400 0.2450 2.4100 0.3850 ;
      RECT 2.0550 0.3150 2.4100 0.3850 ;
      RECT 2.0550 1.0850 2.7900 1.1550 ;
      RECT 2.1500 0.1050 2.2200 0.2450 ;
      RECT 2.7200 0.1050 2.7900 0.2450 ;
      RECT 2.1500 0.1050 2.7900 0.1750 ;
      RECT 0.6300 0.4550 0.7000 1.0150 ;
      RECT 0.0600 0.5250 0.7000 0.5950 ;
  END
END CLKGATE_X2

MACRO CLKGATE_X4
  CLASS CORE ;
  ORIGIN 0 0 ;
  FOREIGN CLKGATE_X4 0 0 ;
  SIZE 4.56 BY 1.40 ;
  SYMMETRY X Y ;
  SITE core ;
  PIN CK
    DIRECTION INPUT ;
    USE CLOCK ;
    PORT
      LAYER metal1 ;
        RECT 0.4400 0.1750 0.5100 0.3850 ;
        RECT 0.4400 0.3150 0.7000 0.3850 ;
        RECT 2.0550 0.3850 2.3150 0.4550 ;
        RECT 0.8200 0.5950 1.0800 0.6650 ;
      LAYER via1 ;
        RECT 0.6325 0.3175 0.6975 0.3825 ;
        RECT 0.8225 0.5975 0.8875 0.6625 ;
        RECT 2.0575 0.3875 2.1225 0.4525 ;
      LAYER metal2 ;
        RECT 0.6300 0.1050 0.7000 0.6650 ;
        RECT 1.7700 0.1050 1.8400 0.3850 ;
        RECT 1.9600 0.3150 2.0300 0.4550 ;
        RECT 0.6300 0.1050 1.8400 0.1750 ;
        RECT 1.7700 0.3150 2.0300 0.3850 ;
        RECT 1.9600 0.3850 2.2200 0.4550 ;
        RECT 0.6300 0.5950 0.9850 0.6650 ;
    END
  END CK
  PIN E
    DIRECTION INPUT ;
    USE SIGNAL ;
    PORT
      LAYER metal1 ;
        RECT 1.9600 0.5950 2.0300 0.8050 ;
        RECT 1.4850 0.7350 2.1250 0.8050 ;
    END
  END E
  PIN SE
    DIRECTION INPUT ;
    USE SIGNAL ;
    PORT
      LAYER metal1 ;
        RECT 1.5800 0.3150 1.6500 0.5250 ;
    END
  END SE
  PIN GCK
    DIRECTION OUTPUT ;
    USE SIGNAL ;
    PORT
      LAYER metal1 ;
        RECT 0.0600 0.8750 0.1300 1.0850 ;
        RECT 0.3450 0.4550 0.4150 0.9450 ;
        RECT 0.3450 0.4550 0.5100 0.5250 ;
        RECT 0.0600 0.8750 0.5100 0.9450 ;
    END
  END GCK
  PIN VDD
    DIRECTION INOUT ;
    USE POWER ;
    SHAPE ABUTMENT ;
    PORT
      LAYER metal1 ;
        RECT 0.0000 1.3150 4.5600 1.4850 ;
        RECT 0.2500 1.1550 0.3200 1.3650 ;
        RECT 0.6300 1.1550 0.7000 1.3650 ;
        RECT 1.2000 1.1550 1.2700 1.3650 ;
        RECT 2.1500 1.1550 2.2200 1.3650 ;
        RECT 2.9100 1.1550 2.9800 1.3650 ;
        RECT 4.4300 1.1550 4.5000 1.3650 ;
        RECT 1.2000 1.1550 1.4600 1.2250 ;
    END
  END VDD
  PIN VSS
    DIRECTION INOUT ;
    USE GROUND ;
    SHAPE ABUTMENT ;
    PORT
      LAYER metal1 ;
        RECT 0.0000 -0.0850 4.5600 0.0850 ;
        RECT 0.2500 0.0350 0.3200 0.2450 ;
        RECT 0.6300 0.0350 0.7000 0.2450 ;
        RECT 1.3900 0.0350 1.4600 0.2450 ;
        RECT 2.1500 0.0350 2.2200 0.2450 ;
        RECT 2.9100 0.0350 2.9800 0.2450 ;
        RECT 4.4300 0.0350 4.5000 0.2450 ;
        RECT 1.3900 0.1750 1.6500 0.2450 ;
    END
  END VSS
  OBS
    LAYER metal1 ;
      RECT 2.5300 0.2450 2.6000 0.8050 ;
      RECT 3.4800 0.6650 3.5500 0.8050 ;
      RECT 2.3400 0.2450 2.6000 0.3150 ;
      RECT 3.4800 0.6650 4.3100 0.7350 ;
      RECT 2.3400 1.0150 2.6000 1.0850 ;
      RECT 0.8200 0.1750 1.2700 0.2450 ;
      RECT 4.1450 0.2450 4.2150 0.5950 ;
      RECT 4.2400 0.8750 4.3100 1.0850 ;
      RECT 4.4300 0.5250 4.5000 0.9450 ;
      RECT 4.1450 0.2450 4.3100 0.3150 ;
      RECT 3.8600 0.5250 4.5000 0.5950 ;
      RECT 4.2400 0.8750 4.5000 0.9450 ;
      RECT 2.7200 0.5950 2.7900 0.7350 ;
      RECT 3.6700 0.2450 3.7400 0.3850 ;
      RECT 3.6700 1.0150 3.7400 1.2250 ;
      RECT 3.6700 0.3150 3.8350 0.3850 ;
      RECT 2.7200 0.5950 2.8850 0.6650 ;
      RECT 1.2000 0.6650 1.2700 0.9450 ;
      RECT 2.7200 0.2450 2.7900 0.4550 ;
      RECT 2.7200 0.8750 2.7900 1.0850 ;
      RECT 2.9100 0.3850 2.9800 0.5250 ;
      RECT 3.0050 0.4550 3.0750 0.9450 ;
      RECT 2.7200 0.3850 2.9800 0.4550 ;
      RECT 2.9100 0.4550 3.0750 0.5250 ;
      RECT 1.2000 0.6650 1.3650 0.7350 ;
      RECT 0.7250 0.7350 1.2700 0.8050 ;
      RECT 1.2000 0.8750 3.0750 0.9450 ;
      RECT 1.7700 0.1750 1.8400 0.5250 ;
      RECT 3.2900 0.1750 3.3600 0.9450 ;
      RECT 3.8600 0.8750 3.9300 1.0850 ;
      RECT 1.7700 0.1750 2.0300 0.2450 ;
      RECT 3.2900 0.1750 3.5500 0.2450 ;
      RECT 3.2900 0.8750 3.9300 0.9450 ;
      RECT 1.6750 1.0150 1.9350 1.0850 ;
      RECT 1.5800 1.1550 2.0300 1.2250 ;
      RECT 3.1000 0.1750 3.1700 0.3850 ;
      RECT 3.9550 0.1750 4.0250 0.3150 ;
      RECT 3.8600 0.1750 4.0250 0.2450 ;
      RECT 3.1000 1.0150 3.5500 1.0850 ;
      RECT 0.5350 0.5950 0.6050 0.8050 ;
      RECT 0.6300 0.4550 0.7000 0.6650 ;
      RECT 1.0100 0.3150 1.0800 0.5250 ;
      RECT 0.6300 0.4550 1.0800 0.5250 ;
      RECT 0.5350 0.5950 0.7000 0.6650 ;
      RECT 0.8200 0.8750 1.0800 0.9450 ;
    LAYER via1 ;
      RECT 2.5325 0.7375 2.5975 0.8025 ;
      RECT 2.5325 1.0175 2.5975 1.0825 ;
      RECT 3.4825 0.7375 3.5475 0.8025 ;
      RECT 2.8175 0.5975 2.8825 0.6625 ;
      RECT 3.6725 0.3175 3.7375 0.3825 ;
      RECT 3.6725 1.0175 3.7375 1.0825 ;
      RECT 1.7725 0.4575 1.8375 0.5225 ;
      RECT 1.7725 1.0175 1.8375 1.0825 ;
      RECT 1.9625 0.1775 2.0275 0.2425 ;
      RECT 3.2925 0.1775 3.3575 0.2425 ;
      RECT 3.1025 0.3175 3.1675 0.3825 ;
      RECT 3.8625 0.1775 3.9275 0.2425 ;
      RECT 0.5375 0.7375 0.6025 0.8025 ;
      RECT 0.8225 0.8775 0.8875 0.9425 ;
    LAYER metal2 ;
      RECT 2.5300 0.7350 2.6000 1.0850 ;
      RECT 2.5300 0.7350 3.5500 0.8050 ;
      RECT 3.6700 0.3150 3.7400 1.0850 ;
      RECT 2.8150 0.5950 3.7400 0.6650 ;
      RECT 1.7700 0.4550 1.8400 1.0850 ;
      RECT 1.9600 0.1750 3.3600 0.2450 ;
      RECT 3.4800 0.1750 3.5500 0.3850 ;
      RECT 3.4800 0.1750 3.9300 0.2450 ;
      RECT 3.1000 0.3150 3.5500 0.3850 ;
      RECT 0.5350 0.7350 0.6050 0.9450 ;
      RECT 0.5350 0.8750 0.8900 0.9450 ;
  END
END CLKGATE_X4

MACRO TIE0
  CLASS CORE ;
  ORIGIN 0 0 ;
  FOREIGN TIE0 0 0 ;
  SIZE 0.38 BY 1.40 ;
  SYMMETRY X Y ;
  SITE core ;
  PIN Y
    DIRECTION OUTPUT ;
    USE SIGNAL ;
    PORT
      LAYER metal1 ;
        RECT 0.0600 0.1750 0.1300 0.3850 ;
    END
  END Y
  PIN VDD
    DIRECTION INOUT ;
    USE POWER ;
    SHAPE ABUTMENT ;
    PORT
      LAYER metal1 ;
        RECT 0.0000 1.3150 0.3800 1.4850 ;
        RECT 0.2500 1.1550 0.3200 1.3650 ;
    END
  END VDD
  PIN VSS
    DIRECTION INOUT ;
    USE GROUND ;
    SHAPE ABUTMENT ;
    PORT
      LAYER metal1 ;
        RECT 0.0000 -0.0850 0.3800 0.0850 ;
        RECT 0.2500 0.0350 0.3200 0.2450 ;
    END
  END VSS
  OBS
    LAYER metal1 ;
      RECT 0.0600 0.8050 0.1300 1.0850 ;
      RECT 0.0600 0.8050 0.2250 0.8750 ;
  END
END TIE0

MACRO TIE1
  CLASS CORE ;
  ORIGIN 0 0 ;
  FOREIGN TIE1 0 0 ;
  SIZE 0.38 BY 1.40 ;
  SYMMETRY X Y ;
  SITE core ;
  PIN Y
    DIRECTION OUTPUT ;
    USE SIGNAL ;
    PORT
      LAYER metal1 ;
        RECT 0.0600 0.9450 0.1300 1.1550 ;
    END
  END Y
  PIN VDD
    DIRECTION INOUT ;
    USE POWER ;
    SHAPE ABUTMENT ;
    PORT
      LAYER metal1 ;
        RECT 0.0000 1.3150 0.3800 1.4850 ;
        RECT 0.2500 1.1550 0.3200 1.3650 ;
    END
  END VDD
  PIN VSS
    DIRECTION INOUT ;
    USE GROUND ;
    SHAPE ABUTMENT ;
    PORT
      LAYER metal1 ;
        RECT 0.0000 -0.0850 0.3800 0.0850 ;
        RECT 0.2500 0.0350 0.3200 0.2450 ;
    END
  END VSS
  OBS
    LAYER metal1 ;
      RECT 0.0600 0.2450 0.1300 0.4550 ;
  END
END TIE1

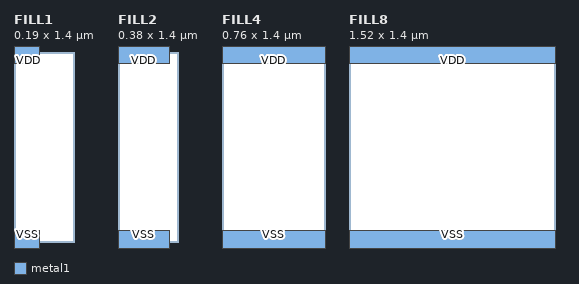
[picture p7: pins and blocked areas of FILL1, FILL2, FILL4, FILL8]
MACRO FILL1
  CLASS CORE SPACER ;
  ORIGIN 0 0 ;
  FOREIGN FILL1 0 0 ;
  SIZE 0.19 BY 1.40 ;
  SYMMETRY X Y ;
  SITE core ;
  PIN VDD
    DIRECTION INOUT ;
    USE POWER ;
    SHAPE ABUTMENT ;
    PORT
      LAYER metal1 ;
        RECT 0.0000 1.3150 0.1900 1.4850 ;
    END
  END VDD
  PIN VSS
    DIRECTION INOUT ;
    USE GROUND ;
    SHAPE ABUTMENT ;
    PORT
      LAYER metal1 ;
        RECT 0.0000 -0.0850 0.1900 0.0850 ;
    END
  END VSS
END FILL1

MACRO FILL2
  CLASS CORE SPACER ;
  ORIGIN 0 0 ;
  FOREIGN FILL2 0 0 ;
  SIZE 0.38 BY 1.40 ;
  SYMMETRY X Y ;
  SITE core ;
  PIN VDD
    DIRECTION INOUT ;
    USE POWER ;
    SHAPE ABUTMENT ;
    PORT
      LAYER metal1 ;
        RECT 0.0000 1.3150 0.3800 1.4850 ;
    END
  END VDD
  PIN VSS
    DIRECTION INOUT ;
    USE GROUND ;
    SHAPE ABUTMENT ;
    PORT
      LAYER metal1 ;
        RECT 0.0000 -0.0850 0.3800 0.0850 ;
    END
  END VSS
END FILL2

MACRO FILL4
  CLASS CORE SPACER ;
  ORIGIN 0 0 ;
  FOREIGN FILL4 0 0 ;
  SIZE 0.76 BY 1.40 ;
  SYMMETRY X Y ;
  SITE core ;
  PIN VDD
    DIRECTION INOUT ;
    USE POWER ;
    SHAPE ABUTMENT ;
    PORT
      LAYER metal1 ;
        RECT 0.0000 1.3150 0.7600 1.4850 ;
    END
  END VDD
  PIN VSS
    DIRECTION INOUT ;
    USE GROUND ;
    SHAPE ABUTMENT ;
    PORT
      LAYER metal1 ;
        RECT 0.0000 -0.0850 0.7600 0.0850 ;
    END
  END VSS
END FILL4

MACRO FILL8
  CLASS CORE SPACER ;
  ORIGIN 0 0 ;
  FOREIGN FILL8 0 0 ;
  SIZE 1.52 BY 1.40 ;
  SYMMETRY X Y ;
  SITE core ;
  PIN VDD
    DIRECTION INOUT ;
    USE POWER ;
    SHAPE ABUTMENT ;
    PORT
      LAYER metal1 ;
        RECT 0.0000 1.3150 1.5200 1.4850 ;
    END
  END VDD
  PIN VSS
    DIRECTION INOUT ;
    USE GROUND ;
    SHAPE ABUTMENT ;
    PORT
      LAYER metal1 ;
        RECT 0.0000 -0.0850 1.5200 0.0850 ;
    END
  END VSS
END FILL8

END LIBRARY
